VERSION 5.8 ;
BUSBITCHARS "[]" ;
DIVIDERCHAR "/" ;
UNITS
    DATABASE MICRONS 1000 ;
END UNITS

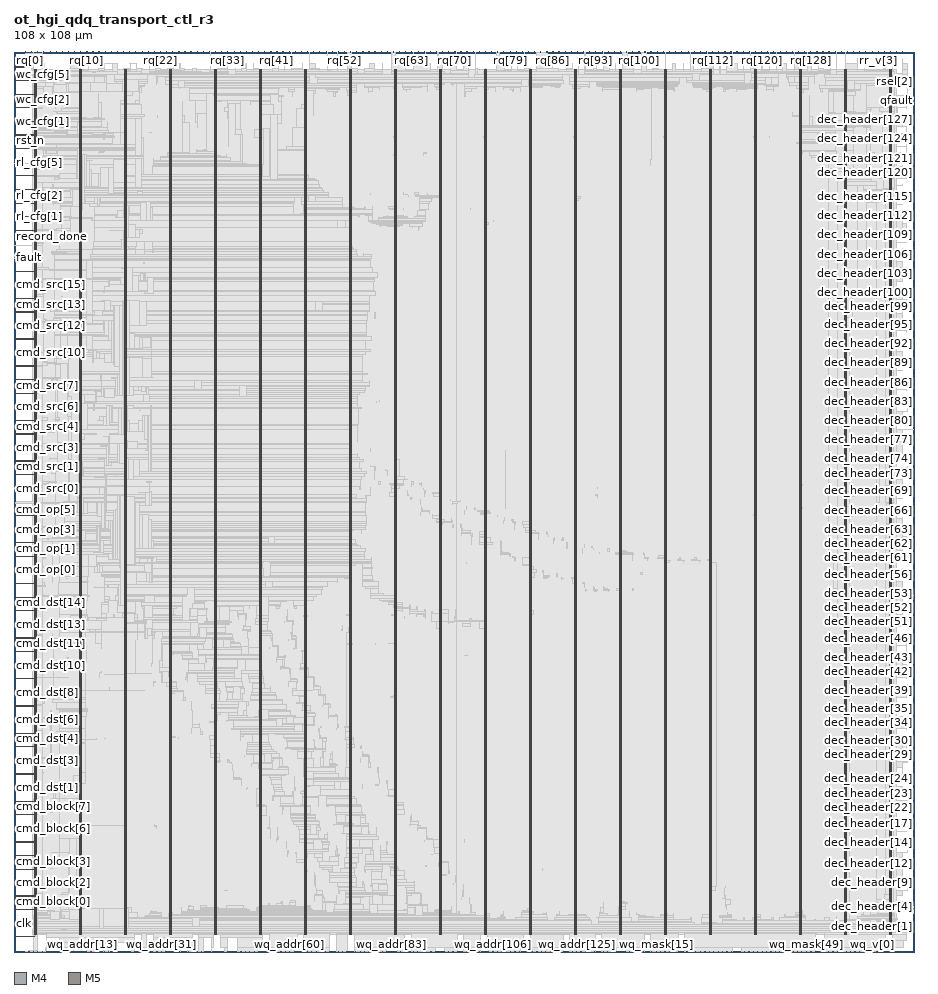
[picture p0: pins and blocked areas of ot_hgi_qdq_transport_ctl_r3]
MACRO ot_hgi_qdq_transport_ctl_r3
  FOREIGN ot_hgi_qdq_transport_ctl_r3 0 0 ;
  CLASS BLOCK ;
  SIZE 108 BY 108 ;
  PIN beat_done
    DIRECTION OUTPUT ;
    USE SIGNAL ;
    PORT
      LAYER M4 ;
        RECT  0 1.824 0.084 1.848 ;
    END
    PORT
      LAYER M4 ;
        RECT  0.06 1.824 2.408 1.848 ;
    END
  END beat_done
  PIN clk
    DIRECTION INPUT ;
    USE SIGNAL ;
    PORT
      LAYER M4 ;
        RECT  0 3.456 0.084 3.48 ;
    END
    PORT
      LAYER M4 ;
        RECT  0.06 3.456 0.227 3.48 ;
    END
  END clk
  PIN cmd_block[0]
    DIRECTION INPUT ;
    USE SIGNAL ;
    PORT
      LAYER M4 ;
        RECT  0 5.088 0.084 5.112 ;
    END
    PORT
      LAYER M4 ;
        RECT  0.06 5.088 2.408 5.112 ;
    END
  END cmd_block[0]
  PIN cmd_block[1]
    DIRECTION INPUT ;
    USE SIGNAL ;
    PORT
      LAYER M4 ;
        RECT  0 6.72 0.084 6.744 ;
    END
    PORT
      LAYER M4 ;
        RECT  0.06 6.72 2.408 6.744 ;
    END
  END cmd_block[1]
  PIN cmd_block[2]
    DIRECTION INPUT ;
    USE SIGNAL ;
    PORT
      LAYER M4 ;
        RECT  0 8.304 0.084 8.328 ;
    END
    PORT
      LAYER M4 ;
        RECT  0.06 8.304 2.408 8.328 ;
    END
  END cmd_block[2]
  PIN cmd_block[3]
    DIRECTION INPUT ;
    USE SIGNAL ;
    PORT
      LAYER M4 ;
        RECT  0 9.936 0.084 9.96 ;
    END
    PORT
      LAYER M4 ;
        RECT  0.06 9.936 2.408 9.96 ;
    END
  END cmd_block[3]
  PIN cmd_block[4]
    DIRECTION INPUT ;
    USE SIGNAL ;
    PORT
      LAYER M4 ;
        RECT  0 11.568 0.084 11.592 ;
    END
    PORT
      LAYER M4 ;
        RECT  0.06 11.568 2.408 11.592 ;
    END
  END cmd_block[4]
  PIN cmd_block[5]
    DIRECTION INPUT ;
    USE SIGNAL ;
    PORT
      LAYER M4 ;
        RECT  0 13.2 0.084 13.224 ;
    END
    PORT
      LAYER M4 ;
        RECT  0.06 13.2 2.408 13.224 ;
    END
  END cmd_block[5]
  PIN cmd_block[6]
    DIRECTION INPUT ;
    USE SIGNAL ;
    PORT
      LAYER M4 ;
        RECT  0 14.832 0.084 14.856 ;
    END
    PORT
      LAYER M4 ;
        RECT  0.06 14.832 2.408 14.856 ;
    END
  END cmd_block[6]
  PIN cmd_block[7]
    DIRECTION INPUT ;
    USE SIGNAL ;
    PORT
      LAYER M4 ;
        RECT  0 16.464 0.084 16.488 ;
    END
    PORT
      LAYER M4 ;
        RECT  0.06 16.464 2.408 16.488 ;
    END
  END cmd_block[7]
  PIN cmd_dst[0]
    DIRECTION INPUT ;
    USE SIGNAL ;
    PORT
      LAYER M4 ;
        RECT  0 18.096 0.084 18.12 ;
    END
    PORT
      LAYER M4 ;
        RECT  0.06 18.096 2.408 18.12 ;
    END
  END cmd_dst[0]
  PIN cmd_dst[10]
    DIRECTION INPUT ;
    USE SIGNAL ;
    PORT
      LAYER M4 ;
        RECT  0 34.416 0.084 34.44 ;
    END
    PORT
      LAYER M4 ;
        RECT  0.06 34.416 2.408 34.44 ;
    END
  END cmd_dst[10]
  PIN cmd_dst[11]
    DIRECTION INPUT ;
    USE SIGNAL ;
    PORT
      LAYER M4 ;
        RECT  0 36.048 0.084 36.072 ;
    END
    PORT
      LAYER M4 ;
        RECT  0.06 36.048 2.408 36.072 ;
    END
  END cmd_dst[11]
  PIN cmd_dst[12]
    DIRECTION INPUT ;
    USE SIGNAL ;
    PORT
      LAYER M4 ;
        RECT  0 37.68 0.084 37.704 ;
    END
    PORT
      LAYER M4 ;
        RECT  0.06 37.68 2.408 37.704 ;
    END
  END cmd_dst[12]
  PIN cmd_dst[13]
    DIRECTION INPUT ;
    USE SIGNAL ;
    PORT
      LAYER M4 ;
        RECT  0 39.312 0.084 39.336 ;
    END
    PORT
      LAYER M4 ;
        RECT  0.06 39.312 2.408 39.336 ;
    END
  END cmd_dst[13]
  PIN cmd_dst[14]
    DIRECTION INPUT ;
    USE SIGNAL ;
    PORT
      LAYER M4 ;
        RECT  0 40.944 0.084 40.968 ;
    END
    PORT
      LAYER M4 ;
        RECT  0.06 40.944 2.408 40.968 ;
    END
  END cmd_dst[14]
  PIN cmd_dst[15]
    DIRECTION INPUT ;
    USE SIGNAL ;
    PORT
      LAYER M4 ;
        RECT  0 42.576 0.084 42.6 ;
    END
    PORT
      LAYER M4 ;
        RECT  0.06 42.576 2.408 42.6 ;
    END
  END cmd_dst[15]
  PIN cmd_dst[1]
    DIRECTION INPUT ;
    USE SIGNAL ;
    PORT
      LAYER M4 ;
        RECT  0 19.728 0.084 19.752 ;
    END
    PORT
      LAYER M4 ;
        RECT  0.06 19.728 2.408 19.752 ;
    END
  END cmd_dst[1]
  PIN cmd_dst[2]
    DIRECTION INPUT ;
    USE SIGNAL ;
    PORT
      LAYER M4 ;
        RECT  0 21.36 0.084 21.384 ;
    END
    PORT
      LAYER M4 ;
        RECT  0.06 21.36 2.408 21.384 ;
    END
  END cmd_dst[2]
  PIN cmd_dst[3]
    DIRECTION INPUT ;
    USE SIGNAL ;
    PORT
      LAYER M4 ;
        RECT  0 22.992 0.084 23.016 ;
    END
    PORT
      LAYER M4 ;
        RECT  0.06 22.992 2.408 23.016 ;
    END
  END cmd_dst[3]
  PIN cmd_dst[4]
    DIRECTION INPUT ;
    USE SIGNAL ;
    PORT
      LAYER M4 ;
        RECT  0 24.624 0.084 24.648 ;
    END
    PORT
      LAYER M4 ;
        RECT  0.06 24.624 2.408 24.648 ;
    END
  END cmd_dst[4]
  PIN cmd_dst[5]
    DIRECTION INPUT ;
    USE SIGNAL ;
    PORT
      LAYER M4 ;
        RECT  0 26.256 0.084 26.28 ;
    END
    PORT
      LAYER M4 ;
        RECT  0.06 26.256 2.408 26.28 ;
    END
  END cmd_dst[5]
  PIN cmd_dst[6]
    DIRECTION INPUT ;
    USE SIGNAL ;
    PORT
      LAYER M4 ;
        RECT  0 27.888 0.084 27.912 ;
    END
    PORT
      LAYER M4 ;
        RECT  0.06 27.888 2.408 27.912 ;
    END
  END cmd_dst[6]
  PIN cmd_dst[7]
    DIRECTION INPUT ;
    USE SIGNAL ;
    PORT
      LAYER M4 ;
        RECT  0 29.52 0.084 29.544 ;
    END
    PORT
      LAYER M4 ;
        RECT  0.06 29.52 2.408 29.544 ;
    END
  END cmd_dst[7]
  PIN cmd_dst[8]
    DIRECTION INPUT ;
    USE SIGNAL ;
    PORT
      LAYER M4 ;
        RECT  0 31.152 0.084 31.176 ;
    END
    PORT
      LAYER M4 ;
        RECT  0.06 31.152 2.408 31.176 ;
    END
  END cmd_dst[8]
  PIN cmd_dst[9]
    DIRECTION INPUT ;
    USE SIGNAL ;
    PORT
      LAYER M4 ;
        RECT  0 32.784 0.084 32.808 ;
    END
    PORT
      LAYER M4 ;
        RECT  0.06 32.784 2.408 32.808 ;
    END
  END cmd_dst[9]
  PIN cmd_last
    DIRECTION INPUT ;
    USE SIGNAL ;
    PORT
      LAYER M4 ;
        RECT  0 44.208 0.084 44.232 ;
    END
    PORT
      LAYER M4 ;
        RECT  0.06 44.208 2.408 44.232 ;
    END
  END cmd_last
  PIN cmd_op[0]
    DIRECTION INPUT ;
    USE SIGNAL ;
    PORT
      LAYER M4 ;
        RECT  0 45.84 0.084 45.864 ;
    END
    PORT
      LAYER M4 ;
        RECT  0.06 45.84 2.408 45.864 ;
    END
  END cmd_op[0]
  PIN cmd_op[1]
    DIRECTION INPUT ;
    USE SIGNAL ;
    PORT
      LAYER M4 ;
        RECT  0 47.472 0.084 47.496 ;
    END
    PORT
      LAYER M4 ;
        RECT  0.06 47.472 2.408 47.496 ;
    END
  END cmd_op[1]
  PIN cmd_op[2]
    DIRECTION INPUT ;
    USE SIGNAL ;
    PORT
      LAYER M4 ;
        RECT  0 49.104 0.084 49.128 ;
    END
    PORT
      LAYER M4 ;
        RECT  0.06 49.104 2.408 49.128 ;
    END
  END cmd_op[2]
  PIN cmd_op[3]
    DIRECTION INPUT ;
    USE SIGNAL ;
    PORT
      LAYER M4 ;
        RECT  0 50.736 0.084 50.76 ;
    END
    PORT
      LAYER M4 ;
        RECT  0.06 50.736 2.408 50.76 ;
    END
  END cmd_op[3]
  PIN cmd_op[4]
    DIRECTION INPUT ;
    USE SIGNAL ;
    PORT
      LAYER M4 ;
        RECT  0 52.368 0.084 52.392 ;
    END
    PORT
      LAYER M4 ;
        RECT  0.06 52.368 2.408 52.392 ;
    END
  END cmd_op[4]
  PIN cmd_op[5]
    DIRECTION INPUT ;
    USE SIGNAL ;
    PORT
      LAYER M4 ;
        RECT  0 54 0.084 54.024 ;
    END
    PORT
      LAYER M4 ;
        RECT  0.06 54 0.181 54.024 ;
    END
  END cmd_op[5]
  PIN cmd_src[0]
    DIRECTION INPUT ;
    USE SIGNAL ;
    PORT
      LAYER M4 ;
        RECT  0 55.632 0.084 55.656 ;
    END
    PORT
      LAYER M4 ;
        RECT  0.06 55.632 0.097 55.656 ;
    END
  END cmd_src[0]
  PIN cmd_src[10]
    DIRECTION INPUT ;
    USE SIGNAL ;
    PORT
      LAYER M4 ;
        RECT  0 71.904 0.084 71.928 ;
    END
    PORT
      LAYER M4 ;
        RECT  0.06 71.904 2.408 71.928 ;
    END
  END cmd_src[10]
  PIN cmd_src[11]
    DIRECTION INPUT ;
    USE SIGNAL ;
    PORT
      LAYER M4 ;
        RECT  0 73.536 0.084 73.56 ;
    END
    PORT
      LAYER M4 ;
        RECT  0.06 73.536 2.408 73.56 ;
    END
  END cmd_src[11]
  PIN cmd_src[12]
    DIRECTION INPUT ;
    USE SIGNAL ;
    PORT
      LAYER M4 ;
        RECT  0 75.168 0.084 75.192 ;
    END
    PORT
      LAYER M4 ;
        RECT  0.06 75.168 2.408 75.192 ;
    END
  END cmd_src[12]
  PIN cmd_src[13]
    DIRECTION INPUT ;
    USE SIGNAL ;
    PORT
      LAYER M4 ;
        RECT  0 76.8 0.084 76.824 ;
    END
    PORT
      LAYER M4 ;
        RECT  0.06 76.8 2.408 76.824 ;
    END
  END cmd_src[13]
  PIN cmd_src[14]
    DIRECTION INPUT ;
    USE SIGNAL ;
    PORT
      LAYER M4 ;
        RECT  0 78.432 0.084 78.456 ;
    END
    PORT
      LAYER M4 ;
        RECT  0.06 78.432 2.408 78.456 ;
    END
  END cmd_src[14]
  PIN cmd_src[15]
    DIRECTION INPUT ;
    USE SIGNAL ;
    PORT
      LAYER M4 ;
        RECT  0 80.064 0.084 80.088 ;
    END
    PORT
      LAYER M4 ;
        RECT  0.06 80.064 2.408 80.088 ;
    END
  END cmd_src[15]
  PIN cmd_src[1]
    DIRECTION INPUT ;
    USE SIGNAL ;
    PORT
      LAYER M4 ;
        RECT  0 57.264 0.084 57.288 ;
    END
    PORT
      LAYER M4 ;
        RECT  0.06 57.264 2.408 57.288 ;
    END
  END cmd_src[1]
  PIN cmd_src[2]
    DIRECTION INPUT ;
    USE SIGNAL ;
    PORT
      LAYER M4 ;
        RECT  0 58.896 0.084 58.92 ;
    END
    PORT
      LAYER M4 ;
        RECT  0.06 58.896 2.408 58.92 ;
    END
  END cmd_src[2]
  PIN cmd_src[3]
    DIRECTION INPUT ;
    USE SIGNAL ;
    PORT
      LAYER M4 ;
        RECT  0 60.528 0.084 60.552 ;
    END
    PORT
      LAYER M4 ;
        RECT  0.06 60.528 2.408 60.552 ;
    END
  END cmd_src[3]
  PIN cmd_src[4]
    DIRECTION INPUT ;
    USE SIGNAL ;
    PORT
      LAYER M4 ;
        RECT  0 62.16 0.084 62.184 ;
    END
    PORT
      LAYER M4 ;
        RECT  0.06 62.16 2.408 62.184 ;
    END
  END cmd_src[4]
  PIN cmd_src[5]
    DIRECTION INPUT ;
    USE SIGNAL ;
    PORT
      LAYER M4 ;
        RECT  0 63.792 0.084 63.816 ;
    END
    PORT
      LAYER M4 ;
        RECT  0.06 63.792 2.408 63.816 ;
    END
  END cmd_src[5]
  PIN cmd_src[6]
    DIRECTION INPUT ;
    USE SIGNAL ;
    PORT
      LAYER M4 ;
        RECT  0 65.424 0.084 65.448 ;
    END
    PORT
      LAYER M4 ;
        RECT  0.06 65.424 2.408 65.448 ;
    END
  END cmd_src[6]
  PIN cmd_src[7]
    DIRECTION INPUT ;
    USE SIGNAL ;
    PORT
      LAYER M4 ;
        RECT  0 67.056 0.084 67.08 ;
    END
    PORT
      LAYER M4 ;
        RECT  0.06 67.056 2.408 67.08 ;
    END
  END cmd_src[7]
  PIN cmd_src[8]
    DIRECTION INPUT ;
    USE SIGNAL ;
    PORT
      LAYER M4 ;
        RECT  0 68.688 0.084 68.712 ;
    END
    PORT
      LAYER M4 ;
        RECT  0.06 68.688 2.408 68.712 ;
    END
  END cmd_src[8]
  PIN cmd_src[9]
    DIRECTION INPUT ;
    USE SIGNAL ;
    PORT
      LAYER M4 ;
        RECT  0 70.32 0.084 70.344 ;
    END
    PORT
      LAYER M4 ;
        RECT  0.06 70.32 2.408 70.344 ;
    END
  END cmd_src[9]
  PIN cmd_v
    DIRECTION INPUT ;
    USE SIGNAL ;
    PORT
      LAYER M4 ;
        RECT  0 81.696 0.084 81.72 ;
    END
    PORT
      LAYER M4 ;
        RECT  0.06 81.696 2.408 81.72 ;
    END
  END cmd_v
  PIN dec_header[0]
    DIRECTION OUTPUT ;
    USE SIGNAL ;
    PORT
      LAYER M4 ;
        RECT  107.916 1.392 108 1.416 ;
    END
  END dec_header[0]
  PIN dec_header[100]
    DIRECTION OUTPUT ;
    USE SIGNAL ;
    PORT
      LAYER M4 ;
        RECT  107.916 78.192 108 78.216 ;
    END
  END dec_header[100]
  PIN dec_header[101]
    DIRECTION OUTPUT ;
    USE SIGNAL ;
    PORT
      LAYER M4 ;
        RECT  107.916 78.96 108 78.984 ;
    END
  END dec_header[101]
  PIN dec_header[102]
    DIRECTION OUTPUT ;
    USE SIGNAL ;
    PORT
      LAYER M4 ;
        RECT  107.916 79.728 108 79.752 ;
    END
  END dec_header[102]
  PIN dec_header[103]
    DIRECTION OUTPUT ;
    USE SIGNAL ;
    PORT
      LAYER M4 ;
        RECT  107.916 80.496 108 80.52 ;
    END
  END dec_header[103]
  PIN dec_header[104]
    DIRECTION OUTPUT ;
    USE SIGNAL ;
    PORT
      LAYER M4 ;
        RECT  107.916 81.264 108 81.288 ;
    END
  END dec_header[104]
  PIN dec_header[105]
    DIRECTION OUTPUT ;
    USE SIGNAL ;
    PORT
      LAYER M4 ;
        RECT  107.916 82.032 108 82.056 ;
    END
  END dec_header[105]
  PIN dec_header[106]
    DIRECTION OUTPUT ;
    USE SIGNAL ;
    PORT
      LAYER M4 ;
        RECT  107.916 82.8 108 82.824 ;
    END
  END dec_header[106]
  PIN dec_header[107]
    DIRECTION OUTPUT ;
    USE SIGNAL ;
    PORT
      LAYER M4 ;
        RECT  107.916 83.568 108 83.592 ;
    END
  END dec_header[107]
  PIN dec_header[108]
    DIRECTION OUTPUT ;
    USE SIGNAL ;
    PORT
      LAYER M4 ;
        RECT  107.916 84.336 108 84.36 ;
    END
  END dec_header[108]
  PIN dec_header[109]
    DIRECTION OUTPUT ;
    USE SIGNAL ;
    PORT
      LAYER M4 ;
        RECT  107.916 85.104 108 85.128 ;
    END
  END dec_header[109]
  PIN dec_header[10]
    DIRECTION OUTPUT ;
    USE SIGNAL ;
    PORT
      LAYER M4 ;
        RECT  107.916 9.072 108 9.096 ;
    END
  END dec_header[10]
  PIN dec_header[110]
    DIRECTION OUTPUT ;
    USE SIGNAL ;
    PORT
      LAYER M4 ;
        RECT  107.916 85.872 108 85.896 ;
    END
  END dec_header[110]
  PIN dec_header[111]
    DIRECTION OUTPUT ;
    USE SIGNAL ;
    PORT
      LAYER M4 ;
        RECT  107.916 86.64 108 86.664 ;
    END
  END dec_header[111]
  PIN dec_header[112]
    DIRECTION OUTPUT ;
    USE SIGNAL ;
    PORT
      LAYER M4 ;
        RECT  107.916 87.408 108 87.432 ;
    END
  END dec_header[112]
  PIN dec_header[113]
    DIRECTION OUTPUT ;
    USE SIGNAL ;
    PORT
      LAYER M4 ;
        RECT  107.916 88.176 108 88.2 ;
    END
  END dec_header[113]
  PIN dec_header[114]
    DIRECTION OUTPUT ;
    USE SIGNAL ;
    PORT
      LAYER M4 ;
        RECT  107.916 88.944 108 88.968 ;
    END
  END dec_header[114]
  PIN dec_header[115]
    DIRECTION OUTPUT ;
    USE SIGNAL ;
    PORT
      LAYER M4 ;
        RECT  107.916 89.712 108 89.736 ;
    END
  END dec_header[115]
  PIN dec_header[116]
    DIRECTION OUTPUT ;
    USE SIGNAL ;
    PORT
      LAYER M4 ;
        RECT  107.916 90.48 108 90.504 ;
    END
  END dec_header[116]
  PIN dec_header[117]
    DIRECTION OUTPUT ;
    USE SIGNAL ;
    PORT
      LAYER M4 ;
        RECT  107.916 91.248 108 91.272 ;
    END
  END dec_header[117]
  PIN dec_header[118]
    DIRECTION OUTPUT ;
    USE SIGNAL ;
    PORT
      LAYER M4 ;
        RECT  107.916 92.016 108 92.04 ;
    END
  END dec_header[118]
  PIN dec_header[119]
    DIRECTION OUTPUT ;
    USE SIGNAL ;
    PORT
      LAYER M4 ;
        RECT  107.916 92.784 108 92.808 ;
    END
  END dec_header[119]
  PIN dec_header[11]
    DIRECTION OUTPUT ;
    USE SIGNAL ;
    PORT
      LAYER M4 ;
        RECT  107.916 9.84 108 9.864 ;
    END
  END dec_header[11]
  PIN dec_header[120]
    DIRECTION OUTPUT ;
    USE SIGNAL ;
    PORT
      LAYER M4 ;
        RECT  107.916 93.552 108 93.576 ;
    END
  END dec_header[120]
  PIN dec_header[121]
    DIRECTION OUTPUT ;
    USE SIGNAL ;
    PORT
      LAYER M4 ;
        RECT  107.916 94.32 108 94.344 ;
    END
  END dec_header[121]
  PIN dec_header[122]
    DIRECTION OUTPUT ;
    USE SIGNAL ;
    PORT
      LAYER M4 ;
        RECT  107.916 95.088 108 95.112 ;
    END
  END dec_header[122]
  PIN dec_header[123]
    DIRECTION OUTPUT ;
    USE SIGNAL ;
    PORT
      LAYER M4 ;
        RECT  107.916 95.856 108 95.88 ;
    END
  END dec_header[123]
  PIN dec_header[124]
    DIRECTION OUTPUT ;
    USE SIGNAL ;
    PORT
      LAYER M4 ;
        RECT  107.916 96.624 108 96.648 ;
    END
  END dec_header[124]
  PIN dec_header[125]
    DIRECTION OUTPUT ;
    USE SIGNAL ;
    PORT
      LAYER M4 ;
        RECT  107.916 97.392 108 97.416 ;
    END
  END dec_header[125]
  PIN dec_header[126]
    DIRECTION OUTPUT ;
    USE SIGNAL ;
    PORT
      LAYER M4 ;
        RECT  107.916 98.16 108 98.184 ;
    END
  END dec_header[126]
  PIN dec_header[127]
    DIRECTION OUTPUT ;
    USE SIGNAL ;
    PORT
      LAYER M4 ;
        RECT  107.916 98.928 108 98.952 ;
    END
  END dec_header[127]
  PIN dec_header[12]
    DIRECTION OUTPUT ;
    USE SIGNAL ;
    PORT
      LAYER M4 ;
        RECT  107.916 10.608 108 10.632 ;
    END
  END dec_header[12]
  PIN dec_header[13]
    DIRECTION OUTPUT ;
    USE SIGNAL ;
    PORT
      LAYER M4 ;
        RECT  107.916 11.376 108 11.4 ;
    END
  END dec_header[13]
  PIN dec_header[14]
    DIRECTION OUTPUT ;
    USE SIGNAL ;
    PORT
      LAYER M4 ;
        RECT  107.916 12.144 108 12.168 ;
    END
  END dec_header[14]
  PIN dec_header[15]
    DIRECTION OUTPUT ;
    USE SIGNAL ;
    PORT
      LAYER M4 ;
        RECT  107.916 12.912 108 12.936 ;
    END
  END dec_header[15]
  PIN dec_header[16]
    DIRECTION OUTPUT ;
    USE SIGNAL ;
    PORT
      LAYER M4 ;
        RECT  107.916 13.68 108 13.704 ;
    END
  END dec_header[16]
  PIN dec_header[17]
    DIRECTION OUTPUT ;
    USE SIGNAL ;
    PORT
      LAYER M4 ;
        RECT  107.916 14.448 108 14.472 ;
    END
  END dec_header[17]
  PIN dec_header[18]
    DIRECTION OUTPUT ;
    USE SIGNAL ;
    PORT
      LAYER M4 ;
        RECT  107.916 15.216 108 15.24 ;
    END
  END dec_header[18]
  PIN dec_header[19]
    DIRECTION OUTPUT ;
    USE SIGNAL ;
    PORT
      LAYER M4 ;
        RECT  107.916 15.984 108 16.008 ;
    END
  END dec_header[19]
  PIN dec_header[1]
    DIRECTION OUTPUT ;
    USE SIGNAL ;
    PORT
      LAYER M4 ;
        RECT  107.916 2.16 108 2.184 ;
    END
  END dec_header[1]
  PIN dec_header[20]
    DIRECTION OUTPUT ;
    USE SIGNAL ;
    PORT
      LAYER M4 ;
        RECT  107.916 16.752 108 16.776 ;
    END
  END dec_header[20]
  PIN dec_header[21]
    DIRECTION OUTPUT ;
    USE SIGNAL ;
    PORT
      LAYER M4 ;
        RECT  107.916 17.52 108 17.544 ;
    END
  END dec_header[21]
  PIN dec_header[22]
    DIRECTION OUTPUT ;
    USE SIGNAL ;
    PORT
      LAYER M4 ;
        RECT  107.916 18.288 108 18.312 ;
    END
  END dec_header[22]
  PIN dec_header[23]
    DIRECTION OUTPUT ;
    USE SIGNAL ;
    PORT
      LAYER M4 ;
        RECT  107.916 19.056 108 19.08 ;
    END
  END dec_header[23]
  PIN dec_header[24]
    DIRECTION OUTPUT ;
    USE SIGNAL ;
    PORT
      LAYER M4 ;
        RECT  107.916 19.824 108 19.848 ;
    END
  END dec_header[24]
  PIN dec_header[25]
    DIRECTION OUTPUT ;
    USE SIGNAL ;
    PORT
      LAYER M4 ;
        RECT  107.916 20.592 108 20.616 ;
    END
  END dec_header[25]
  PIN dec_header[26]
    DIRECTION OUTPUT ;
    USE SIGNAL ;
    PORT
      LAYER M4 ;
        RECT  107.916 21.36 108 21.384 ;
    END
  END dec_header[26]
  PIN dec_header[27]
    DIRECTION OUTPUT ;
    USE SIGNAL ;
    PORT
      LAYER M4 ;
        RECT  107.916 22.128 108 22.152 ;
    END
  END dec_header[27]
  PIN dec_header[28]
    DIRECTION OUTPUT ;
    USE SIGNAL ;
    PORT
      LAYER M4 ;
        RECT  107.916 22.896 108 22.92 ;
    END
  END dec_header[28]
  PIN dec_header[29]
    DIRECTION OUTPUT ;
    USE SIGNAL ;
    PORT
      LAYER M4 ;
        RECT  107.916 23.664 108 23.688 ;
    END
  END dec_header[29]
  PIN dec_header[2]
    DIRECTION OUTPUT ;
    USE SIGNAL ;
    PORT
      LAYER M4 ;
        RECT  107.916 2.928 108 2.952 ;
    END
  END dec_header[2]
  PIN dec_header[30]
    DIRECTION OUTPUT ;
    USE SIGNAL ;
    PORT
      LAYER M4 ;
        RECT  107.916 24.432 108 24.456 ;
    END
  END dec_header[30]
  PIN dec_header[31]
    DIRECTION OUTPUT ;
    USE SIGNAL ;
    PORT
      LAYER M4 ;
        RECT  107.916 25.2 108 25.224 ;
    END
  END dec_header[31]
  PIN dec_header[32]
    DIRECTION OUTPUT ;
    USE SIGNAL ;
    PORT
      LAYER M4 ;
        RECT  107.916 25.968 108 25.992 ;
    END
  END dec_header[32]
  PIN dec_header[33]
    DIRECTION OUTPUT ;
    USE SIGNAL ;
    PORT
      LAYER M4 ;
        RECT  107.916 26.736 108 26.76 ;
    END
  END dec_header[33]
  PIN dec_header[34]
    DIRECTION OUTPUT ;
    USE SIGNAL ;
    PORT
      LAYER M4 ;
        RECT  107.916 27.504 108 27.528 ;
    END
  END dec_header[34]
  PIN dec_header[35]
    DIRECTION OUTPUT ;
    USE SIGNAL ;
    PORT
      LAYER M4 ;
        RECT  107.916 28.272 108 28.296 ;
    END
  END dec_header[35]
  PIN dec_header[36]
    DIRECTION OUTPUT ;
    USE SIGNAL ;
    PORT
      LAYER M4 ;
        RECT  107.916 29.04 108 29.064 ;
    END
  END dec_header[36]
  PIN dec_header[37]
    DIRECTION OUTPUT ;
    USE SIGNAL ;
    PORT
      LAYER M4 ;
        RECT  107.916 29.808 108 29.832 ;
    END
  END dec_header[37]
  PIN dec_header[38]
    DIRECTION OUTPUT ;
    USE SIGNAL ;
    PORT
      LAYER M4 ;
        RECT  107.916 30.576 108 30.6 ;
    END
  END dec_header[38]
  PIN dec_header[39]
    DIRECTION OUTPUT ;
    USE SIGNAL ;
    PORT
      LAYER M4 ;
        RECT  107.916 31.344 108 31.368 ;
    END
  END dec_header[39]
  PIN dec_header[3]
    DIRECTION OUTPUT ;
    USE SIGNAL ;
    PORT
      LAYER M4 ;
        RECT  107.916 3.696 108 3.72 ;
    END
  END dec_header[3]
  PIN dec_header[40]
    DIRECTION OUTPUT ;
    USE SIGNAL ;
    PORT
      LAYER M4 ;
        RECT  107.916 32.112 108 32.136 ;
    END
  END dec_header[40]
  PIN dec_header[41]
    DIRECTION OUTPUT ;
    USE SIGNAL ;
    PORT
      LAYER M4 ;
        RECT  107.916 32.88 108 32.904 ;
    END
  END dec_header[41]
  PIN dec_header[42]
    DIRECTION OUTPUT ;
    USE SIGNAL ;
    PORT
      LAYER M4 ;
        RECT  107.916 33.648 108 33.672 ;
    END
  END dec_header[42]
  PIN dec_header[43]
    DIRECTION OUTPUT ;
    USE SIGNAL ;
    PORT
      LAYER M4 ;
        RECT  107.916 34.416 108 34.44 ;
    END
  END dec_header[43]
  PIN dec_header[44]
    DIRECTION OUTPUT ;
    USE SIGNAL ;
    PORT
      LAYER M4 ;
        RECT  107.916 35.184 108 35.208 ;
    END
  END dec_header[44]
  PIN dec_header[45]
    DIRECTION OUTPUT ;
    USE SIGNAL ;
    PORT
      LAYER M4 ;
        RECT  107.916 35.952 108 35.976 ;
    END
  END dec_header[45]
  PIN dec_header[46]
    DIRECTION OUTPUT ;
    USE SIGNAL ;
    PORT
      LAYER M4 ;
        RECT  107.916 36.72 108 36.744 ;
    END
  END dec_header[46]
  PIN dec_header[47]
    DIRECTION OUTPUT ;
    USE SIGNAL ;
    PORT
      LAYER M4 ;
        RECT  107.916 37.488 108 37.512 ;
    END
  END dec_header[47]
  PIN dec_header[48]
    DIRECTION OUTPUT ;
    USE SIGNAL ;
    PORT
      LAYER M4 ;
        RECT  107.916 38.256 108 38.28 ;
    END
  END dec_header[48]
  PIN dec_header[49]
    DIRECTION OUTPUT ;
    USE SIGNAL ;
    PORT
      LAYER M4 ;
        RECT  107.916 39.024 108 39.048 ;
    END
  END dec_header[49]
  PIN dec_header[4]
    DIRECTION OUTPUT ;
    USE SIGNAL ;
    PORT
      LAYER M4 ;
        RECT  107.916 4.464 108 4.488 ;
    END
  END dec_header[4]
  PIN dec_header[50]
    DIRECTION OUTPUT ;
    USE SIGNAL ;
    PORT
      LAYER M4 ;
        RECT  107.916 39.792 108 39.816 ;
    END
  END dec_header[50]
  PIN dec_header[51]
    DIRECTION OUTPUT ;
    USE SIGNAL ;
    PORT
      LAYER M4 ;
        RECT  107.916 40.56 108 40.584 ;
    END
  END dec_header[51]
  PIN dec_header[52]
    DIRECTION OUTPUT ;
    USE SIGNAL ;
    PORT
      LAYER M4 ;
        RECT  107.916 41.328 108 41.352 ;
    END
  END dec_header[52]
  PIN dec_header[53]
    DIRECTION OUTPUT ;
    USE SIGNAL ;
    PORT
      LAYER M4 ;
        RECT  107.916 42.096 108 42.12 ;
    END
  END dec_header[53]
  PIN dec_header[54]
    DIRECTION OUTPUT ;
    USE SIGNAL ;
    PORT
      LAYER M4 ;
        RECT  107.916 42.864 108 42.888 ;
    END
  END dec_header[54]
  PIN dec_header[55]
    DIRECTION OUTPUT ;
    USE SIGNAL ;
    PORT
      LAYER M4 ;
        RECT  107.916 43.632 108 43.656 ;
    END
  END dec_header[55]
  PIN dec_header[56]
    DIRECTION OUTPUT ;
    USE SIGNAL ;
    PORT
      LAYER M4 ;
        RECT  107.916 44.4 108 44.424 ;
    END
  END dec_header[56]
  PIN dec_header[57]
    DIRECTION OUTPUT ;
    USE SIGNAL ;
    PORT
      LAYER M4 ;
        RECT  107.916 45.168 108 45.192 ;
    END
  END dec_header[57]
  PIN dec_header[58]
    DIRECTION OUTPUT ;
    USE SIGNAL ;
    PORT
      LAYER M4 ;
        RECT  107.916 45.936 108 45.96 ;
    END
  END dec_header[58]
  PIN dec_header[59]
    DIRECTION OUTPUT ;
    USE SIGNAL ;
    PORT
      LAYER M4 ;
        RECT  107.916 46.704 108 46.728 ;
    END
  END dec_header[59]
  PIN dec_header[5]
    DIRECTION OUTPUT ;
    USE SIGNAL ;
    PORT
      LAYER M4 ;
        RECT  107.916 5.232 108 5.256 ;
    END
  END dec_header[5]
  PIN dec_header[60]
    DIRECTION OUTPUT ;
    USE SIGNAL ;
    PORT
      LAYER M4 ;
        RECT  107.916 47.472 108 47.496 ;
    END
  END dec_header[60]
  PIN dec_header[61]
    DIRECTION OUTPUT ;
    USE SIGNAL ;
    PORT
      LAYER M4 ;
        RECT  107.916 48.24 108 48.264 ;
    END
  END dec_header[61]
  PIN dec_header[62]
    DIRECTION OUTPUT ;
    USE SIGNAL ;
    PORT
      LAYER M4 ;
        RECT  107.916 49.008 108 49.032 ;
    END
  END dec_header[62]
  PIN dec_header[63]
    DIRECTION OUTPUT ;
    USE SIGNAL ;
    PORT
      LAYER M4 ;
        RECT  107.916 49.776 108 49.8 ;
    END
  END dec_header[63]
  PIN dec_header[64]
    DIRECTION OUTPUT ;
    USE SIGNAL ;
    PORT
      LAYER M4 ;
        RECT  107.916 50.544 108 50.568 ;
    END
  END dec_header[64]
  PIN dec_header[65]
    DIRECTION OUTPUT ;
    USE SIGNAL ;
    PORT
      LAYER M4 ;
        RECT  107.916 51.312 108 51.336 ;
    END
  END dec_header[65]
  PIN dec_header[66]
    DIRECTION OUTPUT ;
    USE SIGNAL ;
    PORT
      LAYER M4 ;
        RECT  107.916 52.08 108 52.104 ;
    END
  END dec_header[66]
  PIN dec_header[67]
    DIRECTION OUTPUT ;
    USE SIGNAL ;
    PORT
      LAYER M4 ;
        RECT  107.916 52.848 108 52.872 ;
    END
  END dec_header[67]
  PIN dec_header[68]
    DIRECTION OUTPUT ;
    USE SIGNAL ;
    PORT
      LAYER M4 ;
        RECT  107.916 53.616 108 53.64 ;
    END
  END dec_header[68]
  PIN dec_header[69]
    DIRECTION OUTPUT ;
    USE SIGNAL ;
    PORT
      LAYER M4 ;
        RECT  107.916 54.384 108 54.408 ;
    END
  END dec_header[69]
  PIN dec_header[6]
    DIRECTION OUTPUT ;
    USE SIGNAL ;
    PORT
      LAYER M4 ;
        RECT  107.916 6 108 6.024 ;
    END
  END dec_header[6]
  PIN dec_header[70]
    DIRECTION OUTPUT ;
    USE SIGNAL ;
    PORT
      LAYER M4 ;
        RECT  107.916 55.152 108 55.176 ;
    END
  END dec_header[70]
  PIN dec_header[71]
    DIRECTION OUTPUT ;
    USE SIGNAL ;
    PORT
      LAYER M4 ;
        RECT  107.916 55.92 108 55.944 ;
    END
  END dec_header[71]
  PIN dec_header[72]
    DIRECTION OUTPUT ;
    USE SIGNAL ;
    PORT
      LAYER M4 ;
        RECT  107.916 56.688 108 56.712 ;
    END
  END dec_header[72]
  PIN dec_header[73]
    DIRECTION OUTPUT ;
    USE SIGNAL ;
    PORT
      LAYER M4 ;
        RECT  107.916 57.456 108 57.48 ;
    END
  END dec_header[73]
  PIN dec_header[74]
    DIRECTION OUTPUT ;
    USE SIGNAL ;
    PORT
      LAYER M4 ;
        RECT  107.916 58.224 108 58.248 ;
    END
  END dec_header[74]
  PIN dec_header[75]
    DIRECTION OUTPUT ;
    USE SIGNAL ;
    PORT
      LAYER M4 ;
        RECT  107.916 58.992 108 59.016 ;
    END
  END dec_header[75]
  PIN dec_header[76]
    DIRECTION OUTPUT ;
    USE SIGNAL ;
    PORT
      LAYER M4 ;
        RECT  107.916 59.76 108 59.784 ;
    END
  END dec_header[76]
  PIN dec_header[77]
    DIRECTION OUTPUT ;
    USE SIGNAL ;
    PORT
      LAYER M4 ;
        RECT  107.916 60.528 108 60.552 ;
    END
  END dec_header[77]
  PIN dec_header[78]
    DIRECTION OUTPUT ;
    USE SIGNAL ;
    PORT
      LAYER M4 ;
        RECT  107.916 61.296 108 61.32 ;
    END
  END dec_header[78]
  PIN dec_header[79]
    DIRECTION OUTPUT ;
    USE SIGNAL ;
    PORT
      LAYER M4 ;
        RECT  107.916 62.064 108 62.088 ;
    END
  END dec_header[79]
  PIN dec_header[7]
    DIRECTION OUTPUT ;
    USE SIGNAL ;
    PORT
      LAYER M4 ;
        RECT  107.916 6.768 108 6.792 ;
    END
  END dec_header[7]
  PIN dec_header[80]
    DIRECTION OUTPUT ;
    USE SIGNAL ;
    PORT
      LAYER M4 ;
        RECT  107.916 62.832 108 62.856 ;
    END
  END dec_header[80]
  PIN dec_header[81]
    DIRECTION OUTPUT ;
    USE SIGNAL ;
    PORT
      LAYER M4 ;
        RECT  107.916 63.6 108 63.624 ;
    END
  END dec_header[81]
  PIN dec_header[82]
    DIRECTION OUTPUT ;
    USE SIGNAL ;
    PORT
      LAYER M4 ;
        RECT  107.916 64.368 108 64.392 ;
    END
  END dec_header[82]
  PIN dec_header[83]
    DIRECTION OUTPUT ;
    USE SIGNAL ;
    PORT
      LAYER M4 ;
        RECT  107.916 65.136 108 65.16 ;
    END
  END dec_header[83]
  PIN dec_header[84]
    DIRECTION OUTPUT ;
    USE SIGNAL ;
    PORT
      LAYER M4 ;
        RECT  107.916 65.904 108 65.928 ;
    END
  END dec_header[84]
  PIN dec_header[85]
    DIRECTION OUTPUT ;
    USE SIGNAL ;
    PORT
      LAYER M4 ;
        RECT  107.916 66.672 108 66.696 ;
    END
  END dec_header[85]
  PIN dec_header[86]
    DIRECTION OUTPUT ;
    USE SIGNAL ;
    PORT
      LAYER M4 ;
        RECT  107.916 67.44 108 67.464 ;
    END
  END dec_header[86]
  PIN dec_header[87]
    DIRECTION OUTPUT ;
    USE SIGNAL ;
    PORT
      LAYER M4 ;
        RECT  107.916 68.208 108 68.232 ;
    END
  END dec_header[87]
  PIN dec_header[88]
    DIRECTION OUTPUT ;
    USE SIGNAL ;
    PORT
      LAYER M4 ;
        RECT  107.916 68.976 108 69 ;
    END
  END dec_header[88]
  PIN dec_header[89]
    DIRECTION OUTPUT ;
    USE SIGNAL ;
    PORT
      LAYER M4 ;
        RECT  107.916 69.744 108 69.768 ;
    END
  END dec_header[89]
  PIN dec_header[8]
    DIRECTION OUTPUT ;
    USE SIGNAL ;
    PORT
      LAYER M4 ;
        RECT  107.916 7.536 108 7.56 ;
    END
  END dec_header[8]
  PIN dec_header[90]
    DIRECTION OUTPUT ;
    USE SIGNAL ;
    PORT
      LAYER M4 ;
        RECT  107.916 70.512 108 70.536 ;
    END
  END dec_header[90]
  PIN dec_header[91]
    DIRECTION OUTPUT ;
    USE SIGNAL ;
    PORT
      LAYER M4 ;
        RECT  107.916 71.28 108 71.304 ;
    END
  END dec_header[91]
  PIN dec_header[92]
    DIRECTION OUTPUT ;
    USE SIGNAL ;
    PORT
      LAYER M4 ;
        RECT  107.916 72.048 108 72.072 ;
    END
  END dec_header[92]
  PIN dec_header[93]
    DIRECTION OUTPUT ;
    USE SIGNAL ;
    PORT
      LAYER M4 ;
        RECT  107.916 72.816 108 72.84 ;
    END
  END dec_header[93]
  PIN dec_header[94]
    DIRECTION OUTPUT ;
    USE SIGNAL ;
    PORT
      LAYER M4 ;
        RECT  107.916 73.584 108 73.608 ;
    END
  END dec_header[94]
  PIN dec_header[95]
    DIRECTION OUTPUT ;
    USE SIGNAL ;
    PORT
      LAYER M4 ;
        RECT  107.916 74.352 108 74.376 ;
    END
  END dec_header[95]
  PIN dec_header[96]
    DIRECTION OUTPUT ;
    USE SIGNAL ;
    PORT
      LAYER M4 ;
        RECT  107.916 75.12 108 75.144 ;
    END
  END dec_header[96]
  PIN dec_header[97]
    DIRECTION OUTPUT ;
    USE SIGNAL ;
    PORT
      LAYER M4 ;
        RECT  107.916 75.888 108 75.912 ;
    END
  END dec_header[97]
  PIN dec_header[98]
    DIRECTION OUTPUT ;
    USE SIGNAL ;
    PORT
      LAYER M4 ;
        RECT  107.916 76.656 108 76.68 ;
    END
  END dec_header[98]
  PIN dec_header[99]
    DIRECTION OUTPUT ;
    USE SIGNAL ;
    PORT
      LAYER M4 ;
        RECT  107.916 77.424 108 77.448 ;
    END
  END dec_header[99]
  PIN dec_header[9]
    DIRECTION OUTPUT ;
    USE SIGNAL ;
    PORT
      LAYER M4 ;
        RECT  107.916 8.304 108 8.328 ;
    END
  END dec_header[9]
  PIN dec_v
    DIRECTION OUTPUT ;
    USE SIGNAL ;
    PORT
      LAYER M4 ;
        RECT  107.916 99.696 108 99.72 ;
    END
  END dec_v
  PIN decode_fault
    DIRECTION INPUT ;
    USE SIGNAL ;
    PORT
      LAYER M4 ;
        RECT  107.916 100.464 108 100.488 ;
    END
  END decode_fault
  PIN fault
    DIRECTION OUTPUT ;
    USE SIGNAL ;
    PORT
      LAYER M4 ;
        RECT  0 83.328 0.084 83.352 ;
    END
    PORT
      LAYER M4 ;
        RECT  0.06 83.328 0.137 83.352 ;
    END
  END fault
  PIN qfault
    DIRECTION INPUT ;
    USE SIGNAL ;
    PORT
      LAYER M4 ;
        RECT  107.916 101.232 108 101.256 ;
    END
  END qfault
  PIN record_done
    DIRECTION OUTPUT ;
    USE SIGNAL ;
    PORT
      LAYER M4 ;
        RECT  0 84.96 0.084 84.984 ;
    END
    PORT
      LAYER M4 ;
        RECT  0.06 84.96 0.137 84.984 ;
    END
  END record_done
  PIN rl_cfg[0]
    DIRECTION INPUT ;
    USE SIGNAL ;
    PORT
      LAYER M4 ;
        RECT  0 86.592 0.084 86.616 ;
    END
    PORT
      LAYER M4 ;
        RECT  0.06 86.592 2.408 86.616 ;
    END
  END rl_cfg[0]
  PIN rl_cfg[1]
    DIRECTION INPUT ;
    USE SIGNAL ;
    PORT
      LAYER M4 ;
        RECT  0 88.224 0.084 88.248 ;
    END
    PORT
      LAYER M4 ;
        RECT  0.06 88.224 2.408 88.248 ;
    END
  END rl_cfg[1]
  PIN rl_cfg[2]
    DIRECTION INPUT ;
    USE SIGNAL ;
    PORT
      LAYER M4 ;
        RECT  0 89.856 0.084 89.88 ;
    END
    PORT
      LAYER M4 ;
        RECT  0.06 89.856 2.408 89.88 ;
    END
  END rl_cfg[2]
  PIN rl_cfg[3]
    DIRECTION INPUT ;
    USE SIGNAL ;
    PORT
      LAYER M4 ;
        RECT  0 91.488 0.084 91.512 ;
    END
    PORT
      LAYER M4 ;
        RECT  0.06 91.488 2.408 91.512 ;
    END
  END rl_cfg[3]
  PIN rl_cfg[4]
    DIRECTION INPUT ;
    USE SIGNAL ;
    PORT
      LAYER M4 ;
        RECT  0 93.12 0.084 93.144 ;
    END
    PORT
      LAYER M4 ;
        RECT  0.06 93.12 2.408 93.144 ;
    END
  END rl_cfg[4]
  PIN rl_cfg[5]
    DIRECTION INPUT ;
    USE SIGNAL ;
    PORT
      LAYER M4 ;
        RECT  0 94.752 0.084 94.776 ;
    END
    PORT
      LAYER M4 ;
        RECT  0.06 94.752 0.137 94.776 ;
    END
  END rl_cfg[5]
  PIN rq[0]
    DIRECTION OUTPUT ;
    USE SIGNAL ;
    PORT
      LAYER M5 ;
        RECT  1.344 107.916 1.368 108 ;
    END
  END rq[0]
  PIN rq[100]
    DIRECTION OUTPUT ;
    USE SIGNAL ;
    PORT
      LAYER M5 ;
        RECT  74.976 107.916 75 108 ;
    END
  END rq[100]
  PIN rq[101]
    DIRECTION OUTPUT ;
    USE SIGNAL ;
    PORT
      LAYER M5 ;
        RECT  75.696 107.916 75.72 108 ;
    END
  END rq[101]
  PIN rq[102]
    DIRECTION OUTPUT ;
    USE SIGNAL ;
    PORT
      LAYER M5 ;
        RECT  76.416 107.916 76.44 108 ;
    END
  END rq[102]
  PIN rq[103]
    DIRECTION OUTPUT ;
    USE SIGNAL ;
    PORT
      LAYER M5 ;
        RECT  77.184 107.916 77.208 108 ;
    END
  END rq[103]
  PIN rq[104]
    DIRECTION OUTPUT ;
    USE SIGNAL ;
    PORT
      LAYER M5 ;
        RECT  77.904 107.916 77.928 108 ;
    END
  END rq[104]
  PIN rq[105]
    DIRECTION OUTPUT ;
    USE SIGNAL ;
    PORT
      LAYER M5 ;
        RECT  78.672 107.916 78.696 108 ;
    END
  END rq[105]
  PIN rq[106]
    DIRECTION OUTPUT ;
    USE SIGNAL ;
    PORT
      LAYER M5 ;
        RECT  79.392 107.916 79.416 108 ;
    END
  END rq[106]
  PIN rq[107]
    DIRECTION OUTPUT ;
    USE SIGNAL ;
    PORT
      LAYER M5 ;
        RECT  80.112 107.916 80.136 108 ;
    END
  END rq[107]
  PIN rq[108]
    DIRECTION OUTPUT ;
    USE SIGNAL ;
    PORT
      LAYER M5 ;
        RECT  80.88 107.916 80.904 108 ;
    END
  END rq[108]
  PIN rq[109]
    DIRECTION OUTPUT ;
    USE SIGNAL ;
    PORT
      LAYER M5 ;
        RECT  81.6 107.916 81.624 108 ;
    END
  END rq[109]
  PIN rq[10]
    DIRECTION OUTPUT ;
    USE SIGNAL ;
    PORT
      LAYER M5 ;
        RECT  8.736 107.916 8.76 108 ;
    END
  END rq[10]
  PIN rq[110]
    DIRECTION OUTPUT ;
    USE SIGNAL ;
    PORT
      LAYER M5 ;
        RECT  82.32 107.916 82.344 108 ;
    END
  END rq[110]
  PIN rq[111]
    DIRECTION OUTPUT ;
    USE SIGNAL ;
    PORT
      LAYER M5 ;
        RECT  83.088 107.916 83.112 108 ;
    END
  END rq[111]
  PIN rq[112]
    DIRECTION OUTPUT ;
    USE SIGNAL ;
    PORT
      LAYER M5 ;
        RECT  83.808 107.916 83.832 108 ;
    END
  END rq[112]
  PIN rq[113]
    DIRECTION OUTPUT ;
    USE SIGNAL ;
    PORT
      LAYER M5 ;
        RECT  84.528 107.916 84.552 108 ;
    END
  END rq[113]
  PIN rq[114]
    DIRECTION OUTPUT ;
    USE SIGNAL ;
    PORT
      LAYER M5 ;
        RECT  85.296 107.916 85.32 108 ;
    END
  END rq[114]
  PIN rq[115]
    DIRECTION OUTPUT ;
    USE SIGNAL ;
    PORT
      LAYER M5 ;
        RECT  86.016 107.916 86.04 108 ;
    END
  END rq[115]
  PIN rq[116]
    DIRECTION OUTPUT ;
    USE SIGNAL ;
    PORT
      LAYER M5 ;
        RECT  86.736 107.916 86.76 108 ;
    END
  END rq[116]
  PIN rq[117]
    DIRECTION OUTPUT ;
    USE SIGNAL ;
    PORT
      LAYER M5 ;
        RECT  87.504 107.916 87.528 108 ;
    END
  END rq[117]
  PIN rq[118]
    DIRECTION OUTPUT ;
    USE SIGNAL ;
    PORT
      LAYER M5 ;
        RECT  88.224 107.916 88.248 108 ;
    END
  END rq[118]
  PIN rq[119]
    DIRECTION OUTPUT ;
    USE SIGNAL ;
    PORT
      LAYER M5 ;
        RECT  88.944 107.916 88.968 108 ;
    END
  END rq[119]
  PIN rq[11]
    DIRECTION OUTPUT ;
    USE SIGNAL ;
    PORT
      LAYER M5 ;
        RECT  9.456 107.916 9.48 108 ;
    END
  END rq[11]
  PIN rq[120]
    DIRECTION OUTPUT ;
    USE SIGNAL ;
    PORT
      LAYER M5 ;
        RECT  89.712 107.916 89.736 108 ;
    END
  END rq[120]
  PIN rq[121]
    DIRECTION OUTPUT ;
    USE SIGNAL ;
    PORT
      LAYER M5 ;
        RECT  90.432 107.916 90.456 108 ;
    END
  END rq[121]
  PIN rq[122]
    DIRECTION OUTPUT ;
    USE SIGNAL ;
    PORT
      LAYER M5 ;
        RECT  91.152 107.916 91.176 108 ;
    END
  END rq[122]
  PIN rq[123]
    DIRECTION OUTPUT ;
    USE SIGNAL ;
    PORT
      LAYER M5 ;
        RECT  91.92 107.916 91.944 108 ;
    END
  END rq[123]
  PIN rq[124]
    DIRECTION OUTPUT ;
    USE SIGNAL ;
    PORT
      LAYER M5 ;
        RECT  92.64 107.916 92.664 108 ;
    END
  END rq[124]
  PIN rq[125]
    DIRECTION OUTPUT ;
    USE SIGNAL ;
    PORT
      LAYER M5 ;
        RECT  93.36 107.916 93.384 108 ;
    END
  END rq[125]
  PIN rq[126]
    DIRECTION OUTPUT ;
    USE SIGNAL ;
    PORT
      LAYER M5 ;
        RECT  94.128 107.916 94.152 108 ;
    END
  END rq[126]
  PIN rq[127]
    DIRECTION OUTPUT ;
    USE SIGNAL ;
    PORT
      LAYER M5 ;
        RECT  94.848 107.916 94.872 108 ;
    END
  END rq[127]
  PIN rq[128]
    DIRECTION OUTPUT ;
    USE SIGNAL ;
    PORT
      LAYER M5 ;
        RECT  95.568 107.916 95.592 108 ;
    END
  END rq[128]
  PIN rq[129]
    DIRECTION OUTPUT ;
    USE SIGNAL ;
    PORT
      LAYER M5 ;
        RECT  96.336 107.916 96.36 108 ;
    END
  END rq[129]
  PIN rq[12]
    DIRECTION OUTPUT ;
    USE SIGNAL ;
    PORT
      LAYER M5 ;
        RECT  10.176 107.916 10.2 108 ;
    END
  END rq[12]
  PIN rq[130]
    DIRECTION OUTPUT ;
    USE SIGNAL ;
    PORT
      LAYER M5 ;
        RECT  97.056 107.916 97.08 108 ;
    END
  END rq[130]
  PIN rq[131]
    DIRECTION OUTPUT ;
    USE SIGNAL ;
    PORT
      LAYER M5 ;
        RECT  97.776 107.916 97.8 108 ;
    END
  END rq[131]
  PIN rq[132]
    DIRECTION OUTPUT ;
    USE SIGNAL ;
    PORT
      LAYER M5 ;
        RECT  98.544 107.916 98.568 108 ;
    END
  END rq[132]
  PIN rq[133]
    DIRECTION OUTPUT ;
    USE SIGNAL ;
    PORT
      LAYER M5 ;
        RECT  99.264 107.916 99.288 108 ;
    END
  END rq[133]
  PIN rq[134]
    DIRECTION OUTPUT ;
    USE SIGNAL ;
    PORT
      LAYER M5 ;
        RECT  99.984 107.916 100.008 108 ;
    END
  END rq[134]
  PIN rq[135]
    DIRECTION OUTPUT ;
    USE SIGNAL ;
    PORT
      LAYER M5 ;
        RECT  100.752 107.916 100.776 108 ;
    END
  END rq[135]
  PIN rq[13]
    DIRECTION OUTPUT ;
    USE SIGNAL ;
    PORT
      LAYER M5 ;
        RECT  10.944 107.916 10.968 108 ;
    END
  END rq[13]
  PIN rq[14]
    DIRECTION OUTPUT ;
    USE SIGNAL ;
    PORT
      LAYER M5 ;
        RECT  11.664 107.916 11.688 108 ;
    END
  END rq[14]
  PIN rq[15]
    DIRECTION OUTPUT ;
    USE SIGNAL ;
    PORT
      LAYER M5 ;
        RECT  12.384 107.916 12.408 108 ;
    END
  END rq[15]
  PIN rq[16]
    DIRECTION OUTPUT ;
    USE SIGNAL ;
    PORT
      LAYER M5 ;
        RECT  13.152 107.916 13.176 108 ;
    END
  END rq[16]
  PIN rq[17]
    DIRECTION OUTPUT ;
    USE SIGNAL ;
    PORT
      LAYER M5 ;
        RECT  13.872 107.916 13.896 108 ;
    END
  END rq[17]
  PIN rq[18]
    DIRECTION OUTPUT ;
    USE SIGNAL ;
    PORT
      LAYER M5 ;
        RECT  14.592 107.916 14.616 108 ;
    END
  END rq[18]
  PIN rq[19]
    DIRECTION OUTPUT ;
    USE SIGNAL ;
    PORT
      LAYER M5 ;
        RECT  15.36 107.916 15.384 108 ;
    END
  END rq[19]
  PIN rq[1]
    DIRECTION OUTPUT ;
    USE SIGNAL ;
    PORT
      LAYER M5 ;
        RECT  2.112 107.916 2.136 108 ;
    END
  END rq[1]
  PIN rq[20]
    DIRECTION OUTPUT ;
    USE SIGNAL ;
    PORT
      LAYER M5 ;
        RECT  16.08 107.916 16.104 108 ;
    END
  END rq[20]
  PIN rq[21]
    DIRECTION OUTPUT ;
    USE SIGNAL ;
    PORT
      LAYER M5 ;
        RECT  16.8 107.916 16.824 108 ;
    END
  END rq[21]
  PIN rq[22]
    DIRECTION OUTPUT ;
    USE SIGNAL ;
    PORT
      LAYER M5 ;
        RECT  17.568 107.916 17.592 108 ;
    END
  END rq[22]
  PIN rq[23]
    DIRECTION OUTPUT ;
    USE SIGNAL ;
    PORT
      LAYER M5 ;
        RECT  18.288 107.916 18.312 108 ;
    END
  END rq[23]
  PIN rq[24]
    DIRECTION OUTPUT ;
    USE SIGNAL ;
    PORT
      LAYER M5 ;
        RECT  19.008 107.916 19.032 108 ;
    END
  END rq[24]
  PIN rq[25]
    DIRECTION OUTPUT ;
    USE SIGNAL ;
    PORT
      LAYER M5 ;
        RECT  19.776 107.916 19.8 108 ;
    END
  END rq[25]
  PIN rq[26]
    DIRECTION OUTPUT ;
    USE SIGNAL ;
    PORT
      LAYER M5 ;
        RECT  20.496 107.916 20.52 108 ;
    END
  END rq[26]
  PIN rq[27]
    DIRECTION OUTPUT ;
    USE SIGNAL ;
    PORT
      LAYER M5 ;
        RECT  21.216 107.916 21.24 108 ;
    END
  END rq[27]
  PIN rq[28]
    DIRECTION OUTPUT ;
    USE SIGNAL ;
    PORT
      LAYER M5 ;
        RECT  21.984 107.916 22.008 108 ;
    END
  END rq[28]
  PIN rq[29]
    DIRECTION OUTPUT ;
    USE SIGNAL ;
    PORT
      LAYER M5 ;
        RECT  22.704 107.916 22.728 108 ;
    END
  END rq[29]
  PIN rq[2]
    DIRECTION OUTPUT ;
    USE SIGNAL ;
    PORT
      LAYER M5 ;
        RECT  2.832 107.916 2.856 108 ;
    END
  END rq[2]
  PIN rq[30]
    DIRECTION OUTPUT ;
    USE SIGNAL ;
    PORT
      LAYER M5 ;
        RECT  23.424 107.916 23.448 108 ;
    END
  END rq[30]
  PIN rq[31]
    DIRECTION OUTPUT ;
    USE SIGNAL ;
    PORT
      LAYER M5 ;
        RECT  24.192 107.916 24.216 108 ;
    END
  END rq[31]
  PIN rq[32]
    DIRECTION OUTPUT ;
    USE SIGNAL ;
    PORT
      LAYER M5 ;
        RECT  24.912 107.916 24.936 108 ;
    END
  END rq[32]
  PIN rq[33]
    DIRECTION OUTPUT ;
    USE SIGNAL ;
    PORT
      LAYER M5 ;
        RECT  25.632 107.916 25.656 108 ;
    END
  END rq[33]
  PIN rq[34]
    DIRECTION OUTPUT ;
    USE SIGNAL ;
    PORT
      LAYER M5 ;
        RECT  26.4 107.916 26.424 108 ;
    END
  END rq[34]
  PIN rq[35]
    DIRECTION OUTPUT ;
    USE SIGNAL ;
    PORT
      LAYER M5 ;
        RECT  27.12 107.916 27.144 108 ;
    END
  END rq[35]
  PIN rq[36]
    DIRECTION OUTPUT ;
    USE SIGNAL ;
    PORT
      LAYER M5 ;
        RECT  27.84 107.916 27.864 108 ;
    END
  END rq[36]
  PIN rq[37]
    DIRECTION OUTPUT ;
    USE SIGNAL ;
    PORT
      LAYER M5 ;
        RECT  28.608 107.916 28.632 108 ;
    END
  END rq[37]
  PIN rq[38]
    DIRECTION OUTPUT ;
    USE SIGNAL ;
    PORT
      LAYER M5 ;
        RECT  29.328 107.916 29.352 108 ;
    END
  END rq[38]
  PIN rq[39]
    DIRECTION OUTPUT ;
    USE SIGNAL ;
    PORT
      LAYER M5 ;
        RECT  30.048 107.916 30.072 108 ;
    END
  END rq[39]
  PIN rq[3]
    DIRECTION OUTPUT ;
    USE SIGNAL ;
    PORT
      LAYER M5 ;
        RECT  3.552 107.916 3.576 108 ;
    END
  END rq[3]
  PIN rq[40]
    DIRECTION OUTPUT ;
    USE SIGNAL ;
    PORT
      LAYER M5 ;
        RECT  30.816 107.916 30.84 108 ;
    END
  END rq[40]
  PIN rq[41]
    DIRECTION OUTPUT ;
    USE SIGNAL ;
    PORT
      LAYER M5 ;
        RECT  31.536 107.916 31.56 108 ;
    END
  END rq[41]
  PIN rq[42]
    DIRECTION OUTPUT ;
    USE SIGNAL ;
    PORT
      LAYER M5 ;
        RECT  32.256 107.916 32.28 108 ;
    END
  END rq[42]
  PIN rq[43]
    DIRECTION OUTPUT ;
    USE SIGNAL ;
    PORT
      LAYER M5 ;
        RECT  33.024 107.916 33.048 108 ;
    END
  END rq[43]
  PIN rq[44]
    DIRECTION OUTPUT ;
    USE SIGNAL ;
    PORT
      LAYER M5 ;
        RECT  33.744 107.916 33.768 108 ;
    END
  END rq[44]
  PIN rq[45]
    DIRECTION OUTPUT ;
    USE SIGNAL ;
    PORT
      LAYER M5 ;
        RECT  34.464 107.916 34.488 108 ;
    END
  END rq[45]
  PIN rq[46]
    DIRECTION OUTPUT ;
    USE SIGNAL ;
    PORT
      LAYER M5 ;
        RECT  35.232 107.916 35.256 108 ;
    END
  END rq[46]
  PIN rq[47]
    DIRECTION OUTPUT ;
    USE SIGNAL ;
    PORT
      LAYER M5 ;
        RECT  35.952 107.916 35.976 108 ;
    END
  END rq[47]
  PIN rq[48]
    DIRECTION OUTPUT ;
    USE SIGNAL ;
    PORT
      LAYER M5 ;
        RECT  36.672 107.916 36.696 108 ;
    END
  END rq[48]
  PIN rq[49]
    DIRECTION OUTPUT ;
    USE SIGNAL ;
    PORT
      LAYER M5 ;
        RECT  37.44 107.916 37.464 108 ;
    END
  END rq[49]
  PIN rq[4]
    DIRECTION OUTPUT ;
    USE SIGNAL ;
    PORT
      LAYER M5 ;
        RECT  4.32 107.916 4.344 108 ;
    END
  END rq[4]
  PIN rq[50]
    DIRECTION OUTPUT ;
    USE SIGNAL ;
    PORT
      LAYER M5 ;
        RECT  38.16 107.916 38.184 108 ;
    END
  END rq[50]
  PIN rq[51]
    DIRECTION OUTPUT ;
    USE SIGNAL ;
    PORT
      LAYER M5 ;
        RECT  38.88 107.916 38.904 108 ;
    END
  END rq[51]
  PIN rq[52]
    DIRECTION OUTPUT ;
    USE SIGNAL ;
    PORT
      LAYER M5 ;
        RECT  39.648 107.916 39.672 108 ;
    END
  END rq[52]
  PIN rq[53]
    DIRECTION OUTPUT ;
    USE SIGNAL ;
    PORT
      LAYER M5 ;
        RECT  40.368 107.916 40.392 108 ;
    END
  END rq[53]
  PIN rq[54]
    DIRECTION OUTPUT ;
    USE SIGNAL ;
    PORT
      LAYER M5 ;
        RECT  41.088 107.916 41.112 108 ;
    END
  END rq[54]
  PIN rq[55]
    DIRECTION OUTPUT ;
    USE SIGNAL ;
    PORT
      LAYER M5 ;
        RECT  41.856 107.916 41.88 108 ;
    END
  END rq[55]
  PIN rq[56]
    DIRECTION OUTPUT ;
    USE SIGNAL ;
    PORT
      LAYER M5 ;
        RECT  42.576 107.916 42.6 108 ;
    END
  END rq[56]
  PIN rq[57]
    DIRECTION OUTPUT ;
    USE SIGNAL ;
    PORT
      LAYER M5 ;
        RECT  43.296 107.916 43.32 108 ;
    END
  END rq[57]
  PIN rq[58]
    DIRECTION OUTPUT ;
    USE SIGNAL ;
    PORT
      LAYER M5 ;
        RECT  44.064 107.916 44.088 108 ;
    END
  END rq[58]
  PIN rq[59]
    DIRECTION OUTPUT ;
    USE SIGNAL ;
    PORT
      LAYER M5 ;
        RECT  44.784 107.916 44.808 108 ;
    END
  END rq[59]
  PIN rq[5]
    DIRECTION OUTPUT ;
    USE SIGNAL ;
    PORT
      LAYER M5 ;
        RECT  5.04 107.916 5.064 108 ;
    END
  END rq[5]
  PIN rq[60]
    DIRECTION OUTPUT ;
    USE SIGNAL ;
    PORT
      LAYER M5 ;
        RECT  45.504 107.916 45.528 108 ;
    END
  END rq[60]
  PIN rq[61]
    DIRECTION OUTPUT ;
    USE SIGNAL ;
    PORT
      LAYER M5 ;
        RECT  46.272 107.916 46.296 108 ;
    END
  END rq[61]
  PIN rq[62]
    DIRECTION OUTPUT ;
    USE SIGNAL ;
    PORT
      LAYER M5 ;
        RECT  46.992 107.916 47.016 108 ;
    END
  END rq[62]
  PIN rq[63]
    DIRECTION OUTPUT ;
    USE SIGNAL ;
    PORT
      LAYER M5 ;
        RECT  47.712 107.916 47.736 108 ;
    END
  END rq[63]
  PIN rq[64]
    DIRECTION OUTPUT ;
    USE SIGNAL ;
    PORT
      LAYER M5 ;
        RECT  48.48 107.916 48.504 108 ;
    END
  END rq[64]
  PIN rq[65]
    DIRECTION OUTPUT ;
    USE SIGNAL ;
    PORT
      LAYER M5 ;
        RECT  49.2 107.916 49.224 108 ;
    END
  END rq[65]
  PIN rq[66]
    DIRECTION OUTPUT ;
    USE SIGNAL ;
    PORT
      LAYER M5 ;
        RECT  49.92 107.916 49.944 108 ;
    END
  END rq[66]
  PIN rq[67]
    DIRECTION OUTPUT ;
    USE SIGNAL ;
    PORT
      LAYER M5 ;
        RECT  50.688 107.916 50.712 108 ;
    END
  END rq[67]
  PIN rq[68]
    DIRECTION OUTPUT ;
    USE SIGNAL ;
    PORT
      LAYER M5 ;
        RECT  51.408 107.916 51.432 108 ;
    END
  END rq[68]
  PIN rq[69]
    DIRECTION OUTPUT ;
    USE SIGNAL ;
    PORT
      LAYER M5 ;
        RECT  52.128 107.916 52.152 108 ;
    END
  END rq[69]
  PIN rq[6]
    DIRECTION OUTPUT ;
    USE SIGNAL ;
    PORT
      LAYER M5 ;
        RECT  5.76 107.916 5.784 108 ;
    END
  END rq[6]
  PIN rq[70]
    DIRECTION OUTPUT ;
    USE SIGNAL ;
    PORT
      LAYER M5 ;
        RECT  52.896 107.916 52.92 108 ;
    END
  END rq[70]
  PIN rq[71]
    DIRECTION OUTPUT ;
    USE SIGNAL ;
    PORT
      LAYER M5 ;
        RECT  53.616 107.916 53.64 108 ;
    END
  END rq[71]
  PIN rq[72]
    DIRECTION OUTPUT ;
    USE SIGNAL ;
    PORT
      LAYER M5 ;
        RECT  54.336 107.916 54.36 108 ;
    END
  END rq[72]
  PIN rq[73]
    DIRECTION OUTPUT ;
    USE SIGNAL ;
    PORT
      LAYER M5 ;
        RECT  55.104 107.916 55.128 108 ;
    END
  END rq[73]
  PIN rq[74]
    DIRECTION OUTPUT ;
    USE SIGNAL ;
    PORT
      LAYER M5 ;
        RECT  55.824 107.916 55.848 108 ;
    END
  END rq[74]
  PIN rq[75]
    DIRECTION OUTPUT ;
    USE SIGNAL ;
    PORT
      LAYER M5 ;
        RECT  56.544 107.916 56.568 108 ;
    END
  END rq[75]
  PIN rq[76]
    DIRECTION OUTPUT ;
    USE SIGNAL ;
    PORT
      LAYER M5 ;
        RECT  57.312 107.916 57.336 108 ;
    END
  END rq[76]
  PIN rq[77]
    DIRECTION OUTPUT ;
    USE SIGNAL ;
    PORT
      LAYER M5 ;
        RECT  58.032 107.916 58.056 108 ;
    END
  END rq[77]
  PIN rq[78]
    DIRECTION OUTPUT ;
    USE SIGNAL ;
    PORT
      LAYER M5 ;
        RECT  58.752 107.916 58.776 108 ;
    END
  END rq[78]
  PIN rq[79]
    DIRECTION OUTPUT ;
    USE SIGNAL ;
    PORT
      LAYER M5 ;
        RECT  59.52 107.916 59.544 108 ;
    END
  END rq[79]
  PIN rq[7]
    DIRECTION OUTPUT ;
    USE SIGNAL ;
    PORT
      LAYER M5 ;
        RECT  6.528 107.916 6.552 108 ;
    END
  END rq[7]
  PIN rq[80]
    DIRECTION OUTPUT ;
    USE SIGNAL ;
    PORT
      LAYER M5 ;
        RECT  60.24 107.916 60.264 108 ;
    END
  END rq[80]
  PIN rq[81]
    DIRECTION OUTPUT ;
    USE SIGNAL ;
    PORT
      LAYER M5 ;
        RECT  60.96 107.916 60.984 108 ;
    END
  END rq[81]
  PIN rq[82]
    DIRECTION OUTPUT ;
    USE SIGNAL ;
    PORT
      LAYER M5 ;
        RECT  61.728 107.916 61.752 108 ;
    END
  END rq[82]
  PIN rq[83]
    DIRECTION OUTPUT ;
    USE SIGNAL ;
    PORT
      LAYER M5 ;
        RECT  62.448 107.916 62.472 108 ;
    END
  END rq[83]
  PIN rq[84]
    DIRECTION OUTPUT ;
    USE SIGNAL ;
    PORT
      LAYER M5 ;
        RECT  63.168 107.916 63.192 108 ;
    END
  END rq[84]
  PIN rq[85]
    DIRECTION OUTPUT ;
    USE SIGNAL ;
    PORT
      LAYER M5 ;
        RECT  63.936 107.916 63.96 108 ;
    END
  END rq[85]
  PIN rq[86]
    DIRECTION OUTPUT ;
    USE SIGNAL ;
    PORT
      LAYER M5 ;
        RECT  64.656 107.916 64.68 108 ;
    END
  END rq[86]
  PIN rq[87]
    DIRECTION OUTPUT ;
    USE SIGNAL ;
    PORT
      LAYER M5 ;
        RECT  65.376 107.916 65.4 108 ;
    END
  END rq[87]
  PIN rq[88]
    DIRECTION OUTPUT ;
    USE SIGNAL ;
    PORT
      LAYER M5 ;
        RECT  66.144 107.916 66.168 108 ;
    END
  END rq[88]
  PIN rq[89]
    DIRECTION OUTPUT ;
    USE SIGNAL ;
    PORT
      LAYER M5 ;
        RECT  66.864 107.916 66.888 108 ;
    END
  END rq[89]
  PIN rq[8]
    DIRECTION OUTPUT ;
    USE SIGNAL ;
    PORT
      LAYER M5 ;
        RECT  7.248 107.916 7.272 108 ;
    END
  END rq[8]
  PIN rq[90]
    DIRECTION OUTPUT ;
    USE SIGNAL ;
    PORT
      LAYER M5 ;
        RECT  67.584 107.916 67.608 108 ;
    END
  END rq[90]
  PIN rq[91]
    DIRECTION OUTPUT ;
    USE SIGNAL ;
    PORT
      LAYER M5 ;
        RECT  68.352 107.916 68.376 108 ;
    END
  END rq[91]
  PIN rq[92]
    DIRECTION OUTPUT ;
    USE SIGNAL ;
    PORT
      LAYER M5 ;
        RECT  69.072 107.916 69.096 108 ;
    END
  END rq[92]
  PIN rq[93]
    DIRECTION OUTPUT ;
    USE SIGNAL ;
    PORT
      LAYER M5 ;
        RECT  69.792 107.916 69.816 108 ;
    END
  END rq[93]
  PIN rq[94]
    DIRECTION OUTPUT ;
    USE SIGNAL ;
    PORT
      LAYER M5 ;
        RECT  70.56 107.916 70.584 108 ;
    END
  END rq[94]
  PIN rq[95]
    DIRECTION OUTPUT ;
    USE SIGNAL ;
    PORT
      LAYER M5 ;
        RECT  71.28 107.916 71.304 108 ;
    END
  END rq[95]
  PIN rq[96]
    DIRECTION OUTPUT ;
    USE SIGNAL ;
    PORT
      LAYER M5 ;
        RECT  72 107.916 72.024 108 ;
    END
  END rq[96]
  PIN rq[97]
    DIRECTION OUTPUT ;
    USE SIGNAL ;
    PORT
      LAYER M5 ;
        RECT  72.768 107.916 72.792 108 ;
    END
  END rq[97]
  PIN rq[98]
    DIRECTION OUTPUT ;
    USE SIGNAL ;
    PORT
      LAYER M5 ;
        RECT  73.488 107.916 73.512 108 ;
    END
  END rq[98]
  PIN rq[99]
    DIRECTION OUTPUT ;
    USE SIGNAL ;
    PORT
      LAYER M5 ;
        RECT  74.208 107.916 74.232 108 ;
    END
  END rq[99]
  PIN rq[9]
    DIRECTION OUTPUT ;
    USE SIGNAL ;
    PORT
      LAYER M5 ;
        RECT  7.968 107.916 7.992 108 ;
    END
  END rq[9]
  PIN rr_v[0]
    DIRECTION INPUT ;
    USE SIGNAL ;
    PORT
      LAYER M5 ;
        RECT  101.472 107.916 101.496 108 ;
    END
  END rr_v[0]
  PIN rr_v[1]
    DIRECTION INPUT ;
    USE SIGNAL ;
    PORT
      LAYER M5 ;
        RECT  102.192 107.916 102.216 108 ;
    END
  END rr_v[1]
  PIN rr_v[2]
    DIRECTION INPUT ;
    USE SIGNAL ;
    PORT
      LAYER M5 ;
        RECT  102.96 107.916 102.984 108 ;
    END
  END rr_v[2]
  PIN rr_v[3]
    DIRECTION INPUT ;
    USE SIGNAL ;
    PORT
      LAYER M5 ;
        RECT  103.68 107.916 103.704 108 ;
    END
  END rr_v[3]
  PIN rr_v[4]
    DIRECTION INPUT ;
    USE SIGNAL ;
    PORT
      LAYER M5 ;
        RECT  104.4 107.916 104.424 108 ;
    END
  END rr_v[4]
  PIN rr_v[5]
    DIRECTION INPUT ;
    USE SIGNAL ;
    PORT
      LAYER M5 ;
        RECT  105.168 107.916 105.192 108 ;
    END
  END rr_v[5]
  PIN rr_v[6]
    DIRECTION INPUT ;
    USE SIGNAL ;
    PORT
      LAYER M5 ;
        RECT  105.888 107.916 105.912 108 ;
    END
  END rr_v[6]
  PIN rr_v[7]
    DIRECTION INPUT ;
    USE SIGNAL ;
    PORT
      LAYER M5 ;
        RECT  106.608 107.916 106.632 108 ;
    END
  END rr_v[7]
  PIN rsel[0]
    DIRECTION OUTPUT ;
    USE SIGNAL ;
    PORT
      LAYER M4 ;
        RECT  107.916 102 108 102.024 ;
    END
  END rsel[0]
  PIN rsel[1]
    DIRECTION OUTPUT ;
    USE SIGNAL ;
    PORT
      LAYER M4 ;
        RECT  107.916 102.768 108 102.792 ;
    END
  END rsel[1]
  PIN rsel[2]
    DIRECTION OUTPUT ;
    USE SIGNAL ;
    PORT
      LAYER M4 ;
        RECT  107.916 103.536 108 103.56 ;
    END
  END rsel[2]
  PIN rst_n
    DIRECTION INPUT ;
    USE SIGNAL ;
    PORT
      LAYER M4 ;
        RECT  0 96.384 0.084 96.408 ;
    END
    PORT
      LAYER M4 ;
        RECT  0.06 96.384 2.408 96.408 ;
    END
  END rst_n
  PIN vo
    DIRECTION INPUT ;
    USE SIGNAL ;
    PORT
      LAYER M4 ;
        RECT  107.916 104.304 108 104.328 ;
    END
  END vo
  PIN wc_cfg[0]
    DIRECTION INPUT ;
    USE SIGNAL ;
    PORT
      LAYER M4 ;
        RECT  0 98.016 0.084 98.04 ;
    END
    PORT
      LAYER M4 ;
        RECT  0.06 98.016 2.408 98.04 ;
    END
  END wc_cfg[0]
  PIN wc_cfg[1]
    DIRECTION INPUT ;
    USE SIGNAL ;
    PORT
      LAYER M4 ;
        RECT  0 99.648 0.084 99.672 ;
    END
    PORT
      LAYER M4 ;
        RECT  0.06 99.648 2.408 99.672 ;
    END
  END wc_cfg[1]
  PIN wc_cfg[2]
    DIRECTION INPUT ;
    USE SIGNAL ;
    PORT
      LAYER M4 ;
        RECT  0 101.28 0.084 101.304 ;
    END
    PORT
      LAYER M4 ;
        RECT  0.06 101.28 2.408 101.304 ;
    END
  END wc_cfg[2]
  PIN wc_cfg[3]
    DIRECTION INPUT ;
    USE SIGNAL ;
    PORT
      LAYER M4 ;
        RECT  0 102.912 0.084 102.936 ;
    END
    PORT
      LAYER M4 ;
        RECT  0.06 102.912 2.408 102.936 ;
    END
  END wc_cfg[3]
  PIN wc_cfg[4]
    DIRECTION INPUT ;
    USE SIGNAL ;
    PORT
      LAYER M4 ;
        RECT  0 104.544 0.084 104.568 ;
    END
    PORT
      LAYER M4 ;
        RECT  0.06 104.544 2.408 104.568 ;
    END
  END wc_cfg[4]
  PIN wc_cfg[5]
    DIRECTION INPUT ;
    USE SIGNAL ;
    PORT
      LAYER M4 ;
        RECT  0 106.176 0.084 106.2 ;
    END
    PORT
      LAYER M4 ;
        RECT  0.06 106.176 2.069 106.2 ;
    END
  END wc_cfg[5]
  PIN wq_addr[0]
    DIRECTION OUTPUT ;
    USE SIGNAL ;
    PORT
      LAYER M5 ;
        RECT  1.248 0 1.272 0.084 ;
    END
  END wq_addr[0]
  PIN wq_addr[100]
    DIRECTION OUTPUT ;
    USE SIGNAL ;
    PORT
      LAYER M5 ;
        RECT  54.24 0 54.264 0.084 ;
    END
  END wq_addr[100]
  PIN wq_addr[101]
    DIRECTION OUTPUT ;
    USE SIGNAL ;
    PORT
      LAYER M5 ;
        RECT  54.768 0 54.792 0.084 ;
    END
  END wq_addr[101]
  PIN wq_addr[102]
    DIRECTION OUTPUT ;
    USE SIGNAL ;
    PORT
      LAYER M5 ;
        RECT  55.296 0 55.32 0.084 ;
    END
  END wq_addr[102]
  PIN wq_addr[103]
    DIRECTION OUTPUT ;
    USE SIGNAL ;
    PORT
      LAYER M5 ;
        RECT  55.824 0 55.848 0.084 ;
    END
  END wq_addr[103]
  PIN wq_addr[104]
    DIRECTION OUTPUT ;
    USE SIGNAL ;
    PORT
      LAYER M5 ;
        RECT  56.352 0 56.376 0.084 ;
    END
  END wq_addr[104]
  PIN wq_addr[105]
    DIRECTION OUTPUT ;
    USE SIGNAL ;
    PORT
      LAYER M5 ;
        RECT  56.88 0 56.904 0.084 ;
    END
  END wq_addr[105]
  PIN wq_addr[106]
    DIRECTION OUTPUT ;
    USE SIGNAL ;
    PORT
      LAYER M5 ;
        RECT  57.456 0 57.48 0.084 ;
    END
  END wq_addr[106]
  PIN wq_addr[107]
    DIRECTION OUTPUT ;
    USE SIGNAL ;
    PORT
      LAYER M5 ;
        RECT  57.984 0 58.008 0.084 ;
    END
  END wq_addr[107]
  PIN wq_addr[108]
    DIRECTION OUTPUT ;
    USE SIGNAL ;
    PORT
      LAYER M5 ;
        RECT  58.512 0 58.536 0.084 ;
    END
  END wq_addr[108]
  PIN wq_addr[109]
    DIRECTION OUTPUT ;
    USE SIGNAL ;
    PORT
      LAYER M5 ;
        RECT  59.04 0 59.064 0.084 ;
    END
  END wq_addr[109]
  PIN wq_addr[10]
    DIRECTION OUTPUT ;
    USE SIGNAL ;
    PORT
      LAYER M5 ;
        RECT  6.576 0 6.6 0.084 ;
    END
  END wq_addr[10]
  PIN wq_addr[110]
    DIRECTION OUTPUT ;
    USE SIGNAL ;
    PORT
      LAYER M5 ;
        RECT  59.568 0 59.592 0.084 ;
    END
  END wq_addr[110]
  PIN wq_addr[111]
    DIRECTION OUTPUT ;
    USE SIGNAL ;
    PORT
      LAYER M5 ;
        RECT  60.096 0 60.12 0.084 ;
    END
  END wq_addr[111]
  PIN wq_addr[112]
    DIRECTION OUTPUT ;
    USE SIGNAL ;
    PORT
      LAYER M5 ;
        RECT  60.624 0 60.648 0.084 ;
    END
  END wq_addr[112]
  PIN wq_addr[113]
    DIRECTION OUTPUT ;
    USE SIGNAL ;
    PORT
      LAYER M5 ;
        RECT  61.152 0 61.176 0.084 ;
    END
  END wq_addr[113]
  PIN wq_addr[114]
    DIRECTION OUTPUT ;
    USE SIGNAL ;
    PORT
      LAYER M5 ;
        RECT  61.68 0 61.704 0.084 ;
    END
  END wq_addr[114]
  PIN wq_addr[115]
    DIRECTION OUTPUT ;
    USE SIGNAL ;
    PORT
      LAYER M5 ;
        RECT  62.208 0 62.232 0.084 ;
    END
  END wq_addr[115]
  PIN wq_addr[116]
    DIRECTION OUTPUT ;
    USE SIGNAL ;
    PORT
      LAYER M5 ;
        RECT  62.736 0 62.76 0.084 ;
    END
  END wq_addr[116]
  PIN wq_addr[117]
    DIRECTION OUTPUT ;
    USE SIGNAL ;
    PORT
      LAYER M5 ;
        RECT  63.264 0 63.288 0.084 ;
    END
  END wq_addr[117]
  PIN wq_addr[118]
    DIRECTION OUTPUT ;
    USE SIGNAL ;
    PORT
      LAYER M5 ;
        RECT  63.792 0 63.816 0.084 ;
    END
  END wq_addr[118]
  PIN wq_addr[119]
    DIRECTION OUTPUT ;
    USE SIGNAL ;
    PORT
      LAYER M5 ;
        RECT  64.32 0 64.344 0.084 ;
    END
  END wq_addr[119]
  PIN wq_addr[11]
    DIRECTION OUTPUT ;
    USE SIGNAL ;
    PORT
      LAYER M5 ;
        RECT  7.104 0 7.128 0.084 ;
    END
  END wq_addr[11]
  PIN wq_addr[120]
    DIRECTION OUTPUT ;
    USE SIGNAL ;
    PORT
      LAYER M5 ;
        RECT  64.848 0 64.872 0.084 ;
    END
  END wq_addr[120]
  PIN wq_addr[121]
    DIRECTION OUTPUT ;
    USE SIGNAL ;
    PORT
      LAYER M5 ;
        RECT  65.376 0 65.4 0.084 ;
    END
  END wq_addr[121]
  PIN wq_addr[122]
    DIRECTION OUTPUT ;
    USE SIGNAL ;
    PORT
      LAYER M5 ;
        RECT  65.904 0 65.928 0.084 ;
    END
  END wq_addr[122]
  PIN wq_addr[123]
    DIRECTION OUTPUT ;
    USE SIGNAL ;
    PORT
      LAYER M5 ;
        RECT  66.432 0 66.456 0.084 ;
    END
  END wq_addr[123]
  PIN wq_addr[124]
    DIRECTION OUTPUT ;
    USE SIGNAL ;
    PORT
      LAYER M5 ;
        RECT  66.96 0 66.984 0.084 ;
    END
  END wq_addr[124]
  PIN wq_addr[125]
    DIRECTION OUTPUT ;
    USE SIGNAL ;
    PORT
      LAYER M5 ;
        RECT  67.488 0 67.512 0.084 ;
    END
  END wq_addr[125]
  PIN wq_addr[126]
    DIRECTION OUTPUT ;
    USE SIGNAL ;
    PORT
      LAYER M5 ;
        RECT  68.016 0 68.04 0.084 ;
    END
  END wq_addr[126]
  PIN wq_addr[127]
    DIRECTION OUTPUT ;
    USE SIGNAL ;
    PORT
      LAYER M5 ;
        RECT  68.544 0 68.568 0.084 ;
    END
  END wq_addr[127]
  PIN wq_addr[12]
    DIRECTION OUTPUT ;
    USE SIGNAL ;
    PORT
      LAYER M5 ;
        RECT  7.632 0 7.656 0.084 ;
    END
  END wq_addr[12]
  PIN wq_addr[13]
    DIRECTION OUTPUT ;
    USE SIGNAL ;
    PORT
      LAYER M5 ;
        RECT  8.16 0 8.184 0.084 ;
    END
  END wq_addr[13]
  PIN wq_addr[14]
    DIRECTION OUTPUT ;
    USE SIGNAL ;
    PORT
      LAYER M5 ;
        RECT  8.688 0 8.712 0.084 ;
    END
  END wq_addr[14]
  PIN wq_addr[15]
    DIRECTION OUTPUT ;
    USE SIGNAL ;
    PORT
      LAYER M5 ;
        RECT  9.216 0 9.24 0.084 ;
    END
  END wq_addr[15]
  PIN wq_addr[16]
    DIRECTION OUTPUT ;
    USE SIGNAL ;
    PORT
      LAYER M5 ;
        RECT  9.744 0 9.768 0.084 ;
    END
  END wq_addr[16]
  PIN wq_addr[17]
    DIRECTION OUTPUT ;
    USE SIGNAL ;
    PORT
      LAYER M5 ;
        RECT  10.272 0 10.296 0.084 ;
    END
  END wq_addr[17]
  PIN wq_addr[18]
    DIRECTION OUTPUT ;
    USE SIGNAL ;
    PORT
      LAYER M5 ;
        RECT  10.8 0 10.824 0.084 ;
    END
  END wq_addr[18]
  PIN wq_addr[19]
    DIRECTION OUTPUT ;
    USE SIGNAL ;
    PORT
      LAYER M5 ;
        RECT  11.328 0 11.352 0.084 ;
    END
  END wq_addr[19]
  PIN wq_addr[1]
    DIRECTION OUTPUT ;
    USE SIGNAL ;
    PORT
      LAYER M5 ;
        RECT  1.776 0 1.8 0.084 ;
    END
  END wq_addr[1]
  PIN wq_addr[20]
    DIRECTION OUTPUT ;
    USE SIGNAL ;
    PORT
      LAYER M5 ;
        RECT  11.856 0 11.88 0.084 ;
    END
  END wq_addr[20]
  PIN wq_addr[21]
    DIRECTION OUTPUT ;
    USE SIGNAL ;
    PORT
      LAYER M5 ;
        RECT  12.384 0 12.408 0.084 ;
    END
  END wq_addr[21]
  PIN wq_addr[22]
    DIRECTION OUTPUT ;
    USE SIGNAL ;
    PORT
      LAYER M5 ;
        RECT  12.912 0 12.936 0.084 ;
    END
  END wq_addr[22]
  PIN wq_addr[23]
    DIRECTION OUTPUT ;
    USE SIGNAL ;
    PORT
      LAYER M5 ;
        RECT  13.44 0 13.464 0.084 ;
    END
  END wq_addr[23]
  PIN wq_addr[24]
    DIRECTION OUTPUT ;
    USE SIGNAL ;
    PORT
      LAYER M5 ;
        RECT  13.968 0 13.992 0.084 ;
    END
  END wq_addr[24]
  PIN wq_addr[25]
    DIRECTION OUTPUT ;
    USE SIGNAL ;
    PORT
      LAYER M5 ;
        RECT  14.496 0 14.52 0.084 ;
    END
  END wq_addr[25]
  PIN wq_addr[26]
    DIRECTION OUTPUT ;
    USE SIGNAL ;
    PORT
      LAYER M5 ;
        RECT  15.024 0 15.048 0.084 ;
    END
  END wq_addr[26]
  PIN wq_addr[27]
    DIRECTION OUTPUT ;
    USE SIGNAL ;
    PORT
      LAYER M5 ;
        RECT  15.552 0 15.576 0.084 ;
    END
  END wq_addr[27]
  PIN wq_addr[28]
    DIRECTION OUTPUT ;
    USE SIGNAL ;
    PORT
      LAYER M5 ;
        RECT  16.08 0 16.104 0.084 ;
    END
  END wq_addr[28]
  PIN wq_addr[29]
    DIRECTION OUTPUT ;
    USE SIGNAL ;
    PORT
      LAYER M5 ;
        RECT  16.608 0 16.632 0.084 ;
    END
  END wq_addr[29]
  PIN wq_addr[2]
    DIRECTION OUTPUT ;
    USE SIGNAL ;
    PORT
      LAYER M5 ;
        RECT  2.304 0 2.328 0.084 ;
    END
  END wq_addr[2]
  PIN wq_addr[30]
    DIRECTION OUTPUT ;
    USE SIGNAL ;
    PORT
      LAYER M5 ;
        RECT  17.136 0 17.16 0.084 ;
    END
  END wq_addr[30]
  PIN wq_addr[31]
    DIRECTION OUTPUT ;
    USE SIGNAL ;
    PORT
      LAYER M5 ;
        RECT  17.664 0 17.688 0.084 ;
    END
  END wq_addr[31]
  PIN wq_addr[32]
    DIRECTION OUTPUT ;
    USE SIGNAL ;
    PORT
      LAYER M5 ;
        RECT  18.192 0 18.216 0.084 ;
    END
  END wq_addr[32]
  PIN wq_addr[33]
    DIRECTION OUTPUT ;
    USE SIGNAL ;
    PORT
      LAYER M5 ;
        RECT  18.72 0 18.744 0.084 ;
    END
  END wq_addr[33]
  PIN wq_addr[34]
    DIRECTION OUTPUT ;
    USE SIGNAL ;
    PORT
      LAYER M5 ;
        RECT  19.296 0 19.32 0.084 ;
    END
  END wq_addr[34]
  PIN wq_addr[35]
    DIRECTION OUTPUT ;
    USE SIGNAL ;
    PORT
      LAYER M5 ;
        RECT  19.824 0 19.848 0.084 ;
    END
  END wq_addr[35]
  PIN wq_addr[36]
    DIRECTION OUTPUT ;
    USE SIGNAL ;
    PORT
      LAYER M5 ;
        RECT  20.352 0 20.376 0.084 ;
    END
  END wq_addr[36]
  PIN wq_addr[37]
    DIRECTION OUTPUT ;
    USE SIGNAL ;
    PORT
      LAYER M5 ;
        RECT  20.88 0 20.904 0.084 ;
    END
  END wq_addr[37]
  PIN wq_addr[38]
    DIRECTION OUTPUT ;
    USE SIGNAL ;
    PORT
      LAYER M5 ;
        RECT  21.408 0 21.432 0.084 ;
    END
  END wq_addr[38]
  PIN wq_addr[39]
    DIRECTION OUTPUT ;
    USE SIGNAL ;
    PORT
      LAYER M5 ;
        RECT  21.936 0 21.96 0.084 ;
    END
  END wq_addr[39]
  PIN wq_addr[3]
    DIRECTION OUTPUT ;
    USE SIGNAL ;
    PORT
      LAYER M5 ;
        RECT  2.832 0 2.856 0.084 ;
    END
  END wq_addr[3]
  PIN wq_addr[40]
    DIRECTION OUTPUT ;
    USE SIGNAL ;
    PORT
      LAYER M5 ;
        RECT  22.464 0 22.488 0.084 ;
    END
  END wq_addr[40]
  PIN wq_addr[41]
    DIRECTION OUTPUT ;
    USE SIGNAL ;
    PORT
      LAYER M5 ;
        RECT  22.992 0 23.016 0.084 ;
    END
  END wq_addr[41]
  PIN wq_addr[42]
    DIRECTION OUTPUT ;
    USE SIGNAL ;
    PORT
      LAYER M5 ;
        RECT  23.52 0 23.544 0.084 ;
    END
  END wq_addr[42]
  PIN wq_addr[43]
    DIRECTION OUTPUT ;
    USE SIGNAL ;
    PORT
      LAYER M5 ;
        RECT  24.048 0 24.072 0.084 ;
    END
  END wq_addr[43]
  PIN wq_addr[44]
    DIRECTION OUTPUT ;
    USE SIGNAL ;
    PORT
      LAYER M5 ;
        RECT  24.576 0 24.6 0.084 ;
    END
  END wq_addr[44]
  PIN wq_addr[45]
    DIRECTION OUTPUT ;
    USE SIGNAL ;
    PORT
      LAYER M5 ;
        RECT  25.104 0 25.128 0.084 ;
    END
  END wq_addr[45]
  PIN wq_addr[46]
    DIRECTION OUTPUT ;
    USE SIGNAL ;
    PORT
      LAYER M5 ;
        RECT  25.632 0 25.656 0.084 ;
    END
  END wq_addr[46]
  PIN wq_addr[47]
    DIRECTION OUTPUT ;
    USE SIGNAL ;
    PORT
      LAYER M5 ;
        RECT  26.16 0 26.184 0.084 ;
    END
  END wq_addr[47]
  PIN wq_addr[48]
    DIRECTION OUTPUT ;
    USE SIGNAL ;
    PORT
      LAYER M5 ;
        RECT  26.688 0 26.712 0.084 ;
    END
  END wq_addr[48]
  PIN wq_addr[49]
    DIRECTION OUTPUT ;
    USE SIGNAL ;
    PORT
      LAYER M5 ;
        RECT  27.216 0 27.24 0.084 ;
    END
  END wq_addr[49]
  PIN wq_addr[4]
    DIRECTION OUTPUT ;
    USE SIGNAL ;
    PORT
      LAYER M5 ;
        RECT  3.36 0 3.384 0.084 ;
    END
  END wq_addr[4]
  PIN wq_addr[50]
    DIRECTION OUTPUT ;
    USE SIGNAL ;
    PORT
      LAYER M5 ;
        RECT  27.744 0 27.768 0.084 ;
    END
  END wq_addr[50]
  PIN wq_addr[51]
    DIRECTION OUTPUT ;
    USE SIGNAL ;
    PORT
      LAYER M5 ;
        RECT  28.272 0 28.296 0.084 ;
    END
  END wq_addr[51]
  PIN wq_addr[52]
    DIRECTION OUTPUT ;
    USE SIGNAL ;
    PORT
      LAYER M5 ;
        RECT  28.8 0 28.824 0.084 ;
    END
  END wq_addr[52]
  PIN wq_addr[53]
    DIRECTION OUTPUT ;
    USE SIGNAL ;
    PORT
      LAYER M5 ;
        RECT  29.328 0 29.352 0.084 ;
    END
  END wq_addr[53]
  PIN wq_addr[54]
    DIRECTION OUTPUT ;
    USE SIGNAL ;
    PORT
      LAYER M5 ;
        RECT  29.856 0 29.88 0.084 ;
    END
  END wq_addr[54]
  PIN wq_addr[55]
    DIRECTION OUTPUT ;
    USE SIGNAL ;
    PORT
      LAYER M5 ;
        RECT  30.384 0 30.408 0.084 ;
    END
  END wq_addr[55]
  PIN wq_addr[56]
    DIRECTION OUTPUT ;
    USE SIGNAL ;
    PORT
      LAYER M5 ;
        RECT  30.912 0 30.936 0.084 ;
    END
  END wq_addr[56]
  PIN wq_addr[57]
    DIRECTION OUTPUT ;
    USE SIGNAL ;
    PORT
      LAYER M5 ;
        RECT  31.44 0 31.464 0.084 ;
    END
  END wq_addr[57]
  PIN wq_addr[58]
    DIRECTION OUTPUT ;
    USE SIGNAL ;
    PORT
      LAYER M5 ;
        RECT  32.016 0 32.04 0.084 ;
    END
  END wq_addr[58]
  PIN wq_addr[59]
    DIRECTION OUTPUT ;
    USE SIGNAL ;
    PORT
      LAYER M5 ;
        RECT  32.544 0 32.568 0.084 ;
    END
  END wq_addr[59]
  PIN wq_addr[5]
    DIRECTION OUTPUT ;
    USE SIGNAL ;
    PORT
      LAYER M5 ;
        RECT  3.888 0 3.912 0.084 ;
    END
  END wq_addr[5]
  PIN wq_addr[60]
    DIRECTION OUTPUT ;
    USE SIGNAL ;
    PORT
      LAYER M5 ;
        RECT  33.072 0 33.096 0.084 ;
    END
  END wq_addr[60]
  PIN wq_addr[61]
    DIRECTION OUTPUT ;
    USE SIGNAL ;
    PORT
      LAYER M5 ;
        RECT  33.6 0 33.624 0.084 ;
    END
  END wq_addr[61]
  PIN wq_addr[62]
    DIRECTION OUTPUT ;
    USE SIGNAL ;
    PORT
      LAYER M5 ;
        RECT  34.128 0 34.152 0.084 ;
    END
  END wq_addr[62]
  PIN wq_addr[63]
    DIRECTION OUTPUT ;
    USE SIGNAL ;
    PORT
      LAYER M5 ;
        RECT  34.656 0 34.68 0.084 ;
    END
  END wq_addr[63]
  PIN wq_addr[64]
    DIRECTION OUTPUT ;
    USE SIGNAL ;
    PORT
      LAYER M5 ;
        RECT  35.184 0 35.208 0.084 ;
    END
  END wq_addr[64]
  PIN wq_addr[65]
    DIRECTION OUTPUT ;
    USE SIGNAL ;
    PORT
      LAYER M5 ;
        RECT  35.712 0 35.736 0.084 ;
    END
  END wq_addr[65]
  PIN wq_addr[66]
    DIRECTION OUTPUT ;
    USE SIGNAL ;
    PORT
      LAYER M5 ;
        RECT  36.24 0 36.264 0.084 ;
    END
  END wq_addr[66]
  PIN wq_addr[67]
    DIRECTION OUTPUT ;
    USE SIGNAL ;
    PORT
      LAYER M5 ;
        RECT  36.768 0 36.792 0.084 ;
    END
  END wq_addr[67]
  PIN wq_addr[68]
    DIRECTION OUTPUT ;
    USE SIGNAL ;
    PORT
      LAYER M5 ;
        RECT  37.296 0 37.32 0.084 ;
    END
  END wq_addr[68]
  PIN wq_addr[69]
    DIRECTION OUTPUT ;
    USE SIGNAL ;
    PORT
      LAYER M5 ;
        RECT  37.824 0 37.848 0.084 ;
    END
  END wq_addr[69]
  PIN wq_addr[6]
    DIRECTION OUTPUT ;
    USE SIGNAL ;
    PORT
      LAYER M5 ;
        RECT  4.416 0 4.44 0.084 ;
    END
  END wq_addr[6]
  PIN wq_addr[70]
    DIRECTION OUTPUT ;
    USE SIGNAL ;
    PORT
      LAYER M5 ;
        RECT  38.352 0 38.376 0.084 ;
    END
  END wq_addr[70]
  PIN wq_addr[71]
    DIRECTION OUTPUT ;
    USE SIGNAL ;
    PORT
      LAYER M5 ;
        RECT  38.88 0 38.904 0.084 ;
    END
  END wq_addr[71]
  PIN wq_addr[72]
    DIRECTION OUTPUT ;
    USE SIGNAL ;
    PORT
      LAYER M5 ;
        RECT  39.408 0 39.432 0.084 ;
    END
  END wq_addr[72]
  PIN wq_addr[73]
    DIRECTION OUTPUT ;
    USE SIGNAL ;
    PORT
      LAYER M5 ;
        RECT  39.936 0 39.96 0.084 ;
    END
  END wq_addr[73]
  PIN wq_addr[74]
    DIRECTION OUTPUT ;
    USE SIGNAL ;
    PORT
      LAYER M5 ;
        RECT  40.464 0 40.488 0.084 ;
    END
  END wq_addr[74]
  PIN wq_addr[75]
    DIRECTION OUTPUT ;
    USE SIGNAL ;
    PORT
      LAYER M5 ;
        RECT  40.992 0 41.016 0.084 ;
    END
  END wq_addr[75]
  PIN wq_addr[76]
    DIRECTION OUTPUT ;
    USE SIGNAL ;
    PORT
      LAYER M5 ;
        RECT  41.52 0 41.544 0.084 ;
    END
  END wq_addr[76]
  PIN wq_addr[77]
    DIRECTION OUTPUT ;
    USE SIGNAL ;
    PORT
      LAYER M5 ;
        RECT  42.048 0 42.072 0.084 ;
    END
  END wq_addr[77]
  PIN wq_addr[78]
    DIRECTION OUTPUT ;
    USE SIGNAL ;
    PORT
      LAYER M5 ;
        RECT  42.576 0 42.6 0.084 ;
    END
  END wq_addr[78]
  PIN wq_addr[79]
    DIRECTION OUTPUT ;
    USE SIGNAL ;
    PORT
      LAYER M5 ;
        RECT  43.104 0 43.128 0.084 ;
    END
  END wq_addr[79]
  PIN wq_addr[7]
    DIRECTION OUTPUT ;
    USE SIGNAL ;
    PORT
      LAYER M5 ;
        RECT  4.944 0 4.968 0.084 ;
    END
  END wq_addr[7]
  PIN wq_addr[80]
    DIRECTION OUTPUT ;
    USE SIGNAL ;
    PORT
      LAYER M5 ;
        RECT  43.632 0 43.656 0.084 ;
    END
  END wq_addr[80]
  PIN wq_addr[81]
    DIRECTION OUTPUT ;
    USE SIGNAL ;
    PORT
      LAYER M5 ;
        RECT  44.16 0 44.184 0.084 ;
    END
  END wq_addr[81]
  PIN wq_addr[82]
    DIRECTION OUTPUT ;
    USE SIGNAL ;
    PORT
      LAYER M5 ;
        RECT  44.736 0 44.76 0.084 ;
    END
  END wq_addr[82]
  PIN wq_addr[83]
    DIRECTION OUTPUT ;
    USE SIGNAL ;
    PORT
      LAYER M5 ;
        RECT  45.264 0 45.288 0.084 ;
    END
  END wq_addr[83]
  PIN wq_addr[84]
    DIRECTION OUTPUT ;
    USE SIGNAL ;
    PORT
      LAYER M5 ;
        RECT  45.792 0 45.816 0.084 ;
    END
  END wq_addr[84]
  PIN wq_addr[85]
    DIRECTION OUTPUT ;
    USE SIGNAL ;
    PORT
      LAYER M5 ;
        RECT  46.32 0 46.344 0.084 ;
    END
  END wq_addr[85]
  PIN wq_addr[86]
    DIRECTION OUTPUT ;
    USE SIGNAL ;
    PORT
      LAYER M5 ;
        RECT  46.848 0 46.872 0.084 ;
    END
  END wq_addr[86]
  PIN wq_addr[87]
    DIRECTION OUTPUT ;
    USE SIGNAL ;
    PORT
      LAYER M5 ;
        RECT  47.376 0 47.4 0.084 ;
    END
  END wq_addr[87]
  PIN wq_addr[88]
    DIRECTION OUTPUT ;
    USE SIGNAL ;
    PORT
      LAYER M5 ;
        RECT  47.904 0 47.928 0.084 ;
    END
  END wq_addr[88]
  PIN wq_addr[89]
    DIRECTION OUTPUT ;
    USE SIGNAL ;
    PORT
      LAYER M5 ;
        RECT  48.432 0 48.456 0.084 ;
    END
  END wq_addr[89]
  PIN wq_addr[8]
    DIRECTION OUTPUT ;
    USE SIGNAL ;
    PORT
      LAYER M5 ;
        RECT  5.472 0 5.496 0.084 ;
    END
  END wq_addr[8]
  PIN wq_addr[90]
    DIRECTION OUTPUT ;
    USE SIGNAL ;
    PORT
      LAYER M5 ;
        RECT  48.96 0 48.984 0.084 ;
    END
  END wq_addr[90]
  PIN wq_addr[91]
    DIRECTION OUTPUT ;
    USE SIGNAL ;
    PORT
      LAYER M5 ;
        RECT  49.488 0 49.512 0.084 ;
    END
  END wq_addr[91]
  PIN wq_addr[92]
    DIRECTION OUTPUT ;
    USE SIGNAL ;
    PORT
      LAYER M5 ;
        RECT  50.016 0 50.04 0.084 ;
    END
  END wq_addr[92]
  PIN wq_addr[93]
    DIRECTION OUTPUT ;
    USE SIGNAL ;
    PORT
      LAYER M5 ;
        RECT  50.544 0 50.568 0.084 ;
    END
  END wq_addr[93]
  PIN wq_addr[94]
    DIRECTION OUTPUT ;
    USE SIGNAL ;
    PORT
      LAYER M5 ;
        RECT  51.072 0 51.096 0.084 ;
    END
  END wq_addr[94]
  PIN wq_addr[95]
    DIRECTION OUTPUT ;
    USE SIGNAL ;
    PORT
      LAYER M5 ;
        RECT  51.6 0 51.624 0.084 ;
    END
  END wq_addr[95]
  PIN wq_addr[96]
    DIRECTION OUTPUT ;
    USE SIGNAL ;
    PORT
      LAYER M5 ;
        RECT  52.128 0 52.152 0.084 ;
    END
  END wq_addr[96]
  PIN wq_addr[97]
    DIRECTION OUTPUT ;
    USE SIGNAL ;
    PORT
      LAYER M5 ;
        RECT  52.656 0 52.68 0.084 ;
    END
  END wq_addr[97]
  PIN wq_addr[98]
    DIRECTION OUTPUT ;
    USE SIGNAL ;
    PORT
      LAYER M5 ;
        RECT  53.184 0 53.208 0.084 ;
    END
  END wq_addr[98]
  PIN wq_addr[99]
    DIRECTION OUTPUT ;
    USE SIGNAL ;
    PORT
      LAYER M5 ;
        RECT  53.712 0 53.736 0.084 ;
    END
  END wq_addr[99]
  PIN wq_addr[9]
    DIRECTION OUTPUT ;
    USE SIGNAL ;
    PORT
      LAYER M5 ;
        RECT  6 0 6.024 0.084 ;
    END
  END wq_addr[9]
  PIN wq_mask[0]
    DIRECTION OUTPUT ;
    USE SIGNAL ;
    PORT
      LAYER M5 ;
        RECT  69.072 0 69.096 0.084 ;
    END
  END wq_mask[0]
  PIN wq_mask[10]
    DIRECTION OUTPUT ;
    USE SIGNAL ;
    PORT
      LAYER M5 ;
        RECT  74.4 0 74.424 0.084 ;
    END
  END wq_mask[10]
  PIN wq_mask[11]
    DIRECTION OUTPUT ;
    USE SIGNAL ;
    PORT
      LAYER M5 ;
        RECT  74.928 0 74.952 0.084 ;
    END
  END wq_mask[11]
  PIN wq_mask[12]
    DIRECTION OUTPUT ;
    USE SIGNAL ;
    PORT
      LAYER M5 ;
        RECT  75.456 0 75.48 0.084 ;
    END
  END wq_mask[12]
  PIN wq_mask[13]
    DIRECTION OUTPUT ;
    USE SIGNAL ;
    PORT
      LAYER M5 ;
        RECT  75.984 0 76.008 0.084 ;
    END
  END wq_mask[13]
  PIN wq_mask[14]
    DIRECTION OUTPUT ;
    USE SIGNAL ;
    PORT
      LAYER M5 ;
        RECT  76.512 0 76.536 0.084 ;
    END
  END wq_mask[14]
  PIN wq_mask[15]
    DIRECTION OUTPUT ;
    USE SIGNAL ;
    PORT
      LAYER M5 ;
        RECT  77.04 0 77.064 0.084 ;
    END
  END wq_mask[15]
  PIN wq_mask[16]
    DIRECTION OUTPUT ;
    USE SIGNAL ;
    PORT
      LAYER M5 ;
        RECT  77.568 0 77.592 0.084 ;
    END
  END wq_mask[16]
  PIN wq_mask[17]
    DIRECTION OUTPUT ;
    USE SIGNAL ;
    PORT
      LAYER M5 ;
        RECT  78.096 0 78.12 0.084 ;
    END
  END wq_mask[17]
  PIN wq_mask[18]
    DIRECTION OUTPUT ;
    USE SIGNAL ;
    PORT
      LAYER M5 ;
        RECT  78.624 0 78.648 0.084 ;
    END
  END wq_mask[18]
  PIN wq_mask[19]
    DIRECTION OUTPUT ;
    USE SIGNAL ;
    PORT
      LAYER M5 ;
        RECT  79.152 0 79.176 0.084 ;
    END
  END wq_mask[19]
  PIN wq_mask[1]
    DIRECTION OUTPUT ;
    USE SIGNAL ;
    PORT
      LAYER M5 ;
        RECT  69.6 0 69.624 0.084 ;
    END
  END wq_mask[1]
  PIN wq_mask[20]
    DIRECTION OUTPUT ;
    USE SIGNAL ;
    PORT
      LAYER M5 ;
        RECT  79.68 0 79.704 0.084 ;
    END
  END wq_mask[20]
  PIN wq_mask[21]
    DIRECTION OUTPUT ;
    USE SIGNAL ;
    PORT
      LAYER M5 ;
        RECT  80.208 0 80.232 0.084 ;
    END
  END wq_mask[21]
  PIN wq_mask[22]
    DIRECTION OUTPUT ;
    USE SIGNAL ;
    PORT
      LAYER M5 ;
        RECT  80.736 0 80.76 0.084 ;
    END
  END wq_mask[22]
  PIN wq_mask[23]
    DIRECTION OUTPUT ;
    USE SIGNAL ;
    PORT
      LAYER M5 ;
        RECT  81.264 0 81.288 0.084 ;
    END
  END wq_mask[23]
  PIN wq_mask[24]
    DIRECTION OUTPUT ;
    USE SIGNAL ;
    PORT
      LAYER M5 ;
        RECT  81.792 0 81.816 0.084 ;
    END
  END wq_mask[24]
  PIN wq_mask[25]
    DIRECTION OUTPUT ;
    USE SIGNAL ;
    PORT
      LAYER M5 ;
        RECT  82.32 0 82.344 0.084 ;
    END
  END wq_mask[25]
  PIN wq_mask[26]
    DIRECTION OUTPUT ;
    USE SIGNAL ;
    PORT
      LAYER M5 ;
        RECT  82.896 0 82.92 0.084 ;
    END
  END wq_mask[26]
  PIN wq_mask[27]
    DIRECTION OUTPUT ;
    USE SIGNAL ;
    PORT
      LAYER M5 ;
        RECT  83.424 0 83.448 0.084 ;
    END
  END wq_mask[27]
  PIN wq_mask[28]
    DIRECTION OUTPUT ;
    USE SIGNAL ;
    PORT
      LAYER M5 ;
        RECT  83.952 0 83.976 0.084 ;
    END
  END wq_mask[28]
  PIN wq_mask[29]
    DIRECTION OUTPUT ;
    USE SIGNAL ;
    PORT
      LAYER M5 ;
        RECT  84.48 0 84.504 0.084 ;
    END
  END wq_mask[29]
  PIN wq_mask[2]
    DIRECTION OUTPUT ;
    USE SIGNAL ;
    PORT
      LAYER M5 ;
        RECT  70.176 0 70.2 0.084 ;
    END
  END wq_mask[2]
  PIN wq_mask[30]
    DIRECTION OUTPUT ;
    USE SIGNAL ;
    PORT
      LAYER M5 ;
        RECT  85.008 0 85.032 0.084 ;
    END
  END wq_mask[30]
  PIN wq_mask[31]
    DIRECTION OUTPUT ;
    USE SIGNAL ;
    PORT
      LAYER M5 ;
        RECT  85.536 0 85.56 0.084 ;
    END
  END wq_mask[31]
  PIN wq_mask[32]
    DIRECTION OUTPUT ;
    USE SIGNAL ;
    PORT
      LAYER M5 ;
        RECT  86.064 0 86.088 0.084 ;
    END
  END wq_mask[32]
  PIN wq_mask[33]
    DIRECTION OUTPUT ;
    USE SIGNAL ;
    PORT
      LAYER M5 ;
        RECT  86.592 0 86.616 0.084 ;
    END
  END wq_mask[33]
  PIN wq_mask[34]
    DIRECTION OUTPUT ;
    USE SIGNAL ;
    PORT
      LAYER M5 ;
        RECT  87.12 0 87.144 0.084 ;
    END
  END wq_mask[34]
  PIN wq_mask[35]
    DIRECTION OUTPUT ;
    USE SIGNAL ;
    PORT
      LAYER M5 ;
        RECT  87.648 0 87.672 0.084 ;
    END
  END wq_mask[35]
  PIN wq_mask[36]
    DIRECTION OUTPUT ;
    USE SIGNAL ;
    PORT
      LAYER M5 ;
        RECT  88.176 0 88.2 0.084 ;
    END
  END wq_mask[36]
  PIN wq_mask[37]
    DIRECTION OUTPUT ;
    USE SIGNAL ;
    PORT
      LAYER M5 ;
        RECT  88.704 0 88.728 0.084 ;
    END
  END wq_mask[37]
  PIN wq_mask[38]
    DIRECTION OUTPUT ;
    USE SIGNAL ;
    PORT
      LAYER M5 ;
        RECT  89.232 0 89.256 0.084 ;
    END
  END wq_mask[38]
  PIN wq_mask[39]
    DIRECTION OUTPUT ;
    USE SIGNAL ;
    PORT
      LAYER M5 ;
        RECT  89.76 0 89.784 0.084 ;
    END
  END wq_mask[39]
  PIN wq_mask[3]
    DIRECTION OUTPUT ;
    USE SIGNAL ;
    PORT
      LAYER M5 ;
        RECT  70.704 0 70.728 0.084 ;
    END
  END wq_mask[3]
  PIN wq_mask[40]
    DIRECTION OUTPUT ;
    USE SIGNAL ;
    PORT
      LAYER M5 ;
        RECT  90.288 0 90.312 0.084 ;
    END
  END wq_mask[40]
  PIN wq_mask[41]
    DIRECTION OUTPUT ;
    USE SIGNAL ;
    PORT
      LAYER M5 ;
        RECT  90.816 0 90.84 0.084 ;
    END
  END wq_mask[41]
  PIN wq_mask[42]
    DIRECTION OUTPUT ;
    USE SIGNAL ;
    PORT
      LAYER M5 ;
        RECT  91.344 0 91.368 0.084 ;
    END
  END wq_mask[42]
  PIN wq_mask[43]
    DIRECTION OUTPUT ;
    USE SIGNAL ;
    PORT
      LAYER M5 ;
        RECT  91.872 0 91.896 0.084 ;
    END
  END wq_mask[43]
  PIN wq_mask[44]
    DIRECTION OUTPUT ;
    USE SIGNAL ;
    PORT
      LAYER M5 ;
        RECT  92.4 0 92.424 0.084 ;
    END
  END wq_mask[44]
  PIN wq_mask[45]
    DIRECTION OUTPUT ;
    USE SIGNAL ;
    PORT
      LAYER M5 ;
        RECT  92.928 0 92.952 0.084 ;
    END
  END wq_mask[45]
  PIN wq_mask[46]
    DIRECTION OUTPUT ;
    USE SIGNAL ;
    PORT
      LAYER M5 ;
        RECT  93.456 0 93.48 0.084 ;
    END
  END wq_mask[46]
  PIN wq_mask[47]
    DIRECTION OUTPUT ;
    USE SIGNAL ;
    PORT
      LAYER M5 ;
        RECT  93.984 0 94.008 0.084 ;
    END
  END wq_mask[47]
  PIN wq_mask[48]
    DIRECTION OUTPUT ;
    USE SIGNAL ;
    PORT
      LAYER M5 ;
        RECT  94.512 0 94.536 0.084 ;
    END
  END wq_mask[48]
  PIN wq_mask[49]
    DIRECTION OUTPUT ;
    USE SIGNAL ;
    PORT
      LAYER M5 ;
        RECT  95.04 0 95.064 0.084 ;
    END
  END wq_mask[49]
  PIN wq_mask[4]
    DIRECTION OUTPUT ;
    USE SIGNAL ;
    PORT
      LAYER M5 ;
        RECT  71.232 0 71.256 0.084 ;
    END
  END wq_mask[4]
  PIN wq_mask[50]
    DIRECTION OUTPUT ;
    USE SIGNAL ;
    PORT
      LAYER M5 ;
        RECT  95.616 0 95.64 0.084 ;
    END
  END wq_mask[50]
  PIN wq_mask[51]
    DIRECTION OUTPUT ;
    USE SIGNAL ;
    PORT
      LAYER M5 ;
        RECT  96.144 0 96.168 0.084 ;
    END
  END wq_mask[51]
  PIN wq_mask[52]
    DIRECTION OUTPUT ;
    USE SIGNAL ;
    PORT
      LAYER M5 ;
        RECT  96.672 0 96.696 0.084 ;
    END
  END wq_mask[52]
  PIN wq_mask[53]
    DIRECTION OUTPUT ;
    USE SIGNAL ;
    PORT
      LAYER M5 ;
        RECT  97.2 0 97.224 0.084 ;
    END
  END wq_mask[53]
  PIN wq_mask[54]
    DIRECTION OUTPUT ;
    USE SIGNAL ;
    PORT
      LAYER M5 ;
        RECT  97.728 0 97.752 0.084 ;
    END
  END wq_mask[54]
  PIN wq_mask[55]
    DIRECTION OUTPUT ;
    USE SIGNAL ;
    PORT
      LAYER M5 ;
        RECT  98.256 0 98.28 0.084 ;
    END
  END wq_mask[55]
  PIN wq_mask[56]
    DIRECTION OUTPUT ;
    USE SIGNAL ;
    PORT
      LAYER M5 ;
        RECT  98.784 0 98.808 0.084 ;
    END
  END wq_mask[56]
  PIN wq_mask[57]
    DIRECTION OUTPUT ;
    USE SIGNAL ;
    PORT
      LAYER M5 ;
        RECT  99.312 0 99.336 0.084 ;
    END
  END wq_mask[57]
  PIN wq_mask[58]
    DIRECTION OUTPUT ;
    USE SIGNAL ;
    PORT
      LAYER M5 ;
        RECT  99.84 0 99.864 0.084 ;
    END
  END wq_mask[58]
  PIN wq_mask[59]
    DIRECTION OUTPUT ;
    USE SIGNAL ;
    PORT
      LAYER M5 ;
        RECT  100.368 0 100.392 0.084 ;
    END
  END wq_mask[59]
  PIN wq_mask[5]
    DIRECTION OUTPUT ;
    USE SIGNAL ;
    PORT
      LAYER M5 ;
        RECT  71.76 0 71.784 0.084 ;
    END
  END wq_mask[5]
  PIN wq_mask[60]
    DIRECTION OUTPUT ;
    USE SIGNAL ;
    PORT
      LAYER M5 ;
        RECT  100.896 0 100.92 0.084 ;
    END
  END wq_mask[60]
  PIN wq_mask[61]
    DIRECTION OUTPUT ;
    USE SIGNAL ;
    PORT
      LAYER M5 ;
        RECT  101.424 0 101.448 0.084 ;
    END
  END wq_mask[61]
  PIN wq_mask[62]
    DIRECTION OUTPUT ;
    USE SIGNAL ;
    PORT
      LAYER M5 ;
        RECT  101.952 0 101.976 0.084 ;
    END
  END wq_mask[62]
  PIN wq_mask[63]
    DIRECTION OUTPUT ;
    USE SIGNAL ;
    PORT
      LAYER M5 ;
        RECT  102.48 0 102.504 0.084 ;
    END
  END wq_mask[63]
  PIN wq_mask[6]
    DIRECTION OUTPUT ;
    USE SIGNAL ;
    PORT
      LAYER M5 ;
        RECT  72.288 0 72.312 0.084 ;
    END
  END wq_mask[6]
  PIN wq_mask[7]
    DIRECTION OUTPUT ;
    USE SIGNAL ;
    PORT
      LAYER M5 ;
        RECT  72.816 0 72.84 0.084 ;
    END
  END wq_mask[7]
  PIN wq_mask[8]
    DIRECTION OUTPUT ;
    USE SIGNAL ;
    PORT
      LAYER M5 ;
        RECT  73.344 0 73.368 0.084 ;
    END
  END wq_mask[8]
  PIN wq_mask[9]
    DIRECTION OUTPUT ;
    USE SIGNAL ;
    PORT
      LAYER M5 ;
        RECT  73.872 0 73.896 0.084 ;
    END
  END wq_mask[9]
  PIN wq_v[0]
    DIRECTION OUTPUT ;
    USE SIGNAL ;
    PORT
      LAYER M5 ;
        RECT  103.008 0 103.032 0.084 ;
    END
  END wq_v[0]
  PIN wq_v[1]
    DIRECTION OUTPUT ;
    USE SIGNAL ;
    PORT
      LAYER M5 ;
        RECT  103.536 0 103.56 0.084 ;
    END
  END wq_v[1]
  PIN wq_v[2]
    DIRECTION OUTPUT ;
    USE SIGNAL ;
    PORT
      LAYER M5 ;
        RECT  104.064 0 104.088 0.084 ;
    END
  END wq_v[2]
  PIN wq_v[3]
    DIRECTION OUTPUT ;
    USE SIGNAL ;
    PORT
      LAYER M5 ;
        RECT  104.592 0 104.616 0.084 ;
    END
  END wq_v[3]
  PIN wq_v[4]
    DIRECTION OUTPUT ;
    USE SIGNAL ;
    PORT
      LAYER M5 ;
        RECT  105.12 0 105.144 0.084 ;
    END
  END wq_v[4]
  PIN wq_v[5]
    DIRECTION OUTPUT ;
    USE SIGNAL ;
    PORT
      LAYER M5 ;
        RECT  105.648 0 105.672 0.084 ;
    END
  END wq_v[5]
  PIN wq_v[6]
    DIRECTION OUTPUT ;
    USE SIGNAL ;
    PORT
      LAYER M5 ;
        RECT  106.176 0 106.2 0.084 ;
    END
  END wq_v[6]
  PIN wq_v[7]
    DIRECTION OUTPUT ;
    USE SIGNAL ;
    PORT
      LAYER M5 ;
        RECT  106.704 0 106.728 0.084 ;
    END
  END wq_v[7]
  PIN wsel[0]
    DIRECTION OUTPUT ;
    USE SIGNAL ;
    PORT
      LAYER M4 ;
        RECT  107.916 105.072 108 105.096 ;
    END
  END wsel[0]
  PIN wsel[1]
    DIRECTION OUTPUT ;
    USE SIGNAL ;
    PORT
      LAYER M4 ;
        RECT  107.916 105.84 108 105.864 ;
    END
  END wsel[1]
  PIN wsel[2]
    DIRECTION OUTPUT ;
    USE SIGNAL ;
    PORT
      LAYER M4 ;
        RECT  107.916 106.608 108 106.632 ;
    END
  END wsel[2]
  PIN VDD
    DIRECTION INOUT ;
    USE POWER ;
    PORT
      LAYER M5 ;
        RECT  105.192 2.151 105.312 105.849 ;
        RECT  99.792 2.151 99.912 105.849 ;
        RECT  94.392 2.151 94.512 105.849 ;
        RECT  88.992 2.151 89.112 105.849 ;
        RECT  83.592 2.151 83.712 105.849 ;
        RECT  78.192 2.151 78.312 105.849 ;
        RECT  72.792 2.151 72.912 105.849 ;
        RECT  67.392 2.151 67.512 105.849 ;
        RECT  61.992 2.151 62.112 105.849 ;
        RECT  56.592 2.151 56.712 105.849 ;
        RECT  51.192 2.151 51.312 105.849 ;
        RECT  45.792 2.151 45.912 105.849 ;
        RECT  40.392 2.151 40.512 105.849 ;
        RECT  34.992 2.151 35.112 105.849 ;
        RECT  29.592 2.151 29.712 105.849 ;
        RECT  24.192 2.151 24.312 105.849 ;
        RECT  18.792 2.151 18.912 105.849 ;
        RECT  13.392 2.151 13.512 105.849 ;
        RECT  7.992 2.151 8.112 105.849 ;
        RECT  2.592 2.151 2.712 105.849 ;
    END
  END VDD
  PIN VSS
    DIRECTION INOUT ;
    USE GROUND ;
    PORT
      LAYER M5 ;
        RECT  105 2.137 105.12 105.863 ;
        RECT  99.6 2.137 99.72 105.863 ;
        RECT  94.2 2.137 94.32 105.863 ;
        RECT  88.8 2.137 88.92 105.863 ;
        RECT  83.4 2.137 83.52 105.863 ;
        RECT  78 2.137 78.12 105.863 ;
        RECT  72.6 2.137 72.72 105.863 ;
        RECT  67.2 2.137 67.32 105.863 ;
        RECT  61.8 2.137 61.92 105.863 ;
        RECT  56.4 2.137 56.52 105.863 ;
        RECT  51 2.137 51.12 105.863 ;
        RECT  45.6 2.137 45.72 105.863 ;
        RECT  40.2 2.137 40.32 105.863 ;
        RECT  34.8 2.137 34.92 105.863 ;
        RECT  29.4 2.137 29.52 105.863 ;
        RECT  24 2.137 24.12 105.863 ;
        RECT  18.6 2.137 18.72 105.863 ;
        RECT  13.2 2.137 13.32 105.863 ;
        RECT  7.8 2.137 7.92 105.863 ;
        RECT  2.4 2.137 2.52 105.863 ;
    END
  END VSS
  # OT_OBS_CLOSED layer=M5 d_um=1.536 added=446
  OBS
    LAYER RVTN ;
     RECT  2.16 2.16 105.84 2.295 ;
     RECT  2.16 2.565 105.84 2.835 ;
     RECT  2.16 3.105 105.84 3.375 ;
     RECT  2.16 3.645 105.84 3.915 ;
     RECT  2.16 4.185 105.84 4.455 ;
     RECT  2.16 4.725 105.84 4.995 ;
     RECT  2.16 5.265 105.84 5.535 ;
     RECT  2.16 5.805 105.84 6.075 ;
     RECT  2.16 6.345 105.84 6.615 ;
     RECT  2.16 6.885 105.84 7.155 ;
     RECT  2.16 7.425 105.84 7.695 ;
     RECT  2.16 7.965 105.84 8.235 ;
     RECT  2.16 8.505 105.84 8.775 ;
     RECT  2.16 9.045 105.84 9.315 ;
     RECT  2.16 9.585 105.84 9.855 ;
     RECT  2.16 10.125 105.84 10.395 ;
     RECT  2.16 10.665 105.84 10.935 ;
     RECT  2.16 11.205 105.84 11.475 ;
     RECT  2.16 11.745 105.84 12.015 ;
     RECT  2.16 12.285 105.84 12.555 ;
     RECT  2.16 12.825 105.84 13.095 ;
     RECT  2.16 13.365 105.84 13.635 ;
     RECT  2.16 13.905 105.84 14.175 ;
     RECT  2.16 14.445 105.84 14.715 ;
     RECT  2.16 14.985 105.84 15.255 ;
     RECT  2.16 15.525 105.84 15.795 ;
     RECT  2.16 16.065 105.84 16.335 ;
     RECT  2.16 16.605 105.84 16.875 ;
     RECT  2.16 17.145 105.84 17.415 ;
     RECT  2.16 17.685 105.84 17.955 ;
     RECT  2.16 18.225 105.84 18.495 ;
     RECT  2.16 18.765 105.84 19.035 ;
     RECT  2.16 19.305 105.84 19.575 ;
     RECT  2.16 19.845 105.84 20.115 ;
     RECT  2.16 20.385 105.84 20.655 ;
     RECT  2.16 20.925 105.84 21.195 ;
     RECT  2.16 21.465 105.84 21.735 ;
     RECT  2.16 22.005 105.84 22.275 ;
     RECT  2.16 22.545 105.84 22.815 ;
     RECT  2.16 23.085 105.84 23.355 ;
     RECT  2.16 23.625 105.84 23.895 ;
     RECT  2.16 24.165 105.84 24.435 ;
     RECT  2.16 24.705 105.84 24.975 ;
     RECT  2.16 25.245 105.84 25.515 ;
     RECT  2.16 25.785 105.84 26.055 ;
     RECT  2.16 26.325 105.84 26.595 ;
     RECT  2.16 26.865 105.84 27.135 ;
     RECT  2.16 27.405 105.84 27.675 ;
     RECT  2.16 27.945 105.84 28.215 ;
     RECT  2.16 28.485 105.84 28.755 ;
     RECT  2.16 29.025 105.84 29.295 ;
     RECT  2.16 29.565 105.84 29.835 ;
     RECT  2.16 30.105 105.84 30.375 ;
     RECT  2.16 30.645 105.84 30.915 ;
     RECT  2.16 31.185 105.84 31.455 ;
     RECT  2.16 31.725 105.84 31.995 ;
     RECT  2.16 32.265 105.84 32.535 ;
     RECT  2.16 32.805 105.84 33.075 ;
     RECT  2.16 33.345 105.84 33.615 ;
     RECT  2.16 33.885 105.84 34.155 ;
     RECT  2.16 34.425 105.84 34.695 ;
     RECT  2.16 34.965 105.84 35.235 ;
     RECT  2.16 35.505 105.84 35.775 ;
     RECT  2.16 36.045 105.84 36.315 ;
     RECT  2.16 36.585 105.84 36.855 ;
     RECT  2.16 37.125 105.84 37.395 ;
     RECT  2.16 37.665 105.84 37.935 ;
     RECT  2.16 38.205 105.84 38.475 ;
     RECT  2.16 38.745 105.84 39.015 ;
     RECT  2.16 39.285 105.84 39.555 ;
     RECT  2.16 39.825 105.84 40.095 ;
     RECT  2.16 40.365 105.84 40.635 ;
     RECT  2.16 40.905 105.84 41.175 ;
     RECT  2.16 41.445 105.84 41.715 ;
     RECT  2.16 41.985 105.84 42.255 ;
     RECT  2.16 42.525 105.84 42.795 ;
     RECT  2.16 43.065 105.84 43.335 ;
     RECT  2.16 43.605 105.84 43.875 ;
     RECT  2.16 44.145 105.84 44.415 ;
     RECT  2.16 44.685 105.84 44.955 ;
     RECT  2.16 45.225 105.84 45.495 ;
     RECT  2.16 45.765 105.84 46.035 ;
     RECT  2.16 46.305 105.84 46.575 ;
     RECT  2.16 46.845 105.84 47.115 ;
     RECT  2.16 47.385 105.84 47.655 ;
     RECT  2.16 47.925 105.84 48.195 ;
     RECT  2.16 48.465 105.84 48.735 ;
     RECT  2.16 49.005 105.84 49.275 ;
     RECT  2.16 49.545 105.84 49.815 ;
     RECT  2.16 50.085 105.84 50.355 ;
     RECT  2.16 50.625 105.84 50.895 ;
     RECT  2.16 51.165 105.84 51.435 ;
     RECT  2.16 51.705 105.84 51.975 ;
     RECT  2.16 52.245 105.84 52.515 ;
     RECT  2.16 52.785 105.84 53.055 ;
     RECT  2.16 53.325 105.84 53.595 ;
     RECT  2.16 53.865 105.84 54.135 ;
     RECT  2.16 54.405 105.84 54.675 ;
     RECT  2.16 54.945 105.84 55.215 ;
     RECT  2.16 55.485 105.84 55.755 ;
     RECT  2.16 56.025 105.84 56.295 ;
     RECT  2.16 56.565 105.84 56.835 ;
     RECT  2.16 57.105 105.84 57.375 ;
     RECT  2.16 57.645 105.84 57.915 ;
     RECT  2.16 58.185 105.84 58.455 ;
     RECT  2.16 58.725 105.84 58.995 ;
     RECT  2.16 59.265 105.84 59.535 ;
     RECT  2.16 59.805 105.84 60.075 ;
     RECT  2.16 60.345 105.84 60.615 ;
     RECT  2.16 60.885 105.84 61.155 ;
     RECT  2.16 61.425 105.84 61.695 ;
     RECT  2.16 61.965 105.84 62.235 ;
     RECT  2.16 62.505 105.84 62.775 ;
     RECT  2.16 63.045 105.84 63.315 ;
     RECT  2.16 63.585 105.84 63.855 ;
     RECT  2.16 64.125 105.84 64.395 ;
     RECT  2.16 64.665 105.84 64.935 ;
     RECT  2.16 65.205 105.84 65.475 ;
     RECT  2.16 65.745 105.84 66.015 ;
     RECT  2.16 66.285 105.84 66.555 ;
     RECT  2.16 66.825 105.84 67.095 ;
     RECT  2.16 67.365 105.84 67.635 ;
     RECT  2.16 67.905 105.84 68.175 ;
     RECT  2.16 68.445 105.84 68.715 ;
     RECT  2.16 68.985 105.84 69.255 ;
     RECT  2.16 69.525 105.84 69.795 ;
     RECT  2.16 70.065 105.84 70.335 ;
     RECT  2.16 70.605 105.84 70.875 ;
     RECT  2.16 71.145 105.84 71.415 ;
     RECT  2.16 71.685 105.84 71.955 ;
     RECT  2.16 72.225 105.84 72.495 ;
     RECT  2.16 72.765 105.84 73.035 ;
     RECT  2.16 73.305 105.84 73.575 ;
     RECT  2.16 73.845 105.84 74.115 ;
     RECT  2.16 74.385 105.84 74.655 ;
     RECT  2.16 74.925 105.84 75.195 ;
     RECT  2.16 75.465 105.84 75.735 ;
     RECT  2.16 76.005 105.84 76.275 ;
     RECT  2.16 76.545 105.84 76.815 ;
     RECT  2.16 77.085 105.84 77.355 ;
     RECT  2.16 77.625 105.84 77.895 ;
     RECT  2.16 78.165 105.84 78.435 ;
     RECT  2.16 78.705 105.84 78.975 ;
     RECT  2.16 79.245 105.84 79.515 ;
     RECT  2.16 79.785 105.84 80.055 ;
     RECT  2.16 80.325 105.84 80.595 ;
     RECT  2.16 80.865 105.84 81.135 ;
     RECT  2.16 81.405 105.84 81.675 ;
     RECT  2.16 81.945 105.84 82.215 ;
     RECT  2.16 82.485 105.84 82.755 ;
     RECT  2.16 83.025 105.84 83.295 ;
     RECT  2.16 83.565 105.84 83.835 ;
     RECT  2.16 84.105 105.84 84.375 ;
     RECT  2.16 84.645 105.84 84.915 ;
     RECT  2.16 85.185 105.84 85.455 ;
     RECT  2.16 85.725 105.84 85.995 ;
     RECT  2.16 86.265 105.84 86.535 ;
     RECT  2.16 86.805 105.84 87.075 ;
     RECT  2.16 87.345 105.84 87.615 ;
     RECT  2.16 87.885 105.84 88.155 ;
     RECT  2.16 88.425 105.84 88.695 ;
     RECT  2.16 88.965 105.84 89.235 ;
     RECT  2.16 89.505 105.84 89.775 ;
     RECT  2.16 90.045 105.84 90.315 ;
     RECT  2.16 90.585 105.84 90.855 ;
     RECT  2.16 91.125 105.84 91.395 ;
     RECT  2.16 91.665 105.84 91.935 ;
     RECT  2.16 92.205 105.84 92.475 ;
     RECT  2.16 92.745 105.84 93.015 ;
     RECT  2.16 93.285 105.84 93.555 ;
     RECT  2.16 93.825 105.84 94.095 ;
     RECT  2.16 94.365 105.84 94.635 ;
     RECT  2.16 94.905 105.84 95.175 ;
     RECT  2.16 95.445 105.84 95.715 ;
     RECT  2.16 95.985 105.84 96.255 ;
     RECT  2.16 96.525 105.84 96.795 ;
     RECT  2.16 97.065 105.84 97.335 ;
     RECT  2.16 97.605 105.84 97.875 ;
     RECT  2.16 98.145 105.84 98.415 ;
     RECT  2.16 98.685 105.84 98.955 ;
     RECT  2.16 99.225 105.84 99.495 ;
     RECT  2.16 99.765 105.84 100.035 ;
     RECT  2.16 100.305 105.84 100.575 ;
     RECT  2.16 100.845 105.84 101.115 ;
     RECT  2.16 101.385 105.84 101.655 ;
     RECT  2.16 101.925 105.84 102.195 ;
     RECT  2.16 102.465 105.84 102.735 ;
     RECT  2.16 103.005 105.84 103.275 ;
     RECT  2.16 103.545 105.84 103.815 ;
     RECT  2.16 104.085 105.84 104.355 ;
     RECT  2.16 104.625 105.84 104.895 ;
     RECT  2.16 105.165 105.84 105.435 ;
     RECT  2.16 105.705 105.84 105.84 ;
    LAYER RVTP ;
     RECT  2.16 2.295 105.84 2.565 ;
     RECT  2.16 2.835 105.84 3.105 ;
     RECT  2.16 3.375 105.84 3.645 ;
     RECT  2.16 3.915 105.84 4.185 ;
     RECT  2.16 4.455 105.84 4.725 ;
     RECT  2.16 4.995 105.84 5.265 ;
     RECT  2.16 5.535 105.84 5.805 ;
     RECT  2.16 6.075 105.84 6.345 ;
     RECT  2.16 6.615 105.84 6.885 ;
     RECT  2.16 7.155 105.84 7.425 ;
     RECT  2.16 7.695 105.84 7.965 ;
     RECT  2.16 8.235 105.84 8.505 ;
     RECT  2.16 8.775 105.84 9.045 ;
     RECT  2.16 9.315 105.84 9.585 ;
     RECT  2.16 9.855 105.84 10.125 ;
     RECT  2.16 10.395 105.84 10.665 ;
     RECT  2.16 10.935 105.84 11.205 ;
     RECT  2.16 11.475 105.84 11.745 ;
     RECT  2.16 12.015 105.84 12.285 ;
     RECT  2.16 12.555 105.84 12.825 ;
     RECT  2.16 13.095 105.84 13.365 ;
     RECT  2.16 13.635 105.84 13.905 ;
     RECT  2.16 14.175 105.84 14.445 ;
     RECT  2.16 14.715 105.84 14.985 ;
     RECT  2.16 15.255 105.84 15.525 ;
     RECT  2.16 15.795 105.84 16.065 ;
     RECT  2.16 16.335 105.84 16.605 ;
     RECT  2.16 16.875 105.84 17.145 ;
     RECT  2.16 17.415 105.84 17.685 ;
     RECT  2.16 17.955 105.84 18.225 ;
     RECT  2.16 18.495 105.84 18.765 ;
     RECT  2.16 19.035 105.84 19.305 ;
     RECT  2.16 19.575 105.84 19.845 ;
     RECT  2.16 20.115 105.84 20.385 ;
     RECT  2.16 20.655 105.84 20.925 ;
     RECT  2.16 21.195 105.84 21.465 ;
     RECT  2.16 21.735 105.84 22.005 ;
     RECT  2.16 22.275 105.84 22.545 ;
     RECT  2.16 22.815 105.84 23.085 ;
     RECT  2.16 23.355 105.84 23.625 ;
     RECT  2.16 23.895 105.84 24.165 ;
     RECT  2.16 24.435 105.84 24.705 ;
     RECT  2.16 24.975 105.84 25.245 ;
     RECT  2.16 25.515 105.84 25.785 ;
     RECT  2.16 26.055 105.84 26.325 ;
     RECT  2.16 26.595 105.84 26.865 ;
     RECT  2.16 27.135 105.84 27.405 ;
     RECT  2.16 27.675 105.84 27.945 ;
     RECT  2.16 28.215 105.84 28.485 ;
     RECT  2.16 28.755 105.84 29.025 ;
     RECT  2.16 29.295 105.84 29.565 ;
     RECT  2.16 29.835 105.84 30.105 ;
     RECT  2.16 30.375 105.84 30.645 ;
     RECT  2.16 30.915 105.84 31.185 ;
     RECT  2.16 31.455 105.84 31.725 ;
     RECT  2.16 31.995 105.84 32.265 ;
     RECT  2.16 32.535 105.84 32.805 ;
     RECT  2.16 33.075 105.84 33.345 ;
     RECT  2.16 33.615 105.84 33.885 ;
     RECT  2.16 34.155 105.84 34.425 ;
     RECT  2.16 34.695 105.84 34.965 ;
     RECT  2.16 35.235 105.84 35.505 ;
     RECT  2.16 35.775 105.84 36.045 ;
     RECT  2.16 36.315 105.84 36.585 ;
     RECT  2.16 36.855 105.84 37.125 ;
     RECT  2.16 37.395 105.84 37.665 ;
     RECT  2.16 37.935 105.84 38.205 ;
     RECT  2.16 38.475 105.84 38.745 ;
     RECT  2.16 39.015 105.84 39.285 ;
     RECT  2.16 39.555 105.84 39.825 ;
     RECT  2.16 40.095 105.84 40.365 ;
     RECT  2.16 40.635 105.84 40.905 ;
     RECT  2.16 41.175 105.84 41.445 ;
     RECT  2.16 41.715 105.84 41.985 ;
     RECT  2.16 42.255 105.84 42.525 ;
     RECT  2.16 42.795 105.84 43.065 ;
     RECT  2.16 43.335 105.84 43.605 ;
     RECT  2.16 43.875 105.84 44.145 ;
     RECT  2.16 44.415 105.84 44.685 ;
     RECT  2.16 44.955 105.84 45.225 ;
     RECT  2.16 45.495 105.84 45.765 ;
     RECT  2.16 46.035 105.84 46.305 ;
     RECT  2.16 46.575 105.84 46.845 ;
     RECT  2.16 47.115 105.84 47.385 ;
     RECT  2.16 47.655 105.84 47.925 ;
     RECT  2.16 48.195 105.84 48.465 ;
     RECT  2.16 48.735 105.84 49.005 ;
     RECT  2.16 49.275 105.84 49.545 ;
     RECT  2.16 49.815 105.84 50.085 ;
     RECT  2.16 50.355 105.84 50.625 ;
     RECT  2.16 50.895 105.84 51.165 ;
     RECT  2.16 51.435 105.84 51.705 ;
     RECT  2.16 51.975 105.84 52.245 ;
     RECT  2.16 52.515 105.84 52.785 ;
     RECT  2.16 53.055 105.84 53.325 ;
     RECT  2.16 53.595 105.84 53.865 ;
     RECT  2.16 54.135 105.84 54.405 ;
     RECT  2.16 54.675 105.84 54.945 ;
     RECT  2.16 55.215 105.84 55.485 ;
     RECT  2.16 55.755 105.84 56.025 ;
     RECT  2.16 56.295 105.84 56.565 ;
     RECT  2.16 56.835 105.84 57.105 ;
     RECT  2.16 57.375 105.84 57.645 ;
     RECT  2.16 57.915 105.84 58.185 ;
     RECT  2.16 58.455 105.84 58.725 ;
     RECT  2.16 58.995 105.84 59.265 ;
     RECT  2.16 59.535 105.84 59.805 ;
     RECT  2.16 60.075 105.84 60.345 ;
     RECT  2.16 60.615 105.84 60.885 ;
     RECT  2.16 61.155 105.84 61.425 ;
     RECT  2.16 61.695 105.84 61.965 ;
     RECT  2.16 62.235 105.84 62.505 ;
     RECT  2.16 62.775 105.84 63.045 ;
     RECT  2.16 63.315 105.84 63.585 ;
     RECT  2.16 63.855 105.84 64.125 ;
     RECT  2.16 64.395 105.84 64.665 ;
     RECT  2.16 64.935 105.84 65.205 ;
     RECT  2.16 65.475 105.84 65.745 ;
     RECT  2.16 66.015 105.84 66.285 ;
     RECT  2.16 66.555 105.84 66.825 ;
     RECT  2.16 67.095 105.84 67.365 ;
     RECT  2.16 67.635 105.84 67.905 ;
     RECT  2.16 68.175 105.84 68.445 ;
     RECT  2.16 68.715 105.84 68.985 ;
     RECT  2.16 69.255 105.84 69.525 ;
     RECT  2.16 69.795 105.84 70.065 ;
     RECT  2.16 70.335 105.84 70.605 ;
     RECT  2.16 70.875 105.84 71.145 ;
     RECT  2.16 71.415 105.84 71.685 ;
     RECT  2.16 71.955 105.84 72.225 ;
     RECT  2.16 72.495 105.84 72.765 ;
     RECT  2.16 73.035 105.84 73.305 ;
     RECT  2.16 73.575 105.84 73.845 ;
     RECT  2.16 74.115 105.84 74.385 ;
     RECT  2.16 74.655 105.84 74.925 ;
     RECT  2.16 75.195 105.84 75.465 ;
     RECT  2.16 75.735 105.84 76.005 ;
     RECT  2.16 76.275 105.84 76.545 ;
     RECT  2.16 76.815 105.84 77.085 ;
     RECT  2.16 77.355 105.84 77.625 ;
     RECT  2.16 77.895 105.84 78.165 ;
     RECT  2.16 78.435 105.84 78.705 ;
     RECT  2.16 78.975 105.84 79.245 ;
     RECT  2.16 79.515 105.84 79.785 ;
     RECT  2.16 80.055 105.84 80.325 ;
     RECT  2.16 80.595 105.84 80.865 ;
     RECT  2.16 81.135 105.84 81.405 ;
     RECT  2.16 81.675 105.84 81.945 ;
     RECT  2.16 82.215 105.84 82.485 ;
     RECT  2.16 82.755 105.84 83.025 ;
     RECT  2.16 83.295 105.84 83.565 ;
     RECT  2.16 83.835 105.84 84.105 ;
     RECT  2.16 84.375 105.84 84.645 ;
     RECT  2.16 84.915 105.84 85.185 ;
     RECT  2.16 85.455 105.84 85.725 ;
     RECT  2.16 85.995 105.84 86.265 ;
     RECT  2.16 86.535 105.84 86.805 ;
     RECT  2.16 87.075 105.84 87.345 ;
     RECT  2.16 87.615 105.84 87.885 ;
     RECT  2.16 88.155 105.84 88.425 ;
     RECT  2.16 88.695 105.84 88.965 ;
     RECT  2.16 89.235 105.84 89.505 ;
     RECT  2.16 89.775 105.84 90.045 ;
     RECT  2.16 90.315 105.84 90.585 ;
     RECT  2.16 90.855 105.84 91.125 ;
     RECT  2.16 91.395 105.84 91.665 ;
     RECT  2.16 91.935 105.84 92.205 ;
     RECT  2.16 92.475 105.84 92.745 ;
     RECT  2.16 93.015 105.84 93.285 ;
     RECT  2.16 93.555 105.84 93.825 ;
     RECT  2.16 94.095 105.84 94.365 ;
     RECT  2.16 94.635 105.84 94.905 ;
     RECT  2.16 95.175 105.84 95.445 ;
     RECT  2.16 95.715 105.84 95.985 ;
     RECT  2.16 96.255 105.84 96.525 ;
     RECT  2.16 96.795 105.84 97.065 ;
     RECT  2.16 97.335 105.84 97.605 ;
     RECT  2.16 97.875 105.84 98.145 ;
     RECT  2.16 98.415 105.84 98.685 ;
     RECT  2.16 98.955 105.84 99.225 ;
     RECT  2.16 99.495 105.84 99.765 ;
     RECT  2.16 100.035 105.84 100.305 ;
     RECT  2.16 100.575 105.84 100.845 ;
     RECT  2.16 101.115 105.84 101.385 ;
     RECT  2.16 101.655 105.84 101.925 ;
     RECT  2.16 102.195 105.84 102.465 ;
     RECT  2.16 102.735 105.84 103.005 ;
     RECT  2.16 103.275 105.84 103.545 ;
     RECT  2.16 103.815 105.84 104.085 ;
     RECT  2.16 104.355 105.84 104.625 ;
     RECT  2.16 104.895 105.84 105.165 ;
     RECT  2.16 105.435 105.84 105.705 ;
    LAYER M1 ;
     RECT  2.16 2.151 105.84 105.849 ;
    LAYER M2 ;
     RECT  0.103 83.196 2.16 83.214 ;
     RECT  0.103 84.816 2.16 84.834 ;
     RECT  0.103 94.608 2.16 94.626 ;
     RECT  2.119 105.066 2.16 105.084 ;
     RECT  33.187 1.152 33.359 1.17 ;
     RECT  2.16 2.151 53.059 105.849 ;
     RECT  53.059 2.151 53.159 106.578 ;
     RECT  53.159 2.151 105.511 105.849 ;
     RECT  105.511 2.106 105.84 105.849 ;
     RECT  105.84 3.546 106.043 3.978 ;
     RECT  105.84 100.62 106.043 101.34 ;
     RECT  106.043 3.546 106.187 3.744 ;
     RECT  106.187 3.582 106.583 3.744 ;
     RECT  105.84 6.822 106.583 7.416 ;
     RECT  105.84 2.106 106.619 2.214 ;
     RECT  105.84 5.202 106.619 6.03 ;
     RECT  105.84 8.28 106.619 8.298 ;
     RECT  105.84 9.09 106.619 10.458 ;
     RECT  105.84 11.376 106.619 11.934 ;
     RECT  105.84 16.776 106.619 18.216 ;
     RECT  105.84 19.08 106.619 19.836 ;
     RECT  105.84 20.862 106.619 21.258 ;
     RECT  105.84 22.086 106.619 22.806 ;
     RECT  105.84 24.48 106.619 25.974 ;
     RECT  105.84 28.26 106.619 28.278 ;
     RECT  105.84 29.034 106.619 29.052 ;
     RECT  105.84 29.808 106.619 29.826 ;
     RECT  105.84 33.822 106.619 35.154 ;
     RECT  105.84 39.06 106.619 40.554 ;
     RECT  105.84 41.382 106.619 42.75 ;
     RECT  105.84 43.65 106.619 44.406 ;
     RECT  105.84 45.162 106.619 45.864 ;
     RECT  105.84 47.016 106.619 47.484 ;
     RECT  105.84 48.24 106.619 48.996 ;
     RECT  105.84 49.788 106.619 50.454 ;
     RECT  105.84 51.336 106.619 52.074 ;
     RECT  105.84 54.378 106.619 54.396 ;
     RECT  105.84 55.152 106.619 55.17 ;
     RECT  105.84 55.926 106.619 56.664 ;
     RECT  105.84 57.42 106.619 58.14 ;
     RECT  105.84 59.778 106.619 61.218 ;
     RECT  105.84 62.046 106.619 62.694 ;
     RECT  105.84 63.756 106.619 64.854 ;
     RECT  105.84 65.916 106.619 66.618 ;
     RECT  105.84 69.732 106.619 69.75 ;
     RECT  105.84 71.316 106.619 72.018 ;
     RECT  105.84 72.81 106.619 73.53 ;
     RECT  105.84 74.556 106.619 75.114 ;
     RECT  105.84 75.942 106.619 76.644 ;
     RECT  105.84 77.4 106.619 77.418 ;
     RECT  105.84 78.246 106.619 78.966 ;
     RECT  105.84 79.722 106.619 79.74 ;
     RECT  105.84 80.496 106.619 81.198 ;
     RECT  105.84 82.116 106.619 82.818 ;
     RECT  105.84 83.574 106.619 84.204 ;
     RECT  105.84 86.742 106.619 88.92 ;
     RECT  105.84 89.712 106.619 89.73 ;
     RECT  105.84 92.016 106.619 92.034 ;
     RECT  105.84 94.266 106.619 94.284 ;
     RECT  105.84 95.076 106.619 95.094 ;
     RECT  105.84 99 106.619 99.594 ;
     RECT  106.583 3.582 106.727 3.672 ;
     RECT  106.619 2.196 107.159 2.214 ;
     RECT  106.727 3.582 107.159 3.6 ;
     RECT  106.619 5.436 107.159 6.03 ;
     RECT  106.619 9.09 107.159 9.108 ;
     RECT  105.84 12.996 107.159 13.554 ;
     RECT  105.84 14.454 107.159 14.472 ;
     RECT  105.84 15.228 107.159 15.246 ;
     RECT  105.84 16.002 107.159 16.02 ;
     RECT  106.619 16.776 107.159 16.794 ;
     RECT  106.619 19.08 107.159 19.098 ;
     RECT  106.619 20.862 107.159 20.88 ;
     RECT  105.84 23.67 107.159 23.688 ;
     RECT  106.619 24.48 107.159 25.236 ;
     RECT  105.84 26.802 107.159 27.36 ;
     RECT  105.84 30.582 107.159 31.914 ;
     RECT  105.84 32.886 107.159 32.904 ;
     RECT  106.619 33.822 107.159 34.452 ;
     RECT  105.84 35.982 107.159 36 ;
     RECT  105.84 36.756 107.159 36.774 ;
     RECT  105.84 37.602 107.159 38.16 ;
     RECT  106.619 39.06 107.159 39.816 ;
     RECT  106.619 41.382 107.159 41.4 ;
     RECT  106.619 43.65 107.159 43.668 ;
     RECT  106.619 47.016 107.159 47.034 ;
     RECT  106.619 49.788 107.159 49.806 ;
     RECT  106.619 51.336 107.159 51.354 ;
     RECT  105.84 52.866 107.159 53.424 ;
     RECT  106.619 55.926 107.159 55.944 ;
     RECT  105.84 59.004 107.159 59.022 ;
     RECT  106.619 59.778 107.159 59.796 ;
     RECT  106.619 63.756 107.159 63.774 ;
     RECT  106.619 65.916 107.159 65.934 ;
     RECT  105.84 67.446 107.159 67.464 ;
     RECT  105.84 68.22 107.159 68.94 ;
     RECT  105.84 70.542 107.159 70.56 ;
     RECT  106.619 71.316 107.159 71.334 ;
     RECT  106.619 74.556 107.159 74.574 ;
     RECT  106.619 75.942 107.159 75.96 ;
     RECT  106.619 78.246 107.159 78.264 ;
     RECT  106.619 82.116 107.159 82.134 ;
     RECT  106.619 83.574 107.159 83.592 ;
     RECT  105.84 85.122 107.159 85.14 ;
     RECT  105.84 85.896 107.159 85.914 ;
     RECT  106.619 86.742 107.159 87.444 ;
     RECT  105.84 90.522 107.159 91.188 ;
     RECT  105.84 92.826 107.159 93.384 ;
     RECT  105.84 95.886 107.159 95.904 ;
     RECT  105.84 96.696 107.159 96.714 ;
     RECT  105.84 97.542 107.159 98.208 ;
     RECT  106.619 99 107.159 99.018 ;
     RECT  106.043 101.322 107.159 101.34 ;
     RECT  105.84 102.096 107.159 102.798 ;
     RECT  105.84 104.292 107.167 105.426 ;
     RECT  106.583 7.398 107.195 7.416 ;
     RECT  106.619 11.916 107.195 11.934 ;
     RECT  107.159 13.536 107.195 13.554 ;
     RECT  106.619 18.198 107.195 18.216 ;
     RECT  106.619 22.788 107.195 22.806 ;
     RECT  107.159 27.342 107.195 27.36 ;
     RECT  107.159 31.266 107.195 31.914 ;
     RECT  107.159 38.142 107.195 38.16 ;
     RECT  106.619 48.978 107.195 48.996 ;
     RECT  107.159 53.406 107.195 53.424 ;
     RECT  106.619 58.122 107.195 58.14 ;
     RECT  106.619 64.836 107.195 64.854 ;
     RECT  107.159 68.922 107.195 68.94 ;
     RECT  106.619 73.512 107.195 73.53 ;
     RECT  106.619 88.902 107.195 88.92 ;
     RECT  107.159 91.17 107.195 91.188 ;
     RECT  107.159 93.366 107.195 93.384 ;
     RECT  107.159 102.636 107.195 102.654 ;
     RECT  107.167 104.292 107.195 105.93 ;
     RECT  107.195 105.336 107.267 105.93 ;
     RECT  107.159 5.436 107.915 5.454 ;
     RECT  106.619 42.732 107.915 42.75 ;
     RECT  106.619 62.676 107.915 62.694 ;
    LAYER M3 ;
     RECT  2.808 0.091 2.826 0.139 ;
     RECT  3.924 0.091 3.942 0.523 ;
     RECT  10.764 0.091 11.394 0.523 ;
     RECT  12.384 0.091 12.402 0.523 ;
     RECT  23.688 0.091 23.706 0.523 ;
     RECT  26.82 0.091 29.178 0.523 ;
     RECT  31.14 0.091 33.642 0.523 ;
     RECT  35.208 0.091 37.818 0.523 ;
     RECT  40.86 0.091 42.606 0.523 ;
     RECT  43.668 0.091 44.73 0.523 ;
     RECT  45.972 0.091 46.89 0.523 ;
     RECT  47.736 0.091 50.562 0.523 ;
     RECT  51.624 0.091 53.19 0.523 ;
     RECT  53.928 0.091 54.378 0.523 ;
     RECT  55.512 0.091 56.034 0.523 ;
     RECT  56.88 0.091 60.75 0.523 ;
     RECT  62.172 0.091 65.898 0.523 ;
     RECT  70.524 0.091 72.27 0.523 ;
     RECT  73.332 0.091 75.654 0.523 ;
     RECT  80.46 0.091 86.238 0.523 ;
     RECT  87.3 0.091 96.138 0.523 ;
     RECT  97.236 0.091 104.238 0.523 ;
     RECT  105.444 0.091 105.678 0.523 ;
     RECT  5.472 0.091 6.102 0.571 ;
     RECT  7.092 0.091 7.11 0.571 ;
     RECT  8.748 0.091 9.666 0.571 ;
     RECT  10.764 0.523 12.402 0.571 ;
     RECT  15.66 0.091 15.93 0.571 ;
     RECT  25.308 0.091 25.614 0.571 ;
     RECT  31.14 0.523 34.038 0.571 ;
     RECT  5.472 0.571 12.402 1.099 ;
     RECT  14.076 0.091 14.49 1.099 ;
     RECT  105.444 0.523 106.722 1.387 ;
     RECT  3.888 0.523 3.942 1.723 ;
     RECT  5.472 1.099 14.49 1.723 ;
     RECT  16.74 0.091 18.198 1.723 ;
     RECT  19.296 0.091 20.034 1.723 ;
     RECT  20.844 0.091 21.402 1.723 ;
     RECT  22.14 0.091 22.698 1.723 ;
     RECT  23.688 0.523 23.994 1.723 ;
     RECT  24.732 0.571 25.614 1.723 ;
     RECT  26.82 0.523 29.826 1.723 ;
     RECT  22.14 1.723 23.994 2.143 ;
     RECT  24.732 1.723 29.826 2.143 ;
     RECT  38.7 0.091 39.978 2.143 ;
     RECT  40.86 0.523 46.89 2.143 ;
     RECT  53.928 0.523 56.034 2.143 ;
     RECT  56.772 0.523 61.11 2.143 ;
     RECT  61.956 0.523 65.898 2.143 ;
     RECT  97.236 0.523 104.562 2.143 ;
     RECT  105.444 1.387 107.154 2.143 ;
     RECT  2.376 0.139 2.826 2.191 ;
     RECT  3.888 1.723 14.49 2.191 ;
     RECT  15.264 0.571 15.93 2.191 ;
     RECT  16.74 1.723 21.402 2.191 ;
     RECT  22.14 2.143 29.826 2.191 ;
     RECT  30.636 0.571 34.038 2.191 ;
     RECT  34.776 0.523 37.818 2.191 ;
     RECT  38.7 2.143 46.89 2.191 ;
     RECT  47.736 0.523 53.19 2.191 ;
     RECT  53.928 2.143 65.898 2.191 ;
     RECT  66.672 0.091 69.786 2.191 ;
     RECT  70.524 0.523 75.654 2.191 ;
     RECT  76.392 0.091 79.686 2.191 ;
     RECT  30.636 2.191 37.818 2.227 ;
     RECT  2.34 2.191 29.826 2.263 ;
     RECT  30.636 2.227 37.926 2.263 ;
     RECT  38.7 2.191 53.19 2.263 ;
     RECT  53.928 2.191 79.686 2.263 ;
     RECT  80.46 0.523 96.138 2.263 ;
     RECT  2.34 2.263 37.962 2.371 ;
     RECT  38.7 2.263 79.686 2.371 ;
     RECT  80.46 2.263 96.246 2.371 ;
     RECT  97.236 2.143 107.154 2.371 ;
     RECT  2.304 2.371 107.154 2.569 ;
     RECT  2.232 2.569 107.154 2.795 ;
     RECT  2.232 2.795 102.762 3.065 ;
     RECT  103.5 2.795 107.154 3.065 ;
     RECT  2.232 3.065 102.726 3.107 ;
     RECT  22.284 3.107 102.726 3.299 ;
     RECT  70.128 3.299 102.726 3.335 ;
     RECT  2.232 3.107 21.438 3.407 ;
     RECT  82.44 3.335 102.726 3.437 ;
     RECT  70.128 3.335 81.666 3.569 ;
     RECT  82.44 3.437 84.294 3.569 ;
     RECT  70.128 3.569 81.342 3.605 ;
     RECT  103.536 3.065 107.154 3.605 ;
     RECT  2.304 3.407 21.438 3.641 ;
     RECT  103.536 3.605 106.722 3.677 ;
     RECT  85.068 3.437 102.726 3.749 ;
     RECT  103.536 3.677 106.578 3.749 ;
     RECT  22.284 3.299 69.318 3.839 ;
     RECT  85.068 3.749 87.642 3.839 ;
     RECT  88.596 3.749 102.726 3.839 ;
     RECT  64.8 3.839 69.174 3.875 ;
     RECT  74.88 3.605 81.342 3.875 ;
     RECT  85.068 3.839 86.67 3.875 ;
     RECT  88.596 3.839 91.134 3.875 ;
     RECT  80.712 3.875 81.342 3.911 ;
     RECT  90.936 3.875 91.134 3.911 ;
     RECT  99.615 3.839 102.726 3.911 ;
     RECT  22.284 3.839 64.026 3.917 ;
     RECT  96.012 3.839 96.21 3.917 ;
     RECT  22.284 3.917 59.202 3.947 ;
     RECT  74.88 3.875 79.65 3.947 ;
     RECT  88.596 3.875 89.622 3.947 ;
     RECT  101.232 3.911 102.726 3.955 ;
     RECT  103.536 3.749 106.038 3.955 ;
     RECT  2.304 3.641 8.838 3.965 ;
     RECT  9.576 3.641 21.438 3.965 ;
     RECT  9.612 3.965 21.438 3.983 ;
     RECT  22.284 3.947 58.95 3.983 ;
     RECT  101.232 3.955 106.038 3.983 ;
     RECT  70.128 3.605 74.106 4.081 ;
     RECT  2.304 3.965 6.066 4.109 ;
     RECT  9.612 3.983 10.962 4.109 ;
     RECT  11.988 3.983 21.438 4.109 ;
     RECT  57.96 3.983 58.95 4.109 ;
     RECT  60.228 3.917 64.026 4.109 ;
     RECT  64.8 3.875 69.03 4.109 ;
     RECT  69.912 4.081 74.106 4.109 ;
     RECT  81.18 3.911 81.342 4.109 ;
     RECT  82.44 3.569 83.697 4.109 ;
     RECT  87.516 3.839 87.642 4.109 ;
     RECT  88.668 3.947 89.622 4.109 ;
     RECT  90.936 3.911 91.098 4.109 ;
     RECT  91.872 3.839 94.986 4.109 ;
     RECT  97.236 3.839 97.902 4.109 ;
     RECT  90.936 4.109 90.954 4.115 ;
     RECT  15.624 4.109 21.438 4.123 ;
     RECT  22.284 3.983 57.042 4.123 ;
     RECT  15.624 4.123 57.042 4.145 ;
     RECT  58.428 4.109 58.95 4.145 ;
     RECT  60.228 4.109 63.954 4.145 ;
     RECT  74.88 3.947 79.182 4.145 ;
     RECT  81.18 4.109 81.198 4.145 ;
     RECT  87.516 4.109 87.534 4.145 ;
     RECT  88.815 4.109 89.622 4.145 ;
     RECT  97.236 4.109 97.254 4.145 ;
     RECT  9.756 4.109 10.962 4.157 ;
     RECT  85.068 3.875 86.094 4.171 ;
     RECT  69.912 4.109 73.89 4.181 ;
     RECT  15.624 4.145 17.73 4.205 ;
     RECT  58.428 4.145 58.914 4.217 ;
     RECT  88.815 4.145 89.586 4.217 ;
     RECT  6.84 3.965 8.838 4.253 ;
     RECT  15.696 4.205 17.73 4.253 ;
     RECT  98.676 3.839 98.694 4.253 ;
     RECT  74.88 4.145 76.734 4.289 ;
     RECT  92.484 4.109 94.986 4.289 ;
     RECT  84.672 4.171 86.094 4.301 ;
     RECT  101.232 3.983 105.714 4.312 ;
     RECT  2.376 4.109 6.066 4.379 ;
     RECT  6.84 4.253 8.097 4.379 ;
     RECT  10.44 4.157 10.962 4.379 ;
     RECT  15.768 4.253 17.73 4.379 ;
     RECT  58.428 4.217 58.734 4.379 ;
     RECT  65.052 4.109 68.67 4.379 ;
     RECT  70.2 4.181 72.954 4.379 ;
     RECT  74.88 4.289 75.726 4.379 ;
     RECT  77.544 4.145 79.182 4.379 ;
     RECT  84.708 4.301 86.094 4.379 ;
     RECT  93.78 4.289 94.986 4.379 ;
     RECT  101.664 4.312 105.714 4.379 ;
     RECT  84.816 4.379 84.834 4.397 ;
     RECT  70.2 4.379 71.406 4.402 ;
     RECT  2.412 4.379 6.066 4.415 ;
     RECT  10.512 4.379 10.962 4.415 ;
     RECT  18.576 4.145 57.042 4.415 ;
     RECT  66.42 4.379 68.67 4.415 ;
     RECT  74.88 4.379 75.582 4.415 ;
     RECT  10.584 4.415 10.962 4.451 ;
     RECT  18.576 4.415 48.222 4.451 ;
     RECT  65.088 4.379 65.43 4.451 ;
     RECT  77.544 4.379 78.426 4.451 ;
     RECT  92.484 4.289 92.538 4.451 ;
     RECT  93.78 4.379 94.698 4.451 ;
     RECT  82.656 4.109 83.697 4.487 ;
     RECT  85.572 4.379 86.094 4.487 ;
     RECT  92.52 4.451 92.538 4.487 ;
     RECT  66.528 4.415 68.562 4.493 ;
     RECT  102.78 4.379 105.642 4.493 ;
     RECT  6.84 4.379 6.894 4.523 ;
     RECT  10.692 4.451 10.962 4.523 ;
     RECT  49.032 4.415 55.422 4.523 ;
     RECT  77.544 4.451 78.39 4.523 ;
     RECT  82.692 4.487 83.697 4.523 ;
     RECT  88.815 4.217 89.55 4.523 ;
     RECT  101.664 4.379 101.898 4.523 ;
     RECT  74.88 4.415 75.114 4.531 ;
     RECT  8.82 4.253 8.838 4.541 ;
     RECT  18.576 4.451 47.25 4.541 ;
     RECT  60.912 4.145 63.954 4.541 ;
     RECT  10.836 4.523 10.926 4.559 ;
     RECT  49.032 4.523 53.442 4.559 ;
     RECT  54.828 4.523 55.422 4.559 ;
     RECT  58.464 4.379 58.734 4.559 ;
     RECT  60.912 4.541 62.73 4.559 ;
     RECT  66.528 4.493 67.497 4.559 ;
     RECT  68.544 4.493 68.562 4.559 ;
     RECT  72.396 4.379 72.954 4.559 ;
     RECT  74.664 4.531 75.114 4.559 ;
     RECT  16.272 4.379 17.73 4.649 ;
     RECT  18.576 4.541 18.99 4.649 ;
     RECT  20.052 4.541 47.25 4.649 ;
     RECT  49.068 4.559 53.442 4.649 ;
     RECT  56.415 4.415 57.042 4.649 ;
     RECT  63.468 4.541 63.954 4.649 ;
     RECT  70.2 4.402 71.262 4.649 ;
     RECT  78.015 4.523 78.39 4.649 ;
     RECT  79.164 4.379 79.182 4.649 ;
     RECT  85.572 4.487 85.662 4.649 ;
     RECT  103.608 4.493 105.642 4.649 ;
     RECT  54.828 4.559 55.386 4.685 ;
     RECT  70.2 4.649 70.722 4.685 ;
     RECT  85.572 4.649 85.59 4.685 ;
     RECT  60.912 4.559 62.37 4.721 ;
     RECT  11.988 4.109 14.85 4.733 ;
     RECT  18.615 4.649 18.99 4.733 ;
     RECT  20.052 4.649 42.786 4.733 ;
     RECT  49.068 4.649 52.542 4.733 ;
     RECT  63.936 4.649 63.954 4.757 ;
     RECT  93.78 4.451 94.626 4.781 ;
     RECT  2.412 4.415 5.634 4.793 ;
     RECT  6.84 4.523 6.858 4.793 ;
     RECT  13.215 4.733 14.85 4.793 ;
     RECT  16.344 4.649 17.73 4.793 ;
     RECT  50.364 4.733 52.542 4.793 ;
     RECT  74.664 4.559 74.682 4.793 ;
     RECT  11.988 4.733 12.006 4.829 ;
     RECT  20.052 4.733 37.53 4.829 ;
     RECT  16.344 4.793 17.118 4.919 ;
     RECT  20.808 4.829 37.53 4.919 ;
     RECT  38.376 4.733 42.786 4.919 ;
     RECT  50.436 4.793 52.542 4.919 ;
     RECT  53.352 4.649 53.442 4.919 ;
     RECT  58.716 4.559 58.734 4.919 ;
     RECT  61.02 4.721 62.37 4.919 ;
     RECT  65.412 4.451 65.43 4.919 ;
     RECT  73.872 4.181 73.89 4.919 ;
     RECT  102.78 4.493 102.798 4.919 ;
     RECT  7.704 4.379 8.097 4.925 ;
     RECT  94.215 4.781 94.626 4.925 ;
     RECT  2.412 4.793 4.806 4.928 ;
     RECT  20.808 4.919 28.242 4.928 ;
     RECT  43.56 4.649 47.25 4.955 ;
     RECT  61.02 4.919 62.154 4.955 ;
     RECT  103.608 4.649 105.354 4.955 ;
     RECT  29.088 4.919 37.53 4.973 ;
     RECT  2.412 4.928 3.87 4.991 ;
     RECT  4.788 4.928 4.806 4.991 ;
     RECT  16.488 4.919 16.506 4.991 ;
     RECT  36.648 4.973 37.53 4.991 ;
     RECT  29.088 4.973 35.91 5.021 ;
     RECT  98.604 4.891 98.622 5.021 ;
     RECT  36.972 4.991 37.53 5.027 ;
     RECT  46.692 4.955 47.25 5.027 ;
     RECT  50.508 4.919 52.542 5.027 ;
     RECT  20.808 4.928 21.582 5.063 ;
     RECT  38.376 4.919 42.678 5.063 ;
     RECT  46.728 5.027 47.25 5.063 ;
     RECT  38.376 5.063 41.922 5.069 ;
     RECT  52.38 5.027 52.542 5.069 ;
     RECT  72.504 4.559 72.954 5.071 ;
     RECT  29.088 5.021 35.766 5.072 ;
     RECT  18.615 4.733 18.954 5.099 ;
     RECT  22.356 4.928 28.242 5.099 ;
     RECT  29.088 5.072 35.694 5.099 ;
     RECT  50.616 5.027 51.297 5.099 ;
     RECT  52.416 5.069 52.542 5.099 ;
     RECT  101.88 4.523 101.898 5.099 ;
     RECT  2.412 4.991 3.546 5.117 ;
     RECT  5.544 4.793 5.634 5.117 ;
     RECT  2.415 5.117 3.546 5.189 ;
     RECT  61.632 4.955 62.154 5.189 ;
     RECT  22.392 5.099 27.846 5.225 ;
     RECT  22.392 5.225 27.594 5.261 ;
     RECT  29.124 5.099 35.694 5.261 ;
     RECT  106.596 5.197 106.614 5.261 ;
     RECT  13.215 4.793 14.13 5.297 ;
     RECT  47.232 5.063 47.25 5.305 ;
     RECT  48.024 4.451 48.222 5.305 ;
     RECT  20.052 4.829 20.07 5.309 ;
     RECT  13.215 5.297 13.698 5.369 ;
     RECT  22.392 5.261 24.498 5.369 ;
     RECT  29.124 5.261 35.586 5.369 ;
     RECT  70.38 4.685 70.722 5.369 ;
     RECT  85.536 5.131 85.554 5.419 ;
     RECT  2.415 5.189 3.474 5.459 ;
     RECT  20.952 5.063 21.582 5.459 ;
     RECT  29.304 5.369 35.586 5.459 ;
     RECT  107.892 4.459 107.91 5.459 ;
     RECT  5.544 5.117 5.562 5.495 ;
     RECT  20.988 5.459 21.582 5.495 ;
     RECT  29.415 5.459 35.586 5.495 ;
     RECT  52.524 5.099 52.542 5.495 ;
     RECT  72.504 5.071 73.422 5.495 ;
     RECT  22.392 5.369 23.094 5.531 ;
     RECT  25.524 5.261 27.594 5.531 ;
     RECT  29.415 5.495 33.822 5.531 ;
     RECT  20.988 5.495 21.15 5.567 ;
     RECT  26.64 5.531 27.27 5.567 ;
     RECT  25.524 5.531 25.542 5.603 ;
     RECT  29.415 5.531 32.31 5.603 ;
     RECT  6.552 4.891 6.57 5.611 ;
     RECT  47.232 5.305 48.222 5.611 ;
     RECT  49.068 4.733 49.59 5.611 ;
     RECT  20.988 5.567 21.006 5.639 ;
     RECT  22.392 5.531 22.842 5.639 ;
     RECT  27.252 5.567 27.27 5.639 ;
     RECT  30.492 5.603 32.31 5.639 ;
     RECT  34.815 5.495 35.586 5.639 ;
     RECT  42.66 5.063 42.678 5.707 ;
     RECT  43.56 4.955 45.897 5.707 ;
     RECT  85.392 5.419 85.554 5.707 ;
     RECT  103.608 4.955 105.297 5.707 ;
     RECT  38.412 5.069 41.922 5.729 ;
     RECT  42.66 5.707 45.897 5.729 ;
     RECT  47.232 5.611 49.59 5.729 ;
     RECT  54.828 4.685 54.846 5.729 ;
     RECT  38.412 5.729 41.562 5.741 ;
     RECT  39.564 5.741 41.562 5.789 ;
     RECT  47.232 5.729 47.25 5.803 ;
     RECT  72.615 5.495 73.422 5.809 ;
     RECT  30.492 5.639 30.654 5.837 ;
     RECT  48.636 5.729 48.942 5.837 ;
     RECT  46.944 5.803 47.25 5.843 ;
     RECT  30.528 5.837 30.654 5.873 ;
     RECT  31.5 5.639 32.238 5.873 ;
     RECT  36.972 5.027 37.386 5.881 ;
     RECT  38.412 5.741 38.682 5.881 ;
     RECT  33.084 5.531 33.822 5.909 ;
     RECT  61.815 5.189 62.154 5.909 ;
     RECT  70.704 5.369 70.722 5.909 ;
     RECT  72.615 5.809 73.566 5.909 ;
     RECT  31.932 5.873 32.238 5.999 ;
     RECT  72.615 5.909 73.35 5.999 ;
     RECT  103.428 5.707 105.297 5.999 ;
     RECT  72.615 5.999 73.278 6.035 ;
     RECT  107.136 5.995 107.154 6.035 ;
     RECT  32.148 5.999 32.238 6.071 ;
     RECT  36.972 5.881 38.682 6.077 ;
     RECT  32.22 6.071 32.238 6.107 ;
     RECT  36.972 6.077 37.926 6.107 ;
     RECT  33.228 5.909 33.822 6.125 ;
     RECT  85.392 5.707 85.986 6.269 ;
     RECT  103.5 5.999 105.297 6.269 ;
     RECT  85.032 6.385 85.338 6.461 ;
     RECT  36.972 6.107 37.278 6.539 ;
     RECT  53.676 6.283 53.694 6.539 ;
     RECT  54.612 5.845 54.63 6.539 ;
     RECT  39.744 5.789 41.562 6.547 ;
     RECT  39.744 6.547 41.922 6.691 ;
     RECT  42.66 5.729 43.038 6.691 ;
     RECT  48.78 5.837 48.942 6.691 ;
     RECT  2.415 5.459 2.697 6.715 ;
     RECT  36 6.091 36.018 6.781 ;
     RECT  36.972 6.539 37.134 6.781 ;
     RECT  44.172 5.729 45.897 6.781 ;
     RECT  47.088 5.843 47.25 6.808 ;
     RECT  36 6.781 37.134 6.809 ;
     RECT  38.664 6.077 38.682 6.809 ;
     RECT  43.884 6.781 45.897 6.809 ;
     RECT  85.212 6.461 85.338 6.809 ;
     RECT  2.304 6.715 2.697 6.845 ;
     RECT  36 6.809 37.062 6.845 ;
     RECT  104.436 6.269 105.297 6.845 ;
     RECT  106.56 6.763 106.578 6.845 ;
     RECT  6.48 5.611 6.57 6.859 ;
     RECT  39.744 6.691 43.038 6.925 ;
     RECT  43.884 6.809 44.874 6.925 ;
     RECT  2.415 6.845 2.697 6.961 ;
     RECT  3.456 5.459 3.474 6.961 ;
     RECT  47.088 6.808 47.718 6.961 ;
     RECT  48.744 6.691 48.942 6.961 ;
     RECT  2.415 6.961 3.474 7.079 ;
     RECT  39.744 6.925 44.874 7.079 ;
     RECT  47.088 6.961 48.942 7.079 ;
     RECT  53.82 6.691 53.946 7.079 ;
     RECT  85.212 6.809 85.266 7.079 ;
     RECT  5.76 6.859 6.57 7.115 ;
     RECT  47.088 7.079 48.69 7.115 ;
     RECT  39.744 7.079 44.766 7.187 ;
     RECT  6.48 7.115 6.57 7.231 ;
     RECT  25.596 7.321 25.614 7.339 ;
     RECT  38.88 6.961 39.006 7.339 ;
     RECT  39.744 7.187 42.174 7.339 ;
     RECT  36.288 6.845 37.062 7.349 ;
     RECT  38.88 7.339 42.174 7.349 ;
     RECT  47.088 7.115 48.114 7.349 ;
     RECT  53.82 7.079 53.91 7.349 ;
     RECT  25.236 7.339 25.614 7.373 ;
     RECT  25.236 7.373 25.254 7.385 ;
     RECT  36.288 7.349 36.99 7.385 ;
     RECT  43.02 7.187 44.766 7.421 ;
     RECT  83.415 4.523 83.697 7.435 ;
     RECT  107.172 7.393 107.19 7.565 ;
     RECT  36.288 7.385 36.306 7.619 ;
     RECT  85.248 7.079 85.266 7.619 ;
     RECT  47.088 7.349 48.006 7.735 ;
     RECT  38.88 7.349 42.03 7.799 ;
     RECT  38.88 7.799 41.094 7.819 ;
     RECT  83.415 7.435 84.186 7.861 ;
     RECT  36.144 7.735 36.162 7.889 ;
     RECT  53.892 7.349 53.91 7.889 ;
     RECT  85.32 7.735 85.338 7.889 ;
     RECT  43.02 7.421 43.038 7.915 ;
     RECT  45.615 6.809 45.897 8.005 ;
     RECT  45.615 8.005 46.17 8.011 ;
     RECT  46.98 7.735 48.006 8.011 ;
     RECT  42.768 7.915 43.038 8.033 ;
     RECT  41.868 7.799 42.03 8.159 ;
     RECT  43.776 7.421 44.766 8.159 ;
     RECT  53.928 8.005 53.946 8.159 ;
     RECT  52.776 8.155 52.794 8.195 ;
     RECT  42.876 8.033 43.038 8.203 ;
     RECT  43.776 8.159 44.694 8.203 ;
     RECT  2.415 7.079 2.697 8.299 ;
     RECT  45.615 8.011 48.006 8.303 ;
     RECT  37.8 8.299 37.818 8.311 ;
     RECT  38.772 7.819 41.094 8.311 ;
     RECT  106.596 8.275 106.614 8.333 ;
     RECT  7.815 4.925 8.097 8.401 ;
     RECT  41.868 8.159 41.886 8.429 ;
     RECT  47.988 8.303 48.006 8.429 ;
     RECT  53.028 8.311 53.154 8.429 ;
     RECT  2.304 8.299 2.697 8.465 ;
     RECT  42.876 8.203 44.694 8.699 ;
     RECT  45.615 8.303 47.106 8.699 ;
     RECT  37.8 8.311 41.094 8.969 ;
     RECT  107.136 9.067 107.154 9.113 ;
     RECT  45.615 8.699 46.89 9.121 ;
     RECT  51.015 5.099 51.297 9.211 ;
     RECT  36.108 7.933 36.126 9.239 ;
     RECT  37.8 8.969 40.95 9.239 ;
     RECT  53.028 8.429 53.046 9.239 ;
     RECT  51.015 9.211 51.894 9.275 ;
     RECT  36 9.355 36.018 9.509 ;
     RECT  37.8 9.239 40.914 9.545 ;
     RECT  42.156 9.481 42.174 9.625 ;
     RECT  42.912 8.699 44.118 9.625 ;
     RECT  34.815 5.639 35.097 9.661 ;
     RECT  37.8 9.545 38.178 9.661 ;
     RECT  34.815 9.661 35.262 9.779 ;
     RECT  45.144 9.121 46.89 9.779 ;
     RECT  52.092 9.391 52.218 9.779 ;
     RECT  2.415 8.465 2.697 9.931 ;
     RECT  37.728 9.661 38.178 9.931 ;
     RECT  42.048 9.625 42.174 9.931 ;
     RECT  42.912 9.625 44.19 9.931 ;
     RECT  4.428 9.979 4.446 10.049 ;
     RECT  39.132 9.545 40.914 10.049 ;
     RECT  45.144 9.779 46.17 10.049 ;
     RECT  63.36 9.787 63.378 10.049 ;
     RECT  2.304 9.931 2.697 10.085 ;
     RECT  45.144 10.049 46.062 10.085 ;
     RECT  37.044 9.931 38.178 10.165 ;
     RECT  39.636 10.049 40.914 10.171 ;
     RECT  45.144 10.085 46.026 10.201 ;
     RECT  42.048 9.931 44.19 10.205 ;
     RECT  51.015 9.275 51.297 10.291 ;
     RECT  45 10.201 46.026 10.319 ;
     RECT  36.648 10.165 38.178 10.327 ;
     RECT  49.428 10.315 49.446 10.355 ;
     RECT  42.156 10.205 44.19 10.471 ;
     RECT  45 10.319 45.954 10.471 ;
     RECT  42.156 10.471 45.954 10.589 ;
     RECT  39.636 10.171 41.058 10.625 ;
     RECT  106.596 9.823 106.614 10.637 ;
     RECT  50.976 10.291 51.297 10.733 ;
     RECT  33.948 10.705 33.966 10.741 ;
     RECT  34.815 9.779 35.154 10.741 ;
     RECT  39.672 10.625 41.058 10.741 ;
     RECT  51.015 10.733 51.297 10.741 ;
     RECT  52.092 9.779 52.182 10.741 ;
     RECT  36.648 10.327 38.898 10.843 ;
     RECT  36.468 10.843 38.898 10.859 ;
     RECT  42.192 10.589 45.954 10.859 ;
     RECT  51.015 10.741 52.182 10.859 ;
     RECT  51.015 10.859 52.038 10.895 ;
     RECT  33.948 10.741 35.154 11.129 ;
     RECT  34.815 11.129 35.154 11.281 ;
     RECT  36.468 10.859 37.062 11.281 ;
     RECT  39.672 10.741 41.382 11.399 ;
     RECT  43.92 10.859 45.954 11.399 ;
     RECT  106.596 11.365 106.614 11.405 ;
     RECT  37.836 10.859 38.898 11.435 ;
     RECT  38.52 11.435 38.898 11.551 ;
     RECT  2.415 10.085 2.697 11.563 ;
     RECT  38.52 11.551 39.006 11.669 ;
     RECT  42.192 10.859 43.146 11.669 ;
     RECT  43.92 11.399 45.897 11.669 ;
     RECT  51.015 10.895 51.354 11.669 ;
     RECT  2.412 11.563 2.697 11.705 ;
     RECT  50.148 11.659 50.166 11.705 ;
     RECT  39.852 11.399 41.382 11.785 ;
     RECT  32.76 11.419 32.778 11.821 ;
     RECT  33.912 11.281 33.93 11.821 ;
     RECT  34.815 11.281 35.262 11.821 ;
     RECT  36.072 11.281 37.062 11.821 ;
     RECT  51.015 11.669 51.297 11.821 ;
     RECT  5.4 10.201 5.418 11.899 ;
     RECT  33.768 11.821 33.93 11.939 ;
     RECT  38.52 11.669 38.862 11.939 ;
     RECT  43.92 11.669 44.874 11.939 ;
     RECT  5.04 11.899 5.418 11.947 ;
     RECT  6.48 7.231 6.714 11.947 ;
     RECT  5.04 11.947 6.714 11.975 ;
     RECT  33.768 11.939 33.786 11.975 ;
     RECT  34.815 11.821 37.062 12.091 ;
     RECT  107.172 11.911 107.19 12.173 ;
     RECT  32.76 11.821 32.994 12.209 ;
     RECT  38.592 11.939 38.79 12.209 ;
     RECT  42.732 11.669 43.146 12.209 ;
     RECT  43.92 11.939 44.73 12.209 ;
     RECT  34.815 12.091 37.746 12.245 ;
     RECT  43.92 12.209 43.974 12.245 ;
     RECT  38.664 12.209 38.79 12.281 ;
     RECT  34.815 12.245 36.234 12.317 ;
     RECT  36.972 12.245 37.746 12.389 ;
     RECT  39.852 11.785 41.778 12.451 ;
     RECT  42.732 12.209 42.966 12.451 ;
     RECT  38.7 12.281 38.79 12.479 ;
     RECT  39.852 12.451 42.966 12.515 ;
     RECT  50.472 11.821 51.297 12.595 ;
     RECT  38.7 12.479 38.718 12.749 ;
     RECT  43.956 12.245 43.974 12.749 ;
     RECT  44.712 12.209 44.73 12.749 ;
     RECT  37.008 12.389 37.746 12.901 ;
     RECT  107.136 12.907 107.154 13.019 ;
     RECT  34.815 12.317 35.982 13.051 ;
     RECT  34.812 13.051 35.982 13.171 ;
     RECT  37.008 12.901 37.818 13.171 ;
     RECT  2.415 11.705 2.697 13.195 ;
     RECT  32.652 12.361 32.67 13.289 ;
     RECT  36.864 13.171 37.818 13.289 ;
     RECT  44.748 12.865 44.766 13.289 ;
     RECT  2.34 13.195 2.697 13.325 ;
     RECT  49.284 13.291 49.302 13.331 ;
     RECT  31.536 13.243 31.554 13.441 ;
     RECT  34.272 13.171 35.982 13.441 ;
     RECT  36.864 13.289 37.674 13.441 ;
     RECT  39.852 12.515 40.554 13.441 ;
     RECT  41.472 12.515 42.966 13.441 ;
     RECT  50.328 12.595 51.297 13.441 ;
     RECT  34.272 13.441 37.674 13.559 ;
     RECT  49.5 13.441 51.297 13.559 ;
     RECT  54 13.099 54.018 13.559 ;
     RECT  34.272 13.559 37.638 13.595 ;
     RECT  49.5 13.559 50.274 13.595 ;
     RECT  5.4 11.975 6.714 13.603 ;
     RECT  7.524 8.401 8.097 13.603 ;
     RECT  31.536 13.441 31.77 13.661 ;
     RECT  53.64 13.627 53.658 13.667 ;
     RECT  107.172 13.531 107.19 13.709 ;
     RECT  31.572 13.661 31.77 13.829 ;
     RECT  39.852 13.441 43.794 13.829 ;
     RECT  49.5 13.595 49.626 13.829 ;
     RECT  31.572 13.829 31.626 14.099 ;
     RECT  34.272 13.595 36.486 14.099 ;
     RECT  37.296 13.595 37.638 14.099 ;
     RECT  39.852 13.829 43.47 14.099 ;
     RECT  39.852 14.099 41.706 14.203 ;
     RECT  39.348 14.203 41.706 14.243 ;
     RECT  37.62 14.099 37.638 14.369 ;
     RECT  42.552 14.099 42.714 14.369 ;
     RECT  107.136 14.44 107.154 14.477 ;
     RECT  42.552 14.369 42.678 14.513 ;
     RECT  36.324 14.099 36.486 14.521 ;
     RECT  34.272 14.099 35.586 14.647 ;
     RECT  30.78 13.627 30.798 14.765 ;
     RECT  48.384 14.587 48.402 14.791 ;
     RECT  49.5 13.829 49.518 14.791 ;
     RECT  2.415 13.325 2.697 14.827 ;
     RECT  30.456 14.827 30.618 14.909 ;
     RECT  31.572 14.099 31.59 14.909 ;
     RECT  36.324 14.521 36.774 14.909 ;
     RECT  43.452 14.099 43.47 14.909 ;
     RECT  48.384 14.791 49.518 14.909 ;
     RECT  2.304 14.827 2.697 14.945 ;
     RECT  48.384 14.909 49.41 14.945 ;
     RECT  34.128 14.647 35.586 15.025 ;
     RECT  17.064 14.827 17.082 15.061 ;
     RECT  39.528 14.243 41.706 15.061 ;
     RECT  42.552 14.513 42.57 15.061 ;
     RECT  13.215 5.369 13.497 15.151 ;
     RECT  16.884 15.061 17.082 15.151 ;
     RECT  16.848 15.151 17.082 15.179 ;
     RECT  36.324 14.909 36.666 15.179 ;
     RECT  39.528 15.061 42.57 15.179 ;
     RECT  48.384 14.945 48.726 15.179 ;
     RECT  13.104 15.151 13.497 15.197 ;
     RECT  16.848 15.179 16.902 15.197 ;
     RECT  48.384 15.179 48.582 15.215 ;
     RECT  107.136 15.211 107.154 15.251 ;
     RECT  47.448 15.163 47.466 15.293 ;
     RECT  33.912 15.025 35.586 15.331 ;
     RECT  36.324 15.179 36.63 15.331 ;
     RECT  38.376 15.163 38.394 15.331 ;
     RECT  39.528 15.179 40.698 15.331 ;
     RECT  48.384 15.215 48.546 15.331 ;
     RECT  16.884 15.197 16.902 15.341 ;
     RECT  38.376 15.331 40.698 15.341 ;
     RECT  38.7 15.341 40.698 15.449 ;
     RECT  41.58 15.179 42.498 15.449 ;
     RECT  38.7 15.449 40.497 15.485 ;
     RECT  33.588 15.331 36.63 15.601 ;
     RECT  33.408 15.601 36.63 15.719 ;
     RECT  47.628 15.331 48.546 15.719 ;
     RECT  33.408 15.719 36.486 15.755 ;
     RECT  48.42 15.719 48.438 15.755 ;
     RECT  33.408 15.755 36.234 15.835 ;
     RECT  33.264 15.835 36.234 15.989 ;
     RECT  107.136 15.979 107.154 16.025 ;
     RECT  33.264 15.989 36.126 16.105 ;
     RECT  41.58 15.449 42.174 16.105 ;
     RECT  30.6 14.909 30.618 16.259 ;
     RECT  47.628 15.719 47.682 16.259 ;
     RECT  29.415 5.603 29.697 16.375 ;
     RECT  38.7 15.485 38.718 16.375 ;
     RECT  39.78 15.485 40.497 16.405 ;
     RECT  33.228 16.105 36.126 16.411 ;
     RECT  39.78 16.405 40.626 16.411 ;
     RECT  41.544 16.105 42.174 16.411 ;
     RECT  45.615 11.669 45.897 16.459 ;
     RECT  38.556 16.375 38.718 16.501 ;
     RECT  39.78 16.411 42.174 16.501 ;
     RECT  45.615 16.459 46.566 16.501 ;
     RECT  33.192 16.411 36.126 16.529 ;
     RECT  38.556 16.501 42.174 16.529 ;
     RECT  47.664 16.259 47.682 16.529 ;
     RECT  2.415 14.945 2.697 16.537 ;
     RECT  3.456 7.079 3.474 16.537 ;
     RECT  33.192 16.529 35.586 16.645 ;
     RECT  4.428 16.747 4.446 16.799 ;
     RECT  38.556 16.529 41.778 16.799 ;
     RECT  107.136 16.747 107.154 16.799 ;
     RECT  2.415 16.537 3.474 16.835 ;
     RECT  32.184 16.555 32.202 17.041 ;
     RECT  45.615 16.501 46.89 17.069 ;
     RECT  29.415 16.375 30.258 17.455 ;
     RECT  32.184 17.041 32.382 17.455 ;
     RECT  33.156 16.645 35.586 17.455 ;
     RECT  37.476 17.467 37.494 17.491 ;
     RECT  38.556 16.799 41.706 17.491 ;
     RECT  31.896 17.455 35.586 17.501 ;
     RECT  106.596 17.455 106.614 17.549 ;
     RECT  37.476 17.491 37.746 17.581 ;
     RECT  38.484 17.491 41.706 17.581 ;
     RECT  29.088 17.455 30.258 17.609 ;
     RECT  31.932 17.501 35.586 17.609 ;
     RECT  37.476 17.581 41.706 17.609 ;
     RECT  45.615 17.069 46.782 17.611 ;
     RECT  29.088 17.609 30.042 17.645 ;
     RECT  34.416 17.609 35.097 17.645 ;
     RECT  37.476 17.609 41.634 17.645 ;
     RECT  45.612 17.611 46.782 17.651 ;
     RECT  37.476 17.645 41.058 17.693 ;
     RECT  31.932 17.609 33.678 17.879 ;
     RECT  45.615 17.651 46.782 17.915 ;
     RECT  45.615 17.915 46.602 17.987 ;
     RECT  2.415 16.835 2.697 18.091 ;
     RECT  45.615 17.987 45.954 18.149 ;
     RECT  107.172 18.193 107.19 18.317 ;
     RECT  5.4 13.603 8.097 18.379 ;
     RECT  37.512 17.693 41.058 18.419 ;
     RECT  2.304 18.091 2.697 18.455 ;
     RECT  5.004 18.379 8.097 18.455 ;
     RECT  34.632 17.645 35.097 18.565 ;
     RECT  36.504 17.467 36.522 18.565 ;
     RECT  34.632 18.565 36.522 18.571 ;
     RECT  34.596 18.571 36.522 18.605 ;
     RECT  31.068 18.229 31.086 18.661 ;
     RECT  31.932 17.879 33.57 18.661 ;
     RECT  45.615 18.149 45.897 18.661 ;
     RECT  37.512 18.419 40.914 18.689 ;
     RECT  31.068 18.661 33.57 18.725 ;
     RECT  44.964 18.661 45.897 18.763 ;
     RECT  36.504 18.605 36.522 18.769 ;
     RECT  37.512 18.689 40.497 18.769 ;
     RECT  36.504 18.769 40.497 18.797 ;
     RECT  31.068 18.725 32.49 18.803 ;
     RECT  44.676 18.763 45.897 18.803 ;
     RECT  33.408 18.725 33.57 18.959 ;
     RECT  34.596 18.605 35.097 19.075 ;
     RECT  107.136 19.051 107.154 19.103 ;
     RECT  31.284 18.803 32.49 19.229 ;
     RECT  34.416 19.075 35.097 19.229 ;
     RECT  33.444 18.959 33.57 19.265 ;
     RECT  34.56 19.229 35.097 19.373 ;
     RECT  44.964 18.803 45.897 19.499 ;
     RECT  31.284 19.229 32.238 19.531 ;
     RECT  36.72 18.797 40.497 19.535 ;
     RECT  27.9 19.507 27.918 19.565 ;
     RECT  29.088 17.645 29.697 19.565 ;
     RECT  2.415 18.455 2.697 19.723 ;
     RECT  28.044 19.651 28.062 19.769 ;
     RECT  31.104 19.531 32.238 19.769 ;
     RECT  33.66 19.381 33.822 19.769 ;
     RECT  2.304 19.723 2.697 19.805 ;
     RECT  106.596 19.813 106.614 19.853 ;
     RECT  34.815 19.373 35.097 19.885 ;
     RECT  34.815 19.885 35.586 19.921 ;
     RECT  36.72 19.535 38.43 19.921 ;
     RECT  34.815 19.921 38.43 19.949 ;
     RECT  43.74 19.963 43.758 20.011 ;
     RECT  43.344 20.011 43.758 20.048 ;
     RECT  41.796 19.651 41.814 20.141 ;
     RECT  31.104 19.769 32.13 20.155 ;
     RECT  5.4 18.455 8.097 20.191 ;
     RECT  44.82 19.615 44.838 20.191 ;
     RECT  33.66 19.769 33.714 20.309 ;
     RECT  35.892 19.949 38.43 20.461 ;
     RECT  39.168 19.535 40.497 20.461 ;
     RECT  44.676 20.191 44.838 20.579 ;
     RECT  26.1 20.539 26.118 20.615 ;
     RECT  44.676 20.579 44.694 20.615 ;
     RECT  34.815 19.949 35.097 20.695 ;
     RECT  35.892 20.461 40.497 20.695 ;
     RECT  27.252 19.921 27.27 20.731 ;
     RECT  30.888 20.155 32.13 20.731 ;
     RECT  26.352 20.731 27.27 20.849 ;
     RECT  34.815 20.695 40.497 20.849 ;
     RECT  43.884 20.191 43.902 20.849 ;
     RECT  26.352 20.849 27.09 20.885 ;
     RECT  35.892 20.849 40.497 20.885 ;
     RECT  107.136 20.587 107.154 20.885 ;
     RECT  30.816 20.731 32.13 20.965 ;
     RECT  34.815 20.849 35.097 21.115 ;
     RECT  33.696 20.309 33.714 21.119 ;
     RECT  30.672 20.965 32.13 21.127 ;
     RECT  29.415 19.565 29.697 21.163 ;
     RECT  30.672 21.127 32.562 21.163 ;
     RECT  29.415 21.163 32.562 21.271 ;
     RECT  2.415 19.805 2.697 21.355 ;
     RECT  3.456 16.835 3.474 21.361 ;
     RECT  35.892 20.885 38.934 21.389 ;
     RECT  43.704 20.965 43.722 21.389 ;
     RECT  2.304 21.355 2.697 21.425 ;
     RECT  35.892 21.389 38.826 21.425 ;
     RECT  3.456 21.361 3.582 21.533 ;
     RECT  34.776 21.115 35.097 21.631 ;
     RECT  35.892 21.425 38.61 21.631 ;
     RECT  26.352 20.885 26.37 21.659 ;
     RECT  29.415 21.271 32.886 21.929 ;
     RECT  29.415 21.929 31.05 22.045 ;
     RECT  31.788 21.929 32.886 22.109 ;
     RECT  39.78 20.885 40.497 22.109 ;
     RECT  106.596 21.235 106.614 22.157 ;
     RECT  31.86 22.109 32.886 22.199 ;
     RECT  34.776 21.631 38.61 22.199 ;
     RECT  43.668 21.541 43.686 22.199 ;
     RECT  36.72 22.199 38.61 22.205 ;
     RECT  31.86 22.199 32.778 22.235 ;
     RECT  36.756 22.205 38.61 22.235 ;
     RECT  37.872 22.235 38.61 22.351 ;
     RECT  26.208 21.775 26.226 22.469 ;
     RECT  37.872 22.351 38.826 22.505 ;
     RECT  37.872 22.505 38.61 22.577 ;
     RECT  28.44 22.219 28.458 22.621 ;
     RECT  29.304 22.045 31.05 22.621 ;
     RECT  28.44 22.621 31.05 22.637 ;
     RECT  24.015 5.369 24.297 22.699 ;
     RECT  26.1 22.621 26.118 22.711 ;
     RECT  25.668 22.711 26.118 22.739 ;
     RECT  42.516 22.171 42.822 22.739 ;
     RECT  24.015 22.699 24.57 22.747 ;
     RECT  28.728 22.637 31.05 22.775 ;
     RECT  24.015 22.747 24.642 22.891 ;
     RECT  107.172 22.783 107.19 22.925 ;
     RECT  30.924 22.775 31.05 22.939 ;
     RECT  2.415 21.425 2.697 22.987 ;
     RECT  24.015 22.891 24.786 23.009 ;
     RECT  25.668 22.739 25.83 23.009 ;
     RECT  25.668 23.009 25.686 23.045 ;
     RECT  37.872 22.577 38.214 23.045 ;
     RECT  30.924 22.939 31.122 23.161 ;
     RECT  31.86 22.235 32.202 23.161 ;
     RECT  34.776 22.199 35.946 23.161 ;
     RECT  3.456 21.533 3.474 23.275 ;
     RECT  30.924 23.161 32.202 23.279 ;
     RECT  34.02 23.161 35.946 23.279 ;
     RECT  41.58 22.795 41.598 23.279 ;
     RECT  2.304 22.987 2.697 23.315 ;
     RECT  3.456 23.275 3.51 23.315 ;
     RECT  30.924 23.279 32.058 23.315 ;
     RECT  36.756 22.235 37.098 23.315 ;
     RECT  24.015 23.009 24.678 23.371 ;
     RECT  42.516 22.739 42.606 23.431 ;
     RECT  27.648 23.515 27.666 23.555 ;
     RECT  41.76 23.431 42.606 23.585 ;
     RECT  107.136 23.656 107.154 23.693 ;
     RECT  28.728 22.775 30.042 23.701 ;
     RECT  41.76 23.585 42.534 23.729 ;
     RECT  23.544 23.371 24.678 23.819 ;
     RECT  30.924 23.315 31.914 23.819 ;
     RECT  37.944 23.045 38.214 23.819 ;
     RECT  41.76 23.729 41.922 23.819 ;
     RECT  27.9 23.701 30.042 23.827 ;
     RECT  30.924 23.819 31.554 23.827 ;
     RECT  27.9 23.827 31.554 24.089 ;
     RECT  38.196 23.819 38.214 24.089 ;
     RECT  41.76 23.819 41.778 24.089 ;
     RECT  34.02 23.279 35.73 24.091 ;
     RECT  37.008 23.315 37.098 24.091 ;
     RECT  34.02 24.091 35.91 24.241 ;
     RECT  37.008 24.091 37.422 24.241 ;
     RECT  27.9 24.089 31.158 24.359 ;
     RECT  41.724 24.241 41.742 24.359 ;
     RECT  33.3 24.241 37.422 24.395 ;
     RECT  32.544 24.241 32.562 24.403 ;
     RECT  33.3 24.395 35.097 24.403 ;
     RECT  41.652 24.367 41.67 24.475 ;
     RECT  32.544 24.403 35.097 24.509 ;
     RECT  39.852 22.109 40.497 24.511 ;
     RECT  2.415 23.315 2.697 24.619 ;
     RECT  27.972 24.359 30.906 24.629 ;
     RECT  36.072 24.395 36.234 24.629 ;
     RECT  41.616 24.475 41.67 24.665 ;
     RECT  23.616 23.819 24.297 24.781 ;
     RECT  41.652 24.665 41.67 24.809 ;
     RECT  27.972 24.629 30.834 24.899 ;
     RECT  39.852 24.511 40.878 24.899 ;
     RECT  2.304 24.619 2.697 24.935 ;
     RECT  28.008 24.899 30.726 24.935 ;
     RECT  4.428 23.431 4.446 25.045 ;
     RECT  5.4 20.191 8.586 25.045 ;
     RECT  4.428 25.045 8.586 25.085 ;
     RECT  26.892 25.099 26.91 25.169 ;
     RECT  28.008 24.935 30.618 25.169 ;
     RECT  107.136 24.427 107.154 25.241 ;
     RECT  32.76 24.509 35.097 25.285 ;
     RECT  36.972 24.395 37.422 25.285 ;
     RECT  32.652 25.285 35.097 25.321 ;
     RECT  36.072 24.629 36.09 25.321 ;
     RECT  35.928 25.321 36.09 25.439 ;
     RECT  35.928 25.439 35.946 25.475 ;
     RECT  39.852 24.899 40.77 25.477 ;
     RECT  39.6 25.477 40.77 25.517 ;
     RECT  23.544 24.781 24.297 25.555 ;
     RECT  9.9 25.531 9.918 25.583 ;
     RECT  32.652 25.321 35.154 25.591 ;
     RECT  36.972 25.285 37.53 25.591 ;
     RECT  10.872 25.591 10.89 25.661 ;
     RECT  32.4 25.591 35.154 25.681 ;
     RECT  32.328 25.681 35.154 25.709 ;
     RECT  36.684 25.591 37.53 25.709 ;
     RECT  39.816 25.517 40.77 25.709 ;
     RECT  19.728 25.675 19.746 25.715 ;
     RECT  36.684 25.709 37.422 25.745 ;
     RECT  39.816 25.709 40.662 25.745 ;
     RECT  18.615 5.099 18.897 25.771 ;
     RECT  18.615 25.771 19.422 25.817 ;
     RECT  27.144 25.321 27.234 25.915 ;
     RECT  23.472 25.555 24.297 25.979 ;
     RECT  36.684 25.745 36.774 25.979 ;
     RECT  106.596 25.951 106.614 25.997 ;
     RECT  28.584 25.169 30.546 26.095 ;
     RECT  22.32 26.095 22.338 26.131 ;
     RECT  27.144 25.915 27.558 26.131 ;
     RECT  28.548 26.095 30.546 26.131 ;
     RECT  31.392 26.095 31.41 26.131 ;
     RECT  32.328 25.709 35.097 26.131 ;
     RECT  27.144 26.131 30.546 26.203 ;
     RECT  31.392 26.131 35.097 26.203 ;
     RECT  2.415 24.935 2.697 26.251 ;
     RECT  3.456 23.315 3.474 26.251 ;
     RECT  36.684 25.979 36.702 26.401 ;
     RECT  39.816 25.745 40.497 26.401 ;
     RECT  22.32 26.131 22.59 26.519 ;
     RECT  27.144 26.203 35.097 26.519 ;
     RECT  2.415 26.251 3.474 26.555 ;
     RECT  27.144 26.519 33.714 26.671 ;
     RECT  26.136 26.671 33.714 26.765 ;
     RECT  21.276 26.203 21.294 26.789 ;
     RECT  22.32 26.519 22.374 26.789 ;
     RECT  36.576 26.401 36.702 26.789 ;
     RECT  38.664 26.731 38.682 26.789 ;
     RECT  5.4 25.085 8.586 26.825 ;
     RECT  107.136 26.731 107.154 26.825 ;
     RECT  39.78 26.401 40.497 26.941 ;
     RECT  36.828 26.905 36.846 27.059 ;
     RECT  26.352 26.765 33.714 27.095 ;
     RECT  39.672 26.941 40.497 27.095 ;
     RECT  34.56 26.519 35.097 27.175 ;
     RECT  34.56 27.175 35.694 27.211 ;
     RECT  34.56 27.211 36.09 27.245 ;
     RECT  32.22 27.095 33.714 27.301 ;
     RECT  34.56 27.245 35.097 27.301 ;
     RECT  21.384 26.941 22.302 27.329 ;
     RECT  38.808 26.941 38.934 27.329 ;
     RECT  22.212 27.329 22.23 27.365 ;
     RECT  32.22 27.301 35.097 27.365 ;
     RECT  24.015 25.979 24.297 27.481 ;
     RECT  107.172 27.337 107.19 27.533 ;
     RECT  23.616 27.481 24.297 27.595 ;
     RECT  38.808 27.329 38.826 27.599 ;
     RECT  23.472 27.595 24.297 27.635 ;
     RECT  24.015 27.635 24.297 27.751 ;
     RECT  25.452 27.715 25.47 27.751 ;
     RECT  26.352 27.095 31.482 27.751 ;
     RECT  25.452 27.751 31.482 27.773 ;
     RECT  25.704 27.773 31.482 27.869 ;
     RECT  2.415 26.555 2.697 27.877 ;
     RECT  3.456 26.555 3.474 27.877 ;
     RECT  2.415 27.877 3.474 27.917 ;
     RECT  3.456 27.917 3.474 28.021 ;
     RECT  30.564 27.869 31.482 28.021 ;
     RECT  32.22 27.365 32.742 28.021 ;
     RECT  3.456 28.021 3.618 28.139 ;
     RECT  25.704 27.869 29.697 28.139 ;
     RECT  33.552 27.365 35.097 28.139 ;
     RECT  37.692 28.075 37.71 28.139 ;
     RECT  30.564 28.021 32.742 28.255 ;
     RECT  33.552 28.139 33.786 28.255 ;
     RECT  35.964 27.245 36.09 28.255 ;
     RECT  5.436 26.825 8.586 28.291 ;
     RECT  34.815 28.139 35.097 28.291 ;
     RECT  35.964 28.255 36.126 28.291 ;
     RECT  38.772 27.751 38.79 28.291 ;
     RECT  106.596 28.255 106.614 28.301 ;
     RECT  28.8 28.139 29.697 28.319 ;
     RECT  25.704 28.139 28.026 28.409 ;
     RECT  30.564 28.255 33.786 28.409 ;
     RECT  37.728 28.291 38.79 28.409 ;
     RECT  38.628 28.409 38.646 28.445 ;
     RECT  24.015 27.751 24.426 28.507 ;
     RECT  34.815 28.291 36.126 28.679 ;
     RECT  34.815 28.679 36.018 28.715 ;
     RECT  24.015 28.507 24.786 28.795 ;
     RECT  25.704 28.409 26.766 28.795 ;
     RECT  5.436 28.291 8.694 28.831 ;
     RECT  30.564 28.409 33.21 28.831 ;
     RECT  29.376 28.319 29.697 28.921 ;
     RECT  5.436 28.831 8.802 28.949 ;
     RECT  21.384 27.329 21.402 28.949 ;
     RECT  27.576 28.409 27.918 28.949 ;
     RECT  29.376 28.921 29.754 28.949 ;
     RECT  30.492 28.831 33.21 28.949 ;
     RECT  34.815 28.715 35.55 28.957 ;
     RECT  4.428 25.085 4.446 28.985 ;
     RECT  34.488 28.957 35.55 29.021 ;
     RECT  29.415 28.949 29.754 29.065 ;
     RECT  30.492 28.949 32.742 29.065 ;
     RECT  106.596 29.029 106.614 29.069 ;
     RECT  5.436 28.949 8.766 29.101 ;
     RECT  24.015 28.795 26.766 29.179 ;
     RECT  5.112 29.101 8.766 29.255 ;
     RECT  37.728 28.409 37.746 29.335 ;
     RECT  23.688 29.179 26.766 29.371 ;
     RECT  36.972 29.467 36.99 29.525 ;
     RECT  2.415 27.917 2.697 29.605 ;
     RECT  3.456 28.139 3.474 29.605 ;
     RECT  27.9 28.949 27.918 29.605 ;
     RECT  34.596 29.021 35.55 29.633 ;
     RECT  37.728 29.335 37.962 29.641 ;
     RECT  29.415 29.065 32.742 29.693 ;
     RECT  2.415 29.605 3.474 29.759 ;
     RECT  23.688 29.371 26.946 29.759 ;
     RECT  29.415 29.693 32.346 29.759 ;
     RECT  37.188 29.641 37.962 29.759 ;
     RECT  37.188 29.759 37.89 29.795 ;
     RECT  106.596 29.797 106.614 29.837 ;
     RECT  3.456 29.759 3.474 29.875 ;
     RECT  34.596 29.633 35.097 29.875 ;
     RECT  5.112 29.255 8.586 29.911 ;
     RECT  33.876 29.875 35.097 29.933 ;
     RECT  24.012 29.759 26.946 30.001 ;
     RECT  27.9 29.605 28.098 30.001 ;
     RECT  21.24 29.029 21.258 30.029 ;
     RECT  24.012 30.001 28.098 30.029 ;
     RECT  24.012 30.029 24.714 30.065 ;
     RECT  20.232 30.145 20.25 30.181 ;
     RECT  28.404 30.145 28.458 30.181 ;
     RECT  29.415 29.759 32.274 30.181 ;
     RECT  3.456 29.875 3.618 30.221 ;
     RECT  20.232 30.181 20.538 30.221 ;
     RECT  25.452 30.029 27.378 30.299 ;
     RECT  28.404 30.181 32.274 30.299 ;
     RECT  4.572 29.911 8.586 30.335 ;
     RECT  45.615 19.499 45.897 30.568 ;
     RECT  4.68 30.335 8.586 30.569 ;
     RECT  20.34 30.221 20.538 30.569 ;
     RECT  36.396 30.523 36.414 30.569 ;
     RECT  45.216 30.568 45.897 30.605 ;
     RECT  107.136 30.568 107.154 30.605 ;
     RECT  34.236 29.933 35.097 30.685 ;
     RECT  37.188 29.795 37.422 30.721 ;
     RECT  45.504 30.605 45.897 30.797 ;
     RECT  34.128 30.685 35.097 30.811 ;
     RECT  28.404 30.299 31.554 30.839 ;
     RECT  28.548 30.839 31.41 30.875 ;
     RECT  36.576 30.721 37.422 30.911 ;
     RECT  24.012 30.065 24.678 30.991 ;
     RECT  27.144 30.299 27.378 30.991 ;
     RECT  18.615 25.817 18.897 31.051 ;
     RECT  28.548 30.875 31.338 31.109 ;
     RECT  28.548 31.109 31.266 31.145 ;
     RECT  25.632 30.299 26.262 31.189 ;
     RECT  18.615 31.051 19.242 31.261 ;
     RECT  20.34 30.569 20.358 31.261 ;
     RECT  25.632 31.189 26.298 31.261 ;
     RECT  33.408 30.811 35.097 31.339 ;
     RECT  18.615 31.261 20.358 31.379 ;
     RECT  22.932 30.991 24.75 31.379 ;
     RECT  33.408 31.339 35.766 31.379 ;
     RECT  18.615 31.379 20.25 31.415 ;
     RECT  33.408 31.379 35.097 31.415 ;
     RECT  36.576 30.911 36.738 31.531 ;
     RECT  18.615 31.415 19.566 31.649 ;
     RECT  22.932 31.379 24.606 31.649 ;
     RECT  27.144 30.991 27.666 31.649 ;
     RECT  28.656 31.145 30.798 31.649 ;
     RECT  33.408 31.415 33.858 31.649 ;
     RECT  11.412 31.351 11.43 31.685 ;
     RECT  25.524 31.261 26.298 31.765 ;
     RECT  27.144 31.649 27.522 31.765 ;
     RECT  25.416 31.765 26.298 31.801 ;
     RECT  27.072 31.765 27.522 31.801 ;
     RECT  18.615 31.649 19.458 31.915 ;
     RECT  25.416 31.801 27.522 31.919 ;
     RECT  30.78 31.649 30.798 31.919 ;
     RECT  35.892 31.531 36.738 31.919 ;
     RECT  35.892 31.919 36.594 31.955 ;
     RECT  107.172 31.261 107.19 32.141 ;
     RECT  22.932 31.649 24.462 32.155 ;
     RECT  28.656 31.649 30.006 32.189 ;
     RECT  33.84 31.649 33.858 32.305 ;
     RECT  16.704 31.801 16.722 32.341 ;
     RECT  18.324 31.915 19.458 32.341 ;
     RECT  28.656 32.189 29.934 32.341 ;
     RECT  17.748 32.341 19.458 32.381 ;
     RECT  22.284 32.155 24.462 32.431 ;
     RECT  32.94 31.915 32.958 32.431 ;
     RECT  33.84 32.305 33.966 32.431 ;
     RECT  22.284 32.431 24.642 32.443 ;
     RECT  25.416 31.919 27.378 32.443 ;
     RECT  16.704 32.341 17.01 32.459 ;
     RECT  18.615 32.381 19.458 32.459 ;
     RECT  21.996 32.443 27.378 32.459 ;
     RECT  32.94 32.431 33.966 32.459 ;
     RECT  16.704 32.459 16.722 32.495 ;
     RECT  18.615 32.459 19.314 32.495 ;
     RECT  33.192 32.459 33.966 32.729 ;
     RECT  20.844 32.443 20.862 32.731 ;
     RECT  21.996 32.459 27.306 32.765 ;
     RECT  33.192 32.729 33.858 32.765 ;
     RECT  28.296 32.341 29.934 32.845 ;
     RECT  2.415 29.759 2.697 32.881 ;
     RECT  34.815 31.415 35.097 32.881 ;
     RECT  35.892 31.955 36.018 32.881 ;
     RECT  107.136 32.872 107.154 32.909 ;
     RECT  2.415 32.881 2.718 32.999 ;
     RECT  20.556 32.731 20.862 32.999 ;
     RECT  34.815 32.881 36.018 32.999 ;
     RECT  21.996 32.765 26.514 33.035 ;
     RECT  28.152 32.845 29.934 33.035 ;
     RECT  34.815 32.999 35.91 33.035 ;
     RECT  18.615 32.495 18.897 33.115 ;
     RECT  33.192 32.765 33.21 33.385 ;
     RECT  20.7 32.999 20.862 33.403 ;
     RECT  21.996 33.035 26.406 33.403 ;
     RECT  27.288 32.765 27.306 33.421 ;
     RECT  28.152 33.035 29.826 33.421 ;
     RECT  17.748 32.381 17.766 33.541 ;
     RECT  10.296 32.971 10.314 33.547 ;
     RECT  10.296 33.547 10.494 33.575 ;
     RECT  20.7 33.403 26.406 33.575 ;
     RECT  18.54 33.115 18.897 33.619 ;
     RECT  17.424 33.541 17.766 33.691 ;
     RECT  18.504 33.619 18.897 33.691 ;
     RECT  10.476 33.575 10.494 33.719 ;
     RECT  20.916 33.575 26.406 33.809 ;
     RECT  27.288 33.421 29.826 33.809 ;
     RECT  34.815 33.035 35.37 33.925 ;
     RECT  23.832 33.809 26.406 33.961 ;
     RECT  32.004 33.925 32.022 33.961 ;
     RECT  33.084 33.385 33.21 33.961 ;
     RECT  34.272 33.925 35.37 33.965 ;
     RECT  32.004 33.961 33.21 34.079 ;
     RECT  17.424 33.691 18.897 34.115 ;
     RECT  23.832 33.961 26.874 34.115 ;
     RECT  32.004 34.079 32.958 34.115 ;
     RECT  34.416 33.965 35.37 34.151 ;
     RECT  32.004 34.115 32.454 34.205 ;
     RECT  107.136 33.643 107.154 34.457 ;
     RECT  20.916 33.809 22.806 34.619 ;
     RECT  34.416 34.151 35.097 34.619 ;
     RECT  16.452 34.219 16.47 34.655 ;
     RECT  20.916 34.619 22.122 34.655 ;
     RECT  4.716 30.569 8.586 34.735 ;
     RECT  17.424 34.115 17.766 34.997 ;
     RECT  20.916 34.655 22.086 35.041 ;
     RECT  23.904 34.115 26.874 35.041 ;
     RECT  27.72 33.809 29.754 35.041 ;
     RECT  31.464 34.795 31.482 35.041 ;
     RECT  32.256 34.205 32.454 35.041 ;
     RECT  23.904 35.041 29.754 35.159 ;
     RECT  20.196 35.041 22.086 35.195 ;
     RECT  106.596 35.131 106.614 35.213 ;
     RECT  22.932 34.771 23.13 35.275 ;
     RECT  23.904 35.159 29.697 35.275 ;
     RECT  31.464 35.041 32.454 35.309 ;
     RECT  31.644 35.309 32.454 35.311 ;
     RECT  31.644 35.311 32.526 35.429 ;
     RECT  20.196 35.195 21.366 35.545 ;
     RECT  32.508 35.429 32.526 35.573 ;
     RECT  22.14 35.401 22.158 35.581 ;
     RECT  22.932 35.275 29.697 35.581 ;
     RECT  54.072 35.545 54.09 35.581 ;
     RECT  54.072 35.581 54.45 35.597 ;
     RECT  54.432 35.597 54.45 35.645 ;
     RECT  18.615 34.115 18.897 35.659 ;
     RECT  22.14 35.581 29.697 35.735 ;
     RECT  18.615 35.659 19.134 35.851 ;
     RECT  20.124 35.545 21.366 35.851 ;
     RECT  18.615 35.851 21.366 35.969 ;
     RECT  34.56 34.619 35.097 36.085 ;
     RECT  18.615 35.969 21.258 36.113 ;
     RECT  2.415 32.999 2.697 36.121 ;
     RECT  3.456 30.221 3.474 36.121 ;
     RECT  2.415 36.121 3.474 36.239 ;
     RECT  34.488 36.085 35.097 36.239 ;
     RECT  22.14 35.735 27.27 36.275 ;
     RECT  22.14 36.275 22.734 36.355 ;
     RECT  3.456 36.239 3.474 36.391 ;
     RECT  4.716 34.735 8.73 36.391 ;
     RECT  33.516 36.355 33.534 36.391 ;
     RECT  33.516 36.391 33.858 36.413 ;
     RECT  3.456 36.391 3.582 36.461 ;
     RECT  28.08 35.735 29.697 36.509 ;
     RECT  30.672 36.472 30.69 36.509 ;
     RECT  23.796 36.275 27.27 36.545 ;
     RECT  16.596 34.663 16.614 36.616 ;
     RECT  16.596 36.616 16.65 36.617 ;
     RECT  25.956 36.545 27.27 36.625 ;
     RECT  28.08 36.509 28.134 36.625 ;
     RECT  31.644 35.429 31.77 36.661 ;
     RECT  25.956 36.625 28.134 36.701 ;
     RECT  30.996 36.661 31.77 36.779 ;
     RECT  4.608 36.391 8.73 36.815 ;
     RECT  30.996 36.779 31.626 36.815 ;
     RECT  17.748 34.997 17.766 36.907 ;
     RECT  18.615 36.113 21.114 36.907 ;
     RECT  39.852 27.095 40.497 36.907 ;
     RECT  17.748 36.907 21.114 36.931 ;
     RECT  21.996 36.355 22.734 36.931 ;
     RECT  45.615 30.797 45.897 37.003 ;
     RECT  10.512 36.391 10.53 37.021 ;
     RECT  17.748 36.931 22.734 37.021 ;
     RECT  39.852 36.907 40.59 37.037 ;
     RECT  4.86 36.815 8.73 37.049 ;
     RECT  25.956 36.701 27.162 37.049 ;
     RECT  28.08 36.701 28.134 37.049 ;
     RECT  43.344 36.859 43.362 37.049 ;
     RECT  44.892 37.003 45.897 37.049 ;
     RECT  5.436 37.049 8.73 37.085 ;
     RECT  25.956 37.049 27.09 37.085 ;
     RECT  17.748 37.021 22.842 37.201 ;
     RECT  25.956 37.085 26.406 37.319 ;
     RECT  14.544 33.511 14.562 37.355 ;
     RECT  30.996 36.815 31.014 37.435 ;
     RECT  32.976 37.429 32.994 37.469 ;
     RECT  23.796 36.545 25.182 37.471 ;
     RECT  25.956 37.319 26.298 37.471 ;
     RECT  33.732 36.413 33.858 37.471 ;
     RECT  16.632 36.617 16.65 37.561 ;
     RECT  17.748 37.201 23.022 37.561 ;
     RECT  23.796 37.471 26.298 37.561 ;
     RECT  28.08 37.049 28.098 37.561 ;
     RECT  30.888 37.435 31.014 37.561 ;
     RECT  17.748 37.561 26.298 37.589 ;
     RECT  28.008 37.561 28.098 37.589 ;
     RECT  33.264 37.471 33.93 37.625 ;
     RECT  107.136 35.947 107.154 37.625 ;
     RECT  17.784 37.589 26.262 37.769 ;
     RECT  17.784 37.769 22.302 37.859 ;
     RECT  33.264 37.625 33.858 37.895 ;
     RECT  29.415 36.509 29.697 37.975 ;
     RECT  16.632 37.561 16.866 38.005 ;
     RECT  2.415 36.239 2.697 38.011 ;
     RECT  3.456 36.461 3.474 38.011 ;
     RECT  29.415 37.975 30.078 38.011 ;
     RECT  30.816 37.561 31.014 38.011 ;
     RECT  33.264 37.895 33.75 38.039 ;
     RECT  16.488 38.005 16.866 38.045 ;
     RECT  2.415 38.011 3.474 38.129 ;
     RECT  23.04 37.769 26.262 38.129 ;
     RECT  4.572 37.579 4.59 38.165 ;
     RECT  23.04 38.129 26.118 38.165 ;
     RECT  29.415 38.011 31.014 38.165 ;
     RECT  22.068 37.859 22.302 38.189 ;
     RECT  33.264 38.039 33.39 38.245 ;
     RECT  5.436 37.085 8.586 38.281 ;
     RECT  16.56 38.045 16.866 38.281 ;
     RECT  107.172 38.137 107.19 38.285 ;
     RECT  13.215 15.197 13.497 38.371 ;
     RECT  16.56 38.281 17.01 38.399 ;
     RECT  23.04 38.165 25.434 38.399 ;
     RECT  33.156 38.245 33.39 38.399 ;
     RECT  39.852 37.037 40.497 38.399 ;
     RECT  29.415 38.165 30.942 38.435 ;
     RECT  14.76 37.471 14.778 38.443 ;
     RECT  12.528 38.371 13.497 38.471 ;
     RECT  16.632 38.399 17.01 38.515 ;
     RECT  17.784 37.859 21.222 38.515 ;
     RECT  28.008 37.589 28.026 38.515 ;
     RECT  14.76 38.443 14.85 38.543 ;
     RECT  29.415 38.435 30.834 38.579 ;
     RECT  28.008 38.515 28.35 38.635 ;
     RECT  16.632 38.515 21.222 38.669 ;
     RECT  5.436 38.281 9.018 38.677 ;
     RECT  9.792 37.021 10.53 38.677 ;
     RECT  27.36 38.635 28.35 38.705 ;
     RECT  39.24 38.635 39.402 38.705 ;
     RECT  15.768 38.641 15.786 38.762 ;
     RECT  51.015 13.559 51.297 38.821 ;
     RECT  56.415 4.649 56.697 38.821 ;
     RECT  22.104 38.189 22.302 38.923 ;
     RECT  23.04 38.399 25.326 38.923 ;
     RECT  40.176 38.399 40.497 38.975 ;
     RECT  27.504 38.705 28.35 39.047 ;
     RECT  27.504 39.047 27.774 39.209 ;
     RECT  39.384 38.705 39.402 39.209 ;
     RECT  2.415 38.129 2.697 39.307 ;
     RECT  29.415 38.579 30.474 39.307 ;
     RECT  29.412 39.307 30.474 39.325 ;
     RECT  33.372 38.399 33.39 39.325 ;
     RECT  22.104 38.923 25.326 39.355 ;
     RECT  14.76 38.543 14.778 39.361 ;
     RECT  15.696 38.762 15.786 39.361 ;
     RECT  53.784 39.091 54.738 39.361 ;
     RECT  13.215 38.471 13.497 39.451 ;
     RECT  14.76 39.361 15.894 39.451 ;
     RECT  22.104 39.355 25.866 39.479 ;
     RECT  16.668 38.669 21.222 39.487 ;
     RECT  2.304 39.307 2.697 39.515 ;
     RECT  22.824 39.479 25.866 39.559 ;
     RECT  52.092 39.451 52.11 39.589 ;
     RECT  32.436 39.589 32.454 39.629 ;
     RECT  52.092 39.589 52.794 39.629 ;
     RECT  28.944 39.325 30.474 39.631 ;
     RECT  33.372 39.325 33.498 39.631 ;
     RECT  50.724 38.821 51.297 39.631 ;
     RECT  52.092 39.629 52.146 39.631 ;
     RECT  53.784 39.361 54.81 39.631 ;
     RECT  55.836 38.821 56.697 39.631 ;
     RECT  50.724 39.631 52.146 39.643 ;
     RECT  22.824 39.559 26.046 39.659 ;
     RECT  5.436 38.677 10.53 39.721 ;
     RECT  24.015 39.659 25.83 39.749 ;
     RECT  32.652 39.631 33.498 39.749 ;
     RECT  52.884 39.631 56.697 39.749 ;
     RECT  5.436 39.721 11.106 39.785 ;
     RECT  13.215 39.451 15.894 39.785 ;
     RECT  16.668 39.487 21.978 39.785 ;
     RECT  32.652 39.749 33.39 39.785 ;
     RECT  52.884 39.749 53.766 39.785 ;
     RECT  54.648 39.749 55.638 39.785 ;
     RECT  107.136 39.019 107.154 39.821 ;
     RECT  5.436 39.785 8.838 39.865 ;
     RECT  27.756 39.209 27.774 39.865 ;
     RECT  15.588 39.785 15.894 39.901 ;
     RECT  16.668 39.785 20.214 39.901 ;
     RECT  5.256 39.865 8.838 39.917 ;
     RECT  21.024 39.785 21.978 39.917 ;
     RECT  23.076 39.659 23.238 40.019 ;
     RECT  52.884 39.785 53.046 40.019 ;
     RECT  54.648 39.785 54.918 40.019 ;
     RECT  9.9 39.785 11.106 40.055 ;
     RECT  28.944 39.631 30.546 40.055 ;
     RECT  54.648 40.019 54.666 40.055 ;
     RECT  13.215 39.785 14.778 40.123 ;
     RECT  49.32 39.991 49.338 40.171 ;
     RECT  15.588 39.901 20.214 40.199 ;
     RECT  26.892 39.883 26.91 40.267 ;
     RECT  34.815 36.239 35.097 40.267 ;
     RECT  49.32 40.171 49.374 40.267 ;
     RECT  21.096 39.917 21.978 40.289 ;
     RECT  32.652 39.785 32.778 40.289 ;
     RECT  46.872 40.075 46.89 40.289 ;
     RECT  52.884 40.019 52.938 40.289 ;
     RECT  16.632 40.199 20.214 40.325 ;
     RECT  29.088 40.055 30.546 40.325 ;
     RECT  29.088 40.325 29.79 40.397 ;
     RECT  34.776 40.267 35.19 40.397 ;
     RECT  40.215 38.975 40.497 40.405 ;
     RECT  45.615 37.049 45.897 40.405 ;
     RECT  21.96 40.289 21.978 40.411 ;
     RECT  23.076 40.019 23.13 40.411 ;
     RECT  49.176 40.267 49.374 40.432 ;
     RECT  15.588 40.199 15.714 40.433 ;
     RECT  26.784 40.267 26.91 40.441 ;
     RECT  27.756 39.865 27.882 40.441 ;
     RECT  48.276 40.267 48.294 40.441 ;
     RECT  49.176 40.432 49.41 40.441 ;
     RECT  39.924 40.405 40.497 40.445 ;
     RECT  45.324 40.405 45.897 40.445 ;
     RECT  5.436 39.917 8.766 40.469 ;
     RECT  16.632 40.325 19.422 40.469 ;
     RECT  61.815 5.909 62.097 40.555 ;
     RECT  11.988 40.507 12.006 40.559 ;
     RECT  13.032 40.123 14.778 40.559 ;
     RECT  48.276 40.441 49.41 40.559 ;
     RECT  106.596 40.531 106.614 40.589 ;
     RECT  10.512 40.055 11.106 40.595 ;
     RECT  26.784 40.441 27.882 40.595 ;
     RECT  50.148 39.643 52.146 40.595 ;
     RECT  47.412 40.531 47.43 40.639 ;
     RECT  48.276 40.559 49.374 40.639 ;
     RECT  13.032 40.559 14.562 40.711 ;
     RECT  32.76 40.289 32.778 40.829 ;
     RECT  50.148 40.595 50.274 40.829 ;
     RECT  47.412 40.639 49.374 40.865 ;
     RECT  50.148 40.829 50.166 40.865 ;
     RECT  2.415 39.515 2.697 40.939 ;
     RECT  3.456 38.129 3.474 40.939 ;
     RECT  25.812 39.749 25.83 40.945 ;
     RECT  26.784 40.595 27.486 40.945 ;
     RECT  45.615 40.445 45.897 40.981 ;
     RECT  46.62 40.909 46.638 40.981 ;
     RECT  61.815 40.555 62.298 41.021 ;
     RECT  32.832 40.945 32.85 41.099 ;
     RECT  47.412 40.865 48.438 41.099 ;
     RECT  49.212 40.865 49.374 41.099 ;
     RECT  51.015 40.595 52.146 41.099 ;
     RECT  52.92 40.289 52.938 41.099 ;
     RECT  21.96 40.411 23.13 41.107 ;
     RECT  47.412 41.099 47.61 41.135 ;
     RECT  49.212 41.099 49.23 41.135 ;
     RECT  51.015 41.099 52.002 41.135 ;
     RECT  21.096 40.289 21.222 41.179 ;
     RECT  21.96 41.107 23.274 41.179 ;
     RECT  21.096 41.179 23.274 41.207 ;
     RECT  15.588 40.433 15.678 41.215 ;
     RECT  16.632 40.469 19.17 41.215 ;
     RECT  31.536 41.143 31.554 41.215 ;
     RECT  2.415 40.939 3.474 41.251 ;
     RECT  15.408 41.215 15.678 41.251 ;
     RECT  16.632 41.215 19.314 41.251 ;
     RECT  31.536 41.215 31.698 41.251 ;
     RECT  33.66 41.215 33.678 41.251 ;
     RECT  45.615 40.981 46.638 41.251 ;
     RECT  47.412 41.135 47.574 41.251 ;
     RECT  2.415 41.251 3.69 41.369 ;
     RECT  45.615 41.251 47.574 41.369 ;
     RECT  48.348 41.099 48.438 41.369 ;
     RECT  45.615 41.369 46.638 41.377 ;
     RECT  45.504 41.377 46.638 41.405 ;
     RECT  47.412 41.369 47.574 41.405 ;
     RECT  48.348 41.369 48.366 41.405 ;
     RECT  107.136 41.323 107.154 41.405 ;
     RECT  31.536 41.251 31.842 41.413 ;
     RECT  16.632 41.251 19.458 41.449 ;
     RECT  20.196 40.325 20.214 41.449 ;
     RECT  31.356 41.413 31.914 41.449 ;
     RECT  15.408 41.251 15.714 41.485 ;
     RECT  24.015 39.749 24.714 41.485 ;
     RECT  25.812 40.945 27.486 41.485 ;
     RECT  28.26 41.251 28.278 41.485 ;
     RECT  33.66 41.251 33.93 41.485 ;
     RECT  24.015 41.485 27.486 41.521 ;
     RECT  28.224 41.485 28.278 41.521 ;
     RECT  29.088 40.397 29.697 41.521 ;
     RECT  30.528 40.325 30.546 41.521 ;
     RECT  31.356 41.449 32.022 41.521 ;
     RECT  33.588 41.485 33.93 41.521 ;
     RECT  34.815 40.397 35.097 41.521 ;
     RECT  15.3 41.485 15.714 41.563 ;
     RECT  16.632 41.449 20.214 41.563 ;
     RECT  47.448 41.405 47.574 41.639 ;
     RECT  47.448 41.639 47.466 41.675 ;
     RECT  10.512 40.595 10.53 41.719 ;
     RECT  11.304 40.711 11.322 41.719 ;
     RECT  30.528 41.521 32.022 41.755 ;
     RECT  45.504 41.405 46.602 41.755 ;
     RECT  21.456 41.207 22.914 41.789 ;
     RECT  10.512 41.719 11.322 41.909 ;
     RECT  44.892 41.755 46.602 41.909 ;
     RECT  15.3 41.563 20.214 41.945 ;
     RECT  21.636 41.789 22.914 41.945 ;
     RECT  44.892 41.909 46.494 41.945 ;
     RECT  10.836 41.909 11.322 42.025 ;
     RECT  30.492 41.755 32.022 42.025 ;
     RECT  44.892 41.945 45.897 42.025 ;
     RECT  5.436 40.469 8.658 42.061 ;
     RECT  12.384 40.711 14.562 42.061 ;
     RECT  15.3 41.945 15.678 42.061 ;
     RECT  21.672 41.945 22.914 42.061 ;
     RECT  24.015 41.521 29.697 42.061 ;
     RECT  10.836 42.025 11.394 42.089 ;
     RECT  106.596 42.061 106.614 42.125 ;
     RECT  21.672 42.061 23.094 42.139 ;
     RECT  23.94 42.061 29.697 42.139 ;
     RECT  5.436 42.061 8.73 42.151 ;
     RECT  30.492 42.025 32.742 42.151 ;
     RECT  33.588 41.521 35.097 42.151 ;
     RECT  44.208 42.025 45.897 42.187 ;
     RECT  10.872 42.089 11.394 42.331 ;
     RECT  12.384 42.061 15.678 42.331 ;
     RECT  43.884 42.187 45.897 42.379 ;
     RECT  2.415 41.369 2.697 42.571 ;
     RECT  16.848 41.945 20.214 42.601 ;
     RECT  3.456 41.369 3.474 42.691 ;
     RECT  5.436 42.151 8.838 42.691 ;
     RECT  21.672 42.139 29.697 42.691 ;
     RECT  30.492 42.151 35.946 42.691 ;
     RECT  12.348 42.331 15.678 42.715 ;
     RECT  21.672 42.691 36.342 42.715 ;
     RECT  10.872 42.331 11.43 42.719 ;
     RECT  12.24 42.715 15.678 42.727 ;
     RECT  5.436 42.691 8.946 42.749 ;
     RECT  2.304 42.571 2.697 42.755 ;
     RECT  4.392 42.715 4.41 42.755 ;
     RECT  12.24 42.727 16.11 42.755 ;
     RECT  42.768 42.379 45.897 42.755 ;
     RECT  12.384 42.755 16.11 42.763 ;
     RECT  16.848 42.601 20.682 42.763 ;
     RECT  12.384 42.763 20.682 42.835 ;
     RECT  5.436 42.749 8.838 42.871 ;
     RECT  12.384 42.835 20.718 42.871 ;
     RECT  21.636 42.715 36.342 42.871 ;
     RECT  107.892 42.727 107.91 42.893 ;
     RECT  3.456 42.691 3.582 42.899 ;
     RECT  42.768 42.755 44.334 42.989 ;
     RECT  42.768 42.989 44.226 43.025 ;
     RECT  69.696 43.231 69.714 43.243 ;
     RECT  69.696 43.243 69.822 43.267 ;
     RECT  71.316 43.267 71.334 43.339 ;
     RECT  68.58 43.231 68.598 43.411 ;
     RECT  69.696 43.267 69.894 43.411 ;
     RECT  70.884 43.339 71.334 43.411 ;
     RECT  72.615 6.035 72.897 43.411 ;
     RECT  68.58 43.411 68.742 43.529 ;
     RECT  69.516 43.411 69.966 43.529 ;
     RECT  70.776 43.411 71.478 43.529 ;
     RECT  21.636 42.871 36.918 43.531 ;
     RECT  69.516 43.529 69.714 43.565 ;
     RECT  70.776 43.529 71.226 43.565 ;
     RECT  72.324 43.411 72.897 43.565 ;
     RECT  98.856 39.451 98.874 43.573 ;
     RECT  74.268 43.411 74.286 43.601 ;
     RECT  42.768 43.025 43.794 43.645 ;
     RECT  42.192 43.645 43.794 43.673 ;
     RECT  107.136 43.627 107.154 43.673 ;
     RECT  12.384 42.871 20.79 43.681 ;
     RECT  21.636 43.531 37.026 43.681 ;
     RECT  12.384 43.681 37.026 43.709 ;
     RECT  10.872 42.719 10.89 43.723 ;
     RECT  69.516 43.565 69.678 43.799 ;
     RECT  70.776 43.565 70.902 43.799 ;
     RECT  9.648 43.771 9.666 43.808 ;
     RECT  69.516 43.799 69.534 43.835 ;
     RECT  70.776 43.799 70.794 43.835 ;
     RECT  30.996 43.709 37.026 43.843 ;
     RECT  42.192 43.673 43.686 43.879 ;
     RECT  3.456 42.899 3.474 43.915 ;
     RECT  10.872 43.723 11.214 44.059 ;
     RECT  12.384 43.709 30.222 44.059 ;
     RECT  67.215 4.559 67.497 44.185 ;
     RECT  2.415 42.755 2.697 44.203 ;
     RECT  67.176 44.185 67.497 44.221 ;
     RECT  68.4 43.681 68.418 44.221 ;
     RECT  3.456 43.915 3.69 44.339 ;
     RECT  5.364 42.871 8.838 44.339 ;
     RECT  68.22 44.221 68.418 44.339 ;
     RECT  2.304 44.203 2.697 44.375 ;
     RECT  68.22 44.339 68.238 44.375 ;
     RECT  106.596 44.383 106.614 44.429 ;
     RECT  41.832 43.879 43.686 44.447 ;
     RECT  10.872 44.059 30.222 44.491 ;
     RECT  30.996 43.843 37.674 44.491 ;
     RECT  38.772 44.347 38.79 44.491 ;
     RECT  41.832 44.447 43.146 44.609 ;
     RECT  41.832 44.609 43.074 44.645 ;
     RECT  40.215 40.445 40.497 44.761 ;
     RECT  65.736 44.725 65.754 44.761 ;
     RECT  66.996 44.221 67.497 44.761 ;
     RECT  65.736 44.761 65.934 44.879 ;
     RECT  10.872 44.491 38.826 44.887 ;
     RECT  63.54 44.851 63.918 44.887 ;
     RECT  66.888 44.761 67.497 44.915 ;
     RECT  10.836 44.887 38.826 44.923 ;
     RECT  39.6 44.761 40.497 44.923 ;
     RECT  61.815 41.021 62.097 44.923 ;
     RECT  65.736 44.879 65.754 44.957 ;
     RECT  10.836 44.923 40.497 45.023 ;
     RECT  5.436 44.339 8.838 45.031 ;
     RECT  10.836 45.023 29.97 45.031 ;
     RECT  63.54 44.887 64.098 45.031 ;
     RECT  65.16 44.959 65.178 45.031 ;
     RECT  41.832 44.645 43.038 45.149 ;
     RECT  63.54 45.031 64.242 45.149 ;
     RECT  30.708 45.023 40.497 45.185 ;
     RECT  63.54 45.149 63.918 45.185 ;
     RECT  10.548 45.031 29.97 45.197 ;
     RECT  10.548 45.197 15.75 45.265 ;
     RECT  65.052 45.031 65.178 45.419 ;
     RECT  65.052 45.419 65.07 45.455 ;
     RECT  10.44 45.265 15.75 45.533 ;
     RECT  75.132 45.301 75.474 45.533 ;
     RECT  61.815 44.923 62.478 45.571 ;
     RECT  63.54 45.185 63.558 45.571 ;
     RECT  10.548 45.533 15.75 45.581 ;
     RECT  75.456 45.533 75.474 45.581 ;
     RECT  30.744 45.185 40.497 45.599 ;
     RECT  10.584 45.581 15.75 45.689 ;
     RECT  63.468 45.571 63.558 45.689 ;
     RECT  63.468 45.689 63.486 45.725 ;
     RECT  2.415 44.375 2.697 45.835 ;
     RECT  61.815 45.571 62.73 45.959 ;
     RECT  106.596 45.157 106.614 45.965 ;
     RECT  2.304 45.835 2.697 45.995 ;
     RECT  16.524 45.197 29.97 45.995 ;
     RECT  41.832 45.149 42.93 46.039 ;
     RECT  3.456 44.339 3.474 46.111 ;
     RECT  41.832 46.039 43.038 46.111 ;
     RECT  41.76 46.111 43.038 46.139 ;
     RECT  3.456 46.111 3.51 46.229 ;
     RECT  61.815 45.959 62.298 46.229 ;
     RECT  5.436 45.031 8.91 46.237 ;
     RECT  5.436 46.237 9.594 46.301 ;
     RECT  10.584 45.689 15.714 46.345 ;
     RECT  30.78 45.599 40.497 46.381 ;
     RECT  60.984 46.345 61.002 46.381 ;
     RECT  61.815 46.229 62.154 46.381 ;
     RECT  60.984 46.381 62.154 46.499 ;
     RECT  52.74 46.471 52.758 46.541 ;
     RECT  9.9 46.345 15.714 46.651 ;
     RECT  16.524 45.995 29.79 46.651 ;
     RECT  30.78 46.381 40.986 46.651 ;
     RECT  41.76 46.139 42.858 46.651 ;
     RECT  9.9 46.651 29.79 46.685 ;
     RECT  54.288 46.651 54.306 46.733 ;
     RECT  17.1 46.685 29.79 46.741 ;
     RECT  78.015 4.649 78.297 46.741 ;
     RECT  98.316 43.573 98.874 46.741 ;
     RECT  83.415 7.861 84.33 46.769 ;
     RECT  30.78 46.651 42.858 46.795 ;
     RECT  17.1 46.741 29.898 46.891 ;
     RECT  30.672 46.795 42.858 46.891 ;
     RECT  60.012 46.843 60.03 46.921 ;
     RECT  78.015 46.741 78.642 46.921 ;
     RECT  80.352 46.741 80.37 46.921 ;
     RECT  82.224 46.747 82.242 46.921 ;
     RECT  83.415 46.769 83.754 46.921 ;
     RECT  78.015 46.921 78.786 47.039 ;
     RECT  79.56 46.921 80.514 47.039 ;
     RECT  81.288 46.921 82.386 47.039 ;
     RECT  83.16 46.921 83.754 47.039 ;
     RECT  107.136 46.699 107.154 47.039 ;
     RECT  17.1 46.891 42.858 47.075 ;
     RECT  79.56 47.039 80.046 47.075 ;
     RECT  81.288 47.039 82.062 47.075 ;
     RECT  83.16 47.039 83.697 47.075 ;
     RECT  3.456 46.229 3.474 47.191 ;
     RECT  75.996 47.035 76.014 47.191 ;
     RECT  78.015 47.039 78.297 47.191 ;
     RECT  60.012 46.921 60.21 47.281 ;
     RECT  3.456 47.191 3.798 47.309 ;
     RECT  42.84 47.075 42.858 47.309 ;
     RECT  59.868 47.281 60.21 47.309 ;
     RECT  60.984 46.499 62.097 47.309 ;
     RECT  75.672 47.191 76.194 47.309 ;
     RECT  79.812 47.075 79.974 47.309 ;
     RECT  81.612 47.075 81.954 47.309 ;
     RECT  60.984 47.309 61.002 47.345 ;
     RECT  75.672 47.309 76.014 47.345 ;
     RECT  77.184 47.191 78.297 47.345 ;
     RECT  79.812 47.309 79.83 47.345 ;
     RECT  81.612 47.309 81.63 47.345 ;
     RECT  2.415 45.995 2.697 47.425 ;
     RECT  9.9 46.685 16.074 47.425 ;
     RECT  17.1 47.075 42.066 47.425 ;
     RECT  59.868 47.309 59.886 47.453 ;
     RECT  2.304 47.425 2.697 47.501 ;
     RECT  106.596 47.461 106.614 47.501 ;
     RECT  77.364 47.345 78.297 47.615 ;
     RECT  72.615 43.565 72.897 47.695 ;
     RECT  5.436 46.301 8.91 47.731 ;
     RECT  9.9 47.425 42.066 47.731 ;
     RECT  58.356 47.587 58.374 47.731 ;
     RECT  59.508 47.461 59.526 47.731 ;
     RECT  72.216 47.695 72.897 47.731 ;
     RECT  74.232 47.035 74.25 47.731 ;
     RECT  75.672 47.345 75.69 47.731 ;
     RECT  58.356 47.731 59.526 47.849 ;
     RECT  72.216 47.731 74.394 47.849 ;
     RECT  75.492 47.731 75.69 47.849 ;
     RECT  58.356 47.849 59.31 47.885 ;
     RECT  72.216 47.849 74.25 47.885 ;
     RECT  75.492 47.849 75.51 47.885 ;
     RECT  70.272 47.851 70.29 47.891 ;
     RECT  5.436 47.731 42.066 48.001 ;
     RECT  58.356 47.885 58.59 48.119 ;
     RECT  70.2 48.001 70.218 48.119 ;
     RECT  72.615 47.885 73.566 48.119 ;
     RECT  72.615 48.119 73.386 48.155 ;
     RECT  106.596 48.229 106.614 48.269 ;
     RECT  5.436 48.001 42.138 48.389 ;
     RECT  68.256 47.851 68.274 48.389 ;
     RECT  69.516 48.271 69.534 48.389 ;
     RECT  71.244 48.001 71.406 48.389 ;
     RECT  65.7 48.361 65.718 48.413 ;
     RECT  71.244 48.389 71.262 48.425 ;
     RECT  69.444 48.505 69.462 48.541 ;
     RECT  69.3 48.541 69.462 48.659 ;
     RECT  69.3 48.659 69.318 48.695 ;
     RECT  5.436 48.389 41.598 48.839 ;
     RECT  56.415 39.749 56.697 48.859 ;
     RECT  5.436 48.839 41.274 48.929 ;
     RECT  68.4 48.541 68.418 48.929 ;
     RECT  56.415 48.859 57.366 48.955 ;
     RECT  5.436 48.929 41.13 48.965 ;
     RECT  107.172 48.973 107.19 49.037 ;
     RECT  55.872 48.955 57.366 49.081 ;
     RECT  66.348 48.475 66.366 49.081 ;
     RECT  67.215 44.915 67.497 49.081 ;
     RECT  2.415 47.501 2.697 49.099 ;
     RECT  55.872 49.081 57.51 49.199 ;
     RECT  66.348 49.081 66.438 49.199 ;
     RECT  2.304 49.099 2.697 49.235 ;
     RECT  58.356 48.119 58.482 49.235 ;
     RECT  3.456 47.309 3.474 49.315 ;
     RECT  4.608 44.347 4.626 49.315 ;
     RECT  5.436 48.965 30.51 49.315 ;
     RECT  64.728 49.003 64.746 49.351 ;
     RECT  58.356 49.235 58.374 49.379 ;
     RECT  31.284 48.965 41.022 49.469 ;
     RECT  67.215 49.081 67.554 49.469 ;
     RECT  65.664 49.351 65.934 49.505 ;
     RECT  3.456 49.315 30.51 49.565 ;
     RECT  64.728 49.351 64.89 49.565 ;
     RECT  55.872 49.199 57.15 49.739 ;
     RECT  64.872 49.565 64.89 49.739 ;
     RECT  65.808 49.505 65.934 49.739 ;
     RECT  4.608 49.565 30.51 49.775 ;
     RECT  55.872 49.739 57.078 49.775 ;
     RECT  65.808 49.739 65.826 49.775 ;
     RECT  107.136 49.771 107.154 49.811 ;
     RECT  5.436 49.775 30.51 49.891 ;
     RECT  31.284 49.469 40.497 49.891 ;
     RECT  54.9 48.955 54.918 49.891 ;
     RECT  55.872 49.775 56.697 49.891 ;
     RECT  54.9 49.891 55.062 49.981 ;
     RECT  62.928 49.531 62.946 49.981 ;
     RECT  64.08 49.891 64.098 50.009 ;
     RECT  55.836 49.891 56.697 50.045 ;
     RECT  53.64 49.963 53.658 50.153 ;
     RECT  54.792 49.981 55.062 50.161 ;
     RECT  61.815 47.309 62.097 50.161 ;
     RECT  62.892 49.981 62.946 50.161 ;
     RECT  53.748 50.161 55.062 50.279 ;
     RECT  61.815 50.161 63.09 50.279 ;
     RECT  41.688 50.251 41.706 50.287 ;
     RECT  61.815 50.279 62.946 50.299 ;
     RECT  53.748 50.279 54.81 50.315 ;
     RECT  63.936 50.125 63.99 50.315 ;
     RECT  61.416 50.299 62.946 50.333 ;
     RECT  104.616 6.845 105.297 50.395 ;
     RECT  5.436 49.891 40.497 50.431 ;
     RECT  55.872 50.045 56.697 50.459 ;
     RECT  63.936 50.315 63.954 50.459 ;
     RECT  5.436 50.431 40.554 50.539 ;
     RECT  53.748 50.315 54.774 50.549 ;
     RECT  61.416 50.333 62.586 50.549 ;
     RECT  104.616 50.395 105.498 50.549 ;
     RECT  106.596 50.431 106.614 50.573 ;
     RECT  54.612 50.549 54.63 50.585 ;
     RECT  61.416 50.549 62.406 50.585 ;
     RECT  104.616 50.549 105.297 50.629 ;
     RECT  2.415 49.235 2.697 50.665 ;
     RECT  103.5 6.269 103.518 50.665 ;
     RECT  2.304 50.665 2.697 50.701 ;
     RECT  3.456 49.565 3.474 50.701 ;
     RECT  5.436 50.539 40.698 50.701 ;
     RECT  41.688 50.287 41.742 50.701 ;
     RECT  104.364 50.629 105.297 50.701 ;
     RECT  103.284 50.665 103.518 50.717 ;
     RECT  2.304 50.701 3.474 50.765 ;
     RECT  2.415 50.765 3.474 50.819 ;
     RECT  53.748 50.549 53.766 50.819 ;
     RECT  104.256 50.701 105.297 50.855 ;
     RECT  3.456 50.819 3.474 50.971 ;
     RECT  52.632 50.935 52.65 50.971 ;
     RECT  61.416 50.585 62.097 50.971 ;
     RECT  5.436 50.701 42.174 50.999 ;
     RECT  4.608 49.775 4.626 51.061 ;
     RECT  3.456 50.971 3.726 51.089 ;
     RECT  4.608 51.061 5.022 51.125 ;
     RECT  53.568 50.971 53.73 51.125 ;
     RECT  6.048 50.999 42.174 51.169 ;
     RECT  60.048 50.731 60.066 51.241 ;
     RECT  61.128 50.971 62.097 51.241 ;
     RECT  51.015 41.135 51.297 51.259 ;
     RECT  104.688 50.855 105.297 51.331 ;
     RECT  52.632 50.971 52.794 51.359 ;
     RECT  53.604 51.125 53.73 51.359 ;
     RECT  107.136 51.307 107.154 51.359 ;
     RECT  53.604 51.359 53.622 51.395 ;
     RECT  104.688 51.331 105.498 51.431 ;
     RECT  6.048 51.169 42.318 51.439 ;
     RECT  51.015 51.259 51.426 51.511 ;
     RECT  60.048 51.241 60.21 51.511 ;
     RECT  103.5 50.717 103.518 51.511 ;
     RECT  102.384 51.511 102.402 51.581 ;
     RECT  59.796 51.511 60.21 51.629 ;
     RECT  60.984 51.241 62.097 51.629 ;
     RECT  50.724 51.511 52.578 51.665 ;
     RECT  59.796 51.629 59.922 51.665 ;
     RECT  60.984 51.629 61.002 51.665 ;
     RECT  103.32 51.511 103.554 51.665 ;
     RECT  6.048 51.439 42.354 51.701 ;
     RECT  52.452 51.665 52.578 51.737 ;
     RECT  58.716 51.439 58.734 51.745 ;
     RECT  58.68 51.745 58.734 51.781 ;
     RECT  59.796 51.665 59.886 51.781 ;
     RECT  58.68 51.781 58.842 51.821 ;
     RECT  50.724 51.665 51.642 51.899 ;
     RECT  52.452 51.737 52.506 51.899 ;
     RECT  59.688 51.781 59.886 51.899 ;
     RECT  59.688 51.899 59.706 51.935 ;
     RECT  52.452 51.899 52.47 51.971 ;
     RECT  50.724 51.899 51.354 52.015 ;
     RECT  106.596 52.051 106.614 52.109 ;
     RECT  58.824 51.821 58.842 52.169 ;
     RECT  99.615 3.911 100.314 52.285 ;
     RECT  101.7 52.267 101.718 52.321 ;
     RECT  103.5 51.665 103.554 52.321 ;
     RECT  6.084 51.701 42.354 52.349 ;
     RECT  99.615 52.285 100.602 52.349 ;
     RECT  2.415 50.819 2.697 52.363 ;
     RECT  5.004 51.125 5.022 52.411 ;
     RECT  88.815 4.523 89.097 52.411 ;
     RECT  50.184 52.015 51.354 52.439 ;
     RECT  58.032 52.285 58.05 52.439 ;
     RECT  50.184 52.439 50.202 52.445 ;
     RECT  88.704 52.411 89.097 52.448 ;
     RECT  56.415 50.459 56.697 52.459 ;
     RECT  2.304 52.363 2.697 52.475 ;
     RECT  51.015 52.439 51.318 52.511 ;
     RECT  55.944 52.459 56.697 52.591 ;
     RECT  103.5 52.321 103.734 52.591 ;
     RECT  6.084 52.349 42.21 52.699 ;
     RECT  55.944 52.591 57.186 52.709 ;
     RECT  103.248 52.591 103.734 52.709 ;
     RECT  48.744 52.411 48.762 52.745 ;
     RECT  101.7 52.321 102.042 52.745 ;
     RECT  6.012 52.699 42.21 52.829 ;
     RECT  49.896 52.591 49.914 52.861 ;
     RECT  55.944 52.709 57.078 52.861 ;
     RECT  5.004 52.411 5.166 52.889 ;
     RECT  107.136 52.843 107.154 52.889 ;
     RECT  48.852 52.861 49.914 52.979 ;
     RECT  55.656 52.861 57.078 52.979 ;
     RECT  101.7 52.745 102.006 52.979 ;
     RECT  48.852 52.979 49.698 53.015 ;
     RECT  54.072 52.459 54.09 53.015 ;
     RECT  55.656 52.979 56.898 53.015 ;
     RECT  101.988 52.979 102.006 53.021 ;
     RECT  55.332 53.095 55.35 53.131 ;
     RECT  94.215 4.925 94.497 53.221 ;
     RECT  48.852 53.015 48.978 53.249 ;
     RECT  55.224 53.131 55.35 53.249 ;
     RECT  55.224 53.249 55.242 53.285 ;
     RECT  104.688 51.431 105.297 53.365 ;
     RECT  94.215 53.221 94.662 53.393 ;
     RECT  99.615 52.349 100.314 53.401 ;
     RECT  48.852 53.249 48.87 53.519 ;
     RECT  54.252 53.131 54.27 53.519 ;
     RECT  99.615 53.401 100.71 53.519 ;
     RECT  104.688 53.365 105.642 53.519 ;
     RECT  107.172 53.401 107.19 53.645 ;
     RECT  103.248 52.709 103.518 53.789 ;
     RECT  104.688 53.519 105.57 53.789 ;
     RECT  52.56 53.671 52.578 53.851 ;
     RECT  6.264 52.829 42.21 53.905 ;
     RECT  103.5 53.789 103.518 53.941 ;
     RECT  104.688 53.789 105.498 53.941 ;
     RECT  2.415 52.475 2.697 53.995 ;
     RECT  52.56 53.851 53.226 54.031 ;
     RECT  6.264 53.905 42.318 54.043 ;
     RECT  6.012 54.043 42.318 54.059 ;
     RECT  52.56 54.031 53.55 54.059 ;
     RECT  2.304 53.995 2.697 54.095 ;
     RECT  6.012 54.059 6.678 54.095 ;
     RECT  53.532 54.059 53.55 54.125 ;
     RECT  48.744 53.671 48.762 54.329 ;
     RECT  52.344 54.175 52.362 54.329 ;
     RECT  7.632 54.059 42.318 54.365 ;
     RECT  106.596 54.373 106.614 54.413 ;
     RECT  47.628 54.301 47.646 54.481 ;
     RECT  7.632 54.365 41.094 54.509 ;
     RECT  47.628 54.481 47.79 54.599 ;
     RECT  99.615 53.519 100.314 54.607 ;
     RECT  45.615 42.755 45.897 54.715 ;
     RECT  51.015 52.511 51.297 54.715 ;
     RECT  99.615 54.607 100.89 54.743 ;
     RECT  42.192 54.365 42.318 54.751 ;
     RECT  69.984 54.571 70.002 54.751 ;
     RECT  42.192 54.751 42.786 54.779 ;
     RECT  7.632 54.509 41.058 54.869 ;
     RECT  47.196 54.751 47.286 54.869 ;
     RECT  7.632 54.869 40.497 54.905 ;
     RECT  69.804 54.751 70.002 54.905 ;
     RECT  49.212 54.715 49.23 55.021 ;
     RECT  50.292 54.715 51.297 55.021 ;
     RECT  42.732 54.779 42.786 55.139 ;
     RECT  45.072 54.715 45.897 55.139 ;
     RECT  50.184 55.021 51.297 55.139 ;
     RECT  50.184 55.139 50.202 55.175 ;
     RECT  106.596 55.141 106.614 55.181 ;
     RECT  104.616 53.941 105.498 55.255 ;
     RECT  103.5 53.941 103.842 55.291 ;
     RECT  99.615 54.743 100.53 55.319 ;
     RECT  47.196 54.869 47.214 55.409 ;
     RECT  49.212 55.021 49.338 55.409 ;
     RECT  103.5 55.291 103.878 55.409 ;
     RECT  104.616 55.255 105.534 55.409 ;
     RECT  45.252 55.139 45.897 55.561 ;
     RECT  49.104 55.525 49.122 55.679 ;
     RECT  70.056 55.561 70.074 55.715 ;
     RECT  2.415 54.095 2.697 55.723 ;
     RECT  3.456 51.089 3.474 55.723 ;
     RECT  0.108 55.627 0.126 55.757 ;
     RECT  42.768 55.139 42.786 55.787 ;
     RECT  7.74 54.905 40.497 55.831 ;
     RECT  41.508 55.525 41.526 55.831 ;
     RECT  107.136 55.912 107.154 55.949 ;
     RECT  2.415 55.723 3.474 55.985 ;
     RECT  104.616 55.409 105.498 56.021 ;
     RECT  45.252 55.561 46.278 56.029 ;
     RECT  94.215 53.393 94.497 56.029 ;
     RECT  3.456 55.985 3.474 56.101 ;
     RECT  43.776 56.059 43.794 56.101 ;
     RECT  45.252 56.029 46.782 56.101 ;
     RECT  47.736 55.867 47.754 56.101 ;
     RECT  48.852 55.831 48.942 56.101 ;
     RECT  94.215 56.029 94.662 56.129 ;
     RECT  3.456 56.101 4.158 56.219 ;
     RECT  45.072 56.101 46.782 56.255 ;
     RECT  48.672 56.101 48.942 56.255 ;
     RECT  48.924 56.255 48.942 56.327 ;
     RECT  3.456 56.219 4.014 56.429 ;
     RECT  43.776 56.101 43.938 56.489 ;
     RECT  47.736 56.101 47.898 56.489 ;
     RECT  7.74 55.831 41.526 56.641 ;
     RECT  45.615 56.255 46.782 56.641 ;
     RECT  45.615 56.641 47.178 56.759 ;
     RECT  7.74 56.641 41.67 57.019 ;
     RECT  45.615 56.759 46.89 57.029 ;
     RECT  45.615 57.029 46.746 57.065 ;
     RECT  2.415 55.985 2.697 57.259 ;
     RECT  2.304 57.259 2.697 57.335 ;
     RECT  5.004 52.889 5.022 57.451 ;
     RECT  6.552 54.095 6.678 57.451 ;
     RECT  7.74 57.019 42.102 57.451 ;
     RECT  106.596 56.641 106.614 57.485 ;
     RECT  5.904 57.451 6.678 57.569 ;
     RECT  4.536 57.451 5.022 57.605 ;
     RECT  5.76 57.577 5.778 57.629 ;
     RECT  7.74 57.451 42.282 57.713 ;
     RECT  43.236 56.641 43.254 57.721 ;
     RECT  44.784 57.181 44.802 57.721 ;
     RECT  44.568 57.721 44.802 57.839 ;
     RECT  44.568 57.839 44.586 57.875 ;
     RECT  7.74 57.713 41.742 58.019 ;
     RECT  43.236 57.721 43.398 58.225 ;
     RECT  42.732 58.225 43.398 58.253 ;
     RECT  107.172 58.117 107.19 58.253 ;
     RECT  42.732 58.253 42.75 58.415 ;
     RECT  7.74 58.019 41.454 58.801 ;
     RECT  2.415 57.335 2.697 58.891 ;
     RECT  7.74 58.801 41.922 58.891 ;
     RECT  2.304 58.891 2.697 58.955 ;
     RECT  103.5 55.409 103.842 58.991 ;
     RECT  107.136 58.987 107.154 59.027 ;
     RECT  6.552 57.569 6.678 59.071 ;
     RECT  7.74 58.891 41.958 59.099 ;
     RECT  45.615 57.065 46.206 59.099 ;
     RECT  4.248 59.071 4.266 59.179 ;
     RECT  5.22 57.721 5.238 59.179 ;
     RECT  4.248 59.179 5.238 59.225 ;
     RECT  7.74 59.099 41.454 59.333 ;
     RECT  7.74 59.333 41.274 59.729 ;
     RECT  41.256 59.729 41.274 59.801 ;
     RECT  107.136 59.755 107.154 59.801 ;
     RECT  58.968 53.221 58.986 60.143 ;
     RECT  42.732 60.115 42.75 60.413 ;
     RECT  6.552 59.071 6.894 60.427 ;
     RECT  7.74 59.729 40.497 60.427 ;
     RECT  2.415 58.955 2.697 60.523 ;
     RECT  2.304 60.523 2.697 60.575 ;
     RECT  2.415 60.575 2.697 60.691 ;
     RECT  3.456 56.429 3.474 60.691 ;
     RECT  2.415 60.691 3.474 60.809 ;
     RECT  6.552 60.427 40.497 60.845 ;
     RECT  6.552 60.845 6.894 60.955 ;
     RECT  3.456 60.809 3.474 60.961 ;
     RECT  7.632 60.845 40.497 60.989 ;
     RECT  5.22 59.225 5.238 61.003 ;
     RECT  6.012 60.955 6.894 61.003 ;
     RECT  3.456 60.961 3.978 61.037 ;
     RECT  5.22 61.003 6.894 61.079 ;
     RECT  5.22 61.079 5.814 61.115 ;
     RECT  106.596 60.511 106.614 62.093 ;
     RECT  2.415 60.809 2.697 62.155 ;
     RECT  3.456 61.037 3.474 62.395 ;
     RECT  2.304 62.155 2.697 62.465 ;
     RECT  3.456 62.395 4.014 62.581 ;
     RECT  5.22 61.115 5.238 62.581 ;
     RECT  3.456 62.581 4.158 62.699 ;
     RECT  3.456 62.699 3.87 62.735 ;
     RECT  7.815 60.989 40.497 62.735 ;
     RECT  107.892 62.671 107.91 62.861 ;
     RECT  8.82 62.735 40.497 63.121 ;
     RECT  41.22 61.231 41.238 63.121 ;
     RECT  8.82 63.121 41.238 63.247 ;
     RECT  3.456 62.735 3.474 63.751 ;
     RECT  107.136 63.595 107.154 63.779 ;
     RECT  2.415 62.465 2.697 63.781 ;
     RECT  3.456 63.751 4.014 63.781 ;
     RECT  2.415 63.781 4.014 63.821 ;
     RECT  4.932 62.581 5.238 63.835 ;
     RECT  3.456 63.821 4.014 64.085 ;
     RECT  4.932 63.835 5.49 64.085 ;
     RECT  6.552 61.079 6.894 64.201 ;
     RECT  106.596 64.291 106.614 64.397 ;
     RECT  107.172 64.831 107.19 65.165 ;
     RECT  8.82 63.247 41.346 65.209 ;
     RECT  6.444 64.201 6.894 65.371 ;
     RECT  7.815 62.735 8.097 65.371 ;
     RECT  8.82 65.209 41.67 65.399 ;
     RECT  2.415 63.821 2.697 65.407 ;
     RECT  3.456 64.085 3.474 65.407 ;
     RECT  2.415 65.407 3.474 65.453 ;
     RECT  6.444 65.371 8.097 65.669 ;
     RECT  7.815 65.669 8.097 65.821 ;
     RECT  8.82 65.399 41.238 65.821 ;
     RECT  107.136 65.899 107.154 65.939 ;
     RECT  6.444 65.669 7.038 65.981 ;
     RECT  43.488 65.995 43.506 66.047 ;
     RECT  7.815 65.821 41.238 66.119 ;
     RECT  43.812 66.091 43.83 66.128 ;
     RECT  16.308 66.119 41.238 66.361 ;
     RECT  6.444 65.981 6.894 66.659 ;
     RECT  16.308 66.361 41.274 66.659 ;
     RECT  106.596 66.595 106.614 66.701 ;
     RECT  7.815 66.119 15.57 66.865 ;
     RECT  16.308 66.659 27.054 66.865 ;
     RECT  27.9 66.659 41.274 66.901 ;
     RECT  2.415 65.453 2.697 67.051 ;
     RECT  3.456 65.453 3.474 67.051 ;
     RECT  27.9 66.901 41.454 67.171 ;
     RECT  2.415 67.051 3.474 67.325 ;
     RECT  7.815 66.865 27.054 67.405 ;
     RECT  27.9 67.171 42.102 67.405 ;
     RECT  3.456 67.325 3.474 67.441 ;
     RECT  107.136 67.432 107.154 67.469 ;
     RECT  7.38 67.405 27.054 67.559 ;
     RECT  3.456 67.441 3.978 67.595 ;
     RECT  27.9 67.405 42.174 67.639 ;
     RECT  7.38 67.559 21.69 67.805 ;
     RECT  27.9 67.639 42.21 67.873 ;
     RECT  27.9 67.873 42.642 67.945 ;
     RECT  22.536 67.559 27.054 67.981 ;
     RECT  27.792 67.945 42.642 67.981 ;
     RECT  107.136 68.203 107.154 68.243 ;
     RECT  22.536 67.981 42.642 68.369 ;
     RECT  7.815 67.805 21.69 68.521 ;
     RECT  22.536 68.369 41.85 68.521 ;
     RECT  4.932 64.085 5.238 68.635 ;
     RECT  42.624 68.369 42.642 68.639 ;
     RECT  3.456 67.595 3.474 68.791 ;
     RECT  4.572 68.635 5.238 68.791 ;
     RECT  3.456 68.791 5.526 68.909 ;
     RECT  3.456 68.909 4.158 68.945 ;
     RECT  107.172 68.917 107.19 69.005 ;
     RECT  7.815 68.521 41.85 69.331 ;
     RECT  7.815 69.331 42.462 69.449 ;
     RECT  7.815 69.449 41.814 69.719 ;
     RECT  106.596 69.727 106.614 69.773 ;
     RECT  2.415 67.325 2.697 70.303 ;
     RECT  3.456 68.945 3.474 70.303 ;
     RECT  2.415 70.303 3.474 70.349 ;
     RECT  3.456 70.349 3.474 70.411 ;
     RECT  4.932 68.909 5.526 70.501 ;
     RECT  4.896 70.501 5.526 70.645 ;
     RECT  6.444 66.659 6.57 70.645 ;
     RECT  3.456 70.411 3.978 70.681 ;
     RECT  3.456 70.681 4.086 70.709 ;
     RECT  3.528 70.709 4.086 70.799 ;
     RECT  3.528 70.799 3.978 70.835 ;
     RECT  4.896 70.645 6.57 71.185 ;
     RECT  107.136 70.507 107.154 71.339 ;
     RECT  4.896 71.185 6.822 71.491 ;
     RECT  7.815 69.719 41.778 71.491 ;
     RECT  4.896 71.491 41.778 71.501 ;
     RECT  6.444 71.501 41.778 71.653 ;
     RECT  2.415 70.349 2.697 71.887 ;
     RECT  3.528 70.835 3.546 71.887 ;
     RECT  2.415 71.887 3.546 71.933 ;
     RECT  3.528 71.933 3.546 72.031 ;
     RECT  6.444 71.653 42.21 72.031 ;
     RECT  106.596 71.995 106.614 72.077 ;
     RECT  3.528 72.031 3.906 72.185 ;
     RECT  6.444 72.031 42.75 72.269 ;
     RECT  9.468 72.269 42.75 72.293 ;
     RECT  106.596 72.805 106.614 72.845 ;
     RECT  9.468 72.293 42.174 73.381 ;
     RECT  2.415 71.933 2.697 73.531 ;
     RECT  107.172 73.507 107.19 73.613 ;
     RECT  2.304 73.531 2.697 73.805 ;
     RECT  9.468 73.381 42.858 73.913 ;
     RECT  4.896 71.501 5.526 73.921 ;
     RECT  6.444 72.269 8.658 73.921 ;
     RECT  9.468 73.913 42.318 73.921 ;
     RECT  4.896 73.921 42.318 74.075 ;
     RECT  6.444 74.075 42.318 74.345 ;
     RECT  107.136 74.347 107.154 74.579 ;
     RECT  106.596 75.091 106.614 75.149 ;
     RECT  2.415 73.805 2.697 75.163 ;
     RECT  6.444 74.345 42.282 75.389 ;
     RECT  2.415 75.163 2.79 75.425 ;
     RECT  3.528 72.185 3.546 75.541 ;
     RECT  4.896 74.075 5.526 75.541 ;
     RECT  3.456 75.541 3.87 75.695 ;
     RECT  9.468 75.389 42.282 75.811 ;
     RECT  3.528 75.695 3.87 75.929 ;
     RECT  3.528 75.929 3.654 75.965 ;
     RECT  4.788 75.541 5.526 75.965 ;
     RECT  107.136 75.883 107.154 75.965 ;
     RECT  4.86 75.965 5.526 76.081 ;
     RECT  6.444 75.389 8.658 76.081 ;
     RECT  99.615 55.319 100.314 76.081 ;
     RECT  4.86 76.081 8.658 76.363 ;
     RECT  9.468 75.811 42.39 76.363 ;
     RECT  4.86 76.363 42.39 76.505 ;
     RECT  43.308 76.045 43.326 76.739 ;
     RECT  4.86 76.505 8.658 76.891 ;
     RECT  9.468 76.505 42.39 76.891 ;
     RECT  9.468 76.891 42.678 77.009 ;
     RECT  4.392 76.891 8.658 77.045 ;
     RECT  106.596 76.621 106.614 77.453 ;
     RECT  37.044 77.009 42.678 77.701 ;
     RECT  37.044 77.701 42.714 77.819 ;
     RECT  9.468 77.009 36.162 78.043 ;
     RECT  37.044 77.819 42.606 78.043 ;
     RECT  107.136 78.187 107.154 78.269 ;
     RECT  99.615 76.081 100.602 78.511 ;
     RECT  2.415 75.425 2.697 78.637 ;
     RECT  3.528 75.965 3.546 78.637 ;
     RECT  9.468 78.043 42.606 78.745 ;
     RECT  9.468 78.745 43.038 78.781 ;
     RECT  2.415 78.637 3.546 78.899 ;
     RECT  106.596 78.943 106.614 78.989 ;
     RECT  3.456 78.899 3.546 79.051 ;
     RECT  3.456 79.051 3.798 79.205 ;
     RECT  9.468 78.781 43.326 79.277 ;
     RECT  9.468 79.277 43.218 79.439 ;
     RECT  106.596 79.717 106.614 79.757 ;
     RECT  2.415 78.899 2.697 80.059 ;
     RECT  2.34 80.059 2.697 80.285 ;
     RECT  2.415 80.285 2.697 80.329 ;
     RECT  3.456 79.205 3.474 80.329 ;
     RECT  9.468 79.439 43.11 80.401 ;
     RECT  2.415 80.329 3.474 80.519 ;
     RECT  3.456 80.519 3.474 80.671 ;
     RECT  4.896 77.045 8.658 80.671 ;
     RECT  9.468 80.401 43.254 80.671 ;
     RECT  3.456 80.671 3.762 80.813 ;
     RECT  4.896 80.671 43.254 80.861 ;
     RECT  9.468 80.861 43.254 80.905 ;
     RECT  106.596 80.485 106.614 81.293 ;
     RECT  9.468 80.905 43.65 81.599 ;
     RECT  4.896 80.861 8.658 81.751 ;
     RECT  2.415 80.519 2.697 81.877 ;
     RECT  3.456 80.813 3.474 81.877 ;
     RECT  4.212 81.751 8.658 81.877 ;
     RECT  2.415 81.877 8.658 81.941 ;
     RECT  9.468 81.599 43.038 82.139 ;
     RECT  107.136 82.027 107.154 82.139 ;
     RECT  2.415 81.941 4.086 82.175 ;
     RECT  106.596 82.789 106.614 82.829 ;
     RECT  4.896 81.941 8.658 83.029 ;
     RECT  9.468 82.139 42.822 83.029 ;
     RECT  4.896 83.029 42.822 83.057 ;
     RECT  9.144 83.057 42.822 83.191 ;
     RECT  0.108 83.191 0.126 83.357 ;
     RECT  9.144 83.191 42.894 83.489 ;
     RECT  2.415 82.175 2.697 83.497 ;
     RECT  3.456 82.175 3.474 83.497 ;
     RECT  107.136 83.56 107.154 83.597 ;
     RECT  4.896 83.057 8.097 83.641 ;
     RECT  9.144 83.489 41.166 83.669 ;
     RECT  9.468 83.669 41.058 83.759 ;
     RECT  41.94 83.489 42.894 83.759 ;
     RECT  41.94 83.759 41.958 83.795 ;
     RECT  2.415 83.497 3.474 83.867 ;
     RECT  4.608 83.641 8.097 83.875 ;
     RECT  4.464 83.875 8.097 84.029 ;
     RECT  15.624 83.759 41.058 84.065 ;
     RECT  5.076 84.029 8.097 84.299 ;
     RECT  16.56 84.065 41.058 84.299 ;
     RECT  106.596 84.181 106.614 84.365 ;
     RECT  9.468 83.759 14.562 84.371 ;
     RECT  16.56 84.299 40.77 84.479 ;
     RECT  9.504 84.371 14.562 84.613 ;
     RECT  16.56 84.479 40.626 84.713 ;
     RECT  2.415 83.867 2.697 84.811 ;
     RECT  3.456 83.867 3.474 84.811 ;
     RECT  0.108 84.811 0.126 84.989 ;
     RECT  2.415 84.811 3.474 84.991 ;
     RECT  2.415 84.991 3.51 85.109 ;
     RECT  107.136 85.099 107.154 85.145 ;
     RECT  9.504 84.613 14.742 85.225 ;
     RECT  15.624 84.065 15.642 85.225 ;
     RECT  16.56 84.713 40.497 85.225 ;
     RECT  9.504 85.225 40.497 85.253 ;
     RECT  5.472 84.299 8.097 85.559 ;
     RECT  5.724 85.559 8.097 85.685 ;
     RECT  2.415 85.109 2.697 86.575 ;
     RECT  2.304 86.575 2.697 86.611 ;
     RECT  3.456 85.109 3.474 86.611 ;
     RECT  48.564 86.575 48.582 86.611 ;
     RECT  2.304 86.611 3.474 86.621 ;
     RECT  5.724 85.685 6.786 86.635 ;
     RECT  2.415 86.621 3.474 86.669 ;
     RECT  5.112 86.635 6.786 86.765 ;
     RECT  48.528 86.611 48.582 86.845 ;
     RECT  9.684 85.253 40.497 86.999 ;
     RECT  45.615 59.099 45.897 87.079 ;
     RECT  48.528 86.845 48.69 87.079 ;
     RECT  45.615 87.079 46.206 87.115 ;
     RECT  47.772 86.971 47.79 87.115 ;
     RECT  48.528 87.079 49.014 87.115 ;
     RECT  43.92 87.007 43.938 87.151 ;
     RECT  44.82 87.115 46.242 87.151 ;
     RECT  43.884 87.151 46.638 87.277 ;
     RECT  56.415 53.015 56.697 87.355 ;
     RECT  43.452 87.277 46.638 87.385 ;
     RECT  47.448 87.115 49.014 87.385 ;
     RECT  43.452 87.385 49.014 87.421 ;
     RECT  107.136 85.867 107.154 87.449 ;
     RECT  43.02 87.421 49.014 87.511 ;
     RECT  56.415 87.355 56.898 87.539 ;
     RECT  42.768 87.511 49.014 87.655 ;
     RECT  42.48 87.655 49.014 87.691 ;
     RECT  57.528 87.691 57.546 87.773 ;
     RECT  9.684 86.999 38.862 87.781 ;
     RECT  39.744 86.999 40.497 87.781 ;
     RECT  42.48 87.691 49.338 87.809 ;
     RECT  5.724 86.765 6.786 88.051 ;
     RECT  43.776 87.809 49.338 88.079 ;
     RECT  43.776 88.079 47.25 88.115 ;
     RECT  5.544 88.051 6.786 88.123 ;
     RECT  106.596 88.159 106.614 88.205 ;
     RECT  5.544 88.123 6.858 88.223 ;
     RECT  44.316 88.115 47.25 88.223 ;
     RECT  3.456 86.669 3.474 88.231 ;
     RECT  41.328 88.195 41.346 88.231 ;
     RECT  48.06 88.079 49.338 88.231 ;
     RECT  48.06 88.231 49.374 88.253 ;
     RECT  9.684 87.781 40.497 88.321 ;
     RECT  41.328 88.231 41.418 88.321 ;
     RECT  42.48 87.809 43.038 88.321 ;
     RECT  4.536 88.231 4.698 88.349 ;
     RECT  44.856 88.223 44.874 88.349 ;
     RECT  45.615 88.223 46.71 88.349 ;
     RECT  3.456 88.231 3.582 88.385 ;
     RECT  48.348 88.253 49.374 88.385 ;
     RECT  4.536 88.349 4.554 88.493 ;
     RECT  9.684 88.321 41.418 88.501 ;
     RECT  42.156 88.321 43.038 88.501 ;
     RECT  102.276 83.029 102.294 88.501 ;
     RECT  103.5 58.991 103.518 88.501 ;
     RECT  9.684 88.501 43.038 88.541 ;
     RECT  34.38 88.541 43.038 88.655 ;
     RECT  48.42 88.385 49.374 88.931 ;
     RECT  107.172 88.897 107.19 88.973 ;
     RECT  48.6 88.931 49.374 89.041 ;
     RECT  7.815 85.685 8.097 89.131 ;
     RECT  45.615 88.349 45.897 89.131 ;
     RECT  34.776 88.655 43.038 89.159 ;
     RECT  45 89.131 45.897 89.227 ;
     RECT  34.776 89.159 42.174 89.231 ;
     RECT  46.764 89.131 46.782 89.261 ;
     RECT  54.72 89.131 54.738 89.261 ;
     RECT  7.815 89.131 8.19 89.275 ;
     RECT  34.776 89.231 40.842 89.303 ;
     RECT  42.012 89.231 42.174 89.303 ;
     RECT  40.215 89.303 40.626 89.429 ;
     RECT  42.012 89.303 42.03 89.429 ;
     RECT  43.02 89.159 43.038 89.429 ;
     RECT  7.815 89.275 8.262 89.437 ;
     RECT  9.684 88.541 33.57 89.437 ;
     RECT  44.964 89.227 45.897 89.453 ;
     RECT  5.544 88.223 6.786 89.473 ;
     RECT  5.544 89.473 7.002 89.581 ;
     RECT  7.74 89.437 8.262 89.581 ;
     RECT  34.776 89.303 39.474 89.671 ;
     RECT  106.596 89.701 106.614 89.741 ;
     RECT  4.716 89.707 4.734 89.851 ;
     RECT  5.544 89.581 8.262 89.851 ;
     RECT  9.108 89.437 33.57 89.851 ;
     RECT  48.6 89.041 49.698 89.851 ;
     RECT  4.572 89.851 33.57 89.941 ;
     RECT  102.276 88.501 103.518 89.941 ;
     RECT  4.572 89.941 33.714 90.005 ;
     RECT  34.488 89.671 39.474 90.005 ;
     RECT  102.276 89.941 103.77 90.013 ;
     RECT  104.616 56.021 105.297 90.013 ;
     RECT  36.18 90.005 39.474 90.041 ;
     RECT  48.6 89.851 49.878 90.085 ;
     RECT  67.215 49.469 67.497 90.235 ;
     RECT  48.6 90.085 50.058 90.391 ;
     RECT  67.215 90.235 67.698 90.391 ;
     RECT  34.488 90.005 35.37 90.481 ;
     RECT  36.18 90.041 39.402 90.509 ;
     RECT  4.716 90.005 33.714 90.517 ;
     RECT  34.452 90.481 35.37 90.517 ;
     RECT  48.6 90.391 50.202 90.517 ;
     RECT  51.015 55.139 51.297 90.517 ;
     RECT  36.18 90.509 38.106 90.545 ;
     RECT  38.88 90.509 39.078 90.545 ;
     RECT  107.136 90.475 107.154 90.545 ;
     RECT  38.88 90.545 38.898 90.581 ;
     RECT  67.215 90.391 68.022 90.605 ;
     RECT  102.276 90.013 105.297 90.653 ;
     RECT  48.6 90.517 51.297 90.661 ;
     RECT  4.716 90.517 35.37 90.751 ;
     RECT  47.376 90.625 47.394 90.779 ;
     RECT  48.168 90.661 51.297 90.779 ;
     RECT  4.572 90.751 35.37 90.787 ;
     RECT  36.18 90.545 37.746 90.787 ;
     RECT  3.456 88.385 3.474 90.811 ;
     RECT  4.572 90.787 37.746 90.811 ;
     RECT  49.572 90.779 50.202 90.815 ;
     RECT  3.456 90.811 37.746 90.851 ;
     RECT  48.168 90.779 48.51 90.895 ;
     RECT  49.572 90.815 49.662 90.923 ;
     RECT  47.232 90.895 47.25 90.931 ;
     RECT  46.764 90.931 47.25 90.941 ;
     RECT  42.768 90.859 42.786 91.049 ;
     RECT  49.644 90.923 49.662 91.049 ;
     RECT  48.024 90.895 48.51 91.085 ;
     RECT  46.764 90.941 46.782 91.121 ;
     RECT  48.492 91.085 48.51 91.121 ;
     RECT  4.428 90.851 37.746 91.193 ;
     RECT  107.172 91.165 107.19 91.277 ;
     RECT  4.428 91.193 37.17 91.355 ;
     RECT  2.415 86.669 2.697 91.435 ;
     RECT  102.348 90.653 105.297 91.435 ;
     RECT  101.988 91.435 105.297 91.499 ;
     RECT  2.304 91.435 2.697 91.517 ;
     RECT  4.428 91.355 36.99 91.589 ;
     RECT  104.364 91.499 105.297 91.633 ;
     RECT  4.428 91.589 36.954 91.733 ;
     RECT  3.456 90.851 3.582 91.741 ;
     RECT  4.428 91.733 14.562 91.741 ;
     RECT  99.615 78.511 101.25 91.975 ;
     RECT  101.988 91.499 103.446 91.975 ;
     RECT  106.596 92.005 106.614 92.045 ;
     RECT  15.336 91.733 36.63 92.129 ;
     RECT  2.415 91.517 2.697 92.371 ;
     RECT  3.456 91.741 14.562 92.371 ;
     RECT  99.615 91.975 103.446 92.435 ;
     RECT  15.336 92.129 36.594 92.579 ;
     RECT  15.336 92.579 36.306 92.669 ;
     RECT  99.615 92.435 102.87 92.669 ;
     RECT  31.536 92.669 36.162 92.705 ;
     RECT  31.536 92.705 36.054 92.741 ;
     RECT  31.572 92.741 36.054 92.777 ;
     RECT  104.364 91.633 105.678 92.821 ;
     RECT  107.136 92.779 107.154 92.849 ;
     RECT  103.86 92.821 105.678 92.939 ;
     RECT  2.415 92.371 14.562 93.055 ;
     RECT  15.336 92.669 30.726 93.083 ;
     RECT  99.615 92.669 102.834 93.083 ;
     RECT  2.304 93.055 14.562 93.149 ;
     RECT  31.572 92.777 35.37 93.209 ;
     RECT  15.336 93.083 29.826 93.341 ;
     RECT  31.572 93.209 35.262 93.353 ;
     RECT  107.172 93.361 107.19 93.581 ;
     RECT  97.776 46.741 98.874 93.631 ;
     RECT  99.615 93.083 101.25 93.631 ;
     RECT  97.776 93.631 101.25 94.019 ;
     RECT  97.776 94.019 100.998 94.061 ;
     RECT  30.636 93.083 30.726 94.289 ;
     RECT  16.668 93.341 29.826 94.297 ;
     RECT  106.596 94.261 106.614 94.349 ;
     RECT  16.632 94.297 29.826 94.397 ;
     RECT  16.776 94.397 29.826 94.441 ;
     RECT  2.415 93.149 14.562 94.469 ;
     RECT  16.776 94.441 29.97 94.469 ;
     RECT  16.776 94.469 27.954 94.595 ;
     RECT  16.776 94.595 27.774 94.631 ;
     RECT  104.22 92.939 105.678 94.675 ;
     RECT  97.776 94.061 100.71 94.703 ;
     RECT  0.108 94.603 0.126 94.781 ;
     RECT  16.776 94.631 27.414 94.829 ;
     RECT  103.824 94.675 105.678 94.829 ;
     RECT  97.776 94.703 99.897 94.837 ;
     RECT  26.676 94.829 27.414 94.901 ;
     RECT  102.276 93.083 102.834 94.981 ;
     RECT  16.776 94.829 25.938 95.009 ;
     RECT  106.596 95.071 106.614 95.117 ;
     RECT  76.356 94.333 76.374 95.135 ;
     RECT  16.776 95.009 16.794 95.165 ;
     RECT  3.42 94.469 14.562 95.251 ;
     RECT  15.336 93.341 15.57 95.251 ;
     RECT  95.688 95.179 95.706 95.341 ;
     RECT  17.568 95.009 25.938 95.369 ;
     RECT  95.688 95.341 96.282 95.377 ;
     RECT  3.42 95.251 15.57 95.405 ;
     RECT  17.568 95.369 25.542 95.405 ;
     RECT  18.36 95.405 25.542 95.441 ;
     RECT  97.452 94.837 99.897 95.477 ;
     RECT  17.568 95.405 17.586 95.501 ;
     RECT  95.688 95.377 96.534 95.521 ;
     RECT  97.452 95.477 98.73 95.521 ;
     RECT  3.492 95.405 15.57 95.549 ;
     RECT  45.615 89.453 45.897 95.611 ;
     RECT  95.688 95.521 98.73 95.611 ;
     RECT  18.36 95.441 24.75 95.639 ;
     RECT  45.504 95.611 45.897 95.648 ;
     RECT  25.524 95.441 25.542 95.711 ;
     RECT  18.36 95.639 24.297 95.783 ;
     RECT  49.104 95.611 49.122 95.791 ;
     RECT  94.215 56.129 94.497 95.791 ;
     RECT  18.36 95.783 21.042 95.909 ;
     RECT  49.104 95.791 49.446 95.909 ;
     RECT  102.276 94.981 103.266 95.909 ;
     RECT  18.615 95.909 19.314 95.981 ;
     RECT  94.215 95.791 94.662 96.061 ;
     RECT  95.4 95.611 98.73 96.061 ;
     RECT  21.888 95.783 24.297 96.089 ;
     RECT  102.276 95.909 102.834 96.089 ;
     RECT  3.492 95.549 14.562 96.151 ;
     RECT  21.888 96.089 23.202 96.179 ;
     RECT  31.572 93.353 35.097 96.179 ;
     RECT  94.215 96.061 98.73 96.179 ;
     RECT  2.415 94.469 2.697 96.187 ;
     RECT  99.576 95.477 99.897 96.221 ;
     RECT  99.615 96.221 99.897 96.223 ;
     RECT  100.692 94.703 100.71 96.223 ;
     RECT  21.888 96.179 21.906 96.251 ;
     RECT  31.608 96.179 35.097 96.251 ;
     RECT  2.412 96.187 2.697 96.295 ;
     RECT  3.42 96.151 14.562 96.295 ;
     RECT  22.716 96.179 23.094 96.323 ;
     RECT  31.608 96.251 31.734 96.323 ;
     RECT  2.412 96.295 14.562 96.331 ;
     RECT  2.376 96.331 14.562 96.379 ;
     RECT  2.304 96.379 14.562 96.485 ;
     RECT  32.688 96.251 35.097 96.629 ;
     RECT  2.376 96.485 14.562 96.863 ;
     RECT  2.376 96.863 11.79 96.989 ;
     RECT  94.215 96.179 98.622 97.069 ;
     RECT  93.924 97.069 98.622 97.133 ;
     RECT  94.215 97.133 98.622 97.295 ;
     RECT  94.215 97.295 96.642 97.529 ;
     RECT  2.415 96.989 11.79 97.681 ;
     RECT  29.415 94.469 29.97 97.771 ;
     RECT  45.615 95.648 45.897 97.771 ;
     RECT  56.415 87.539 56.697 97.771 ;
     RECT  67.215 90.605 67.497 97.771 ;
     RECT  78.015 47.615 78.297 97.771 ;
     RECT  88.815 52.448 89.097 97.771 ;
     RECT  15.336 95.549 15.57 97.799 ;
     RECT  45.504 97.771 45.897 97.808 ;
     RECT  56.304 97.771 56.697 97.808 ;
     RECT  67.104 97.771 67.497 97.808 ;
     RECT  77.904 97.771 78.297 97.808 ;
     RECT  88.704 97.771 89.097 97.808 ;
     RECT  90.648 97.771 90.666 97.901 ;
     RECT  2.415 97.681 12.006 97.907 ;
     RECT  2.415 97.907 11.934 98.011 ;
     RECT  27.216 94.901 27.414 98.059 ;
     RECT  26.496 98.059 27.414 98.069 ;
     RECT  26.496 98.069 27.306 98.105 ;
     RECT  2.304 98.011 11.934 98.249 ;
     RECT  94.215 97.529 96.39 98.311 ;
     RECT  97.38 97.295 98.622 98.311 ;
     RECT  16.488 98.311 16.506 98.347 ;
     RECT  2.304 98.249 11.286 98.375 ;
     RECT  16.272 98.347 16.506 98.381 ;
     RECT  16.272 98.381 16.29 98.384 ;
     RECT  94.215 98.311 98.622 98.581 ;
     RECT  99.615 96.223 100.71 98.581 ;
     RECT  2.415 98.375 11.286 98.609 ;
     RECT  28.872 97.771 29.97 98.645 ;
     RECT  26.532 98.105 27.306 98.753 ;
     RECT  29.415 98.645 29.97 98.761 ;
     RECT  30.708 94.289 30.726 98.761 ;
     RECT  102.312 96.089 102.834 98.887 ;
     RECT  2.415 98.609 11.25 98.915 ;
     RECT  33.408 96.629 35.097 98.951 ;
     RECT  94.215 98.581 100.71 98.959 ;
     RECT  2.415 98.915 10.494 99.023 ;
     RECT  107.136 95.851 107.154 99.023 ;
     RECT  94.215 98.959 101.034 99.031 ;
     RECT  101.988 98.887 102.834 99.031 ;
     RECT  2.415 99.023 3.402 99.149 ;
     RECT  94.215 99.031 102.834 99.149 ;
     RECT  95.436 99.149 102.834 99.185 ;
     RECT  96.516 99.185 102.834 99.221 ;
     RECT  97.596 99.221 102.834 99.455 ;
     RECT  31.608 96.323 31.626 99.463 ;
     RECT  20.232 95.909 21.042 99.491 ;
     RECT  21.996 98.887 22.014 99.499 ;
     RECT  11.232 98.915 11.25 99.527 ;
     RECT  2.415 99.149 3.294 99.643 ;
     RECT  2.412 99.643 3.294 99.689 ;
     RECT  4.284 99.023 10.494 99.689 ;
     RECT  2.412 99.689 2.697 99.725 ;
     RECT  4.284 99.689 4.302 99.725 ;
     RECT  97.74 99.455 102.834 99.725 ;
     RECT  106.596 99.571 106.614 99.725 ;
     RECT  5.724 99.689 10.494 99.841 ;
     RECT  12.744 96.863 14.562 100.039 ;
     RECT  15.336 97.799 15.354 100.039 ;
     RECT  5.724 99.841 10.818 100.067 ;
     RECT  25.704 96.601 25.722 100.075 ;
     RECT  9.504 100.067 10.494 100.103 ;
     RECT  96.516 99.221 96.534 100.139 ;
     RECT  5.724 100.067 8.658 100.157 ;
     RECT  12.744 100.039 15.354 100.201 ;
     RECT  94.215 99.149 94.497 100.201 ;
     RECT  95.436 99.185 95.778 100.301 ;
     RECT  17.244 100.171 17.262 100.349 ;
     RECT  93.456 100.201 94.497 100.349 ;
     RECT  20.232 99.491 20.43 100.409 ;
     RECT  29.415 98.761 30.726 100.459 ;
     RECT  31.608 99.463 32.058 100.459 ;
     RECT  104.22 94.829 105.678 100.459 ;
     RECT  29.415 100.459 32.058 100.499 ;
     RECT  12.744 100.201 15.714 100.535 ;
     RECT  21.78 99.499 22.014 100.579 ;
     RECT  23.076 96.323 23.094 100.579 ;
     RECT  97.776 99.725 102.834 100.607 ;
     RECT  104.22 100.459 106.038 100.643 ;
     RECT  5.724 100.157 8.097 100.645 ;
     RECT  93.456 100.349 93.474 100.685 ;
     RECT  97.776 100.607 98.55 100.685 ;
     RECT  99.36 100.607 102.834 100.685 ;
     RECT  99.36 100.685 100.998 100.769 ;
     RECT  101.772 100.685 102.834 100.769 ;
     RECT  99.576 100.769 100.998 100.805 ;
     RECT  104.22 100.643 105.678 100.849 ;
     RECT  99.615 100.805 100.998 100.877 ;
     RECT  5.148 100.645 8.097 100.883 ;
     RECT  25.596 100.075 25.722 100.891 ;
     RECT  102.312 100.769 102.834 101.155 ;
     RECT  33.876 98.951 35.097 101.183 ;
     RECT  2.415 99.725 2.697 101.191 ;
     RECT  5.724 100.883 8.097 101.219 ;
     RECT  2.415 101.191 3.402 101.309 ;
     RECT  6.192 101.219 8.097 101.309 ;
     RECT  25.2 100.891 25.722 101.309 ;
     RECT  4.932 101.191 4.95 101.345 ;
     RECT  102.312 101.155 102.87 101.389 ;
     RECT  103.896 100.849 105.678 101.389 ;
     RECT  12.744 100.535 15.354 101.759 ;
     RECT  29.415 100.499 31.086 101.759 ;
     RECT  34.452 101.183 35.097 101.759 ;
     RECT  25.596 101.309 25.722 101.821 ;
     RECT  26.532 98.753 27.234 101.821 ;
     RECT  12.744 101.759 15.102 101.849 ;
     RECT  10.152 100.103 10.494 101.921 ;
     RECT  28.332 101.731 28.35 102.001 ;
     RECT  29.415 101.759 30.726 102.001 ;
     RECT  32.04 100.499 32.058 102.043 ;
     RECT  24.015 96.089 24.297 102.091 ;
     RECT  20.232 100.409 20.25 102.119 ;
     RECT  24.015 102.091 24.858 102.127 ;
     RECT  25.596 101.821 27.234 102.127 ;
     RECT  28.332 102.001 30.726 102.163 ;
     RECT  12.744 101.849 13.497 102.191 ;
     RECT  21.78 100.579 23.094 102.199 ;
     RECT  14.544 101.849 15.102 102.227 ;
     RECT  24.015 102.127 27.234 102.235 ;
     RECT  28.116 102.163 30.726 102.235 ;
     RECT  31.68 102.043 32.058 102.631 ;
     RECT  107.136 101.227 107.154 102.631 ;
     RECT  95.436 100.301 95.454 102.731 ;
     RECT  24.015 102.235 30.726 102.739 ;
     RECT  40.215 89.429 40.497 102.739 ;
     RECT  99.615 100.877 100.71 102.763 ;
     RECT  13.215 102.191 13.497 102.775 ;
     RECT  31.68 102.631 32.382 102.803 ;
     RECT  107.136 102.631 107.19 102.803 ;
     RECT  23.94 102.739 30.726 102.901 ;
     RECT  31.68 102.803 31.698 102.901 ;
     RECT  2.415 101.309 2.697 102.907 ;
     RECT  2.304 102.907 2.697 102.965 ;
     RECT  10.152 101.921 10.17 103.001 ;
     RECT  21.096 102.199 23.094 103.003 ;
     RECT  23.94 102.901 31.698 103.003 ;
     RECT  35.892 100.345 35.91 103.009 ;
     RECT  4.572 103.045 4.59 103.081 ;
     RECT  6.624 101.309 8.097 103.147 ;
     RECT  15.084 102.227 15.102 103.171 ;
     RECT  38.304 102.667 38.538 103.171 ;
     RECT  40.032 102.739 40.497 103.171 ;
     RECT  94.215 100.349 94.497 103.171 ;
     RECT  4.572 103.081 4.734 103.181 ;
     RECT  6.552 103.147 8.097 103.195 ;
     RECT  4.716 103.181 4.734 103.199 ;
     RECT  54.108 102.631 54.126 103.207 ;
     RECT  33.444 102.703 33.462 103.243 ;
     RECT  38.304 103.171 38.79 103.243 ;
     RECT  42.48 103.195 42.498 103.243 ;
     RECT  99.615 102.763 100.998 103.243 ;
     RECT  97.776 100.685 98.334 103.291 ;
     RECT  99.108 103.243 100.998 103.291 ;
     RECT  32.976 103.243 33.462 103.315 ;
     RECT  83.415 47.075 83.697 103.315 ;
     RECT  85.14 103.243 85.158 103.315 ;
     RECT  97.02 103.171 97.038 103.315 ;
     RECT  34.815 101.759 35.097 103.351 ;
     RECT  35.892 103.009 36.162 103.351 ;
     RECT  40.032 103.171 41.058 103.351 ;
     RECT  76.536 95.143 76.554 103.351 ;
     RECT  79.2 103.279 79.218 103.351 ;
     RECT  97.776 103.291 100.998 103.351 ;
     RECT  72.615 48.155 72.897 103.441 ;
     RECT  78.015 97.808 78.297 103.441 ;
     RECT  79.128 103.351 79.218 103.441 ;
     RECT  83.124 103.315 83.697 103.441 ;
     RECT  85.14 103.315 85.41 103.441 ;
     RECT  86.688 103.279 86.706 103.441 ;
     RECT  90.252 103.351 90.27 103.441 ;
     RECT  91.152 103.279 91.17 103.441 ;
     RECT  32.976 103.315 33.642 103.477 ;
     RECT  56.415 97.808 56.697 103.477 ;
     RECT  59.868 103.207 59.958 103.477 ;
     RECT  74.664 103.279 74.682 103.477 ;
     RECT  47.088 103.291 47.106 103.483 ;
     RECT  70.596 103.315 70.614 103.483 ;
     RECT  51.015 90.779 51.297 103.513 ;
     RECT  74.664 103.477 75.294 103.513 ;
     RECT  86.688 103.441 87.354 103.513 ;
     RECT  94.215 103.171 94.698 103.513 ;
     RECT  46.764 103.483 47.106 103.531 ;
     RECT  70.596 103.483 70.722 103.531 ;
     RECT  97.776 103.351 101.538 103.541 ;
     RECT  37.656 103.243 38.79 103.549 ;
     RECT  50.724 103.513 51.297 103.549 ;
     RECT  56.415 103.477 56.79 103.549 ;
     RECT  70.596 103.531 71.37 103.549 ;
     RECT  72.396 103.441 72.897 103.549 ;
     RECT  107.172 102.803 107.19 103.565 ;
     RECT  21.096 103.003 31.698 103.585 ;
     RECT  37.332 103.549 39.006 103.585 ;
     RECT  54.108 103.207 54.882 103.585 ;
     RECT  67.215 97.808 67.497 103.585 ;
     RECT  74.664 103.513 75.582 103.585 ;
     RECT  76.464 103.351 76.554 103.585 ;
     RECT  82.656 103.441 83.697 103.585 ;
     RECT  85.14 103.441 85.77 103.585 ;
     RECT  86.688 103.513 87.93 103.585 ;
     RECT  88.815 97.808 89.097 103.585 ;
     RECT  94.215 103.513 95.346 103.585 ;
     RECT  2.34 102.965 2.697 103.621 ;
     RECT  3.564 103.081 3.582 103.621 ;
     RECT  34.815 103.351 36.162 103.621 ;
     RECT  37.332 103.585 39.114 103.621 ;
     RECT  45.615 97.808 45.897 103.621 ;
     RECT  67.215 103.585 68.022 103.621 ;
     RECT  78.015 103.441 79.218 103.621 ;
     RECT  85.14 103.585 89.097 103.621 ;
     RECT  96.804 103.315 97.038 103.621 ;
     RECT  97.776 103.541 100.026 103.621 ;
     RECT  10.584 103.621 10.746 103.711 ;
     RECT  13.215 102.775 14.202 103.711 ;
     RECT  19.836 103.585 19.854 103.711 ;
     RECT  21.096 103.585 31.914 103.711 ;
     RECT  42.48 103.243 43.038 103.711 ;
     RECT  43.884 103.441 43.902 103.711 ;
     RECT  56.415 103.549 56.934 103.711 ;
     RECT  57.744 103.315 57.762 103.711 ;
     RECT  59.544 103.477 59.958 103.711 ;
     RECT  60.768 103.279 60.786 103.711 ;
     RECT  70.596 103.549 72.897 103.711 ;
     RECT  82.656 103.585 83.79 103.711 ;
     RECT  13.215 103.711 14.274 103.723 ;
     RECT  15.084 103.171 15.246 103.723 ;
     RECT  34.815 103.621 39.114 103.723 ;
     RECT  39.888 103.351 41.058 103.723 ;
     RECT  46.764 103.531 47.538 103.723 ;
     RECT  48.456 103.711 48.474 103.723 ;
     RECT  82.368 103.711 84.15 103.723 ;
     RECT  19.836 103.711 31.914 103.739 ;
     RECT  18.615 95.981 18.897 103.747 ;
     RECT  20.484 103.739 31.914 103.747 ;
     RECT  32.976 103.477 33.714 103.747 ;
     RECT  42.48 103.711 43.902 103.747 ;
     RECT  46.764 103.723 48.474 103.747 ;
     RECT  58.716 103.441 58.734 103.747 ;
     RECT  59.544 103.711 60.786 103.747 ;
     RECT  61.815 51.629 62.097 103.747 ;
     RECT  65.34 103.711 65.358 103.747 ;
     RECT  70.596 103.711 73.494 103.747 ;
     RECT  74.664 103.585 76.554 103.747 ;
     RECT  85.14 103.621 89.19 103.747 ;
     RECT  50.652 103.549 51.297 103.771 ;
     RECT  61.815 103.747 62.442 103.771 ;
     RECT  63.36 103.711 63.378 103.771 ;
     RECT  70.596 103.747 76.554 103.771 ;
     RECT  77.292 103.621 79.218 103.771 ;
     RECT  20.484 103.747 33.714 103.783 ;
     RECT  34.815 103.723 41.058 103.783 ;
     RECT  42.192 103.747 43.902 103.783 ;
     RECT  46.656 103.747 48.87 103.783 ;
     RECT  65.196 103.747 65.43 103.783 ;
     RECT  69.084 103.747 69.102 103.783 ;
     RECT  82.152 103.723 84.15 103.783 ;
     RECT  10.584 103.711 10.89 103.819 ;
     RECT  56.304 103.711 57.762 103.819 ;
     RECT  70.596 103.771 79.218 103.819 ;
     RECT  13.215 103.723 15.246 103.855 ;
     RECT  45.576 103.621 45.897 103.855 ;
     RECT  46.656 103.783 48.906 103.855 ;
     RECT  49.644 103.207 49.662 103.855 ;
     RECT  54.108 103.585 55.458 103.855 ;
     RECT  56.196 103.819 57.762 103.855 ;
     RECT  58.716 103.747 60.786 103.855 ;
     RECT  61.815 103.771 63.378 103.855 ;
     RECT  64.944 103.783 65.466 103.855 ;
     RECT  81.54 103.783 84.15 103.855 ;
     RECT  85.068 103.747 89.19 103.855 ;
     RECT  2.34 103.621 3.582 103.891 ;
     RECT  50.544 103.771 51.297 103.891 ;
     RECT  64.404 103.855 65.466 103.891 ;
     RECT  66.996 103.621 68.022 103.891 ;
     RECT  68.976 103.783 69.102 103.891 ;
     RECT  70.02 103.819 79.218 103.891 ;
     RECT  90.252 103.441 91.17 103.891 ;
     RECT  58.716 103.855 63.378 103.901 ;
     RECT  6.192 103.195 8.097 103.915 ;
     RECT  9.036 103.351 9.054 103.915 ;
     RECT  42.084 103.783 43.902 103.915 ;
     RECT  44.892 103.855 45.897 103.915 ;
     RECT  54.108 103.855 57.762 103.915 ;
     RECT  58.716 103.901 60.894 103.915 ;
     RECT  10.08 103.819 10.89 103.981 ;
     RECT  13.215 103.855 15.642 103.981 ;
     RECT  20.484 103.783 41.058 103.981 ;
     RECT  70.02 103.891 79.65 103.981 ;
     RECT  81.504 103.855 89.19 103.981 ;
     RECT  93.024 103.891 93.042 103.981 ;
     RECT  93.888 103.585 95.346 103.981 ;
     RECT  6.192 103.915 9.054 104.008 ;
     RECT  10.08 103.981 11.142 104.008 ;
     RECT  93.024 103.981 95.346 104.009 ;
     RECT  96.66 103.621 100.026 104.009 ;
     RECT  102.312 101.389 105.678 104.009 ;
     RECT  12.996 103.981 15.642 104.011 ;
     RECT  90.252 103.891 91.782 104.011 ;
     RECT  61.704 103.901 63.378 104.017 ;
     RECT  64.404 103.891 65.538 104.017 ;
     RECT  96.66 104.009 96.678 104.045 ;
     RECT  52.632 104.017 52.65 104.053 ;
     RECT  66.996 103.891 69.102 104.059 ;
     RECT  61.704 104.017 65.538 104.089 ;
     RECT  90.108 104.011 91.782 104.089 ;
     RECT  81.396 103.981 89.19 104.107 ;
     RECT  89.964 104.089 91.782 104.107 ;
     RECT  81.396 104.107 91.782 104.117 ;
     RECT  18.615 103.747 19.71 104.125 ;
     RECT  50.4 103.891 51.297 104.125 ;
     RECT  52.488 104.053 52.65 104.125 ;
     RECT  6.192 104.008 11.142 104.141 ;
     RECT  69.912 103.981 79.65 104.155 ;
     RECT  12.312 104.011 15.642 104.161 ;
     RECT  20.484 103.981 41.094 104.161 ;
     RECT  42.084 103.915 45.897 104.161 ;
     RECT  46.656 103.855 49.662 104.161 ;
     RECT  50.4 104.125 51.606 104.161 ;
     RECT  52.488 104.125 52.794 104.161 ;
     RECT  54.108 103.915 60.894 104.161 ;
     RECT  69.912 104.155 79.794 104.161 ;
     RECT  20.484 104.161 51.606 104.189 ;
     RECT  4.896 104.161 4.914 104.203 ;
     RECT  52.488 104.161 60.894 104.251 ;
     RECT  61.704 104.089 65.574 104.251 ;
     RECT  69.84 104.161 79.794 104.251 ;
     RECT  100.8 103.541 101.538 104.251 ;
     RECT  102.312 104.009 105.354 104.251 ;
     RECT  6.192 104.141 10.098 104.279 ;
     RECT  81.396 104.117 90.126 104.279 ;
     RECT  2.34 103.891 3.762 104.287 ;
     RECT  4.752 104.203 4.914 104.287 ;
     RECT  93.024 104.009 95.31 104.287 ;
     RECT  6.192 104.279 9.954 104.302 ;
     RECT  6.66 104.302 9.954 104.315 ;
     RECT  92.88 104.287 95.31 104.315 ;
     RECT  36.468 104.189 51.606 104.359 ;
     RECT  52.38 104.251 60.894 104.359 ;
     RECT  81.396 104.279 87.642 104.359 ;
     RECT  20.484 104.189 35.442 104.387 ;
     RECT  17.1 104.059 17.118 104.395 ;
     RECT  69.84 104.251 79.83 104.395 ;
     RECT  12.312 104.161 16.038 104.431 ;
     RECT  66.708 104.059 69.102 104.491 ;
     RECT  69.84 104.395 79.902 104.491 ;
     RECT  80.712 104.359 87.642 104.549 ;
     RECT  88.38 104.279 90.126 104.549 ;
     RECT  18.18 104.125 19.71 104.557 ;
     RECT  20.484 104.387 35.406 104.557 ;
     RECT  61.704 104.251 65.97 104.585 ;
     RECT  2.34 104.287 5.13 104.629 ;
     RECT  97.416 104.009 100.026 104.629 ;
     RECT  100.8 104.251 105.354 104.629 ;
     RECT  61.704 104.585 65.862 104.665 ;
     RECT  92.88 104.315 92.898 104.692 ;
     RECT  12.06 104.431 16.038 104.701 ;
     RECT  17.1 104.395 17.19 104.701 ;
     RECT  36.468 104.359 60.894 104.701 ;
     RECT  61.632 104.665 65.862 104.701 ;
     RECT  36.468 104.701 65.862 104.935 ;
     RECT  18.18 104.557 35.406 104.971 ;
     RECT  66.708 104.491 79.902 104.971 ;
     RECT  80.712 104.549 81.378 104.971 ;
     RECT  88.452 104.549 90.126 104.971 ;
     RECT  90.9 104.117 91.782 104.971 ;
     RECT  92.844 104.692 92.898 104.971 ;
     RECT  97.416 104.629 105.354 104.971 ;
     RECT  36.144 104.935 65.862 104.999 ;
     RECT  2.34 104.629 5.706 105.061 ;
     RECT  6.66 104.315 9.702 105.061 ;
     RECT  10.836 104.141 11.142 105.061 ;
     RECT  17.1 104.701 17.262 105.061 ;
     RECT  18.036 104.971 35.406 105.061 ;
     RECT  92.7 104.971 92.898 105.061 ;
     RECT  93.672 104.315 95.31 105.061 ;
     RECT  96.048 104.161 96.066 105.061 ;
     RECT  107.172 104.287 107.19 105.097 ;
     RECT  2.124 105.061 5.706 105.205 ;
     RECT  6.66 105.061 11.142 105.205 ;
     RECT  2.124 105.205 11.142 105.241 ;
     RECT  12.06 104.701 16.074 105.241 ;
     RECT  17.1 105.061 35.406 105.241 ;
     RECT  36.144 104.999 54.486 105.241 ;
     RECT  92.7 105.061 96.066 105.241 ;
     RECT  97.236 104.971 105.462 105.241 ;
     RECT  2.124 105.241 16.254 105.331 ;
     RECT  17.1 105.241 54.486 105.331 ;
     RECT  55.296 104.999 65.862 105.331 ;
     RECT  66.708 104.971 81.378 105.331 ;
     RECT  106.596 105.097 107.19 105.331 ;
     RECT  2.124 105.331 54.486 105.359 ;
     RECT  55.296 105.331 81.378 105.359 ;
     RECT  82.26 104.549 87.642 105.359 ;
     RECT  97.236 105.241 105.606 105.359 ;
     RECT  26.532 105.359 44.226 105.395 ;
     RECT  92.7 105.241 96.39 105.403 ;
     RECT  97.236 105.359 97.974 105.403 ;
     RECT  13.215 105.359 25.686 105.431 ;
     RECT  45.252 105.359 54.486 105.431 ;
     RECT  68.508 105.359 81.378 105.431 ;
     RECT  75.24 105.431 81.378 105.475 ;
     RECT  82.26 105.359 83.97 105.475 ;
     RECT  88.452 104.971 91.782 105.475 ;
     RECT  92.628 105.403 96.39 105.475 ;
     RECT  97.164 105.403 97.974 105.475 ;
     RECT  85.464 105.359 87.642 105.511 ;
     RECT  88.452 105.475 97.974 105.511 ;
     RECT  16.236 105.431 25.686 105.581 ;
     RECT  4.392 105.359 12.438 105.629 ;
     RECT  13.215 105.431 15.354 105.629 ;
     RECT  16.236 105.581 22.446 105.629 ;
     RECT  23.4 105.581 25.686 105.629 ;
     RECT  26.532 105.395 41.274 105.629 ;
     RECT  42.012 105.395 44.226 105.629 ;
     RECT  45.252 105.431 51.642 105.629 ;
     RECT  56.376 105.359 67.77 105.629 ;
     RECT  68.508 105.431 74.358 105.629 ;
     RECT  85.464 105.511 97.974 105.629 ;
     RECT  98.712 105.359 105.606 105.629 ;
     RECT  5.076 105.629 9.234 105.665 ;
     RECT  13.215 105.629 15.318 105.665 ;
     RECT  38.772 105.629 41.274 105.665 ;
     RECT  42.012 105.629 43.47 105.665 ;
     RECT  45.252 105.629 51.426 105.665 ;
     RECT  57.924 105.629 61.974 105.665 ;
     RECT  75.24 105.475 83.97 105.665 ;
     RECT  87.552 105.629 95.742 105.665 ;
     RECT  98.712 105.629 105.39 105.665 ;
     RECT  30.816 105.629 31.698 105.701 ;
     RECT  56.415 105.629 57.042 105.701 ;
     RECT  80.28 105.665 81.522 105.701 ;
     RECT  88.38 105.665 90.702 105.701 ;
     RECT  98.712 105.665 101.25 105.701 ;
     RECT  68.508 105.629 71.442 105.737 ;
     RECT  89.748 105.701 90.702 105.737 ;
     RECT  5.076 105.665 8.91 105.773 ;
     RECT  16.992 105.629 20.502 105.773 ;
     RECT  60.408 105.665 61.974 105.773 ;
     RECT  68.508 105.737 69.93 105.773 ;
     RECT  2.124 105.359 3.618 105.809 ;
     RECT  6.012 105.773 8.91 105.809 ;
     RECT  10.08 105.629 10.89 105.809 ;
     RECT  13.215 105.665 13.986 105.809 ;
     RECT  16.992 105.773 19.17 105.809 ;
     RECT  37.656 105.629 37.962 105.809 ;
     RECT  45.252 105.665 49.95 105.809 ;
     RECT  52.416 105.431 54.486 105.809 ;
     RECT  57.924 105.665 59.67 105.809 ;
     RECT  96.48 105.629 97.974 105.809 ;
     RECT  102.096 105.665 105.39 105.809 ;
     RECT  102.096 105.809 103.446 105.821 ;
     RECT  2.124 105.809 2.505 105.857 ;
     RECT  13.215 105.809 13.95 105.857 ;
     RECT  23.58 105.629 25.65 105.857 ;
     RECT  28.764 105.629 29.505 105.857 ;
     RECT  33.264 105.629 36.63 105.857 ;
     RECT  56.415 105.701 56.574 105.857 ;
     RECT  66.312 105.629 67.77 105.857 ;
     RECT  72.18 105.629 74.358 105.857 ;
     RECT  76.644 105.665 78.174 105.857 ;
     RECT  93.6 105.665 94.305 105.857 ;
     RECT  99.615 105.701 101.25 105.857 ;
     RECT  104.364 105.809 105.39 105.857 ;
     RECT  106.596 105.331 107.262 105.935 ;
     RECT  28.764 105.857 29.394 105.965 ;
     RECT  2.124 105.857 2.358 106.013 ;
     RECT  5.076 105.773 5.094 106.013 ;
     RECT  17.028 105.809 17.622 106.013 ;
     RECT  19.908 105.773 20.502 106.013 ;
     RECT  24.408 105.857 25.65 106.013 ;
     RECT  27.324 105.629 27.846 106.013 ;
     RECT  102.096 105.821 102.114 106.013 ;
     RECT  104.364 105.857 104.634 106.013 ;
     RECT  6.012 105.809 7.974 106.061 ;
     RECT  10.152 105.809 10.89 106.061 ;
     RECT  13.536 105.857 13.95 106.061 ;
     RECT  14.724 105.665 15.318 106.061 ;
     RECT  17.028 106.013 17.046 106.061 ;
     RECT  18.432 105.809 19.17 106.061 ;
     RECT  21.384 105.629 21.942 106.061 ;
     RECT  24.408 106.013 24.426 106.061 ;
     RECT  26.532 105.629 26.55 106.061 ;
     RECT  30.996 105.701 31.698 106.061 ;
     RECT  33.264 105.857 34.614 106.061 ;
     RECT  35.424 105.857 36.63 106.061 ;
     RECT  38.772 105.665 38.862 106.061 ;
     RECT  39.996 105.665 41.274 106.061 ;
     RECT  42.012 105.665 43.29 106.061 ;
     RECT  55.368 105.359 55.638 106.061 ;
     RECT  56.556 105.857 56.574 106.061 ;
     RECT  61.272 105.773 61.974 106.061 ;
     RECT  62.712 105.629 65.358 106.061 ;
     RECT  66.312 105.857 67.014 106.061 ;
     RECT  69.516 105.773 69.93 106.061 ;
     RECT  76.644 105.857 77.382 106.061 ;
     RECT  82.512 105.665 83.97 106.061 ;
     RECT  88.38 105.701 88.974 106.061 ;
     RECT  96.48 105.809 97.182 106.061 ;
     RECT  97.956 105.809 97.974 106.061 ;
     RECT  2.304 106.013 2.358 106.205 ;
     RECT  52.416 105.809 53.154 106.583 ;
     RECT  3.42 105.809 3.618 106.589 ;
     RECT  6.732 106.061 7.974 106.589 ;
     RECT  8.892 105.809 8.91 106.589 ;
     RECT  10.872 106.061 10.89 106.589 ;
     RECT  11.808 105.629 12.438 106.589 ;
     RECT  13.932 106.061 13.95 106.589 ;
     RECT  14.724 106.061 14.742 106.589 ;
     RECT  16.236 105.629 16.254 106.589 ;
     RECT  19.152 106.061 19.17 106.589 ;
     RECT  19.908 106.013 19.926 106.589 ;
     RECT  25.632 106.013 25.65 106.589 ;
     RECT  27.828 106.013 27.846 106.589 ;
     RECT  28.764 105.965 28.782 106.589 ;
     RECT  31.68 106.061 31.698 106.589 ;
     RECT  32.436 105.629 32.454 106.589 ;
     RECT  34.596 106.061 34.614 106.589 ;
     RECT  35.424 106.061 36.126 106.589 ;
     RECT  42.696 106.061 43.29 106.589 ;
     RECT  44.208 105.629 44.226 106.589 ;
     RECT  45.252 105.809 46.998 106.589 ;
     RECT  47.916 105.809 49.95 106.589 ;
     RECT  50.868 105.665 51.426 106.589 ;
     RECT  52.416 106.583 53.082 106.589 ;
     RECT  53.928 105.809 54.486 106.589 ;
     RECT  57.924 105.809 58.914 106.589 ;
     RECT  59.652 105.809 59.67 106.589 ;
     RECT  62.712 106.061 64.674 106.589 ;
     RECT  66.996 106.061 67.014 106.589 ;
     RECT  67.752 105.857 67.77 106.589 ;
     RECT  69.912 106.061 69.93 106.589 ;
     RECT  70.74 105.737 71.442 106.589 ;
     RECT  72.18 105.857 72.198 106.589 ;
     RECT  73.044 105.857 74.358 106.589 ;
     RECT  77.364 106.061 77.382 106.589 ;
     RECT  78.984 105.665 79.398 106.589 ;
     RECT  80.28 105.701 80.298 106.589 ;
     RECT  83.232 106.061 83.97 106.589 ;
     RECT  84.708 105.359 84.726 106.589 ;
     RECT  85.464 105.629 86.814 106.589 ;
     RECT  87.552 105.665 87.57 106.589 ;
     RECT  89.748 105.737 89.766 106.589 ;
     RECT  92.268 105.665 92.646 106.589 ;
     RECT  93.6 105.857 94.158 106.589 ;
     RECT  95.184 105.665 95.742 106.589 ;
     RECT  96.48 106.061 96.498 106.589 ;
     RECT  99.756 105.857 101.25 106.589 ;
     RECT  7.956 106.589 7.974 106.637 ;
     RECT  106.596 105.935 107.19 106.637 ;
     RECT  60.408 105.773 60.426 107.165 ;
     RECT  81.216 105.701 81.522 107.213 ;
     RECT  101.232 106.589 101.25 107.213 ;
     RECT  104.616 106.013 104.634 107.213 ;
     RECT  105.372 105.857 105.39 107.213 ;
     RECT  106.596 106.637 106.614 107.213 ;
     RECT  2.34 106.205 2.358 107.885 ;
     RECT  3.42 106.589 3.438 107.885 ;
     RECT  23.58 105.857 23.598 107.885 ;
     RECT  33.264 106.061 33.282 107.885 ;
     RECT  35.424 106.589 35.442 107.885 ;
     RECT  37.656 105.809 37.674 107.885 ;
     RECT  38.772 106.061 38.79 107.885 ;
     RECT  39.996 106.061 40.554 107.885 ;
     RECT  45.252 106.589 45.774 107.885 ;
     RECT  47.916 106.589 47.934 107.885 ;
     RECT  49.356 106.589 49.374 107.885 ;
     RECT  50.868 106.589 50.886 107.885 ;
     RECT  53.064 106.589 53.082 107.885 ;
     RECT  55.368 106.061 55.386 107.885 ;
     RECT  57.924 106.589 58.23 107.885 ;
     RECT  61.272 106.061 61.29 107.885 ;
     RECT  62.712 106.589 64.062 107.885 ;
     RECT  68.508 105.773 68.526 107.885 ;
     RECT  70.74 106.589 70.758 107.885 ;
     RECT  73.044 106.589 73.674 107.885 ;
     RECT  75.24 105.665 75.87 107.885 ;
     RECT  78.156 105.857 78.174 107.885 ;
     RECT  81.216 107.213 81.234 107.885 ;
     RECT  83.232 106.589 83.25 107.885 ;
     RECT  86.184 106.589 86.202 107.885 ;
     RECT  88.38 106.061 88.398 107.885 ;
     RECT  90.684 105.737 90.702 107.885 ;
     RECT  91.476 105.665 91.494 107.885 ;
     RECT  93.6 106.589 93.618 107.885 ;
     RECT  95.184 106.589 95.202 107.885 ;
     RECT  98.712 105.701 98.73 107.885 ;
     RECT  99.756 106.589 99.774 107.885 ;
    LAYER M4 ;
     RECT  0.097 55.632 0.137 55.752 ;
     RECT  1.237 0.096 1.765 0.12 ;
     RECT  2.069 105.984 2.333 106.2 ;
     RECT  2.293 3.312 2.365 3.336 ;
     RECT  1.765 0.096 2.405 0.168 ;
     RECT  2.365 2.832 2.408 3.336 ;
     RECT  0.181 53.856 2.408 54.024 ;
     RECT  0.137 55.728 2.408 55.752 ;
     RECT  2.408 1.824 2.512 105.852 ;
     RECT  2.512 1.824 2.585 105.582 ;
     RECT  2.585 2.256 2.704 105.582 ;
     RECT  2.704 65.424 2.765 65.448 ;
     RECT  2.704 26.256 2.801 26.28 ;
     RECT  2.704 75.168 2.801 75.192 ;
     RECT  2.704 2.256 2.819 4.584 ;
     RECT  2.819 2.256 2.837 2.856 ;
     RECT  2.704 27.888 2.837 27.912 ;
     RECT  2.704 63.792 2.837 63.816 ;
     RECT  2.704 70.32 2.837 70.344 ;
     RECT  2.704 71.904 2.837 71.928 ;
     RECT  2.704 97.92 2.837 98.76 ;
     RECT  2.837 2.256 2.873 2.28 ;
     RECT  2.704 40.944 2.981 40.968 ;
     RECT  2.704 55.728 2.981 55.752 ;
     RECT  2.704 67.056 3.017 67.08 ;
     RECT  2.837 98.64 3.197 98.76 ;
     RECT  1.333 107.856 3.449 107.88 ;
     RECT  3.541 106.56 3.629 106.584 ;
     RECT  2.704 30.192 3.673 30.216 ;
     RECT  2.704 43.92 3.745 43.944 ;
     RECT  2.704 96.576 3.805 96.6 ;
     RECT  2.405 0.096 3.836 0.12 ;
     RECT  3.805 95.856 3.881 96.6 ;
     RECT  3.836 0.096 3.923 0.552 ;
     RECT  3.923 0.096 3.953 0.12 ;
     RECT  2.704 93.84 3.971 94.68 ;
     RECT  2.819 4.56 4.057 4.584 ;
     RECT  4.021 49.536 4.105 49.56 ;
     RECT  3.971 94.56 4.313 94.68 ;
     RECT  4.057 4.56 4.345 4.92 ;
     RECT  3.197 98.736 4.421 98.76 ;
     RECT  2.704 103.872 4.561 103.896 ;
     RECT  4.309 105.552 4.565 105.576 ;
     RECT  4.417 9.984 4.595 10.008 ;
     RECT  4.417 16.752 4.595 16.776 ;
     RECT  2.704 36.432 4.595 36.456 ;
     RECT  4.556 68.64 4.597 68.664 ;
     RECT  2.704 90.816 4.645 90.84 ;
     RECT  4.604 92.064 4.645 92.088 ;
     RECT  4.561 103.152 4.7 103.896 ;
     RECT  4.645 90.816 4.745 92.088 ;
     RECT  4.313 94.656 4.745 94.68 ;
     RECT  4.7 103.152 4.787 104.232 ;
     RECT  4.549 18.384 4.789 18.408 ;
     RECT  2.704 23.28 4.835 23.304 ;
     RECT  3.985 62.4 4.835 62.424 ;
     RECT  4.741 99.6 4.953 99.624 ;
     RECT  4.373 1.728 5.005 1.752 ;
     RECT  4.789 18.384 5.033 19.368 ;
     RECT  3.913 70.656 5.077 70.68 ;
     RECT  3.881 95.856 5.077 95.88 ;
     RECT  4.129 96.912 5.077 96.936 ;
     RECT  4.789 25.056 5.123 25.08 ;
     RECT  3.985 56.4 5.123 56.424 ;
     RECT  4.561 59.184 5.123 59.208 ;
     RECT  4.597 67.776 5.123 68.664 ;
     RECT  5.077 70.656 5.123 71.496 ;
     RECT  5.077 95.856 5.123 96.936 ;
     RECT  4.741 100.848 5.132 100.872 ;
     RECT  2.704 86.64 5.141 86.664 ;
     RECT  5.123 95.856 5.173 96.312 ;
     RECT  5.132 100.656 5.177 100.872 ;
     RECT  5.173 95.136 5.219 96.312 ;
     RECT  5.177 100.656 5.219 100.68 ;
     RECT  4.849 92.688 5.321 93 ;
     RECT  5.321 92.784 5.425 93 ;
     RECT  4.549 11.904 5.459 11.928 ;
     RECT  5.413 13.536 5.461 13.56 ;
     RECT  4.345 3.936 5.465 4.92 ;
     RECT  5.219 96.288 5.465 96.312 ;
     RECT  5.461 13.536 5.501 13.656 ;
     RECT  4.789 63.84 5.501 63.864 ;
     RECT  5.465 4.272 5.533 4.92 ;
     RECT  5.501 13.632 5.545 13.656 ;
     RECT  5.021 105.984 5.641 106.008 ;
     RECT  5.533 4.272 5.651 5.16 ;
     RECT  4.849 76.896 5.747 76.92 ;
     RECT  5.641 105.072 5.749 106.008 ;
     RECT  5.605 6.864 5.789 6.888 ;
     RECT  5.701 78.672 5.789 78.696 ;
     RECT  5.533 88.08 5.821 88.104 ;
     RECT  3.949 61.008 5.825 61.032 ;
     RECT  4.745 91.296 5.857 91.32 ;
     RECT  2.704 53.856 5.989 53.88 ;
     RECT  5.033 19.344 6.001 19.368 ;
     RECT  5.989 52.704 6.001 52.728 ;
     RECT  2.704 51.024 6.035 51.048 ;
     RECT  4.549 15.12 6.037 15.144 ;
     RECT  6.001 18.816 6.041 19.368 ;
     RECT  5.749 105.072 6.041 106.056 ;
     RECT  6.001 52.704 6.076 52.824 ;
     RECT  5.989 53.856 6.076 54.072 ;
     RECT  6.041 18.816 6.085 19.224 ;
     RECT  5.123 71.472 6.085 71.496 ;
     RECT  5.461 0.096 6.113 0.12 ;
     RECT  6.085 71.472 6.131 72.024 ;
     RECT  3.769 75.792 6.131 75.816 ;
     RECT  3.733 80.784 6.149 80.808 ;
     RECT  4.787 103.152 6.253 104.04 ;
     RECT  6.041 105.072 6.253 105.096 ;
     RECT  4.885 98.448 6.289 98.472 ;
     RECT  4.497 37.584 6.323 37.608 ;
     RECT  2.704 81.888 6.323 81.912 ;
     RECT  4.453 84 6.323 84.024 ;
     RECT  6.253 103.152 6.323 105.096 ;
     RECT  6.289 98.448 6.325 98.712 ;
     RECT  5.641 2.688 6.329 2.712 ;
     RECT  6.323 103.152 6.337 104.28 ;
     RECT  6.277 85.632 6.364 85.656 ;
     RECT  6.325 98.112 6.373 98.712 ;
     RECT  3.685 42.72 6.419 42.744 ;
     RECT  6.332 44.832 6.419 44.856 ;
     RECT  6.037 15.12 6.437 15.192 ;
     RECT  6.277 35.328 6.469 35.352 ;
     RECT  2.704 32.976 6.515 33 ;
     RECT  4.549 8.496 6.545 8.52 ;
     RECT  6.469 34.752 6.545 35.352 ;
     RECT  6.545 34.752 6.556 34.776 ;
     RECT  6.277 38.64 6.563 38.664 ;
     RECT  6.337 103.152 6.581 104.184 ;
     RECT  6.541 86.592 6.659 86.616 ;
     RECT  5.821 87.792 6.659 88.104 ;
     RECT  5.651 4.896 6.685 5.16 ;
     RECT  6.289 46.176 6.793 46.2 ;
     RECT  5.857 90.48 6.793 91.32 ;
     RECT  6.373 41.568 6.797 41.592 ;
     RECT  5.245 39.888 6.805 39.912 ;
     RECT  6.793 46.176 6.833 46.296 ;
     RECT  6.131 72 6.901 72.024 ;
     RECT  6.793 90.48 6.973 91.464 ;
     RECT  6.565 0.576 7.081 0.6 ;
     RECT  6.085 19.2 7.148 19.224 ;
     RECT  7.081 0.096 7.165 0.6 ;
     RECT  7.148 19.2 7.189 20.184 ;
     RECT  6.833 46.272 7.225 46.296 ;
     RECT  6.076 52.8 7.237 52.824 ;
     RECT  6.001 60.96 7.477 60.984 ;
     RECT  6.901 72 7.477 72.264 ;
     RECT  5.425 92.784 7.513 93.384 ;
     RECT  5.219 95.136 7.513 95.16 ;
     RECT  5.077 26.496 7.669 26.52 ;
     RECT  7.237 52.704 7.669 52.824 ;
     RECT  6.076 53.856 7.669 53.88 ;
     RECT  7.477 58.656 7.669 58.68 ;
     RECT  7.513 92.784 7.669 95.16 ;
     RECT  7.117 96.384 7.669 96.408 ;
     RECT  6.373 98.112 7.669 98.568 ;
     RECT  6.685 3.936 7.808 5.16 ;
     RECT  6.437 15.168 7.808 15.192 ;
     RECT  7.189 19.2 7.808 21.144 ;
     RECT  7.669 25.536 7.808 26.52 ;
     RECT  7.649 27.936 7.808 27.96 ;
     RECT  5.533 31.392 7.808 31.416 ;
     RECT  6.805 39.888 7.808 40.344 ;
     RECT  7.225 46.272 7.808 46.728 ;
     RECT  7.549 47.712 7.808 47.736 ;
     RECT  7.669 52.704 7.808 53.88 ;
     RECT  5.077 57.6 7.808 57.624 ;
     RECT  7.669 58.656 7.808 58.728 ;
     RECT  7.477 60.432 7.808 60.984 ;
     RECT  7.009 65.952 7.808 65.976 ;
     RECT  5.123 67.776 7.808 67.8 ;
     RECT  7.477 71.904 7.808 72.264 ;
     RECT  6.277 80.544 7.808 80.568 ;
     RECT  6.659 88.08 7.808 88.104 ;
     RECT  6.973 89.52 7.808 91.464 ;
     RECT  7.669 92.784 7.808 96.408 ;
     RECT  7.669 98.112 7.808 99.48 ;
     RECT  6.581 103.2 7.808 104.184 ;
     RECT  6.517 106.56 7.808 106.584 ;
     RECT  7.808 2.148 7.912 106.584 ;
     RECT  7.912 106.56 7.916 106.584 ;
     RECT  7.916 106.56 8.003 106.632 ;
     RECT  7.912 2.418 8.104 105.582 ;
     RECT  8.104 57.024 8.201 58.728 ;
     RECT  8.104 89.76 8.237 95.688 ;
     RECT  8.201 57.024 8.273 58.68 ;
     RECT  7.165 0.576 8.345 0.6 ;
     RECT  8.104 80.544 8.381 80.568 ;
     RECT  8.104 52.656 8.387 54.552 ;
     RECT  8.273 57.024 8.387 58.152 ;
     RECT  8.104 73.776 8.387 73.8 ;
     RECT  8.237 89.808 8.417 95.688 ;
     RECT  8.104 21.552 8.483 21.576 ;
     RECT  8.104 65.856 8.483 66.84 ;
     RECT  8.104 61.536 8.489 62.184 ;
     RECT  8.483 65.856 8.489 66.744 ;
     RECT  8.104 49.344 8.533 50.568 ;
     RECT  8.104 47.712 8.597 47.736 ;
     RECT  8.417 89.808 8.597 90.36 ;
     RECT  8.104 38.4 8.633 40.44 ;
     RECT  8.104 100.128 8.675 100.152 ;
     RECT  8.417 91.872 8.705 95.688 ;
     RECT  8.387 52.656 8.777 53.88 ;
     RECT  8.633 39.888 8.819 40.44 ;
     RECT  8.104 42.192 8.857 42.744 ;
     RECT  8.387 57.024 8.867 57.048 ;
     RECT  8.104 71.904 8.885 72.264 ;
     RECT  8.819 39.888 8.893 40.152 ;
     RECT  8.003 106.56 8.921 106.584 ;
     RECT  8.104 44.448 8.963 44.472 ;
     RECT  8.633 38.4 9.001 38.76 ;
     RECT  8.857 42.72 9.001 42.744 ;
     RECT  8.705 91.872 9.065 94.968 ;
     RECT  8.104 103.2 9.137 104.328 ;
     RECT  9.065 91.872 9.317 93.912 ;
     RECT  8.104 88.08 9.349 88.104 ;
     RECT  9.349 87.792 9.395 88.104 ;
     RECT  9.065 94.944 9.395 94.968 ;
     RECT  8.104 84.288 9.432 84.312 ;
     RECT  9.404 70.704 9.445 70.728 ;
     RECT  8.885 71.904 9.445 72.168 ;
     RECT  8.104 98.352 9.457 98.376 ;
     RECT  9.445 70.704 9.491 72.168 ;
     RECT  9.395 87.792 9.539 87.816 ;
     RECT  8.489 65.856 9.541 65.976 ;
     RECT  8.104 46.272 9.637 46.296 ;
     RECT  9.541 64.944 9.641 65.976 ;
     RECT  8.104 76.368 9.701 76.392 ;
     RECT  8.597 89.808 9.709 90.072 ;
     RECT  8.677 0.096 9.779 0.12 ;
     RECT  9.445 105.504 9.785 105.528 ;
     RECT  9.641 65.856 9.829 65.976 ;
     RECT  9.709 67.248 9.829 67.272 ;
     RECT  9.829 65.856 9.875 67.272 ;
     RECT  8.533 49.344 9.889 50.232 ;
     RECT  8.777 52.752 9.925 53.88 ;
     RECT  8.104 25.536 9.929 25.56 ;
     RECT  8.489 62.16 9.929 62.184 ;
     RECT  9.491 71.184 9.929 72.168 ;
     RECT  9.709 89.808 9.961 90.504 ;
     RECT  9.925 52.608 10.033 53.88 ;
     RECT  9.637 45.552 10.069 46.296 ;
     RECT  9.889 49.344 10.069 51.048 ;
     RECT  9.317 91.872 10.105 93.432 ;
     RECT  10.124 106.032 10.211 106.056 ;
     RECT  8.104 3.024 10.213 5.256 ;
     RECT  9.961 63.792 10.213 63.816 ;
     RECT  10.177 95.952 10.213 95.976 ;
     RECT  9.529 47.904 10.249 47.928 ;
     RECT  10.069 48.912 10.249 51.048 ;
     RECT  8.104 55.68 10.249 55.704 ;
     RECT  10.069 45.552 10.261 46.488 ;
     RECT  9.961 89.568 10.289 90.504 ;
     RECT  10.261 45.504 10.307 46.632 ;
     RECT  9.929 71.184 10.307 71.928 ;
     RECT  10.105 91.728 10.357 93.432 ;
     RECT  10.249 47.904 10.361 51.048 ;
     RECT  10.289 89.856 10.361 90.504 ;
     RECT  10.261 0.576 10.397 0.6 ;
     RECT  9.709 69.312 10.421 69.336 ;
     RECT  10.361 50.832 10.429 51.048 ;
     RECT  10.421 68.4 10.46 69.336 ;
     RECT  10.307 45.504 10.469 45.576 ;
     RECT  9.875 66.72 10.501 67.272 ;
     RECT  10.46 68.304 10.501 69.336 ;
     RECT  10.501 66.72 10.505 69.336 ;
     RECT  10.429 50.832 10.537 51.288 ;
     RECT  10.033 52.32 10.537 53.88 ;
     RECT  10.505 66.72 10.547 68.328 ;
     RECT  10.469 45.552 10.577 45.576 ;
     RECT  9.701 76.368 10.577 76.968 ;
     RECT  10.213 2.88 10.685 5.256 ;
     RECT  9.457 98.112 10.717 98.376 ;
     RECT  10.213 95.952 10.721 96.072 ;
     RECT  10.361 47.904 10.753 49.368 ;
     RECT  8.104 75.264 10.753 75.288 ;
     RECT  10.213 63.792 10.789 64.296 ;
     RECT  10.753 75.264 10.789 75.816 ;
     RECT  10.721 96.048 10.789 96.072 ;
     RECT  10.753 47.856 10.793 49.368 ;
     RECT  10.547 66.72 10.793 67.656 ;
     RECT  10.307 71.184 10.825 71.832 ;
     RECT  10.789 74.64 10.825 75.816 ;
     RECT  10.717 97.488 10.835 98.376 ;
     RECT  9.637 56.976 10.837 57 ;
     RECT  8.387 58.08 10.837 58.152 ;
     RECT  10.577 76.944 10.837 76.968 ;
     RECT  10.501 78.096 10.837 78.12 ;
     RECT  10.789 79.152 10.837 79.176 ;
     RECT  10.537 50.832 10.861 53.88 ;
     RECT  10.249 54.864 10.861 55.704 ;
     RECT  10.837 56.976 10.861 58.152 ;
     RECT  10.141 59.184 10.861 59.208 ;
     RECT  10.789 96.048 10.865 96.312 ;
     RECT  10.861 56.976 10.883 59.208 ;
     RECT  10.837 79.152 10.883 79.848 ;
     RECT  10.793 66.72 10.897 67.56 ;
     RECT  10.844 25.632 10.931 25.656 ;
     RECT  10.861 50.832 10.973 55.704 ;
     RECT  10.835 98.112 10.973 98.376 ;
     RECT  10.973 52.752 10.981 55.704 ;
     RECT  10.883 56.976 10.981 57.336 ;
     RECT  10.883 58.368 11.041 59.208 ;
     RECT  10.321 60.72 11.041 60.744 ;
     RECT  10.505 69.312 11.045 69.336 ;
     RECT  10.981 52.752 11.068 57.336 ;
     RECT  11.068 52.752 11.081 56.04 ;
     RECT  10.789 63.216 11.113 64.296 ;
     RECT  11.081 52.752 11.153 54.744 ;
     RECT  9.137 103.2 11.153 104.28 ;
     RECT  9.637 43.776 11.185 43.8 ;
     RECT  10.307 46.608 11.189 46.632 ;
     RECT  10.361 90.48 11.225 90.504 ;
     RECT  11.041 58.368 11.297 60.744 ;
     RECT  10.793 47.856 11.329 47.88 ;
     RECT  10.973 50.832 11.329 51.768 ;
     RECT  10.883 79.824 11.329 79.848 ;
     RECT  11.185 43.728 11.363 44.088 ;
     RECT  10.825 74.016 11.365 75.816 ;
     RECT  10.357 91.728 11.365 94.104 ;
     RECT  11.297 59.76 11.372 60.744 ;
     RECT  10.717 61.872 11.372 61.896 ;
     RECT  10.748 0.096 11.405 0.12 ;
     RECT  11.372 59.76 11.413 61.896 ;
     RECT  11.113 63.216 11.413 65.544 ;
     RECT  11.413 63.216 11.441 65.592 ;
     RECT  11.413 59.76 11.459 62.184 ;
     RECT  11.329 79.824 11.513 80.616 ;
     RECT  10.793 48.96 11.545 49.368 ;
     RECT  11.329 50.736 11.545 51.768 ;
     RECT  10.837 76.944 11.621 78.12 ;
     RECT  10.825 70.704 11.689 71.832 ;
     RECT  11.365 73.344 11.689 75.816 ;
     RECT  11.297 58.368 11.729 58.776 ;
     RECT  11.441 63.504 11.729 65.592 ;
     RECT  11.729 63.504 11.843 65.544 ;
     RECT  11.329 47.088 11.869 47.88 ;
     RECT  11.545 48.96 11.869 51.768 ;
     RECT  11.797 0.528 11.891 0.552 ;
     RECT  11.689 70.704 11.905 75.816 ;
     RECT  11.869 47.088 11.941 51.768 ;
     RECT  11.153 52.752 11.941 53.016 ;
     RECT  11.905 70.512 11.941 75.816 ;
     RECT  11.621 76.944 11.941 77.592 ;
     RECT  11.365 91.008 11.941 94.104 ;
     RECT  8.893 40.128 11.948 40.152 ;
     RECT  11.941 91.008 11.987 95.16 ;
     RECT  11.948 40.128 12.035 40.536 ;
     RECT  10.865 96.288 12.045 96.312 ;
     RECT  11.941 70.512 12.049 77.592 ;
     RECT  10.897 66.576 12.089 67.56 ;
     RECT  11.941 47.088 12.121 53.016 ;
     RECT  12.089 66.768 12.193 67.56 ;
     RECT  11.653 68.832 12.193 68.952 ;
     RECT  11.068 57.024 12.197 57.336 ;
     RECT  11.301 42.192 12.229 42.216 ;
     RECT  11.729 58.752 12.373 58.776 ;
     RECT  11.459 59.76 12.373 61.08 ;
     RECT  12.193 66.768 12.373 68.952 ;
     RECT  12.121 47.088 12.409 53.112 ;
     RECT  11.153 54.096 12.409 54.744 ;
     RECT  12.157 88.176 12.409 88.2 ;
     RECT  10.861 106.56 12.449 106.584 ;
     RECT  12.373 0.096 12.457 0.12 ;
     RECT  11.843 63.504 12.481 65.256 ;
     RECT  12.229 42.192 12.517 42.744 ;
     RECT  11.363 43.776 12.517 44.088 ;
     RECT  11.459 62.16 12.589 62.184 ;
     RECT  12.481 63.216 12.589 65.256 ;
     RECT  12.373 66.768 12.613 69.288 ;
     RECT  12.049 70.272 12.613 77.592 ;
     RECT  12.409 47.088 12.661 54.744 ;
     RECT  12.373 58.752 12.709 61.08 ;
     RECT  12.517 41.568 12.733 44.088 ;
     RECT  11.545 45.12 12.733 45.144 ;
     RECT  11.513 80.064 12.757 80.616 ;
     RECT  12.733 41.568 12.805 45.144 ;
     RECT  12.661 46.176 12.805 54.744 ;
     RECT  12.589 62.16 12.841 65.256 ;
     RECT  9.432 84.288 12.853 84.36 ;
     RECT  12.757 85.488 12.853 85.512 ;
     RECT  12.035 40.128 13.021 40.152 ;
     RECT  11.153 103.2 13.021 104.184 ;
     RECT  12.613 66.768 13.057 77.592 ;
     RECT  12.841 62.112 13.093 65.256 ;
     RECT  13.057 66.768 13.093 78.12 ;
     RECT  12.853 84.288 13.093 85.512 ;
     RECT  11.473 86.592 13.093 86.616 ;
     RECT  12.409 88.176 13.093 88.92 ;
     RECT  13.093 84.288 13.201 86.616 ;
     RECT  13.093 88.176 13.201 89.928 ;
     RECT  10.685 3.024 13.208 5.256 ;
     RECT  8.104 15.168 13.208 15.192 ;
     RECT  8.104 31.392 13.208 31.416 ;
     RECT  10.885 33.312 13.208 33.336 ;
     RECT  9.001 38.4 13.208 38.424 ;
     RECT  13.021 40.128 13.208 40.584 ;
     RECT  12.805 41.568 13.208 54.744 ;
     RECT  11.081 55.968 13.208 56.04 ;
     RECT  12.197 57.12 13.208 57.336 ;
     RECT  12.709 58.656 13.208 61.08 ;
     RECT  13.093 62.112 13.208 78.12 ;
     RECT  12.757 80.064 13.208 80.904 ;
     RECT  12.841 81.984 13.208 82.008 ;
     RECT  12.812 83.136 13.208 83.16 ;
     RECT  13.201 84.288 13.208 89.928 ;
     RECT  11.987 91.008 13.208 91.176 ;
     RECT  11.987 92.352 13.208 95.16 ;
     RECT  10.973 98.352 13.208 98.376 ;
     RECT  13.021 103.2 13.208 104.664 ;
     RECT  13.141 106.032 13.208 106.056 ;
     RECT  13.208 2.148 13.312 106.056 ;
     RECT  12.86 1.104 13.475 1.128 ;
     RECT  13.312 2.418 13.504 106.056 ;
     RECT  13.504 106.032 13.565 106.056 ;
     RECT  13.504 62.448 13.601 65.592 ;
     RECT  13.504 60.432 13.637 61.416 ;
     RECT  13.504 85.728 13.715 89.544 ;
     RECT  13.504 56.64 13.745 59.256 ;
     RECT  13.504 2.832 13.781 5.256 ;
     RECT  13.504 84.288 13.781 84.696 ;
     RECT  13.601 62.448 13.817 63.816 ;
     RECT  13.504 66.768 13.817 71.304 ;
     RECT  13.504 72.384 13.889 78.12 ;
     RECT  13.715 88.368 13.889 89.544 ;
     RECT  13.504 79.248 14.249 82.104 ;
     RECT  13.817 66.768 14.285 67.896 ;
     RECT  13.745 56.64 14.321 59.064 ;
     RECT  13.601 65.184 14.321 65.592 ;
     RECT  13.889 72.384 14.429 74.232 ;
     RECT  13.504 39.6 14.465 40.584 ;
     RECT  13.504 42.144 14.465 42.216 ;
     RECT  13.504 46.512 14.465 54.696 ;
     RECT  14.429 72.432 14.465 74.232 ;
     RECT  14.465 46.512 14.537 53.88 ;
     RECT  13.957 0.096 14.545 0.12 ;
     RECT  13.715 85.728 14.609 87.288 ;
     RECT  13.504 44.16 14.717 45.528 ;
     RECT  13.861 106.56 14.753 106.584 ;
     RECT  14.821 91.2 14.857 91.224 ;
     RECT  13.637 60.432 14.861 61.224 ;
     RECT  14.285 67.344 14.897 67.896 ;
     RECT  13.817 62.448 14.965 63.384 ;
     RECT  14.249 79.248 14.969 81.24 ;
     RECT  13.504 103.2 14.969 104.664 ;
     RECT  14.537 46.704 15.077 47.304 ;
     RECT  14.321 57.12 15.077 59.064 ;
     RECT  14.465 72.432 15.077 73.896 ;
     RECT  13.889 75.216 15.077 78.12 ;
     RECT  14.537 48.432 15.113 53.88 ;
     RECT  15.077 57.6 15.113 59.064 ;
     RECT  14.609 85.728 15.113 86.664 ;
     RECT  13.889 88.656 15.181 89.544 ;
     RECT  15.013 64.992 15.185 65.016 ;
     RECT  14.969 80.592 15.217 81.24 ;
     RECT  15.181 88.656 15.217 89.976 ;
     RECT  15.013 0.576 15.293 0.6 ;
     RECT  14.897 67.344 15.325 67.848 ;
     RECT  14.965 62.448 15.361 63.816 ;
     RECT  15.113 48.432 15.395 52.488 ;
     RECT  15.289 106.032 15.395 106.056 ;
     RECT  15.113 86.256 15.401 86.664 ;
     RECT  15.077 72.432 15.437 73.8 ;
     RECT  14.857 90.96 15.437 91.224 ;
     RECT  13.817 68.928 15.443 71.304 ;
     RECT  14.465 42.144 15.509 42.168 ;
     RECT  15.217 80.592 15.589 81.432 ;
     RECT  13.504 38.4 15.637 38.424 ;
     RECT  15.361 62.448 15.649 64.392 ;
     RECT  14.969 79.248 15.649 79.272 ;
     RECT  15.569 82.656 15.653 82.68 ;
     RECT  15.589 80.592 15.676 81.48 ;
     RECT  13.504 31.392 15.683 31.416 ;
     RECT  15.637 37.632 15.685 38.424 ;
     RECT  14.465 39.6 15.685 39.624 ;
     RECT  15.685 37.632 15.725 39.624 ;
     RECT  15.676 80.592 15.725 81.432 ;
     RECT  14.861 60.432 15.757 60.456 ;
     RECT  15.325 67.248 15.758 67.848 ;
     RECT  15.113 53.568 15.793 53.88 ;
     RECT  14.965 55.152 15.793 55.176 ;
     RECT  15.758 67.248 15.865 67.8 ;
     RECT  15.217 87.792 15.865 89.976 ;
     RECT  14.717 44.496 15.901 45.528 ;
     RECT  15.077 75.216 15.923 78.024 ;
     RECT  15.725 37.632 15.971 38.808 ;
     RECT  15.757 60.144 16.009 60.456 ;
     RECT  15.649 61.536 16.009 64.392 ;
     RECT  15.649 79.008 16.009 79.272 ;
     RECT  15.725 80.592 16.009 81 ;
     RECT  15.865 66.912 16.121 67.8 ;
     RECT  15.113 57.648 16.153 59.064 ;
     RECT  16.009 60.144 16.153 64.392 ;
     RECT  15.395 48.48 16.193 52.488 ;
     RECT  15.793 53.568 16.22 55.176 ;
     RECT  15.865 56.4 16.22 56.424 ;
     RECT  16.069 106.56 16.265 106.584 ;
     RECT  15.901 44.448 16.297 45.528 ;
     RECT  16.22 53.568 16.307 56.424 ;
     RECT  15.865 87.792 16.337 90.072 ;
     RECT  16.153 57.648 16.405 64.392 ;
     RECT  16.364 65.52 16.405 65.544 ;
     RECT  15.437 72.48 16.405 73.752 ;
     RECT  13.504 33.408 16.441 33.432 ;
     RECT  16.307 53.568 16.441 55.272 ;
     RECT  15.443 68.928 16.441 71.208 ;
     RECT  16.405 72.48 16.441 73.992 ;
     RECT  16.405 57.648 16.451 65.544 ;
     RECT  16.307 56.4 16.481 56.424 ;
     RECT  16.451 57.648 16.499 65.016 ;
     RECT  16.297 44.352 16.513 45.528 ;
     RECT  15.077 47.28 16.513 47.304 ;
     RECT  15.971 38.016 16.547 38.808 ;
     RECT  16.193 48.48 16.547 51.864 ;
     RECT  16.441 68.928 16.547 73.992 ;
     RECT  16.547 48.48 16.553 51.72 ;
     RECT  16.513 44.352 16.597 47.304 ;
     RECT  13.781 84.288 16.657 84.312 ;
     RECT  16.337 87.792 16.661 89.304 ;
     RECT  16.261 93.312 16.693 93.336 ;
     RECT  15.685 42.768 16.697 42.792 ;
     RECT  16.597 47.28 16.765 47.304 ;
     RECT  16.553 48.48 16.765 49.368 ;
     RECT  16.547 68.928 16.765 68.952 ;
     RECT  16.009 79.008 16.789 81 ;
     RECT  16.657 83.904 16.789 84.312 ;
     RECT  16.547 38.16 16.805 38.808 ;
     RECT  16.499 57.648 16.805 64.44 ;
     RECT  16.693 93.312 16.835 94.104 ;
     RECT  13.504 15.168 16.873 15.192 ;
     RECT  16.789 79.008 16.876 81.192 ;
     RECT  15.541 41.568 16.913 41.592 ;
     RECT  16.876 79.008 16.913 80.904 ;
     RECT  16.789 83.904 16.931 84.984 ;
     RECT  16.661 87.792 16.931 88.92 ;
     RECT  15.923 75.216 16.981 77.976 ;
     RECT  16.873 15.168 17.053 15.336 ;
     RECT  16.805 57.648 17.053 57.96 ;
     RECT  16.981 75.168 17.053 77.976 ;
     RECT  16.981 90.528 17.053 90.552 ;
     RECT  16.789 106.032 17.057 106.056 ;
     RECT  15.685 100.224 17.077 100.344 ;
     RECT  15.401 86.592 17.089 86.664 ;
     RECT  16.441 52.992 17.161 55.272 ;
     RECT  17.077 100.224 17.219 100.92 ;
     RECT  17.219 100.224 17.233 100.344 ;
     RECT  17.233 100.176 17.273 100.344 ;
     RECT  16.931 83.904 17.363 84.312 ;
     RECT  17.053 75.12 17.372 77.976 ;
     RECT  16.441 33.408 17.411 34.248 ;
     RECT  17.363 83.904 17.411 84.216 ;
     RECT  16.121 66.912 17.413 66.936 ;
     RECT  17.411 33.408 17.453 33.576 ;
     RECT  17.161 52.944 17.453 55.272 ;
     RECT  17.372 75.12 17.459 78.024 ;
     RECT  16.913 79.008 17.459 80.856 ;
     RECT  17.125 41.04 17.489 41.064 ;
     RECT  17.413 66.096 17.557 66.936 ;
     RECT  13.504 95.136 17.557 95.16 ;
     RECT  16.597 44.352 17.593 46.104 ;
     RECT  16.765 47.28 17.593 49.368 ;
     RECT  17.053 57.12 17.593 57.96 ;
     RECT  17.557 95.136 17.597 95.496 ;
     RECT  16.805 58.992 17.629 64.44 ;
     RECT  17.053 90.528 17.629 90.84 ;
     RECT  17.549 105.984 17.633 106.008 ;
     RECT  17.411 83.904 17.66 83.928 ;
     RECT  17.593 44.352 17.773 49.368 ;
     RECT  17.089 85.632 17.773 86.664 ;
     RECT  17.773 44.064 17.809 49.368 ;
     RECT  17.521 42.336 17.881 42.36 ;
     RECT  17.453 52.992 17.881 55.272 ;
     RECT  17.593 56.4 17.881 57.96 ;
     RECT  16.931 88.464 17.881 88.92 ;
     RECT  16.547 69.936 17.917 73.992 ;
     RECT  17.459 75.12 17.917 77.976 ;
     RECT  17.629 90.528 17.989 91.176 ;
     RECT  17.629 58.992 18.169 64.968 ;
     RECT  17.557 66.096 18.169 67.032 ;
     RECT  17.773 85.632 18.181 87.288 ;
     RECT  17.881 88.464 18.181 88.968 ;
     RECT  17.881 42.336 18.241 42.792 ;
     RECT  18.181 85.632 18.241 88.968 ;
     RECT  15.541 0.096 18.253 0.12 ;
     RECT  16.837 32.352 18.313 32.376 ;
     RECT  18.241 85.392 18.313 88.968 ;
     RECT  17.989 90.336 18.313 91.176 ;
     RECT  17.597 95.472 18.349 95.496 ;
     RECT  18.169 58.992 18.457 67.032 ;
     RECT  16.765 68.112 18.457 68.952 ;
     RECT  18.313 85.392 18.457 91.176 ;
     RECT  16.835 93.312 18.469 93.864 ;
     RECT  16.805 38.16 18.493 38.424 ;
     RECT  17.084 39.888 18.493 39.912 ;
     RECT  18.457 58.992 18.529 68.952 ;
     RECT  17.917 69.936 18.529 77.976 ;
     RECT  13.781 3.024 18.608 5.256 ;
     RECT  17.605 7.344 18.608 7.368 ;
     RECT  17.053 14.832 18.608 15.336 ;
     RECT  18.313 31.92 18.608 32.376 ;
     RECT  17.453 33.408 18.608 33.432 ;
     RECT  18.133 36.912 18.608 36.936 ;
     RECT  18.493 38.16 18.608 40.056 ;
     RECT  18.241 42.336 18.608 43.032 ;
     RECT  17.809 44.064 18.608 49.464 ;
     RECT  16.553 50.976 18.608 51.72 ;
     RECT  17.881 52.992 18.608 57.96 ;
     RECT  18.529 58.992 18.608 77.976 ;
     RECT  17.459 79.2 18.608 80.856 ;
     RECT  17.66 83.136 18.608 83.928 ;
     RECT  18.457 85.392 18.608 91.944 ;
     RECT  18.469 93.312 18.608 94.2 ;
     RECT  18.349 95.472 18.608 95.784 ;
     RECT  13.504 98.352 18.608 98.376 ;
     RECT  17.273 100.176 18.608 100.248 ;
     RECT  14.969 103.2 18.608 104.28 ;
     RECT  18.277 106.032 18.608 106.056 ;
     RECT  18.608 2.148 18.701 106.056 ;
     RECT  18.701 1.728 18.712 106.056 ;
     RECT  18.712 1.728 18.785 105.582 ;
     RECT  18.785 2.418 18.904 105.582 ;
     RECT  18.904 84 19.001 85.704 ;
     RECT  18.904 41.76 19.037 43.032 ;
     RECT  18.904 50.736 19.043 53.88 ;
     RECT  18.904 35.664 19.073 40.056 ;
     RECT  19.043 50.736 19.109 53.784 ;
     RECT  18.904 86.832 19.139 90.936 ;
     RECT  18.904 91.968 19.181 93.864 ;
     RECT  19.001 84 19.217 85.464 ;
     RECT  18.904 30.192 19.283 33.432 ;
     RECT  19.073 37.584 19.397 40.056 ;
     RECT  18.904 64.944 19.433 66.312 ;
     RECT  19.433 65.136 19.505 66.312 ;
     RECT  18.904 56.88 19.577 63.624 ;
     RECT  19.037 42.672 19.613 43.032 ;
     RECT  19.577 56.88 19.649 59.256 ;
     RECT  18.904 67.536 19.685 77.976 ;
     RECT  19.613 42.672 19.715 42.84 ;
     RECT  19.397 37.584 19.721 38.76 ;
     RECT  18.904 47.088 19.721 49.32 ;
     RECT  19.685 67.536 19.757 73.608 ;
     RECT  18.904 14.928 19.763 15.336 ;
     RECT  18.904 25.68 19.763 25.8 ;
     RECT  19.139 90.288 19.793 90.936 ;
     RECT  19.793 90.288 19.865 90.888 ;
     RECT  19.715 42.72 19.873 42.84 ;
     RECT  19.139 86.832 19.937 89.016 ;
     RECT  18.997 106.56 19.937 106.584 ;
     RECT  19.685 75.12 19.941 77.976 ;
     RECT  18.904 79.2 19.941 81.864 ;
     RECT  18.904 3.024 20.041 5.256 ;
     RECT  19.721 37.584 20.045 37.656 ;
     RECT  18.904 103.2 20.045 104.712 ;
     RECT  19.505 65.184 20.081 66.312 ;
     RECT  19.865 90.288 20.149 90.84 ;
     RECT  19.073 35.664 20.153 36.504 ;
     RECT  19.397 39.888 20.153 40.056 ;
     RECT  18.904 44.016 20.185 45.816 ;
     RECT  20.149 90.24 20.185 90.84 ;
     RECT  19.577 60.672 20.189 63.624 ;
     RECT  19.181 91.968 20.189 91.992 ;
     RECT  20.185 44.016 20.221 45.912 ;
     RECT  19.109 50.736 20.221 51.72 ;
     RECT  19.721 47.424 20.257 49.32 ;
     RECT  20.221 50.64 20.257 51.72 ;
     RECT  19.941 75.12 20.257 81.864 ;
     RECT  19.283 30.192 20.261 30.216 ;
     RECT  20.257 47.424 20.365 51.72 ;
     RECT  19.109 52.848 20.365 53.784 ;
     RECT  19.649 56.88 20.365 59.016 ;
     RECT  18.904 54.912 20.437 55.752 ;
     RECT  20.365 56.784 20.437 59.016 ;
     RECT  20.113 66.48 20.437 66.504 ;
     RECT  19.757 67.536 20.437 68.76 ;
     RECT  19.181 93.312 20.437 93.864 ;
     RECT  19.757 69.984 20.441 73.608 ;
     RECT  19.937 87.12 20.473 89.016 ;
     RECT  20.341 1.728 20.477 1.752 ;
     RECT  20.437 66.48 20.477 68.76 ;
     RECT  20.081 65.184 20.483 65.352 ;
     RECT  20.477 66.48 20.521 67.848 ;
     RECT  20.437 93.312 20.533 94.056 ;
     RECT  18.904 95.376 20.533 95.4 ;
     RECT  20.437 54.912 20.549 59.016 ;
     RECT  20.473 105.984 20.557 106.008 ;
     RECT  20.473 87.12 20.581 89.064 ;
     RECT  20.185 90.048 20.581 90.84 ;
     RECT  20.521 66.48 20.585 66.504 ;
     RECT  20.365 47.424 20.693 53.784 ;
     RECT  20.257 75.12 20.729 81.96 ;
     RECT  20.533 93.312 20.761 95.4 ;
     RECT  20.693 51.36 20.765 53.784 ;
     RECT  20.549 54.912 20.765 58.008 ;
     RECT  20.441 69.984 20.801 73.272 ;
     RECT  20.801 69.984 20.821 70.104 ;
     RECT  20.761 92.88 20.837 95.4 ;
     RECT  20.729 81.888 20.905 81.96 ;
     RECT  18.904 82.992 20.905 83.016 ;
     RECT  20.821 69.408 20.908 70.104 ;
     RECT  20.549 58.992 20.941 59.016 ;
     RECT  20.189 60.816 20.941 63.624 ;
     RECT  20.773 64.848 20.941 64.872 ;
     RECT  20.765 54.912 21.017 55.896 ;
     RECT  20.765 56.976 21.017 58.008 ;
     RECT  20.801 71.088 21.053 73.272 ;
     RECT  21.017 54.912 21.085 55.848 ;
     RECT  20.581 87.12 21.085 90.84 ;
     RECT  20.941 60.816 21.089 64.872 ;
     RECT  19.873 42.816 21.155 42.84 ;
     RECT  21.085 87.12 21.169 91.8 ;
     RECT  19.283 32.448 21.193 33.432 ;
     RECT  19.217 84 21.193 85.416 ;
     RECT  20.521 67.824 21.233 67.848 ;
     RECT  20.837 92.88 21.233 93.864 ;
     RECT  21.053 72.912 21.251 73.272 ;
     RECT  19.763 25.776 21.265 25.8 ;
     RECT  20.045 103.2 21.301 104.184 ;
     RECT  20.221 43.92 21.337 45.912 ;
     RECT  20.765 51.648 21.337 53.784 ;
     RECT  21.337 43.92 21.377 46.2 ;
     RECT  20.837 95.136 21.445 95.4 ;
     RECT  21.193 84 21.481 86.136 ;
     RECT  21.169 87.12 21.481 90.984 ;
     RECT  21.109 41.76 21.485 41.784 ;
     RECT  21.445 95.136 21.491 95.784 ;
     RECT  21.377 44.16 21.733 46.2 ;
     RECT  20.693 47.424 21.733 50.136 ;
     RECT  21.089 61.68 21.733 64.872 ;
     RECT  20.045 37.632 21.74 37.656 ;
     RECT  19.721 38.736 21.74 38.76 ;
     RECT  21.337 51.648 21.769 53.88 ;
     RECT  20.905 81.888 21.769 83.016 ;
     RECT  21.481 84 21.769 90.984 ;
     RECT  21.301 103.2 21.769 104.568 ;
     RECT  21.769 51.312 21.805 53.88 ;
     RECT  21.085 54.864 21.805 55.848 ;
     RECT  20.908 70.08 21.805 70.104 ;
     RECT  21.053 71.088 21.805 71.736 ;
     RECT  20.729 75.12 21.805 80.856 ;
     RECT  21.017 57.456 21.841 58.008 ;
     RECT  20.941 58.992 21.841 59.64 ;
     RECT  21.769 81.888 21.989 90.984 ;
     RECT  21.205 106.032 22.019 106.056 ;
     RECT  21.193 32.448 22.025 33.672 ;
     RECT  21.74 37.632 22.069 38.76 ;
     RECT  20.153 39.888 22.069 39.912 ;
     RECT  21.841 57.456 22.165 59.64 ;
     RECT  21.805 70.08 22.201 71.736 ;
     RECT  21.989 87.216 22.205 90.984 ;
     RECT  22.069 37.632 22.211 39.912 ;
     RECT  22.165 57.456 22.211 60.552 ;
     RECT  21.805 75.024 22.237 80.856 ;
     RECT  21.989 81.888 22.237 86.232 ;
     RECT  20.153 36.48 22.241 36.504 ;
     RECT  22.025 32.448 22.273 32.76 ;
     RECT  21.805 51.312 22.309 55.848 ;
     RECT  21.233 93.456 22.309 93.864 ;
     RECT  21.733 44.16 22.345 50.136 ;
     RECT  22.309 51.264 22.345 55.848 ;
     RECT  22.211 57.456 22.345 58.488 ;
     RECT  22.201 70.08 22.417 71.928 ;
     RECT  21.251 72.912 22.417 72.936 ;
     RECT  22.309 93.456 22.453 94.44 ;
     RECT  22.453 93.36 22.525 94.44 ;
     RECT  22.345 51.168 22.529 55.848 ;
     RECT  21.553 69.024 22.561 69.048 ;
     RECT  22.417 70.08 22.561 72.936 ;
     RECT  22.529 51.168 22.565 53.88 ;
     RECT  22.565 52.512 22.637 53.88 ;
     RECT  21.541 41.232 22.652 41.256 ;
     RECT  22.652 40.416 22.693 41.256 ;
     RECT  22.211 59.808 22.705 60.552 ;
     RECT  21.733 61.68 22.705 65.544 ;
     RECT  22.693 40.416 22.739 41.64 ;
     RECT  22.739 41.232 22.741 41.64 ;
     RECT  21.625 42.72 22.741 42.744 ;
     RECT  22.345 44.016 22.741 50.136 ;
     RECT  22.205 87.264 22.781 90.984 ;
     RECT  22.565 51.168 22.813 51.288 ;
     RECT  22.693 105.552 22.817 105.576 ;
     RECT  22.705 59.808 22.835 65.544 ;
     RECT  22.525 93.312 22.849 94.44 ;
     RECT  22.211 38.928 22.853 39.336 ;
     RECT  22.849 93.264 22.885 94.44 ;
     RECT  22.853 39.024 22.925 39.336 ;
     RECT  22.273 32.16 22.961 32.76 ;
     RECT  22.835 59.808 22.961 59.832 ;
     RECT  22.781 87.264 22.961 90.888 ;
     RECT  21.491 95.76 22.989 95.784 ;
     RECT  22.561 69.024 23.029 72.936 ;
     RECT  22.237 74.928 23.029 86.232 ;
     RECT  22.211 37.632 23.033 37.656 ;
     RECT  22.835 61.008 23.033 65.544 ;
     RECT  22.885 93.264 23.132 94.68 ;
     RECT  23.033 61.392 23.137 65.544 ;
     RECT  21.877 66.816 23.137 66.84 ;
     RECT  22.981 1.728 23.141 1.752 ;
     RECT  23.029 68.736 23.173 72.936 ;
     RECT  22.529 54.864 23.317 55.848 ;
     RECT  22.345 57.024 23.317 58.488 ;
     RECT  18.904 100.224 23.317 100.248 ;
     RECT  22.741 41.232 23.353 50.136 ;
     RECT  22.813 51.12 23.353 51.288 ;
     RECT  23.173 68.736 23.365 73.032 ;
     RECT  21.769 102.96 23.389 104.568 ;
     RECT  22.961 32.736 23.468 32.76 ;
     RECT  22.777 34.464 23.468 34.488 ;
     RECT  23.137 61.392 23.605 66.84 ;
     RECT  23.413 107.856 23.609 107.88 ;
     RECT  22.637 52.704 23.713 53.88 ;
     RECT  23.317 54.864 23.713 59.256 ;
     RECT  19.285 0.096 23.717 0.12 ;
     RECT  23.468 32.736 23.852 34.488 ;
     RECT  20.041 3.024 23.893 5.304 ;
     RECT  23.533 23.376 23.893 23.4 ;
     RECT  23.852 32.736 23.893 35.064 ;
     RECT  23.713 52.704 23.929 59.256 ;
     RECT  23.365 68.592 23.929 73.032 ;
     RECT  23.893 2.88 23.965 5.304 ;
     RECT  23.929 68.4 24.001 73.032 ;
     RECT  23.965 2.832 24.008 5.304 ;
     RECT  18.904 7.344 24.008 7.368 ;
     RECT  19.763 14.928 24.008 14.952 ;
     RECT  23.893 22.752 24.008 23.4 ;
     RECT  21.265 25.776 24.008 26.232 ;
     RECT  23.42 27.6 24.008 27.624 ;
     RECT  23.461 28.8 24.008 29.208 ;
     RECT  23.893 32.736 24.008 35.928 ;
     RECT  23.857 36.912 24.008 36.936 ;
     RECT  22.925 39.024 24.008 39.24 ;
     RECT  23.353 41.232 24.008 51.288 ;
     RECT  23.929 52.704 24.008 59.592 ;
     RECT  23.605 61.392 24.008 67.416 ;
     RECT  24.001 68.4 24.008 73.08 ;
     RECT  23.029 74.064 24.008 86.232 ;
     RECT  22.961 87.264 24.008 90.792 ;
     RECT  23.132 93.264 24.008 95.64 ;
     RECT  18.904 98.352 24.008 98.376 ;
     RECT  23.317 100.224 24.008 100.92 ;
     RECT  23.389 102.96 24.008 104.712 ;
     RECT  23.965 0.528 24.083 0.552 ;
     RECT  24.008 2.148 24.112 105.852 ;
     RECT  24.112 2.418 24.181 105.852 ;
     RECT  24.181 2.418 24.304 106.056 ;
     RECT  24.304 105.984 24.437 106.056 ;
     RECT  24.304 74.784 24.473 90.888 ;
     RECT  24.304 65.952 24.508 73.32 ;
     RECT  24.304 39.024 24.509 39.24 ;
     RECT  24.304 92.88 24.563 95.208 ;
     RECT  24.473 89.424 24.581 90.888 ;
     RECT  24.509 39.024 24.617 39.048 ;
     RECT  24.304 22.704 24.653 22.776 ;
     RECT  24.304 2.88 24.689 5.304 ;
     RECT  24.563 95.184 24.689 95.208 ;
     RECT  24.304 28.512 24.697 30.264 ;
     RECT  24.565 0.576 24.761 0.6 ;
     RECT  24.304 53.568 24.796 64.968 ;
     RECT  24.304 34.128 24.797 34.488 ;
     RECT  24.304 14.928 24.803 14.952 ;
     RECT  24.437 105.984 25.085 106.008 ;
     RECT  24.563 92.88 25.229 94.152 ;
     RECT  24.304 100.896 25.229 100.92 ;
     RECT  24.304 36.672 25.235 37.272 ;
     RECT  24.797 34.224 25.265 34.488 ;
     RECT  24.304 102.96 25.297 104.568 ;
     RECT  24.304 40.416 25.333 42.744 ;
     RECT  24.304 50.88 25.333 51.768 ;
     RECT  24.304 44.448 25.369 49.32 ;
     RECT  24.796 61.392 25.369 64.968 ;
     RECT  24.508 65.952 25.369 73.224 ;
     RECT  25.265 34.464 25.373 34.488 ;
     RECT  24.304 25.776 25.379 25.8 ;
     RECT  24.796 53.568 25.379 59.88 ;
     RECT  25.369 44.208 25.405 49.32 ;
     RECT  25.333 40.272 25.427 42.744 ;
     RECT  24.697 28.512 25.429 29.112 ;
     RECT  25.333 50.688 25.441 51.768 ;
     RECT  24.473 74.784 25.441 88.152 ;
     RECT  25.369 61.392 25.445 73.224 ;
     RECT  25.427 40.272 25.477 41.544 ;
     RECT  25.429 27.744 25.516 29.112 ;
     RECT  25.441 34.752 25.525 34.776 ;
     RECT  25.445 61.536 25.549 73.224 ;
     RECT  25.441 74.688 25.549 88.152 ;
     RECT  24.581 90.864 25.549 90.888 ;
     RECT  25.297 102.864 25.549 104.664 ;
     RECT  25.229 93.84 25.553 94.152 ;
     RECT  25.549 102.864 25.585 104.856 ;
     RECT  25.516 28.272 25.589 29.112 ;
     RECT  24.653 22.704 25.619 22.728 ;
     RECT  24.581 89.424 25.621 89.448 ;
     RECT  25.441 50.592 25.625 51.768 ;
     RECT  24.304 7.344 25.66 7.368 ;
     RECT  25.405 44.208 25.667 49.608 ;
     RECT  25.093 0.096 25.669 0.12 ;
     RECT  24.697 30.24 25.697 30.264 ;
     RECT  25.621 106.56 25.705 106.584 ;
     RECT  25.549 61.536 25.715 88.152 ;
     RECT  25.427 42.72 25.717 42.744 ;
     RECT  25.667 44.208 25.717 49.272 ;
     RECT  25.585 102.768 25.717 104.856 ;
     RECT  24.304 32.448 25.765 32.76 ;
     RECT  25.717 42.72 25.804 49.272 ;
     RECT  25.717 102.768 25.804 104.952 ;
     RECT  25.765 32.448 25.805 33.096 ;
     RECT  25.715 66.096 25.841 88.152 ;
     RECT  25.379 53.616 25.873 59.88 ;
     RECT  25.477 39.36 25.877 41.544 ;
     RECT  25.715 61.536 25.877 65.016 ;
     RECT  25.804 102.768 25.901 104.856 ;
     RECT  25.873 53.616 25.913 60.408 ;
     RECT  25.901 102.048 25.916 104.856 ;
     RECT  25.625 50.592 25.945 51.624 ;
     RECT  25.841 74.784 25.945 88.152 ;
     RECT  24.304 98.352 26.003 98.376 ;
     RECT  25.916 101.952 26.003 104.856 ;
     RECT  25.841 66.096 26.057 73.8 ;
     RECT  25.801 35.424 26.125 35.448 ;
     RECT  25.235 36.672 26.125 36.696 ;
     RECT  25.573 20.544 26.129 20.568 ;
     RECT  25.804 42.72 26.129 42.744 ;
     RECT  26.117 1.728 26.201 1.752 ;
     RECT  26.125 35.424 26.243 36.696 ;
     RECT  25.877 40.272 26.273 41.544 ;
     RECT  25.913 53.616 26.273 59.112 ;
     RECT  25.877 61.536 26.273 64.92 ;
     RECT  25.621 89.424 26.273 89.496 ;
     RECT  26.273 61.536 26.345 62.856 ;
     RECT  26.273 53.616 26.377 54.696 ;
     RECT  26.345 61.536 26.417 62.568 ;
     RECT  26.057 66.096 26.417 73.56 ;
     RECT  26.377 53.568 26.485 54.696 ;
     RECT  26.417 66.096 26.525 70.056 ;
     RECT  26.389 106.032 26.561 106.056 ;
     RECT  26.413 92.736 26.665 92.76 ;
     RECT  25.945 74.784 26.669 88.344 ;
     RECT  26.125 26.736 26.677 26.76 ;
     RECT  25.589 28.272 26.677 28.296 ;
     RECT  26.677 26.736 26.723 28.296 ;
     RECT  26.669 79.104 26.741 88.344 ;
     RECT  26.723 26.736 26.764 27.336 ;
     RECT  26.485 53.136 26.773 54.696 ;
     RECT  26.525 66.096 26.777 68.712 ;
     RECT  26.417 71.04 26.785 73.56 ;
     RECT  26.777 68.256 26.813 68.712 ;
     RECT  26.764 26.736 26.849 26.76 ;
     RECT  26.741 79.104 26.849 86.76 ;
     RECT  26.485 101.424 26.849 101.448 ;
     RECT  24.304 24.624 26.881 24.648 ;
     RECT  26.273 40.272 26.881 41.256 ;
     RECT  26.243 35.424 26.885 35.448 ;
     RECT  26.881 39.888 26.965 41.256 ;
     RECT  25.945 50.4 26.993 51.624 ;
     RECT  25.804 44.208 27.061 49.272 ;
     RECT  26.849 79.104 27.065 86.616 ;
     RECT  26.003 102.768 27.065 104.856 ;
     RECT  27.061 44.208 27.097 49.512 ;
     RECT  25.553 93.84 27.097 93.864 ;
     RECT  26.424 98.064 27.155 98.088 ;
     RECT  26.273 55.68 27.157 59.112 ;
     RECT  25.913 60.384 27.173 60.408 ;
     RECT  26.813 68.256 27.173 68.28 ;
     RECT  27.097 93.84 27.181 94.584 ;
     RECT  27.065 102.768 27.205 104.712 ;
     RECT  26.741 87.792 27.209 88.344 ;
     RECT  27.157 55.68 27.244 59.208 ;
     RECT  25.805 32.688 27.26 33.096 ;
     RECT  24.689 3.024 27.277 5.304 ;
     RECT  27.26 32.688 27.301 33.624 ;
     RECT  27.097 43.872 27.313 49.512 ;
     RECT  27.301 32.688 27.347 34.248 ;
     RECT  26.125 31.344 27.349 31.368 ;
     RECT  26.993 50.544 27.349 51.624 ;
     RECT  26.773 52.8 27.349 54.696 ;
     RECT  26.669 74.784 27.349 78.12 ;
     RECT  27.244 55.68 27.353 58.248 ;
     RECT  27.109 105.984 27.353 106.008 ;
     RECT  27.349 30.192 27.389 31.368 ;
     RECT  26.917 38.64 27.389 38.664 ;
     RECT  27.349 50.544 27.389 54.696 ;
     RECT  26.777 66.096 27.389 66.84 ;
     RECT  26.665 92.688 27.421 92.76 ;
     RECT  27.277 2.976 27.461 5.304 ;
     RECT  26.881 24.624 27.5 25.128 ;
     RECT  26.785 71.04 27.529 73.32 ;
     RECT  27.421 92.544 27.569 92.76 ;
     RECT  27.5 24.624 27.587 26.232 ;
     RECT  26.417 61.92 27.605 62.568 ;
     RECT  26.273 63.888 27.713 64.92 ;
     RECT  26.243 36.672 27.749 36.696 ;
     RECT  27.569 92.544 27.821 92.712 ;
     RECT  27.347 34.224 27.857 34.248 ;
     RECT  27.209 88.272 27.893 88.344 ;
     RECT  27.821 92.544 27.925 92.568 ;
     RECT  27.529 70.656 27.929 73.32 ;
     RECT  25.549 90.768 27.929 90.888 ;
     RECT  27.925 92.256 27.965 92.568 ;
     RECT  27.929 72.48 27.997 73.32 ;
     RECT  27.349 74.736 27.997 78.12 ;
     RECT  27.065 79.104 27.997 86.184 ;
     RECT  27.313 43.824 28.033 49.512 ;
     RECT  27.389 50.544 28.033 54.36 ;
     RECT  27.587 24.624 28.073 25.128 ;
     RECT  27.997 72.48 28.141 86.184 ;
     RECT  28.141 72.48 28.145 86.472 ;
     RECT  27.605 62.544 28.175 62.568 ;
     RECT  26.965 40.368 28.213 41.256 ;
     RECT  28.033 43.824 28.213 54.36 ;
     RECT  27.713 64.416 28.285 64.92 ;
     RECT  28.073 24.624 28.289 24.648 ;
     RECT  28.213 40.368 28.3 54.36 ;
     RECT  28.145 73.296 28.321 86.472 ;
     RECT  28.3 40.368 28.333 42.792 ;
     RECT  27.389 66.816 28.357 66.84 ;
     RECT  28.357 66.672 28.393 66.84 ;
     RECT  27.205 102.624 28.397 104.712 ;
     RECT  27.637 23.52 28.405 23.544 ;
     RECT  28.405 22.608 28.429 24.504 ;
     RECT  28.321 59.232 28.429 59.256 ;
     RECT  27.353 57.024 28.433 58.248 ;
     RECT  28.175 62.544 28.453 62.712 ;
     RECT  27.347 32.688 28.501 32.712 ;
     RECT  27.889 34.752 28.501 34.776 ;
     RECT  28.069 35.904 28.501 35.928 ;
     RECT  28.3 43.824 28.501 54.36 ;
     RECT  27.353 55.68 28.501 55.944 ;
     RECT  28.433 57.024 28.501 58.104 ;
     RECT  27.181 93.84 28.537 94.056 ;
     RECT  28.501 32.688 28.645 33.048 ;
     RECT  28.172 61.2 28.753 61.224 ;
     RECT  28.453 62.544 28.753 63.096 ;
     RECT  27.929 90.864 28.753 90.888 ;
     RECT  27.965 92.256 28.753 92.28 ;
     RECT  28.177 69.408 28.789 69.432 ;
     RECT  27.929 70.656 28.789 71.4 ;
     RECT  27.817 106.56 28.793 106.584 ;
     RECT  27.389 30.192 28.933 30.888 ;
     RECT  28.789 69.408 28.933 71.4 ;
     RECT  27.893 88.272 28.969 88.296 ;
     RECT  26.273 89.424 28.969 89.448 ;
     RECT  28.753 90.864 29.029 92.28 ;
     RECT  28.753 60.816 29.077 63.096 ;
     RECT  28.285 64.416 29.077 65.016 ;
     RECT  28.969 88.272 29.077 89.448 ;
     RECT  29.029 90.48 29.077 92.28 ;
     RECT  28.933 69.408 29.113 71.496 ;
     RECT  28.321 73.296 29.173 87.288 ;
     RECT  29.113 68.448 29.221 71.496 ;
     RECT  29.221 68.4 29.269 71.496 ;
     RECT  29.173 73.248 29.269 87.288 ;
     RECT  29.077 88.272 29.269 92.28 ;
     RECT  28.537 93.84 29.269 94.344 ;
     RECT  28.397 102.672 29.269 104.712 ;
     RECT  26.677 0.096 29.363 0.12 ;
     RECT  28.393 66.288 29.401 66.84 ;
     RECT  29.317 105.936 29.405 105.96 ;
     RECT  27.461 3.024 29.408 5.304 ;
     RECT  27.889 19.536 29.408 19.56 ;
     RECT  28.429 22.224 29.408 24.504 ;
     RECT  27.587 26.208 29.408 26.232 ;
     RECT  29.401 28.512 29.408 28.536 ;
     RECT  28.933 29.52 29.408 30.888 ;
     RECT  28.645 31.92 29.408 33.048 ;
     RECT  28.501 34.752 29.408 35.928 ;
     RECT  29.401 39.312 29.408 39.336 ;
     RECT  28.333 40.368 29.408 42.216 ;
     RECT  28.501 43.824 29.408 58.104 ;
     RECT  28.429 59.232 29.408 59.592 ;
     RECT  29.077 60.816 29.408 65.016 ;
     RECT  29.401 66.288 29.408 67.32 ;
     RECT  29.269 68.4 29.408 71.736 ;
     RECT  29.269 72.816 29.408 87.288 ;
     RECT  29.269 88.272 29.408 94.344 ;
     RECT  29.269 102.672 29.408 104.904 ;
     RECT  29.408 2.148 29.512 105.852 ;
     RECT  29.512 2.418 29.704 105.582 ;
     RECT  29.704 92.256 29.729 92.28 ;
     RECT  29.704 39.312 29.843 42.216 ;
     RECT  29.704 31.92 29.873 31.944 ;
     RECT  29.797 0.528 29.891 0.552 ;
     RECT  29.704 43.824 29.891 86.808 ;
     RECT  29.704 22.224 29.909 22.248 ;
     RECT  29.704 90.576 30.017 90.6 ;
     RECT  29.891 44.592 30.035 86.808 ;
     RECT  29.704 38.16 30.089 38.184 ;
     RECT  30.035 44.592 30.161 63.912 ;
     RECT  30.161 44.592 30.269 58.392 ;
     RECT  29.704 102.768 30.269 105.48 ;
     RECT  30.269 44.592 30.275 52.824 ;
     RECT  30.161 59.568 30.277 63.912 ;
     RECT  30.277 59.568 30.305 63.24 ;
     RECT  30.373 0.576 30.665 0.6 ;
     RECT  29.704 14.832 30.725 14.856 ;
     RECT  29.704 21.216 30.733 21.24 ;
     RECT  29.704 36.48 30.745 36.504 ;
     RECT  29.704 28.512 30.773 28.536 ;
     RECT  30.725 14.736 30.803 14.856 ;
     RECT  30.275 44.592 30.809 51.48 ;
     RECT  30.275 52.464 30.809 52.824 ;
     RECT  30.803 14.736 30.844 14.76 ;
     RECT  30.269 53.856 30.881 58.392 ;
     RECT  30.733 21.168 30.913 21.24 ;
     RECT  29.704 23.952 30.953 23.976 ;
     RECT  29.704 3.024 30.985 5.496 ;
     RECT  29.704 93.84 30.995 94.488 ;
     RECT  30.035 64.944 31.025 86.808 ;
     RECT  30.805 106.032 31.025 106.056 ;
     RECT  30.809 52.464 31.043 52.776 ;
     RECT  30.269 102.768 31.043 104.904 ;
     RECT  29.704 19.536 31.045 19.56 ;
     RECT  30.913 21.168 31.093 21.672 ;
     RECT  31.052 22.944 31.093 22.968 ;
     RECT  31.025 64.944 31.129 65.592 ;
     RECT  31.045 18.768 31.132 19.56 ;
     RECT  30.985 2.88 31.133 5.496 ;
     RECT  31.132 19.536 31.133 19.56 ;
     RECT  30.881 56.976 31.133 58.392 ;
     RECT  31.093 21.168 31.139 22.968 ;
     RECT  31.139 21.168 31.165 22.104 ;
     RECT  29.704 29.52 31.205 29.544 ;
     RECT  31.025 66.816 31.205 86.808 ;
     RECT  31.133 56.976 31.277 57.192 ;
     RECT  31.043 102.768 31.285 104.856 ;
     RECT  31.205 86.688 31.309 86.808 ;
     RECT  30.908 100.464 31.331 100.488 ;
     RECT  31.133 58.176 31.345 58.392 ;
     RECT  31.237 59.424 31.345 59.448 ;
     RECT  30.305 60.528 31.345 63.096 ;
     RECT  31.345 60.528 31.379 63.192 ;
     RECT  31.205 66.816 31.379 85.56 ;
     RECT  31.129 64.896 31.417 65.592 ;
     RECT  31.093 26.208 31.421 26.232 ;
     RECT  31.379 60.768 31.427 63.192 ;
     RECT  29.704 35.28 31.453 35.304 ;
     RECT  30.809 44.592 31.453 50.76 ;
     RECT  31.453 34.8 31.477 35.304 ;
     RECT  29.704 88.608 31.489 89.496 ;
     RECT  31.477 34.176 31.493 35.304 ;
     RECT  30.769 13.632 31.525 13.656 ;
     RECT  29.843 40.032 31.525 42.216 ;
     RECT  30.881 53.856 31.525 55.848 ;
     RECT  31.489 88.32 31.525 89.496 ;
     RECT  31.493 34.176 31.537 34.824 ;
     RECT  31.525 13.248 31.565 13.656 ;
     RECT  31.309 86.688 31.619 87.24 ;
     RECT  31.619 87.216 31.633 87.24 ;
     RECT  31.525 88.32 31.633 90.024 ;
     RECT  31.525 40.032 31.637 42.792 ;
     RECT  31.345 58.176 31.667 59.448 ;
     RECT  31.427 60.96 31.669 63.192 ;
     RECT  31.285 102.528 31.669 104.856 ;
     RECT  31.633 87.216 31.709 90.024 ;
     RECT  31.669 102.048 31.753 104.856 ;
     RECT  31.669 60.96 31.813 63.528 ;
     RECT  31.417 64.656 31.813 65.592 ;
     RECT  31.165 20.304 31.817 22.104 ;
     RECT  31.709 87.552 31.817 90.024 ;
     RECT  31.453 44.16 31.849 50.76 ;
     RECT  31.817 88.32 31.849 90.024 ;
     RECT  31.637 40.032 31.861 42.456 ;
     RECT  31.813 60.96 31.889 65.592 ;
     RECT  31.525 53.76 31.925 55.848 ;
     RECT  31.043 52.464 31.961 52.488 ;
     RECT  31.849 88.32 31.993 90.792 ;
     RECT  31.537 34.176 32.033 34.2 ;
     RECT  31.753 102.672 32.033 104.856 ;
     RECT  31.885 17.472 32.173 17.496 ;
     RECT  31.925 53.856 32.173 55.848 ;
     RECT  31.277 56.976 32.173 57.144 ;
     RECT  31.667 58.176 32.173 58.776 ;
     RECT  31.133 3.024 32.245 5.496 ;
     RECT  32.173 58.128 32.285 58.776 ;
     RECT  31.379 79.248 32.321 85.56 ;
     RECT  32.321 79.248 32.425 85.512 ;
     RECT  32.101 26.64 32.461 26.664 ;
     RECT  31.993 88.32 32.465 91.032 ;
     RECT  31.525 106.56 32.465 106.584 ;
     RECT  31.849 44.16 32.537 51.048 ;
     RECT  31.889 60.96 32.537 64.152 ;
     RECT  31.889 65.136 32.537 65.592 ;
     RECT  31.379 66.816 32.537 78.168 ;
     RECT  32.461 25.68 32.544 26.664 ;
     RECT  32.544 25.68 32.545 25.704 ;
     RECT  31.817 20.304 32.573 21.192 ;
     RECT  32.485 24.48 32.573 24.504 ;
     RECT  32.465 88.512 32.605 91.032 ;
     RECT  30.985 92.592 32.605 92.616 ;
     RECT  30.995 93.84 32.605 93.864 ;
     RECT  31.309 27.84 32.609 27.864 ;
     RECT  32.605 92.592 32.645 93.864 ;
     RECT  32.537 44.4 32.684 51.048 ;
     RECT  31.309 29.04 32.713 29.064 ;
     RECT  32.245 3.024 32.725 5.592 ;
     RECT  32.713 29.04 32.753 29.688 ;
     RECT  31.565 13.248 32.771 13.272 ;
     RECT  32.537 62.496 32.825 64.152 ;
     RECT  32.537 65.232 32.857 65.592 ;
     RECT  32.537 66.816 32.897 71.736 ;
     RECT  32.173 53.856 32.965 57.144 ;
     RECT  32.285 58.128 32.965 58.44 ;
     RECT  32.924 37.44 33.011 37.464 ;
     RECT  31.861 39.6 33.011 42.456 ;
     RECT  32.684 44.4 33.041 51.624 ;
     RECT  32.725 3.024 33.073 6.12 ;
     RECT  32.965 53.856 33.113 58.44 ;
     RECT  32.033 102.672 33.113 104.712 ;
     RECT  32.537 60.96 33.149 60.984 ;
     RECT  33.073 2.88 33.221 6.12 ;
     RECT  32.605 88.512 33.257 91.128 ;
     RECT  33.013 107.856 33.293 107.88 ;
     RECT  32.929 31.92 33.349 31.944 ;
     RECT  33.041 44.4 33.365 50.664 ;
     RECT  33.349 31.248 33.395 31.944 ;
     RECT  32.753 29.664 33.397 29.688 ;
     RECT  33.395 31.248 33.397 31.272 ;
     RECT  33.011 40.272 33.397 42.456 ;
     RECT  33.397 29.664 33.437 31.272 ;
     RECT  32.825 62.496 33.437 63.528 ;
     RECT  33.437 29.664 33.443 30.84 ;
     RECT  32.317 19.104 33.473 19.128 ;
     RECT  33.365 50.496 33.473 50.664 ;
     RECT  33.443 29.904 33.481 30.84 ;
     RECT  33.257 90 33.509 91.128 ;
     RECT  32.965 36.384 33.545 36.408 ;
     RECT  32.897 69.552 33.545 71.736 ;
     RECT  30.901 0.096 33.653 0.12 ;
     RECT  32.425 79.152 33.653 85.512 ;
     RECT  33.509 90 33.653 91.08 ;
     RECT  33.361 52.848 33.689 52.872 ;
     RECT  33.653 79.152 33.689 80.616 ;
     RECT  33.437 62.496 33.725 63.384 ;
     RECT  33.545 69.552 33.725 70.632 ;
     RECT  33.653 90.816 33.725 91.08 ;
     RECT  33.725 62.496 33.761 62.952 ;
     RECT  32.537 72.72 33.761 78.168 ;
     RECT  33.365 44.4 33.781 48.984 ;
     RECT  33.397 40.272 33.827 42.792 ;
     RECT  32.645 92.88 33.829 93.864 ;
     RECT  32.749 11.424 33.893 11.448 ;
     RECT  33.827 42.768 34.069 42.792 ;
     RECT  33.781 43.92 34.069 48.984 ;
     RECT  33.113 53.856 34.081 58.2 ;
     RECT  33.257 88.512 34.081 88.536 ;
     RECT  33.473 50.592 34.261 50.664 ;
     RECT  33.545 71.712 34.333 71.736 ;
     RECT  33.761 72.72 34.333 77.688 ;
     RECT  33.217 24.912 34.357 25.128 ;
     RECT  33.761 62.496 34.357 62.52 ;
     RECT  34.261 50.592 34.405 50.856 ;
     RECT  34.261 52.464 34.405 52.488 ;
     RECT  34.045 59.856 34.441 60.408 ;
     RECT  33.733 106.032 34.453 106.056 ;
     RECT  33.481 29.904 34.477 29.928 ;
     RECT  34.453 106.032 34.625 106.584 ;
     RECT  32.573 20.304 34.765 20.328 ;
     RECT  34.069 42.768 34.765 48.984 ;
     RECT  33.653 81.696 34.765 85.512 ;
     RECT  34.081 88.464 34.765 88.536 ;
     RECT  34.729 13.296 34.801 13.32 ;
     RECT  34.765 81.6 34.801 85.512 ;
     RECT  34.009 0.528 34.805 0.552 ;
     RECT  33.221 3.024 34.808 6.12 ;
     RECT  33.893 10.8 34.808 11.448 ;
     RECT  34.801 13.056 34.808 13.32 ;
     RECT  34.261 15.312 34.808 15.336 ;
     RECT  32.173 16.56 34.808 17.496 ;
     RECT  34.765 20.304 34.808 21.144 ;
     RECT  34.357 23.856 34.808 23.88 ;
     RECT  34.357 24.912 34.808 25.32 ;
     RECT  34.477 28.992 34.808 29.928 ;
     RECT  34.261 33.936 34.808 33.96 ;
     RECT  33.827 40.272 34.808 41.64 ;
     RECT  34.765 42.768 34.808 49.08 ;
     RECT  34.405 50.592 34.808 52.488 ;
     RECT  34.081 53.616 34.808 58.2 ;
     RECT  34.441 59.28 34.808 60.408 ;
     RECT  34.357 61.872 34.808 62.52 ;
     RECT  34.693 63.504 34.808 63.528 ;
     RECT  32.857 65.232 34.808 65.64 ;
     RECT  32.897 66.816 34.808 68.232 ;
     RECT  33.725 69.552 34.808 69.576 ;
     RECT  33.725 70.608 34.808 70.632 ;
     RECT  34.333 71.712 34.808 77.688 ;
     RECT  33.689 79.296 34.808 80.616 ;
     RECT  34.801 81.6 34.808 85.704 ;
     RECT  33.505 87.168 34.808 87.192 ;
     RECT  34.765 88.464 34.808 88.776 ;
     RECT  33.725 90.816 34.808 91.032 ;
     RECT  33.829 92.688 34.808 93.864 ;
     RECT  33.109 97.632 34.808 97.656 ;
     RECT  33.113 102.672 34.808 104.664 ;
     RECT  34.808 2.148 34.912 105.852 ;
     RECT  34.912 2.418 35.104 105.582 ;
     RECT  35.104 40.272 35.201 40.392 ;
     RECT  35.104 60.96 35.219 69.96 ;
     RECT  35.104 91.872 35.219 92.712 ;
     RECT  35.104 11.424 35.273 11.976 ;
     RECT  35.219 92.688 35.273 92.712 ;
     RECT  35.273 11.952 35.363 11.976 ;
     RECT  35.104 13.056 35.363 13.8 ;
     RECT  35.104 32.736 35.363 32.76 ;
     RECT  35.104 71.712 35.363 78.12 ;
     RECT  35.104 88.512 35.417 90.84 ;
     RECT  35.221 107.856 35.453 107.88 ;
     RECT  35.104 15.312 35.489 15.336 ;
     RECT  35.104 43.296 35.525 59.448 ;
     RECT  35.363 71.76 35.597 78.12 ;
     RECT  35.363 13.248 35.603 13.8 ;
     RECT  35.104 33.936 35.603 33.96 ;
     RECT  35.597 71.76 35.669 77.976 ;
     RECT  35.104 3.024 35.699 6.264 ;
     RECT  35.104 27.216 35.747 29.016 ;
     RECT  35.699 3.024 35.777 5.064 ;
     RECT  35.603 13.248 35.777 13.704 ;
     RECT  35.669 71.76 35.813 77.496 ;
     RECT  35.417 88.512 35.813 88.536 ;
     RECT  35.104 18.576 35.843 18.6 ;
     RECT  35.219 60.96 35.885 65.544 ;
     RECT  35.777 3.024 35.921 5.016 ;
     RECT  35.104 19.92 35.939 21.144 ;
     RECT  35.939 19.92 35.98 20.472 ;
     RECT  35.941 106.56 36.137 106.584 ;
     RECT  35.417 89.664 36.172 90.84 ;
     RECT  35.525 43.536 36.173 59.448 ;
     RECT  35.885 61.296 36.209 65.544 ;
     RECT  35.219 66.816 36.241 69.96 ;
     RECT  36.172 90.048 36.313 90.84 ;
     RECT  35.104 31.344 36.321 31.368 ;
     RECT  36.241 66.816 36.325 70.008 ;
     RECT  36.209 62.736 36.349 65.544 ;
     RECT  36.321 30.528 36.371 31.368 ;
     RECT  35.813 71.808 36.389 77.496 ;
     RECT  35.747 28.08 36.421 29.016 ;
     RECT  36.421 28.08 36.467 29.496 ;
     RECT  36.371 30.528 36.467 30.552 ;
     RECT  35.104 8.88 36.469 9.672 ;
     RECT  36.457 10.848 36.469 10.872 ;
     RECT  35.104 79.248 36.493 86.04 ;
     RECT  36.469 8.88 36.515 10.872 ;
     RECT  36.515 10.224 36.541 10.872 ;
     RECT  36.349 62.736 36.601 65.592 ;
     RECT  36.325 66.816 36.601 70.056 ;
     RECT  36.541 10.224 36.677 10.248 ;
     RECT  36.601 106.032 36.707 106.056 ;
     RECT  36.389 76.368 36.805 77.496 ;
     RECT  35.921 3.024 36.853 4.968 ;
     RECT  35.104 22.176 36.889 22.2 ;
     RECT  36.805 76.368 36.892 78.072 ;
     RECT  36.889 22.176 36.995 22.776 ;
     RECT  35.98 19.92 36.997 19.944 ;
     RECT  35.699 6.048 37.001 6.264 ;
     RECT  36.467 29.472 37.001 29.496 ;
     RECT  36.601 62.736 37.001 70.056 ;
     RECT  36.173 43.536 37.037 43.56 ;
     RECT  36.997 19.248 37.043 19.944 ;
     RECT  36.173 45.216 37.091 59.448 ;
     RECT  37.043 19.248 37.104 19.656 ;
     RECT  36.389 71.808 37.177 75.192 ;
     RECT  36.209 61.296 37.213 61.32 ;
     RECT  37.001 62.736 37.213 69 ;
     RECT  35.104 24.096 37.253 24.936 ;
     RECT  36.853 2.976 37.289 4.968 ;
     RECT  37.177 71.76 37.289 75.192 ;
     RECT  37.091 45.648 37.357 59.448 ;
     RECT  36.493 79.152 37.381 86.04 ;
     RECT  35.104 17.472 37.465 17.496 ;
     RECT  37.381 79.152 37.468 86.376 ;
     RECT  37.357 45.648 37.484 59.64 ;
     RECT  37.465 17.472 37.505 17.688 ;
     RECT  35.777 13.68 37.525 13.704 ;
     RECT  37.525 12.912 37.571 13.704 ;
     RECT  37.484 45.648 37.571 60.024 ;
     RECT  37.289 71.808 37.573 75.192 ;
     RECT  36.892 76.368 37.573 77.304 ;
     RECT  37.571 12.912 37.612 12.936 ;
     RECT  36.995 22.176 37.685 22.2 ;
     RECT  36.313 90.048 37.721 90.888 ;
     RECT  36.515 8.88 37.789 8.904 ;
     RECT  37.573 71.808 37.861 77.304 ;
     RECT  37.213 61.296 37.897 69 ;
     RECT  37.897 61.008 38.009 69 ;
     RECT  37.505 17.664 38.081 17.688 ;
     RECT  37.721 90.048 38.117 90.456 ;
     RECT  37.789 8.304 38.149 8.904 ;
     RECT  37.104 19.632 38.149 19.656 ;
     RECT  38.009 61.344 38.197 69 ;
     RECT  37.001 70.032 38.197 70.056 ;
     RECT  38.117 90.048 38.197 90.072 ;
     RECT  38.149 18.768 38.233 20.04 ;
     RECT  38.197 89.472 38.243 90.072 ;
     RECT  35.104 102.672 38.257 104.712 ;
     RECT  37.861 71.808 38.293 78.072 ;
     RECT  37.468 79.152 38.293 86.088 ;
     RECT  38.233 20.016 38.297 20.04 ;
     RECT  37.289 3.408 38.365 4.968 ;
     RECT  37.141 15.168 38.365 15.192 ;
     RECT  35.104 87.36 38.365 87.384 ;
     RECT  38.197 61.344 38.369 70.056 ;
     RECT  38.369 69.552 38.389 70.056 ;
     RECT  38.365 15.168 38.405 15.336 ;
     RECT  38.365 87.36 38.429 87.576 ;
     RECT  37.001 6.048 38.441 6.072 ;
     RECT  38.429 87.216 38.444 87.576 ;
     RECT  38.293 71.808 38.483 86.088 ;
     RECT  38.444 87.216 38.531 87.72 ;
     RECT  38.257 102.672 38.549 104.856 ;
     RECT  37.571 45.648 38.617 59.784 ;
     RECT  38.365 3.408 38.653 5.064 ;
     RECT  38.617 44.784 38.657 59.784 ;
     RECT  36.467 28.08 38.675 28.104 ;
     RECT  38.483 85.488 38.689 86.088 ;
     RECT  38.531 87.216 38.689 87.576 ;
     RECT  38.657 44.784 38.693 55.992 ;
     RECT  38.483 71.808 38.693 84.216 ;
     RECT  37.253 24.336 38.725 24.936 ;
     RECT  38.389 69.552 38.725 70.104 ;
     RECT  38.693 71.808 38.725 83.448 ;
     RECT  38.629 10.848 38.729 10.968 ;
     RECT  38.149 8.304 38.761 9 ;
     RECT  38.693 44.784 38.765 47.832 ;
     RECT  38.629 26.736 38.771 26.76 ;
     RECT  35.104 36.72 38.773 36.744 ;
     RECT  38.729 10.848 38.801 10.872 ;
     RECT  38.369 61.344 38.801 68.568 ;
     RECT  38.773 36.72 38.819 36.936 ;
     RECT  38.653 3.408 38.837 5.736 ;
     RECT  38.801 66 38.837 68.568 ;
     RECT  38.725 69.552 38.873 83.448 ;
     RECT  38.243 89.472 38.905 89.496 ;
     RECT  38.905 89.424 38.906 89.496 ;
     RECT  38.828 106.032 38.915 106.056 ;
     RECT  38.693 48.816 39.017 55.992 ;
     RECT  38.657 57.552 39.017 59.784 ;
     RECT  38.801 61.344 39.109 65.016 ;
     RECT  38.689 85.488 39.125 87.576 ;
     RECT  39.109 60.96 39.155 65.016 ;
     RECT  39.155 62.16 39.161 65.016 ;
     RECT  38.873 69.552 39.161 83.352 ;
     RECT  39.155 60.96 39.164 61.128 ;
     RECT  38.765 44.784 39.203 47.688 ;
     RECT  39.017 57.552 39.205 59.544 ;
     RECT  39.161 62.16 39.233 64.968 ;
     RECT  39.203 45.12 39.244 47.688 ;
     RECT  39.161 69.552 39.337 82.968 ;
     RECT  38.837 3.504 39.553 5.736 ;
     RECT  38.761 7.824 39.644 9 ;
     RECT  39.644 7.344 39.685 9 ;
     RECT  39.244 45.648 39.733 47.688 ;
     RECT  39.017 48.816 39.733 55.512 ;
     RECT  39.125 85.488 39.841 85.8 ;
     RECT  35.201 40.272 39.913 40.296 ;
     RECT  39.337 14.208 40.021 14.232 ;
     RECT  38.233 18.768 40.049 18.792 ;
     RECT  39.157 20.112 40.049 20.136 ;
     RECT  38.906 89.424 40.057 89.448 ;
     RECT  39.733 10.176 40.069 10.2 ;
     RECT  39.553 3.504 40.208 5.784 ;
     RECT  39.685 6.816 40.208 9 ;
     RECT  40.069 10.176 40.208 10.344 ;
     RECT  40.021 12.48 40.208 12.504 ;
     RECT  40.021 13.584 40.208 14.232 ;
     RECT  38.405 15.312 40.208 15.336 ;
     RECT  39.841 17.472 40.208 17.496 ;
     RECT  40.049 18.768 40.208 20.136 ;
     RECT  38.725 24.336 40.208 25.512 ;
     RECT  38.819 36.912 40.208 36.936 ;
     RECT  39.205 38.64 40.208 38.664 ;
     RECT  39.913 40.272 40.208 40.44 ;
     RECT  39.733 45.648 40.208 55.512 ;
     RECT  39.205 57.696 40.208 59.544 ;
     RECT  39.164 60.768 40.208 61.128 ;
     RECT  39.233 62.16 40.208 63.912 ;
     RECT  39.233 64.944 40.208 64.968 ;
     RECT  38.837 66 40.208 68.184 ;
     RECT  39.337 69.456 40.208 82.968 ;
     RECT  39.841 84.528 40.208 85.8 ;
     RECT  39.125 87.216 40.208 87.576 ;
     RECT  40.057 89.184 40.208 89.448 ;
     RECT  35.104 93.84 40.208 93.864 ;
     RECT  35.104 97.776 40.208 97.8 ;
     RECT  38.549 102.96 40.208 104.856 ;
     RECT  40.208 2.148 40.312 105.852 ;
     RECT  40.312 2.418 40.504 105.852 ;
     RECT  40.504 16.416 40.529 17.496 ;
     RECT  40.504 67.68 40.529 70.248 ;
     RECT  40.504 13.584 40.565 14.232 ;
     RECT  37.429 107.856 40.565 107.88 ;
     RECT  40.504 3.6 40.601 5.784 ;
     RECT  40.504 36.912 40.601 37.032 ;
     RECT  40.504 59.04 40.601 59.544 ;
     RECT  40.529 16.416 40.643 17.304 ;
     RECT  40.643 16.416 40.681 16.44 ;
     RECT  40.504 64.944 40.691 66.264 ;
     RECT  40.504 50.544 40.709 50.76 ;
     RECT  40.691 65.52 40.732 66.024 ;
     RECT  40.504 81.408 40.817 82.968 ;
     RECT  40.504 103.296 40.889 105.852 ;
     RECT  40.601 59.04 40.925 59.064 ;
     RECT  40.504 72 40.961 79.992 ;
     RECT  40.601 3.6 40.997 5.736 ;
     RECT  40.529 67.68 41.069 67.704 ;
     RECT  40.817 81.504 41.069 82.968 ;
     RECT  40.529 68.688 41.075 70.248 ;
     RECT  40.504 47.664 41.219 48.456 ;
     RECT  40.504 52.224 41.249 54.12 ;
     RECT  41.249 52.992 41.411 54.12 ;
     RECT  40.709 50.736 41.429 50.76 ;
     RECT  40.504 89.184 41.465 89.448 ;
     RECT  41.219 47.664 41.496 47.736 ;
     RECT  41.075 68.688 41.537 69.528 ;
     RECT  40.504 46.272 41.557 46.296 ;
     RECT  41.557 45.6 41.603 46.296 ;
     RECT  41.496 47.28 41.603 47.736 ;
     RECT  40.961 72 41.609 75.096 ;
     RECT  41.609 72 41.645 74.712 ;
     RECT  41.564 14.784 41.651 14.808 ;
     RECT  40.565 13.584 41.673 13.608 ;
     RECT  41.537 68.688 41.681 68.712 ;
     RECT  41.069 81.504 41.717 81.672 ;
     RECT  40.504 20.112 41.785 20.136 ;
     RECT  41.645 72 41.789 73.752 ;
     RECT  40.997 3.6 41.821 4.968 ;
     RECT  41.785 20.016 41.825 20.136 ;
     RECT  40.504 7.92 41.893 7.944 ;
     RECT  41.789 72.96 41.897 73.752 ;
     RECT  41.821 67.776 41.905 67.8 ;
     RECT  41.069 82.944 41.929 82.968 ;
     RECT  41.603 47.28 41.933 47.304 ;
     RECT  41.852 6.816 41.939 6.84 ;
     RECT  41.077 106.032 42.041 106.056 ;
     RECT  40.504 56.064 42.073 57.048 ;
     RECT  40.961 76.368 42.077 79.992 ;
     RECT  41.929 82.944 42.109 83.784 ;
     RECT  42.073 56.064 42.113 57.624 ;
     RECT  42.077 76.944 42.113 79.992 ;
     RECT  40.504 10.176 42.133 10.344 ;
     RECT  41.821 3.408 42.145 4.968 ;
     RECT  41.603 45.6 42.221 45.624 ;
     RECT  40.504 87.36 42.408 87.384 ;
     RECT  42.113 77.904 42.419 79.992 ;
     RECT  42.419 77.904 42.445 79.224 ;
     RECT  41.569 22.8 42.469 22.824 ;
     RECT  40.889 103.296 42.469 104.952 ;
     RECT  42.133 10.176 42.505 10.872 ;
     RECT  40.504 11.904 42.505 11.928 ;
     RECT  42.469 22.176 42.515 22.824 ;
     RECT  42.109 82.656 42.515 83.784 ;
     RECT  42.469 103.2 42.553 104.952 ;
     RECT  42.515 22.176 42.556 22.2 ;
     RECT  35.153 0.096 42.617 0.12 ;
     RECT  41.717 81.504 42.653 81.528 ;
     RECT  42.145 3.264 42.785 4.968 ;
     RECT  42.785 3.264 42.793 5.736 ;
     RECT  41.749 13.056 42.833 13.08 ;
     RECT  42.445 79.2 42.833 79.224 ;
     RECT  42.793 2.832 42.869 5.736 ;
     RECT  42.181 43.92 42.869 43.944 ;
     RECT  41.893 7.92 42.901 7.992 ;
     RECT  40.504 8.976 42.901 9 ;
     RECT  42.869 2.832 42.905 5.112 ;
     RECT  42.901 7.92 42.941 9 ;
     RECT  42.505 10.176 42.947 11.928 ;
     RECT  43.052 0.528 43.139 0.552 ;
     RECT  42.113 57.6 43.265 57.624 ;
     RECT  40.601 37.008 43.333 37.032 ;
     RECT  41.825 20.016 43.373 20.04 ;
     RECT  43.436 7.392 43.523 7.416 ;
     RECT  42.445 77.904 43.573 77.928 ;
     RECT  43.573 77.52 43.619 77.928 ;
     RECT  42.325 15.168 43.621 15.192 ;
     RECT  43.58 13.488 43.667 13.512 ;
     RECT  43.621 15.168 43.667 15.288 ;
     RECT  42.941 8.496 43.765 9 ;
     RECT  42.947 10.176 43.765 11.16 ;
     RECT  43.765 8.496 43.769 11.16 ;
     RECT  40.732 66 43.801 66.024 ;
     RECT  43.769 8.88 43.811 11.16 ;
     RECT  43.724 19.968 43.811 19.992 ;
     RECT  43.619 77.52 43.859 77.544 ;
     RECT  42.757 42.384 43.873 42.408 ;
     RECT  43.801 66 43.885 66.12 ;
     RECT  42.905 3.408 44.149 5.112 ;
     RECT  43.811 8.928 44.195 11.16 ;
     RECT  42.565 106.56 44.237 106.584 ;
     RECT  42.408 87.36 44.3 87.72 ;
     RECT  44.3 87.36 44.341 88.2 ;
     RECT  44.341 87.168 44.387 88.2 ;
     RECT  44.149 3.408 44.449 5.496 ;
     RECT  43.873 42.192 44.725 42.408 ;
     RECT  43.613 0.096 44.785 0.12 ;
     RECT  40.504 40.416 44.917 40.44 ;
     RECT  44.725 41.424 44.917 42.408 ;
     RECT  41.465 89.424 44.953 89.448 ;
     RECT  41.411 53.856 45.061 53.88 ;
     RECT  44.449 3.408 45.241 5.832 ;
     RECT  45.212 0.528 45.299 0.552 ;
     RECT  45.205 30.576 45.452 30.6 ;
     RECT  45.241 2.976 45.608 5.832 ;
     RECT  44.195 9.696 45.608 11.16 ;
     RECT  43.667 15.264 45.608 15.288 ;
     RECT  45.601 17.616 45.608 17.64 ;
     RECT  43.765 18.768 45.608 18.792 ;
     RECT  40.504 24.768 45.608 24.792 ;
     RECT  45.452 30.576 45.608 30.792 ;
     RECT  43.333 36.864 45.608 37.032 ;
     RECT  44.917 40.416 45.608 42.408 ;
     RECT  45.061 53.856 45.608 54.744 ;
     RECT  42.113 56.064 45.608 56.088 ;
     RECT  43.885 66 45.608 66.024 ;
     RECT  44.387 87.168 45.608 87.384 ;
     RECT  44.953 89.232 45.608 89.448 ;
     RECT  40.504 93.84 45.608 93.864 ;
     RECT  42.469 95.616 45.608 95.64 ;
     RECT  40.504 97.776 45.608 97.8 ;
     RECT  42.553 103.296 45.608 104.952 ;
     RECT  45.608 2.148 45.712 105.852 ;
     RECT  44.773 107.856 45.785 107.88 ;
     RECT  45.712 2.418 45.904 105.582 ;
     RECT  45.904 16.464 46.595 16.488 ;
     RECT  45.904 17.616 46.595 17.64 ;
     RECT  45.904 87.36 46.793 89.256 ;
     RECT  45.904 8.016 46.931 8.04 ;
     RECT  46.249 106.56 47.053 106.584 ;
     RECT  45.904 103.296 47.117 104.712 ;
     RECT  47.117 103.536 47.401 104.712 ;
     RECT  45.904 15.264 47.437 15.288 ;
     RECT  46.793 87.36 47.437 89.16 ;
     RECT  45.904 40.08 47.441 41.448 ;
     RECT  47.437 15.168 47.477 15.288 ;
     RECT  47.401 103.536 47.549 105 ;
     RECT  45.904 53.856 47.617 54.12 ;
     RECT  45.904 55.248 47.617 55.272 ;
     RECT  47.617 53.856 47.725 55.272 ;
     RECT  46.885 6.816 47.729 6.84 ;
     RECT  47.725 53.856 47.795 55.896 ;
     RECT  45.904 3.312 47.801 5.832 ;
     RECT  47.795 55.872 47.809 55.896 ;
     RECT  47.701 107.856 47.945 107.88 ;
     RECT  47.437 87.168 48.089 89.16 ;
     RECT  47.477 15.168 48.332 15.192 ;
     RECT  48.332 14.592 48.419 15.192 ;
     RECT  48.089 88.896 48.469 89.16 ;
     RECT  48.469 88.896 48.515 89.544 ;
     RECT  48.515 88.944 48.589 89.544 ;
     RECT  47.221 90.912 48.589 90.936 ;
     RECT  48.589 88.944 48.629 90.936 ;
     RECT  47.801 5.808 48.665 5.832 ;
     RECT  48.469 106.56 48.665 106.584 ;
     RECT  45.904 95.616 48.709 95.64 ;
     RECT  47.801 3.312 48.737 4.728 ;
     RECT  48.629 90.384 48.755 90.936 ;
     RECT  48.755 90.384 48.989 90.408 ;
     RECT  48.709 95.616 49.133 95.736 ;
     RECT  47.795 53.856 49.157 54.36 ;
     RECT  49.157 53.856 49.241 54.744 ;
     RECT  48.629 88.944 49.349 89.16 ;
     RECT  49.189 107.856 49.385 107.88 ;
     RECT  45.904 10.32 49.457 11.16 ;
     RECT  49.388 95.808 49.475 95.832 ;
     RECT  49.877 106.56 49.961 106.584 ;
     RECT  49.457 10.704 50.101 11.16 ;
     RECT  47.441 40.08 50.137 40.296 ;
     RECT  48.737 3.408 50.749 4.728 ;
     RECT  50.749 3.12 50.893 4.728 ;
     RECT  50.677 107.856 50.897 107.88 ;
     RECT  50.893 3.12 50.929 5.064 ;
     RECT  45.781 0.096 50.965 0.12 ;
     RECT  50.137 39.648 50.965 40.296 ;
     RECT  50.929 2.88 51.008 5.064 ;
     RECT  50.101 10.704 51.008 11.688 ;
     RECT  48.373 13.296 51.008 13.32 ;
     RECT  45.904 30.576 51.008 30.6 ;
     RECT  50.965 39.6 51.008 40.296 ;
     RECT  47.441 41.424 51.008 41.448 ;
     RECT  48.733 52.416 51.008 52.44 ;
     RECT  49.241 53.856 51.008 54.36 ;
     RECT  48.089 87.36 51.008 87.384 ;
     RECT  49.349 89.136 51.008 89.16 ;
     RECT  45.904 93.84 51.008 93.864 ;
     RECT  45.904 97.776 51.008 97.8 ;
     RECT  47.549 103.728 51.008 105 ;
     RECT  50.965 0.096 51.107 0.552 ;
     RECT  51.008 2.148 51.112 105.852 ;
     RECT  51.112 2.418 51.304 105.582 ;
     RECT  51.304 2.832 51.797 5.064 ;
     RECT  51.304 10.272 51.923 11.16 ;
     RECT  51.304 103.728 52.121 104.856 ;
     RECT  52.121 103.728 52.229 104.808 ;
     RECT  51.397 106.56 52.445 106.584 ;
     RECT  51.304 9.216 52.451 9.24 ;
     RECT  51.304 39.6 52.451 41.448 ;
     RECT  51.304 51.264 52.621 51.288 ;
     RECT  52.621 50.976 52.661 51.288 ;
     RECT  51.797 2.88 52.691 5.064 ;
     RECT  52.405 8.16 52.805 8.184 ;
     RECT  52.451 39.6 52.805 40.104 ;
     RECT  52.885 107.856 53.093 107.88 ;
     RECT  51.304 53.856 53.237 54.12 ;
     RECT  52.661 50.976 53.557 51 ;
     RECT  53.237 54.096 53.561 54.12 ;
     RECT  53.557 50.112 53.603 51 ;
     RECT  53.603 50.112 53.629 50.136 ;
     RECT  53.629 49.968 53.669 50.136 ;
     RECT  53.612 13.632 53.699 13.656 ;
     RECT  52.805 40.08 53.773 40.104 ;
     RECT  52.229 103.728 53.989 104.664 ;
     RECT  51.923 11.136 54.035 11.16 ;
     RECT  53.989 13.104 54.073 13.128 ;
     RECT  53.557 52.464 54.101 52.488 ;
     RECT  53.653 35.568 54.131 35.592 ;
     RECT  52.729 46.512 54.277 46.536 ;
     RECT  53.773 39.12 54.323 40.104 ;
     RECT  52.451 41.424 54.323 41.448 ;
     RECT  54.277 46.512 54.361 46.728 ;
     RECT  53.665 6.288 54.371 6.312 ;
     RECT  54.323 39.6 54.421 40.104 ;
     RECT  51.304 30.576 54.467 30.6 ;
     RECT  54.38 35.616 54.467 35.64 ;
     RECT  53.605 106.56 54.497 106.584 ;
     RECT  51.304 89.136 54.709 89.16 ;
     RECT  54.421 39.6 54.713 40.584 ;
     RECT  54.709 89.136 54.749 89.256 ;
     RECT  51.107 0.096 54.757 0.12 ;
     RECT  54.757 0.096 54.893 0.552 ;
     RECT  53.669 49.968 54.929 49.992 ;
     RECT  52.691 2.88 55.357 4.536 ;
     RECT  55.093 107.856 55.397 107.88 ;
     RECT  55.357 2.88 55.433 4.68 ;
     RECT  53.989 103.728 55.433 104.712 ;
     RECT  54.277 48.96 55.933 48.984 ;
     RECT  54.893 0.096 56.341 0.12 ;
     RECT  55.433 3.12 56.408 4.68 ;
     RECT  53.989 9.792 56.408 9.816 ;
     RECT  54.713 40.56 56.408 40.584 ;
     RECT  54.361 46.512 56.408 46.536 ;
     RECT  55.933 48.96 56.408 49.032 ;
     RECT  55.933 52.464 56.408 52.488 ;
     RECT  51.304 87.36 56.408 87.384 ;
     RECT  54.749 89.232 56.408 89.256 ;
     RECT  51.304 93.84 56.408 93.864 ;
     RECT  51.304 97.776 56.408 97.8 ;
     RECT  55.433 103.728 56.408 104.664 ;
     RECT  55.609 106.032 56.408 106.056 ;
     RECT  56.408 2.148 56.512 106.056 ;
     RECT  56.512 2.418 56.62 106.056 ;
     RECT  56.62 2.418 56.704 105.582 ;
     RECT  56.341 0.096 56.801 0.552 ;
     RECT  56.704 87.36 56.909 87.768 ;
     RECT  56.704 48.864 57.377 49.032 ;
     RECT  56.704 89.232 57.587 89.256 ;
     RECT  56.909 87.744 57.601 87.768 ;
     RECT  57.377 48.864 58.163 48.888 ;
     RECT  57.301 107.856 58.241 107.88 ;
     RECT  56.704 52.464 58.625 52.488 ;
     RECT  58.625 51.792 58.645 52.488 ;
     RECT  58.645 51.072 58.691 52.488 ;
     RECT  58.691 51.072 58.709 51.816 ;
     RECT  56.704 103.728 58.745 104.856 ;
     RECT  58.745 103.728 58.817 104.808 ;
     RECT  58.817 103.728 59.573 104.712 ;
     RECT  58.741 106.56 59.681 106.584 ;
     RECT  56.704 46.512 59.989 46.536 ;
     RECT  58.117 47.616 59.989 47.64 ;
     RECT  59.989 46.368 60.035 47.64 ;
     RECT  58.709 51.072 60.037 51.096 ;
     RECT  60.035 46.368 60.076 46.872 ;
     RECT  60.037 50.4 60.077 51.096 ;
     RECT  60.077 50.4 60.121 50.76 ;
     RECT  59.573 103.776 60.289 104.712 ;
     RECT  60.229 107.136 60.437 107.16 ;
     RECT  60.289 103.776 60.617 105 ;
     RECT  56.801 0.096 60.761 0.12 ;
     RECT  60.949 107.856 61.301 107.88 ;
     RECT  60.121 50.4 61.405 50.424 ;
     RECT  56.704 3.12 61.765 4.68 ;
     RECT  61.765 3.024 61.808 4.68 ;
     RECT  56.704 9.792 61.808 9.816 ;
     RECT  56.704 40.56 61.808 40.584 ;
     RECT  60.076 46.368 61.808 46.536 ;
     RECT  61.405 50.304 61.808 50.424 ;
     RECT  56.704 90.24 61.808 90.264 ;
     RECT  56.704 93.84 61.808 93.864 ;
     RECT  56.704 97.776 61.808 97.8 ;
     RECT  60.617 103.776 61.808 104.664 ;
     RECT  61.717 106.032 61.808 106.056 ;
     RECT  61.808 2.148 61.912 106.056 ;
     RECT  61.081 0.528 61.985 0.552 ;
     RECT  61.912 2.418 61.985 106.056 ;
     RECT  61.985 2.418 62.104 105.582 ;
     RECT  62.104 40.56 62.309 41.016 ;
     RECT  62.309 40.992 62.339 41.016 ;
     RECT  62.104 46.512 62.339 46.728 ;
     RECT  62.339 46.704 62.435 46.728 ;
     RECT  62.104 103.776 62.705 104.904 ;
     RECT  62.104 3.504 62.813 4.824 ;
     RECT  62.104 49.536 62.957 50.328 ;
     RECT  62.813 3.552 62.993 4.824 ;
     RECT  62.104 9.792 63.349 9.816 ;
     RECT  63.349 9.792 63.389 9.912 ;
     RECT  63.389 9.888 63.433 9.912 ;
     RECT  62.993 3.696 63.827 4.824 ;
     RECT  63.827 3.696 63.929 4.488 ;
     RECT  62.437 107.856 64.073 107.88 ;
     RECT  62.104 48.384 64.717 48.408 ;
     RECT  62.957 49.536 64.717 49.56 ;
     RECT  64.645 106.56 64.729 106.584 ;
     RECT  64.717 48.384 64.757 49.56 ;
     RECT  65.545 2.832 65.657 2.856 ;
     RECT  62.104 44.928 65.725 44.952 ;
     RECT  65.725 44.736 65.765 44.952 ;
     RECT  63.929 3.84 66.733 4.488 ;
     RECT  65.324 106.032 66.853 106.056 ;
     RECT  65.765 44.736 67.093 44.76 ;
     RECT  64.757 48.384 67.093 49.032 ;
     RECT  66.733 3.696 67.208 4.488 ;
     RECT  67.093 44.352 67.208 44.76 ;
     RECT  67.093 48.24 67.208 49.032 ;
     RECT  62.104 90.24 67.208 90.264 ;
     RECT  62.104 93.84 67.208 93.864 ;
     RECT  62.104 97.776 67.208 97.8 ;
     RECT  62.705 103.872 67.208 104.904 ;
     RECT  66.853 106.032 67.208 106.584 ;
     RECT  67.208 2.148 67.312 106.584 ;
     RECT  67.312 2.418 67.504 105.582 ;
     RECT  67.504 3.696 67.709 4.488 ;
     RECT  67.504 90.24 67.709 90.6 ;
     RECT  67.312 106.56 67.781 106.584 ;
     RECT  67.709 3.84 67.889 4.488 ;
     RECT  67.504 103.68 68.069 104.904 ;
     RECT  67.709 90.576 68.077 90.6 ;
     RECT  68.341 107.856 68.537 107.88 ;
     RECT  69.061 106.032 69.545 106.056 ;
     RECT  68.569 43.248 69.865 43.272 ;
     RECT  69.865 43.248 69.866 43.32 ;
     RECT  69.781 106.56 69.941 106.584 ;
     RECT  67.889 3.84 70.513 4.2 ;
     RECT  70.513 3.84 70.553 4.392 ;
     RECT  68.069 103.68 70.645 104.664 ;
     RECT  70.645 103.536 70.691 104.664 ;
     RECT  70.549 107.856 70.769 107.88 ;
     RECT  69.866 43.296 71.363 43.32 ;
     RECT  70.553 3.984 71.417 4.392 ;
     RECT  71.417 3.984 71.917 4.2 ;
     RECT  71.269 106.56 72.209 106.584 ;
     RECT  62.161 0.096 72.325 0.12 ;
     RECT  71.917 3.408 72.449 4.2 ;
     RECT  72.449 3.408 72.608 4.776 ;
     RECT  71.317 45.504 72.608 45.528 ;
     RECT  67.504 47.856 72.608 48.408 ;
     RECT  67.504 93.84 72.608 93.864 ;
     RECT  67.504 97.776 72.608 97.8 ;
     RECT  70.691 103.488 72.608 104.664 ;
     RECT  72.608 2.148 72.712 105.852 ;
     RECT  72.745 0.528 72.851 0.552 ;
     RECT  72.712 2.418 72.904 105.582 ;
     RECT  72.904 3.408 72.929 4.776 ;
     RECT  72.929 3.984 72.965 4.776 ;
     RECT  72.757 107.856 73.685 107.88 ;
     RECT  72.965 3.984 73.969 4.2 ;
     RECT  72.904 47.856 74.221 48.408 ;
     RECT  74.221 47.04 74.261 48.408 ;
     RECT  74.197 106.56 74.369 106.584 ;
     RECT  72.904 103.488 74.653 104.664 ;
     RECT  72.904 45.504 75.116 45.528 ;
     RECT  75.116 45.312 75.203 45.528 ;
     RECT  74.261 48.384 75.203 48.408 ;
     RECT  73.969 3.408 75.341 4.2 ;
     RECT  74.261 47.04 75.781 47.064 ;
     RECT  75.445 45.552 75.827 45.576 ;
     RECT  74.965 107.856 75.881 107.88 ;
     RECT  75.781 46.848 76.025 47.064 ;
     RECT  74.653 103.488 76.277 104.808 ;
     RECT  75.341 3.888 76.417 4.2 ;
     RECT  76.405 106.032 76.673 106.056 ;
     RECT  76.277 103.488 77.317 104.568 ;
     RECT  77.173 106.56 77.393 106.584 ;
     RECT  76.417 3.408 78.008 4.2 ;
     RECT  76.025 46.848 78.008 46.872 ;
     RECT  74.917 52.272 78.008 52.296 ;
     RECT  72.904 93.84 78.008 93.864 ;
     RECT  72.904 97.776 78.008 97.8 ;
     RECT  77.317 103.488 78.008 104.664 ;
     RECT  78.008 2.148 78.112 105.852 ;
     RECT  77.893 107.856 78.185 107.88 ;
     RECT  78.112 2.418 78.304 105.582 ;
     RECT  78.304 46.752 78.401 46.872 ;
     RECT  78.304 103.488 79.729 104.664 ;
     RECT  78.661 106.56 80.309 106.584 ;
     RECT  78.304 3.408 81.133 4.2 ;
     RECT  80.869 107.856 81.245 107.88 ;
     RECT  81.493 107.184 81.635 107.208 ;
     RECT  79.729 103.488 82.211 104.856 ;
     RECT  82.211 103.728 82.225 104.856 ;
     RECT  78.401 46.752 82.253 46.776 ;
     RECT  81.133 3.168 82.361 4.2 ;
     RECT  82.309 106.032 82.541 106.056 ;
     RECT  83.077 107.856 83.261 107.88 ;
     RECT  82.361 3.408 83.408 4.2 ;
     RECT  78.304 52.416 83.408 52.44 ;
     RECT  78.304 93.84 83.408 93.864 ;
     RECT  78.304 97.776 83.408 97.8 ;
     RECT  82.165 100.224 83.408 100.248 ;
     RECT  82.225 104.016 83.408 104.856 ;
     RECT  83.408 2.148 83.512 105.852 ;
     RECT  83.512 2.418 83.704 105.582 ;
     RECT  83.704 3.312 84.764 4.344 ;
     RECT  84.764 3.312 84.805 4.392 ;
     RECT  83.704 7.44 85.043 7.464 ;
     RECT  83.704 104.064 85.057 104.664 ;
     RECT  84.997 6.432 85.084 6.456 ;
     RECT  84.805 3.312 85.34 5.16 ;
     RECT  85.34 3.312 85.381 5.448 ;
     RECT  85.057 104.016 85.484 104.664 ;
     RECT  83.797 106.56 85.493 106.584 ;
     RECT  85.381 3.312 85.565 5.736 ;
     RECT  85.484 103.728 85.571 104.664 ;
     RECT  85.565 3.312 85.601 4.296 ;
     RECT  85.601 3.408 85.709 4.296 ;
     RECT  85.565 5.712 85.997 5.736 ;
     RECT  86.005 107.856 86.213 107.88 ;
     RECT  85.571 104.016 86.393 104.664 ;
     RECT  73.321 0.096 86.581 0.12 ;
     RECT  86.393 104.064 86.717 104.664 ;
     RECT  86.581 0.096 86.825 0.552 ;
     RECT  86.725 106.56 87.581 106.584 ;
     RECT  85.709 3.408 87.685 4.2 ;
     RECT  86.717 104.112 88.369 104.664 ;
     RECT  88.213 107.856 88.409 107.88 ;
     RECT  87.685 2.832 88.808 4.2 ;
     RECT  83.704 52.416 88.808 52.44 ;
     RECT  83.704 93.84 88.808 93.864 ;
     RECT  83.704 97.776 88.808 97.8 ;
     RECT  83.704 100.224 88.808 100.248 ;
     RECT  88.369 104.016 88.808 104.664 ;
     RECT  88.808 2.148 88.912 105.852 ;
     RECT  88.912 2.418 88.933 105.852 ;
     RECT  88.933 2.418 89.02 106.056 ;
     RECT  89.02 2.418 89.104 105.582 ;
     RECT  89.693 106.56 89.777 106.584 ;
     RECT  89.104 3.984 90.313 4.2 ;
     RECT  89.104 97.776 90.637 97.8 ;
     RECT  90.637 97.776 90.677 97.896 ;
     RECT  90.313 3.648 90.901 4.2 ;
     RECT  89.104 104.016 90.908 104.664 ;
     RECT  89.104 100.224 90.949 100.248 ;
     RECT  90.908 103.728 90.995 104.664 ;
     RECT  90.421 107.856 91.505 107.88 ;
     RECT  90.995 104.304 91.577 104.664 ;
     RECT  90.901 3.408 92.621 4.2 ;
     RECT  91.909 106.56 92.701 106.584 ;
     RECT  91.577 104.64 92.869 104.664 ;
     RECT  93.349 107.856 93.629 107.88 ;
     RECT  92.621 3.696 93.769 4.2 ;
     RECT  90.677 97.872 93.913 97.896 ;
     RECT  94.085 106.56 94.169 106.584 ;
     RECT  93.769 3.696 94.208 4.776 ;
     RECT  89.104 52.416 94.208 52.44 ;
     RECT  89.104 93.84 94.208 93.864 ;
     RECT  93.913 97.104 94.208 97.896 ;
     RECT  90.949 100.224 94.208 100.68 ;
     RECT  92.869 104.544 94.208 104.664 ;
     RECT  94.208 2.148 94.312 105.852 ;
     RECT  94.312 2.418 94.504 105.582 ;
     RECT  94.504 100.224 94.787 100.344 ;
     RECT  94.837 107.856 95.213 107.88 ;
     RECT  94.504 97.104 95.465 98.616 ;
     RECT  95.465 97.872 95.645 98.616 ;
     RECT  95.645 98.592 95.749 98.616 ;
     RECT  94.504 3.888 96.001 4.92 ;
     RECT  95.749 98.592 96.361 98.664 ;
     RECT  95.557 106.56 96.509 106.584 ;
     RECT  96.289 96.72 96.901 96.744 ;
     RECT  96.901 96.72 96.947 96.984 ;
     RECT  94.504 104.016 97.009 104.664 ;
     RECT  96.947 96.96 97.049 96.984 ;
     RECT  95.677 95.184 97.141 95.208 ;
     RECT  94.787 100.224 97.187 100.248 ;
     RECT  86.825 0.096 97.189 0.12 ;
     RECT  96.001 3.456 97.265 4.92 ;
     RECT  97.189 0.096 97.373 0.168 ;
     RECT  96.361 98.592 97.481 99.144 ;
     RECT  97.009 103.2 97.589 104.664 ;
     RECT  97.481 99.12 97.729 99.144 ;
     RECT  97.729 99.12 97.733 99.72 ;
     RECT  97.045 106.032 97.985 106.056 ;
     RECT  97.733 99.696 98.309 99.72 ;
     RECT  97.265 4.176 98.521 4.92 ;
     RECT  98.492 100.224 98.579 100.68 ;
     RECT  98.521 3.408 98.593 4.92 ;
     RECT  94.504 52.416 98.593 52.44 ;
     RECT  94.504 93.84 98.629 93.864 ;
     RECT  98.593 52.272 98.737 52.44 ;
     RECT  97.141 95.184 99.253 95.736 ;
     RECT  98.593 3.408 99.608 5.016 ;
     RECT  98.737 52.272 99.608 53.064 ;
     RECT  98.629 93.84 99.608 94.056 ;
     RECT  99.253 95.184 99.608 96.216 ;
     RECT  99.212 99.12 99.608 99.144 ;
     RECT  98.579 100.224 99.608 100.536 ;
     RECT  97.589 103.2 99.608 104.424 ;
     RECT  99.608 2.148 99.712 105.852 ;
     RECT  98.533 107.856 99.785 107.88 ;
     RECT  99.712 2.418 99.904 105.582 ;
     RECT  99.904 95.184 100.019 95.496 ;
     RECT  99.904 55.248 100.259 55.272 ;
     RECT  99.904 52.272 100.595 53.064 ;
     RECT  99.973 106.56 100.793 106.584 ;
     RECT  99.904 93.84 100.969 93.864 ;
     RECT  99.904 103.2 100.969 103.368 ;
     RECT  99.904 104.4 100.973 104.712 ;
     RECT  99.904 91.728 100.981 92.328 ;
     RECT  100.969 93.84 100.981 94.056 ;
     RECT  100.981 91.728 101.027 94.056 ;
     RECT  100.019 95.184 101.029 95.208 ;
     RECT  101.027 92.784 101.068 94.056 ;
     RECT  101.068 93.84 101.075 94.056 ;
     RECT  101.029 95.184 101.075 95.544 ;
     RECT  101.075 93.84 101.153 93.864 ;
     RECT  99.904 99.168 101.267 99.192 ;
     RECT  101.18 100.656 101.267 100.68 ;
     RECT  100.969 102.768 101.267 103.368 ;
     RECT  101.221 107.184 101.507 107.208 ;
     RECT  100.595 52.272 101.729 52.968 ;
     RECT  99.904 3.408 101.909 5.016 ;
     RECT  100.973 104.4 101.945 104.424 ;
     RECT  101.027 91.728 101.977 91.752 ;
     RECT  102.085 105.984 102.227 106.008 ;
     RECT  101.267 103.2 102.229 103.368 ;
     RECT  102.332 51.552 102.373 51.576 ;
     RECT  102.373 50.688 102.419 51.576 ;
     RECT  102.229 103.2 102.556 104.28 ;
     RECT  102.556 103.2 102.557 103.224 ;
     RECT  101.909 3.408 102.593 4.488 ;
     RECT  102.556 104.208 102.611 104.28 ;
     RECT  102.561 105.456 102.665 105.816 ;
     RECT  101.068 92.784 102.701 92.808 ;
     RECT  101.977 91.44 102.709 91.752 ;
     RECT  102.709 90.912 102.733 91.752 ;
     RECT  102.733 90.624 102.917 91.752 ;
     RECT  102.917 90.624 103.205 91.464 ;
     RECT  101.977 52.992 103.277 53.016 ;
     RECT  103.205 90.816 103.277 91.464 ;
     RECT  101.075 95.52 103.277 95.544 ;
     RECT  102.419 50.688 103.313 50.712 ;
     RECT  102.611 104.256 103.313 104.28 ;
     RECT  102.593 4.272 103.379 4.488 ;
     RECT  103.333 5.712 103.457 5.736 ;
     RECT  102.665 105.792 103.715 105.816 ;
     RECT  104.353 105.984 104.437 106.008 ;
     RECT  97.373 0.096 104.533 0.12 ;
     RECT  104.533 0.096 104.627 0.552 ;
     RECT  103.379 4.464 105.008 4.488 ;
     RECT  103.277 90.816 105.008 90.84 ;
     RECT  105.008 2.148 105.112 105.852 ;
     RECT  105.112 2.418 105.304 105.582 ;
     RECT  104.627 0.096 105.689 0.12 ;
     RECT  105.304 100.464 106.585 100.488 ;
     RECT  104.605 107.184 106.669 107.208 ;
     RECT  106.124 0.528 106.739 0.552 ;
     RECT  106.585 2.16 107.125 2.184 ;
     RECT  105.304 3.696 107.125 3.72 ;
     RECT  106.585 5.232 107.125 5.256 ;
     RECT  106.549 6.768 107.125 6.792 ;
     RECT  106.585 8.304 107.125 8.328 ;
     RECT  106.585 9.84 107.125 11.4 ;
     RECT  106.585 17.52 107.125 17.544 ;
     RECT  106.585 19.824 107.125 19.848 ;
     RECT  106.585 21.36 107.125 22.152 ;
     RECT  106.585 25.968 107.125 25.992 ;
     RECT  106.585 28.272 107.125 29.832 ;
     RECT  106.585 35.184 107.125 35.208 ;
     RECT  106.585 40.56 107.125 40.584 ;
     RECT  106.585 42.096 107.125 42.12 ;
     RECT  106.585 44.4 107.125 45.96 ;
     RECT  106.585 47.472 107.125 48.264 ;
     RECT  106.585 50.544 107.125 50.568 ;
     RECT  106.585 52.08 107.125 52.104 ;
     RECT  106.585 54.384 107.125 55.176 ;
     RECT  106.585 56.688 107.125 57.48 ;
     RECT  106.585 60.528 107.125 62.088 ;
     RECT  106.585 64.368 107.125 64.392 ;
     RECT  106.585 66.672 107.125 66.696 ;
     RECT  106.585 69.744 107.125 69.768 ;
     RECT  106.585 72.048 107.125 72.84 ;
     RECT  106.585 75.12 107.125 75.144 ;
     RECT  106.585 76.656 107.125 77.448 ;
     RECT  106.585 78.96 107.125 81.288 ;
     RECT  106.585 82.8 107.125 82.824 ;
     RECT  106.585 84.336 107.125 84.36 ;
     RECT  106.585 88.176 107.125 88.2 ;
     RECT  106.585 89.712 107.125 89.736 ;
     RECT  106.585 92.016 107.125 92.04 ;
     RECT  106.585 94.32 107.125 95.112 ;
     RECT  106.585 99.696 107.125 100.488 ;
     RECT  107.125 5.232 107.161 6.792 ;
     RECT  107.125 8.304 107.161 11.4 ;
     RECT  107.125 12.912 107.161 12.936 ;
     RECT  107.125 14.448 107.161 17.544 ;
     RECT  107.125 19.056 107.161 22.152 ;
     RECT  107.125 23.664 107.161 26.76 ;
     RECT  107.125 28.272 107.161 30.6 ;
     RECT  107.125 32.88 107.161 37.512 ;
     RECT  107.125 39.024 107.161 42.12 ;
     RECT  107.125 43.632 107.161 48.264 ;
     RECT  107.125 49.776 107.161 52.872 ;
     RECT  107.125 54.384 107.161 57.48 ;
     RECT  107.125 58.992 107.161 62.088 ;
     RECT  107.125 63.6 107.161 64.392 ;
     RECT  107.125 65.904 107.161 68.232 ;
     RECT  107.125 69.744 107.161 72.84 ;
     RECT  107.125 74.352 107.161 88.2 ;
     RECT  107.125 89.712 107.161 90.504 ;
     RECT  107.125 92.016 107.161 92.808 ;
     RECT  107.125 94.32 107.161 102.792 ;
     RECT  107.125 1.392 107.881 3.72 ;
     RECT  107.161 5.232 107.881 42.12 ;
     RECT  107.161 43.632 107.881 62.088 ;
     RECT  107.161 63.6 107.881 106.632 ;
     RECT  107.881 1.392 107.916 1.416 ;
     RECT  107.881 1.416 107.964 2.16 ;
     RECT  107.881 2.16 107.916 2.184 ;
     RECT  107.881 2.184 107.964 2.928 ;
     RECT  107.881 2.928 107.916 2.952 ;
     RECT  107.881 2.952 107.964 3.696 ;
     RECT  107.881 3.696 107.916 3.72 ;
     RECT  107.881 3.72 107.964 4.464 ;
     RECT  107.881 4.464 107.916 4.488 ;
     RECT  107.881 4.488 107.964 5.232 ;
     RECT  107.881 5.232 107.916 5.256 ;
     RECT  107.881 5.256 107.964 6 ;
     RECT  107.881 6 107.916 6.024 ;
     RECT  107.881 6.024 107.964 6.768 ;
     RECT  107.881 6.768 107.916 6.792 ;
     RECT  107.881 6.792 107.964 7.536 ;
     RECT  107.881 7.536 107.916 7.56 ;
     RECT  107.881 7.56 107.964 8.304 ;
     RECT  107.881 8.304 107.916 8.328 ;
     RECT  107.881 8.328 107.964 9.072 ;
     RECT  107.881 9.072 107.916 9.096 ;
     RECT  107.881 9.096 107.964 9.84 ;
     RECT  107.881 9.84 107.916 9.864 ;
     RECT  107.881 9.864 107.964 10.608 ;
     RECT  107.881 10.608 107.916 10.632 ;
     RECT  107.881 10.632 107.964 11.376 ;
     RECT  107.881 11.376 107.916 11.4 ;
     RECT  107.881 11.4 107.964 12.144 ;
     RECT  107.881 12.144 107.916 12.168 ;
     RECT  107.881 12.168 107.964 12.912 ;
     RECT  107.881 12.912 107.916 12.936 ;
     RECT  107.881 12.936 107.964 13.68 ;
     RECT  107.881 13.68 107.916 13.704 ;
     RECT  107.881 13.704 107.964 14.448 ;
     RECT  107.881 14.448 107.916 14.472 ;
     RECT  107.881 14.472 107.964 15.216 ;
     RECT  107.881 15.216 107.916 15.24 ;
     RECT  107.881 15.24 107.964 15.984 ;
     RECT  107.881 15.984 107.916 16.008 ;
     RECT  107.881 16.008 107.964 16.752 ;
     RECT  107.881 16.752 107.916 16.776 ;
     RECT  107.881 16.776 107.964 17.52 ;
     RECT  107.881 17.52 107.916 17.544 ;
     RECT  107.881 17.544 107.964 18.288 ;
     RECT  107.881 18.288 107.916 18.312 ;
     RECT  107.881 18.312 107.964 19.056 ;
     RECT  107.881 19.056 107.916 19.08 ;
     RECT  107.881 19.08 107.964 19.824 ;
     RECT  107.881 19.824 107.916 19.848 ;
     RECT  107.881 19.848 107.964 20.592 ;
     RECT  107.881 20.592 107.916 20.616 ;
     RECT  107.881 20.616 107.964 21.36 ;
     RECT  107.881 21.36 107.916 21.384 ;
     RECT  107.881 21.384 107.964 22.128 ;
     RECT  107.881 22.128 107.916 22.152 ;
     RECT  107.881 22.152 107.964 22.896 ;
     RECT  107.881 22.896 107.916 22.92 ;
     RECT  107.881 22.92 107.964 23.664 ;
     RECT  107.881 23.664 107.916 23.688 ;
     RECT  107.881 23.688 107.964 24.432 ;
     RECT  107.881 24.432 107.916 24.456 ;
     RECT  107.881 24.456 107.964 25.2 ;
     RECT  107.881 25.2 107.916 25.224 ;
     RECT  107.881 25.224 107.964 25.968 ;
     RECT  107.881 25.968 107.916 25.992 ;
     RECT  107.881 25.992 107.964 26.736 ;
     RECT  107.881 26.736 107.916 26.76 ;
     RECT  107.881 26.76 107.964 27.504 ;
     RECT  107.881 27.504 107.916 27.528 ;
     RECT  107.881 27.528 107.964 28.272 ;
     RECT  107.881 28.272 107.916 28.296 ;
     RECT  107.881 28.296 107.964 29.04 ;
     RECT  107.881 29.04 107.916 29.064 ;
     RECT  107.881 29.064 107.964 29.808 ;
     RECT  107.881 29.808 107.916 29.832 ;
     RECT  107.881 29.832 107.964 30.576 ;
     RECT  107.881 30.576 107.916 30.6 ;
     RECT  107.881 30.6 107.964 31.344 ;
     RECT  107.881 31.344 107.916 31.368 ;
     RECT  107.881 31.368 107.964 32.112 ;
     RECT  107.881 32.112 107.916 32.136 ;
     RECT  107.881 32.136 107.964 32.88 ;
     RECT  107.881 32.88 107.916 32.904 ;
     RECT  107.881 32.904 107.964 33.648 ;
     RECT  107.881 33.648 107.916 33.672 ;
     RECT  107.881 33.672 107.964 34.416 ;
     RECT  107.881 34.416 107.916 34.44 ;
     RECT  107.881 34.44 107.964 35.184 ;
     RECT  107.881 35.184 107.916 35.208 ;
     RECT  107.881 35.208 107.964 35.952 ;
     RECT  107.881 35.952 107.916 35.976 ;
     RECT  107.881 35.976 107.964 36.72 ;
     RECT  107.881 36.72 107.916 36.744 ;
     RECT  107.881 36.744 107.964 37.488 ;
     RECT  107.881 37.488 107.916 37.512 ;
     RECT  107.881 37.512 107.964 38.256 ;
     RECT  107.881 38.256 107.916 38.28 ;
     RECT  107.881 38.28 107.964 39.024 ;
     RECT  107.881 39.024 107.916 39.048 ;
     RECT  107.881 39.048 107.964 39.792 ;
     RECT  107.881 39.792 107.916 39.816 ;
     RECT  107.881 39.816 107.964 40.56 ;
     RECT  107.881 40.56 107.916 40.584 ;
     RECT  107.881 40.584 107.964 41.328 ;
     RECT  107.881 41.328 107.916 41.352 ;
     RECT  107.881 41.352 107.964 42.096 ;
     RECT  107.881 42.096 107.916 42.12 ;
     RECT  107.881 42.12 107.964 42.864 ;
     RECT  107.881 42.864 107.916 42.888 ;
     RECT  107.881 42.888 107.964 43.632 ;
     RECT  107.881 43.632 107.916 43.656 ;
     RECT  107.881 43.656 107.964 44.4 ;
     RECT  107.881 44.4 107.916 44.424 ;
     RECT  107.881 44.424 107.964 45.168 ;
     RECT  107.881 45.168 107.916 45.192 ;
     RECT  107.881 45.192 107.964 45.936 ;
     RECT  107.881 45.936 107.916 45.96 ;
     RECT  107.881 45.96 107.964 46.704 ;
     RECT  107.881 46.704 107.916 46.728 ;
     RECT  107.881 46.728 107.964 47.472 ;
     RECT  107.881 47.472 107.916 47.496 ;
     RECT  107.881 47.496 107.964 48.24 ;
     RECT  107.881 48.24 107.916 48.264 ;
     RECT  107.881 48.264 107.964 49.008 ;
     RECT  107.881 49.008 107.916 49.032 ;
     RECT  107.881 49.032 107.964 49.776 ;
     RECT  107.881 49.776 107.916 49.8 ;
     RECT  107.881 49.8 107.964 50.544 ;
     RECT  107.881 50.544 107.916 50.568 ;
     RECT  107.881 50.568 107.964 51.312 ;
     RECT  107.881 51.312 107.916 51.336 ;
     RECT  107.881 51.336 107.964 52.08 ;
     RECT  107.881 52.08 107.916 52.104 ;
     RECT  107.881 52.104 107.964 52.848 ;
     RECT  107.881 52.848 107.916 52.872 ;
     RECT  107.881 52.872 107.964 53.616 ;
     RECT  107.881 53.616 107.916 53.64 ;
     RECT  107.881 53.64 107.964 54.384 ;
     RECT  107.881 54.384 107.916 54.408 ;
     RECT  107.881 54.408 107.964 55.152 ;
     RECT  107.881 55.152 107.916 55.176 ;
     RECT  107.881 55.176 107.964 55.92 ;
     RECT  107.881 55.92 107.916 55.944 ;
     RECT  107.881 55.944 107.964 56.688 ;
     RECT  107.881 56.688 107.916 56.712 ;
     RECT  107.881 56.712 107.964 57.456 ;
     RECT  107.881 57.456 107.916 57.48 ;
     RECT  107.881 57.48 107.964 58.224 ;
     RECT  107.881 58.224 107.916 58.248 ;
     RECT  107.881 58.248 107.964 58.992 ;
     RECT  107.881 58.992 107.916 59.016 ;
     RECT  107.881 59.016 107.964 59.76 ;
     RECT  107.881 59.76 107.916 59.784 ;
     RECT  107.881 59.784 107.964 60.528 ;
     RECT  107.881 60.528 107.916 60.552 ;
     RECT  107.881 60.552 107.964 61.296 ;
     RECT  107.881 61.296 107.916 61.32 ;
     RECT  107.881 61.32 107.964 62.064 ;
     RECT  107.881 62.064 107.916 62.088 ;
     RECT  107.881 62.088 107.964 62.832 ;
     RECT  107.881 62.832 107.916 62.856 ;
     RECT  107.881 62.856 107.964 63.6 ;
     RECT  107.881 63.6 107.916 63.624 ;
     RECT  107.881 63.624 107.964 64.368 ;
     RECT  107.881 64.368 107.916 64.392 ;
     RECT  107.881 64.392 107.964 65.136 ;
     RECT  107.881 65.136 107.916 65.16 ;
     RECT  107.881 65.16 107.964 65.904 ;
     RECT  107.881 65.904 107.916 65.928 ;
     RECT  107.881 65.928 107.964 66.672 ;
     RECT  107.881 66.672 107.916 66.696 ;
     RECT  107.881 66.696 107.964 67.44 ;
     RECT  107.881 67.44 107.916 67.464 ;
     RECT  107.881 67.464 107.964 68.208 ;
     RECT  107.881 68.208 107.916 68.232 ;
     RECT  107.881 68.232 107.964 68.976 ;
     RECT  107.881 68.976 107.916 69 ;
     RECT  107.881 69 107.964 69.744 ;
     RECT  107.881 69.744 107.916 69.768 ;
     RECT  107.881 69.768 107.964 70.512 ;
     RECT  107.881 70.512 107.916 70.536 ;
     RECT  107.881 70.536 107.964 71.28 ;
     RECT  107.881 71.28 107.916 71.304 ;
     RECT  107.881 71.304 107.964 72.048 ;
     RECT  107.881 72.048 107.916 72.072 ;
     RECT  107.881 72.072 107.964 72.816 ;
     RECT  107.881 72.816 107.916 72.84 ;
     RECT  107.881 72.84 107.964 73.584 ;
     RECT  107.881 73.584 107.916 73.608 ;
     RECT  107.881 73.608 107.964 74.352 ;
     RECT  107.881 74.352 107.916 74.376 ;
     RECT  107.881 74.376 107.964 75.12 ;
     RECT  107.881 75.12 107.916 75.144 ;
     RECT  107.881 75.144 107.964 75.888 ;
     RECT  107.881 75.888 107.916 75.912 ;
     RECT  107.881 75.912 107.964 76.656 ;
     RECT  107.881 76.656 107.916 76.68 ;
     RECT  107.881 76.68 107.964 77.424 ;
     RECT  107.881 77.424 107.916 77.448 ;
     RECT  107.881 77.448 107.964 78.192 ;
     RECT  107.881 78.192 107.916 78.216 ;
     RECT  107.881 78.216 107.964 78.96 ;
     RECT  107.881 78.96 107.916 78.984 ;
     RECT  107.881 78.984 107.964 79.728 ;
     RECT  107.881 79.728 107.916 79.752 ;
     RECT  107.881 79.752 107.964 80.496 ;
     RECT  107.881 80.496 107.916 80.52 ;
     RECT  107.881 80.52 107.964 81.264 ;
     RECT  107.881 81.264 107.916 81.288 ;
     RECT  107.881 81.288 107.964 82.032 ;
     RECT  107.881 82.032 107.916 82.056 ;
     RECT  107.881 82.056 107.964 82.8 ;
     RECT  107.881 82.8 107.916 82.824 ;
     RECT  107.881 82.824 107.964 83.568 ;
     RECT  107.881 83.568 107.916 83.592 ;
     RECT  107.881 83.592 107.964 84.336 ;
     RECT  107.881 84.336 107.916 84.36 ;
     RECT  107.881 84.36 107.964 85.104 ;
     RECT  107.881 85.104 107.916 85.128 ;
     RECT  107.881 85.128 107.964 85.872 ;
     RECT  107.881 85.872 107.916 85.896 ;
     RECT  107.881 85.896 107.964 86.64 ;
     RECT  107.881 86.64 107.916 86.664 ;
     RECT  107.881 86.664 107.964 87.408 ;
     RECT  107.881 87.408 107.916 87.432 ;
     RECT  107.881 87.432 107.964 88.176 ;
     RECT  107.881 88.176 107.916 88.2 ;
     RECT  107.881 88.2 107.964 88.944 ;
     RECT  107.881 88.944 107.916 88.968 ;
     RECT  107.881 88.968 107.964 89.712 ;
     RECT  107.881 89.712 107.916 89.736 ;
     RECT  107.881 89.736 107.964 90.48 ;
     RECT  107.881 90.48 107.916 90.504 ;
     RECT  107.881 90.504 107.964 91.248 ;
     RECT  107.881 91.248 107.916 91.272 ;
     RECT  107.881 91.272 107.964 92.016 ;
     RECT  107.881 92.016 107.916 92.04 ;
     RECT  107.881 92.04 107.964 92.784 ;
     RECT  107.881 92.784 107.916 92.808 ;
     RECT  107.881 92.808 107.964 93.552 ;
     RECT  107.881 93.552 107.916 93.576 ;
     RECT  107.881 93.576 107.964 94.32 ;
     RECT  107.881 94.32 107.916 94.344 ;
     RECT  107.881 94.344 107.964 95.088 ;
     RECT  107.881 95.088 107.916 95.112 ;
     RECT  107.881 95.112 107.964 95.856 ;
     RECT  107.881 95.856 107.916 95.88 ;
     RECT  107.881 95.88 107.964 96.624 ;
     RECT  107.881 96.624 107.916 96.648 ;
     RECT  107.881 96.648 107.964 97.392 ;
     RECT  107.881 97.392 107.916 97.416 ;
     RECT  107.881 97.416 107.964 98.16 ;
     RECT  107.881 98.16 107.916 98.184 ;
     RECT  107.881 98.184 107.964 98.928 ;
     RECT  107.881 98.928 107.916 98.952 ;
     RECT  107.881 98.952 107.964 99.696 ;
     RECT  107.881 99.696 107.916 99.72 ;
     RECT  107.881 99.72 107.964 100.464 ;
     RECT  107.881 100.464 107.916 100.488 ;
     RECT  107.881 100.488 107.964 101.232 ;
     RECT  107.881 101.232 107.916 101.256 ;
     RECT  107.881 101.256 107.964 102 ;
     RECT  107.881 102 107.916 102.024 ;
     RECT  107.881 102.024 107.964 102.768 ;
     RECT  107.881 102.768 107.916 102.792 ;
     RECT  107.881 102.792 107.964 103.536 ;
     RECT  107.881 103.536 107.916 103.56 ;
     RECT  107.881 103.56 107.964 104.304 ;
     RECT  107.881 104.304 107.916 104.328 ;
     RECT  107.881 104.328 107.964 105.072 ;
     RECT  107.881 105.072 107.916 105.096 ;
     RECT  107.881 105.096 107.964 105.84 ;
     RECT  107.881 105.84 107.916 105.864 ;
     RECT  107.881 105.864 107.964 106.608 ;
     RECT  107.881 106.608 107.916 106.632 ;
    LAYER M5 ;
     RECT  1.272 0.016 1.776 0.084 ;
     RECT  1.8 0.016 2.304 0.084 ;
     RECT  2.328 0.016 2.832 0.084 ;
     RECT  2.856 0.016 3.36 0.084 ;
     RECT  3.384 0.016 3.888 0.084 ;
     RECT  3.912 0.016 4.416 0.084 ;
     RECT  4.44 0.016 4.944 0.084 ;
     RECT  4.968 0.016 5.472 0.084 ;
     RECT  5.496 0.016 6 0.084 ;
     RECT  6.024 0.016 6.576 0.084 ;
     RECT  6.6 0.016 7.104 0.084 ;
     RECT  7.128 0.016 7.632 0.084 ;
     RECT  7.656 0.016 8.16 0.084 ;
     RECT  8.184 0.016 8.688 0.084 ;
     RECT  8.712 0.016 9.216 0.084 ;
     RECT  9.24 0.016 9.744 0.084 ;
     RECT  9.768 0.016 10.272 0.084 ;
     RECT  10.296 0.016 10.8 0.084 ;
     RECT  10.824 0.016 11.328 0.084 ;
     RECT  11.352 0.016 11.856 0.084 ;
     RECT  11.88 0.016 12.384 0.084 ;
     RECT  12.408 0.016 12.912 0.084 ;
     RECT  12.936 0.016 13.44 0.084 ;
     RECT  13.464 0.016 13.968 0.084 ;
     RECT  13.992 0.016 14.496 0.084 ;
     RECT  14.52 0.016 15.024 0.084 ;
     RECT  15.048 0.016 15.552 0.084 ;
     RECT  15.576 0.016 16.08 0.084 ;
     RECT  16.104 0.016 16.608 0.084 ;
     RECT  16.632 0.016 17.136 0.084 ;
     RECT  17.16 0.016 17.664 0.084 ;
     RECT  17.688 0.016 18.192 0.084 ;
     RECT  18.216 0.016 18.72 0.084 ;
     RECT  18.744 0.016 19.296 0.084 ;
     RECT  19.32 0.016 19.824 0.084 ;
     RECT  19.848 0.016 20.352 0.084 ;
     RECT  20.376 0.016 20.88 0.084 ;
     RECT  20.904 0.016 21.408 0.084 ;
     RECT  21.432 0.016 21.936 0.084 ;
     RECT  21.96 0.016 22.464 0.084 ;
     RECT  22.488 0.016 22.992 0.084 ;
     RECT  23.016 0.016 23.52 0.084 ;
     RECT  23.544 0.016 24.048 0.084 ;
     RECT  24.072 0.016 24.576 0.084 ;
     RECT  24.6 0.016 25.104 0.084 ;
     RECT  25.128 0.016 25.632 0.084 ;
     RECT  25.656 0.016 26.16 0.084 ;
     RECT  26.184 0.016 26.688 0.084 ;
     RECT  26.712 0.016 27.216 0.084 ;
     RECT  27.24 0.016 27.744 0.084 ;
     RECT  27.768 0.016 28.272 0.084 ;
     RECT  28.296 0.016 28.8 0.084 ;
     RECT  28.824 0.016 29.328 0.084 ;
     RECT  29.352 0.016 29.856 0.084 ;
     RECT  29.88 0.016 30.384 0.084 ;
     RECT  30.408 0.016 30.912 0.084 ;
     RECT  30.936 0.016 31.44 0.084 ;
     RECT  31.464 0.016 32.016 0.084 ;
     RECT  32.04 0.016 32.544 0.084 ;
     RECT  32.568 0.016 33.072 0.084 ;
     RECT  33.096 0.016 33.6 0.084 ;
     RECT  33.624 0.016 34.128 0.084 ;
     RECT  34.152 0.016 34.656 0.084 ;
     RECT  34.68 0.016 35.184 0.084 ;
     RECT  35.208 0.016 35.712 0.084 ;
     RECT  35.736 0.016 36.24 0.084 ;
     RECT  36.264 0.016 36.768 0.084 ;
     RECT  36.792 0.016 37.296 0.084 ;
     RECT  37.32 0.016 37.824 0.084 ;
     RECT  37.848 0.016 38.352 0.084 ;
     RECT  38.376 0.016 38.88 0.084 ;
     RECT  38.904 0.016 39.408 0.084 ;
     RECT  39.432 0.016 39.936 0.084 ;
     RECT  39.96 0.016 40.464 0.084 ;
     RECT  40.488 0.016 40.992 0.084 ;
     RECT  41.016 0.016 41.52 0.084 ;
     RECT  41.544 0.016 42.048 0.084 ;
     RECT  42.072 0.016 42.576 0.084 ;
     RECT  42.6 0.016 43.104 0.084 ;
     RECT  43.128 0.016 43.632 0.084 ;
     RECT  43.656 0.016 44.16 0.084 ;
     RECT  44.184 0.016 44.736 0.084 ;
     RECT  44.76 0.016 45.264 0.084 ;
     RECT  45.288 0.016 45.792 0.084 ;
     RECT  45.816 0.016 46.32 0.084 ;
     RECT  46.344 0.016 46.848 0.084 ;
     RECT  46.872 0.016 47.376 0.084 ;
     RECT  47.4 0.016 47.904 0.084 ;
     RECT  47.928 0.016 48.432 0.084 ;
     RECT  48.456 0.016 48.96 0.084 ;
     RECT  48.984 0.016 49.488 0.084 ;
     RECT  49.512 0.016 50.016 0.084 ;
     RECT  50.04 0.016 50.544 0.084 ;
     RECT  50.568 0.016 51.072 0.084 ;
     RECT  51.096 0.016 51.6 0.084 ;
     RECT  51.624 0.016 52.128 0.084 ;
     RECT  52.152 0.016 52.656 0.084 ;
     RECT  52.68 0.016 53.184 0.084 ;
     RECT  53.208 0.016 53.712 0.084 ;
     RECT  53.736 0.016 54.24 0.084 ;
     RECT  54.264 0.016 54.768 0.084 ;
     RECT  54.792 0.016 55.296 0.084 ;
     RECT  55.32 0.016 55.824 0.084 ;
     RECT  55.848 0.016 56.352 0.084 ;
     RECT  56.376 0.016 56.88 0.084 ;
     RECT  56.904 0.016 57.456 0.084 ;
     RECT  57.48 0.016 57.984 0.084 ;
     RECT  58.008 0.016 58.512 0.084 ;
     RECT  58.536 0.016 59.04 0.084 ;
     RECT  59.064 0.016 59.568 0.084 ;
     RECT  59.592 0.016 60.096 0.084 ;
     RECT  60.12 0.016 60.624 0.084 ;
     RECT  60.648 0.016 61.152 0.084 ;
     RECT  61.176 0.016 61.68 0.084 ;
     RECT  61.704 0.016 62.208 0.084 ;
     RECT  62.232 0.016 62.736 0.084 ;
     RECT  62.76 0.016 63.264 0.084 ;
     RECT  63.288 0.016 63.792 0.084 ;
     RECT  63.816 0.016 64.32 0.084 ;
     RECT  64.344 0.016 64.848 0.084 ;
     RECT  64.872 0.016 65.376 0.084 ;
     RECT  65.4 0.016 65.904 0.084 ;
     RECT  65.928 0.016 66.432 0.084 ;
     RECT  66.456 0.016 66.96 0.084 ;
     RECT  66.984 0.016 67.488 0.084 ;
     RECT  67.512 0.016 68.016 0.084 ;
     RECT  68.04 0.016 68.544 0.084 ;
     RECT  68.568 0.016 69.072 0.084 ;
     RECT  69.096 0.016 69.6 0.084 ;
     RECT  69.624 0.016 70.176 0.084 ;
     RECT  70.2 0.016 70.704 0.084 ;
     RECT  70.728 0.016 71.232 0.084 ;
     RECT  71.256 0.016 71.76 0.084 ;
     RECT  71.784 0.016 72.288 0.084 ;
     RECT  72.312 0.016 72.816 0.084 ;
     RECT  72.84 0.016 73.344 0.084 ;
     RECT  73.368 0.016 73.872 0.084 ;
     RECT  73.896 0.016 74.4 0.084 ;
     RECT  74.424 0.016 74.928 0.084 ;
     RECT  74.952 0.016 75.456 0.084 ;
     RECT  75.48 0.016 75.984 0.084 ;
     RECT  76.008 0.016 76.512 0.084 ;
     RECT  76.536 0.016 77.04 0.084 ;
     RECT  77.064 0.016 77.568 0.084 ;
     RECT  77.592 0.016 78.096 0.084 ;
     RECT  78.12 0.016 78.624 0.084 ;
     RECT  78.648 0.016 79.152 0.084 ;
     RECT  79.176 0.016 79.68 0.084 ;
     RECT  79.704 0.016 80.208 0.084 ;
     RECT  80.232 0.016 80.736 0.084 ;
     RECT  80.76 0.016 81.264 0.084 ;
     RECT  81.288 0.016 81.792 0.084 ;
     RECT  81.816 0.016 82.32 0.084 ;
     RECT  82.344 0.016 82.896 0.084 ;
     RECT  82.92 0.016 83.424 0.084 ;
     RECT  83.448 0.016 83.952 0.084 ;
     RECT  83.976 0.016 84.48 0.084 ;
     RECT  84.504 0.016 85.008 0.084 ;
     RECT  85.032 0.016 85.536 0.084 ;
     RECT  85.56 0.016 86.064 0.084 ;
     RECT  86.088 0.016 86.592 0.084 ;
     RECT  86.616 0.016 87.12 0.084 ;
     RECT  87.144 0.016 87.648 0.084 ;
     RECT  87.672 0.016 88.176 0.084 ;
     RECT  88.2 0.016 88.704 0.084 ;
     RECT  88.728 0.016 89.232 0.084 ;
     RECT  89.256 0.016 89.76 0.084 ;
     RECT  89.784 0.016 90.288 0.084 ;
     RECT  90.312 0.016 90.816 0.084 ;
     RECT  90.84 0.016 91.344 0.084 ;
     RECT  91.368 0.016 91.872 0.084 ;
     RECT  91.896 0.016 92.4 0.084 ;
     RECT  92.424 0.016 92.928 0.084 ;
     RECT  92.952 0.016 93.456 0.084 ;
     RECT  93.48 0.016 93.984 0.084 ;
     RECT  94.008 0.016 94.512 0.084 ;
     RECT  94.536 0.016 95.04 0.084 ;
     RECT  95.064 0.016 95.616 0.084 ;
     RECT  95.64 0.016 96.144 0.084 ;
     RECT  96.168 0.016 96.672 0.084 ;
     RECT  96.696 0.016 97.2 0.084 ;
     RECT  97.224 0.016 97.728 0.084 ;
     RECT  97.752 0.016 98.256 0.084 ;
     RECT  98.28 0.016 98.784 0.084 ;
     RECT  98.808 0.016 99.312 0.084 ;
     RECT  99.336 0.016 99.84 0.084 ;
     RECT  99.864 0.016 100.368 0.084 ;
     RECT  100.392 0.016 100.896 0.084 ;
     RECT  100.92 0.016 101.424 0.084 ;
     RECT  101.448 0.016 101.952 0.084 ;
     RECT  101.976 0.016 102.48 0.084 ;
     RECT  102.504 0.016 103.008 0.084 ;
     RECT  103.032 0.016 103.536 0.084 ;
     RECT  103.56 0.016 104.064 0.084 ;
     RECT  104.088 0.016 104.592 0.084 ;
     RECT  104.616 0.016 105.12 0.084 ;
     RECT  105.144 0.016 105.648 0.084 ;
     RECT  105.672 0.016 106.176 0.084 ;
     RECT  106.2 0.016 106.704 0.084 ;
     RECT  1.248 0.084 106.728 0.131 ;
     RECT  1.776 0.131 2.856 0.179 ;
     RECT  97.2 0.131 97.224 0.179 ;
     RECT  3.888 0.131 4.968 0.563 ;
     RECT  11.856 0.131 11.88 0.563 ;
     RECT  24.048 0.131 24.6 0.563 ;
     RECT  29.856 0.131 30.408 0.563 ;
     RECT  34.128 0.131 34.68 0.563 ;
     RECT  43.104 0.131 43.128 0.563 ;
     RECT  45.264 0.131 45.288 0.563 ;
     RECT  51.072 0.131 51.096 0.563 ;
     RECT  54.768 0.131 54.792 0.563 ;
     RECT  56.352 0.131 56.376 0.563 ;
     RECT  61.152 0.131 61.704 0.563 ;
     RECT  72.816 0.131 72.84 0.563 ;
     RECT  86.592 0.131 86.616 0.563 ;
     RECT  104.592 0.131 104.616 0.563 ;
     RECT  106.176 0.131 106.728 0.563 ;
     RECT  6.576 0.131 6.6 0.611 ;
     RECT  7.632 0.131 8.184 0.611 ;
     RECT  10.272 0.131 10.296 0.611 ;
     RECT  15.024 0.131 15.048 0.611 ;
     RECT  24.576 0.563 24.6 0.611 ;
     RECT  30.384 0.563 30.408 0.611 ;
     RECT  12.912 0.131 13.464 1.139 ;
     RECT  4.416 0.563 4.968 1.763 ;
     RECT  20.352 0.131 20.376 1.763 ;
     RECT  22.992 0.131 23.016 1.763 ;
     RECT  26.16 0.131 26.184 1.763 ;
     RECT  18.72 0.131 18.744 2.137 ;
     RECT  7.8 2.137 7.92 2.151 ;
     RECT  13.2 2.137 13.32 2.151 ;
     RECT  18.6 2.137 18.744 2.151 ;
     RECT  24 2.137 24.12 2.151 ;
     RECT  29.4 2.137 29.52 2.151 ;
     RECT  34.8 2.137 34.92 2.151 ;
     RECT  40.2 2.137 40.32 2.151 ;
     RECT  45.6 2.137 45.72 2.151 ;
     RECT  51 2.137 51.12 2.151 ;
     RECT  56.4 2.137 56.52 2.151 ;
     RECT  61.8 2.137 61.92 2.151 ;
     RECT  67.2 2.137 67.32 2.151 ;
     RECT  72.6 2.137 72.72 2.151 ;
     RECT  78 2.137 78.12 2.151 ;
     RECT  83.4 2.137 83.52 2.151 ;
     RECT  88.8 2.137 88.92 2.151 ;
     RECT  94.2 2.137 94.32 2.151 ;
     RECT  99.6 2.137 99.72 2.151 ;
     RECT  105 2.137 105.12 2.151 ;
     RECT  2.304 0.179 2.856 2.291 ;
     RECT  2.304 2.291 2.712 3.347 ;
     RECT  61.8 2.151 62.112 3.397 ;
     RECT  72.6 2.151 72.912 3.397 ;
     RECT  34.8 2.151 35.112 3.493 ;
     RECT  29.4 2.151 29.712 3.541 ;
     RECT  56.4 2.151 56.712 3.589 ;
     RECT  2.4 3.347 2.712 3.733 ;
     RECT  40.2 2.151 40.512 3.877 ;
     RECT  60.912 3.397 62.112 3.877 ;
     RECT  7.8 2.151 8.112 3.925 ;
     RECT  24 2.151 24.312 3.925 ;
     RECT  27.36 3.685 27.384 3.925 ;
     RECT  60.912 3.877 62.808 3.925 ;
     RECT  58.608 3.685 58.632 3.971 ;
     RECT  42.816 3.397 42.84 3.973 ;
     RECT  34.8 3.493 35.208 4.019 ;
     RECT  34.8 4.019 35.112 4.021 ;
     RECT  42.672 3.973 42.84 4.069 ;
     RECT  60.768 3.925 62.808 4.115 ;
     RECT  75.072 3.397 75.096 4.115 ;
     RECT  90.912 3.397 90.936 4.115 ;
     RECT  51 2.151 51.312 4.117 ;
     RECT  56.304 3.589 56.712 4.163 ;
     RECT  28.992 3.541 29.712 4.165 ;
     RECT  40.08 3.877 40.512 4.165 ;
     RECT  42.576 4.069 42.84 4.211 ;
     RECT  23.568 3.925 24.312 4.213 ;
     RECT  28.992 4.165 29.832 4.261 ;
     RECT  45.6 2.151 45.912 4.261 ;
     RECT  85.392 4.165 85.416 4.261 ;
     RECT  48.528 3.589 48.552 4.307 ;
     RECT  28.704 4.261 29.832 4.357 ;
     RECT  45.6 4.261 46.776 4.357 ;
     RECT  85.008 4.261 85.416 4.357 ;
     RECT  22.8 4.213 24.312 4.451 ;
     RECT  45.504 4.357 46.776 4.451 ;
     RECT  50.736 4.117 51.312 4.451 ;
     RECT  42.816 4.211 42.84 4.453 ;
     RECT  54.48 4.309 54.504 4.453 ;
     RECT  28.608 4.357 29.832 4.499 ;
     RECT  36.672 3.973 36.696 4.499 ;
     RECT  54.336 4.453 54.504 4.499 ;
     RECT  33.84 4.021 35.112 4.547 ;
     RECT  2.4 3.733 2.808 4.595 ;
     RECT  27.36 3.925 27.624 4.595 ;
     RECT  40.08 4.165 40.92 4.595 ;
     RECT  60.768 4.115 60.792 4.595 ;
     RECT  61.8 4.115 62.808 4.595 ;
     RECT  23.568 4.451 24.312 4.643 ;
     RECT  42.816 4.453 42.936 4.643 ;
     RECT  18.6 2.151 18.912 4.645 ;
     RECT  45.504 4.451 45.912 4.691 ;
     RECT  9.552 3.925 9.576 4.787 ;
     RECT  29.4 4.499 29.832 4.787 ;
     RECT  72.48 3.397 72.912 4.787 ;
     RECT  63.792 4.117 63.816 4.789 ;
     RECT  63.36 4.789 63.816 4.835 ;
     RECT  21.504 3.301 21.528 4.883 ;
     RECT  28.032 4.741 28.056 4.883 ;
     RECT  52.656 3.349 52.68 5.029 ;
     RECT  52.416 5.029 52.68 5.075 ;
     RECT  6.864 3.925 8.112 5.171 ;
     RECT  38.736 4.213 38.76 5.171 ;
     RECT  84.816 4.357 85.416 5.171 ;
     RECT  33.072 5.221 33.096 5.363 ;
     RECT  85.008 5.171 85.416 5.459 ;
     RECT  34.8 4.547 35.112 5.557 ;
     RECT  40.2 4.595 40.92 5.747 ;
     RECT  42.816 4.643 42.84 5.747 ;
     RECT  103.344 4.261 103.368 5.747 ;
     RECT  54.336 4.499 54.36 6.323 ;
     RECT  40.2 5.747 40.512 6.805 ;
     RECT  5.616 4.261 5.64 6.899 ;
     RECT  44.16 4.405 44.184 7.381 ;
     RECT  85.008 5.459 85.032 7.475 ;
     RECT  39.696 6.805 40.512 7.859 ;
     RECT  41.904 6.805 41.928 8.003 ;
     RECT  46.896 5.797 46.92 8.051 ;
     RECT  43.488 7.381 44.184 8.917 ;
     RECT  42.912 8.917 44.184 8.963 ;
     RECT  51 4.451 51.312 9.205 ;
     RECT  52.416 5.075 52.44 9.205 ;
     RECT  51 9.205 52.44 9.251 ;
     RECT  34.8 5.557 35.688 9.637 ;
     RECT  42.912 8.963 44.088 9.731 ;
     RECT  63.36 4.835 63.384 9.923 ;
     RECT  42.912 9.731 42.936 10.165 ;
     RECT  44.064 9.731 44.088 10.307 ;
     RECT  51 9.251 51.912 10.307 ;
     RECT  40.2 7.859 40.512 10.309 ;
     RECT  51 10.307 51.312 10.693 ;
     RECT  34.8 9.637 36.504 10.789 ;
     RECT  33.936 10.789 36.504 10.883 ;
     RECT  42.144 10.165 42.936 10.883 ;
     RECT  38.64 10.837 38.664 10.979 ;
     RECT  33.936 10.883 35.592 11.459 ;
     RECT  4.56 8.485 4.584 11.893 ;
     RECT  4.56 11.893 5.448 11.939 ;
     RECT  42.912 10.883 42.936 11.939 ;
     RECT  40.08 10.309 40.512 12.469 ;
     RECT  54 9.781 54.024 13.139 ;
     RECT  32.736 6.085 32.76 13.283 ;
     RECT  50.112 10.693 51.312 13.331 ;
     RECT  5.424 11.939 5.448 13.571 ;
     RECT  37.536 12.901 37.56 13.669 ;
     RECT  37.152 13.669 37.56 13.715 ;
     RECT  40.032 12.469 40.512 14.243 ;
     RECT  41.616 13.573 41.64 14.819 ;
     RECT  30.768 14.725 30.792 14.867 ;
     RECT  24 4.643 24.312 14.917 ;
     RECT  25.584 3.925 25.608 14.917 ;
     RECT  17.616 4.645 18.912 14.963 ;
     RECT  5.472 13.621 5.496 15.109 ;
     RECT  4.56 15.109 5.496 15.155 ;
     RECT  37.152 13.715 37.176 15.203 ;
     RECT  48.384 13.285 48.408 15.203 ;
     RECT  45.6 4.691 45.912 15.253 ;
     RECT  43.632 13.477 43.656 15.299 ;
     RECT  18.6 14.963 18.912 15.301 ;
     RECT  40.08 14.243 40.512 16.405 ;
     RECT  40.08 16.405 40.632 17.315 ;
     RECT  45.6 15.253 46.584 17.651 ;
     RECT  4.56 15.155 4.584 18.373 ;
     RECT  4.56 18.373 4.824 18.419 ;
     RECT  34.8 11.459 35.592 18.565 ;
     RECT  6.048 15.157 6.072 18.851 ;
     RECT  33.072 17.461 33.096 19.139 ;
     RECT  7.8 5.171 8.112 19.189 ;
     RECT  31.056 18.757 31.08 19.571 ;
     RECT  34.8 18.565 35.832 19.909 ;
     RECT  37.008 19.237 37.032 19.955 ;
     RECT  43.776 18.757 43.8 20.003 ;
     RECT  38.16 19.333 38.184 20.051 ;
     RECT  7.2 19.189 8.112 21.155 ;
     RECT  34.8 19.909 35.928 21.155 ;
     RECT  31.488 20.485 31.512 21.203 ;
     RECT  7.8 21.155 8.112 21.541 ;
     RECT  29.4 4.787 29.712 22.597 ;
     RECT  24 14.917 25.608 22.739 ;
     RECT  24 22.739 24.792 22.741 ;
     RECT  42.48 20.005 42.504 22.835 ;
     RECT  31.104 21.637 31.128 22.979 ;
     RECT  23.904 22.741 24.792 23.411 ;
     RECT  34.8 21.155 35.112 23.845 ;
     RECT  28.416 22.597 29.712 23.939 ;
     RECT  36.96 22.165 36.984 24.131 ;
     RECT  45.6 17.651 45.912 24.757 ;
     RECT  40.08 17.315 40.512 24.947 ;
     RECT  4.8 18.419 4.824 25.045 ;
     RECT  4.8 25.045 5.112 25.091 ;
     RECT  34.368 23.845 35.112 25.331 ;
     RECT  7.8 21.541 8.472 25.525 ;
     RECT  32.496 24.469 32.52 25.715 ;
     RECT  24 23.411 24.792 25.765 ;
     RECT  27.552 25.093 27.576 25.955 ;
     RECT  24 25.765 25.368 26.197 ;
     RECT  5.088 25.091 5.112 26.531 ;
     RECT  38.736 24.325 38.76 26.725 ;
     RECT  38.64 26.725 38.76 26.771 ;
     RECT  34.8 25.331 35.112 27.205 ;
     RECT  23.472 26.197 25.368 27.733 ;
     RECT  32.448 26.629 32.472 27.875 ;
     RECT  7.68 25.525 8.472 27.971 ;
     RECT  38.64 26.771 38.664 28.115 ;
     RECT  26.688 27.301 26.712 28.307 ;
     RECT  34.8 27.205 35.736 28.451 ;
     RECT  23.472 27.733 25.464 28.547 ;
     RECT  25.344 28.547 25.464 29.123 ;
     RECT  23.472 28.547 24.312 29.219 ;
     RECT  29.4 23.939 29.712 29.509 ;
     RECT  24 29.219 24.312 29.605 ;
     RECT  25.344 29.123 25.368 29.605 ;
     RECT  2.4 4.595 2.712 30.181 ;
     RECT  36.432 28.981 36.456 30.517 ;
     RECT  36.336 30.517 36.456 30.563 ;
     RECT  53.664 13.621 53.688 30.565 ;
     RECT  33.408 29.653 33.432 30.851 ;
     RECT  34.8 28.451 35.112 31.333 ;
     RECT  36.336 30.563 36.36 31.379 ;
     RECT  33.36 31.237 33.384 31.955 ;
     RECT  2.4 30.181 3.624 33.011 ;
     RECT  28.944 29.509 29.712 33.013 ;
     RECT  10.896 25.621 10.92 33.347 ;
     RECT  21.792 32.725 21.816 33.589 ;
     RECT  24 29.605 25.368 33.589 ;
     RECT  34.8 31.333 35.352 33.925 ;
     RECT  17.376 32.341 17.4 34.259 ;
     RECT  27.312 33.589 27.336 34.259 ;
     RECT  23.52 33.589 25.368 34.499 ;
     RECT  25.344 34.499 25.368 34.741 ;
     RECT  6.48 32.965 6.504 34.787 ;
     RECT  31.488 34.165 31.512 34.835 ;
     RECT  28.56 33.013 29.712 35.269 ;
     RECT  25.344 34.741 25.512 35.413 ;
     RECT  53.664 30.565 54.456 35.603 ;
     RECT  18.6 15.301 19.752 35.653 ;
     RECT  23.904 34.499 24.312 35.939 ;
     RECT  28.512 35.269 30.696 35.939 ;
     RECT  18.6 35.653 19.944 36.515 ;
     RECT  29.4 35.939 30.696 36.515 ;
     RECT  24 35.939 24.312 36.661 ;
     RECT  25.344 35.413 26.232 36.661 ;
     RECT  24 36.661 26.232 36.707 ;
     RECT  34.8 33.925 35.592 36.755 ;
     RECT  45.504 24.757 45.912 36.853 ;
     RECT  38.784 36.709 38.808 36.901 ;
     RECT  40.2 24.947 40.512 36.901 ;
     RECT  38.784 36.901 40.512 36.947 ;
     RECT  45.072 36.853 45.912 36.997 ;
     RECT  24 36.707 25.512 37.283 ;
     RECT  4.56 36.421 4.584 37.619 ;
     RECT  15.648 31.381 15.672 37.621 ;
     RECT  15.648 37.621 15.96 37.667 ;
     RECT  18.6 36.515 19.752 37.667 ;
     RECT  21.552 33.589 21.816 37.813 ;
     RECT  15.936 37.667 15.96 38.005 ;
     RECT  29.4 36.515 29.712 38.149 ;
     RECT  15.936 38.005 16.536 38.435 ;
     RECT  6.288 35.317 6.312 38.629 ;
     RECT  27.312 36.661 27.336 38.629 ;
     RECT  6.288 38.629 6.552 38.675 ;
     RECT  26.928 38.629 27.336 38.675 ;
     RECT  39.216 36.947 40.512 38.675 ;
     RECT  7.8 27.971 8.472 38.725 ;
     RECT  18.6 37.667 18.912 38.725 ;
     RECT  15.936 38.435 15.96 38.819 ;
     RECT  25.344 37.283 25.512 39.395 ;
     RECT  32.976 36.373 33 39.635 ;
     RECT  6.528 38.675 6.552 39.877 ;
     RECT  7.8 38.725 8.952 39.877 ;
     RECT  6.528 39.877 8.952 39.923 ;
     RECT  21.552 37.813 22.2 39.923 ;
     RECT  26.928 38.675 26.952 39.923 ;
     RECT  29.4 38.149 29.832 40.067 ;
     RECT  54.096 35.603 54.456 40.115 ;
     RECT  6.816 39.923 8.952 40.163 ;
     RECT  6.816 40.163 8.856 40.355 ;
     RECT  24 37.283 24.312 40.405 ;
     RECT  25.344 39.395 25.368 40.405 ;
     RECT  24 40.405 25.368 40.451 ;
     RECT  12 40.117 12.024 40.547 ;
     RECT  54.288 40.115 54.456 40.595 ;
     RECT  61.8 4.595 62.112 40.981 ;
     RECT  17.136 39.877 17.16 41.075 ;
     RECT  52.416 39.589 52.44 41.075 ;
     RECT  34.8 36.755 35.112 41.221 ;
     RECT  21.552 39.923 21.576 41.267 ;
     RECT  31.872 39.589 31.896 41.267 ;
     RECT  44.928 36.997 45.912 41.413 ;
     RECT  24 40.451 25.224 41.509 ;
     RECT  13.2 2.151 13.512 41.557 ;
     RECT  22.704 40.405 22.728 41.651 ;
     RECT  34.08 41.221 35.112 41.797 ;
     RECT  22.752 41.797 22.776 42.133 ;
     RECT  24 41.509 25.416 42.133 ;
     RECT  29.4 40.067 29.712 42.133 ;
     RECT  22.752 42.133 25.416 42.227 ;
     RECT  44.736 41.413 45.912 42.419 ;
     RECT  7.8 40.355 8.856 42.709 ;
     RECT  18.6 38.725 19.752 42.709 ;
     RECT  28.272 41.269 28.296 42.803 ;
     RECT  12.528 41.557 13.512 42.851 ;
     RECT  18.6 42.709 19.848 42.851 ;
     RECT  21.12 41.749 21.144 42.851 ;
     RECT  33.792 41.797 35.112 42.995 ;
     RECT  22.752 42.227 25.224 43.379 ;
     RECT  34.8 42.995 35.112 43.525 ;
     RECT  23.328 43.379 25.224 43.669 ;
     RECT  11.328 42.181 11.352 43.763 ;
     RECT  3.696 42.709 3.72 43.955 ;
     RECT  33.792 42.995 33.816 43.955 ;
     RECT  23.328 43.669 25.752 44.197 ;
     RECT  23.328 44.197 26.232 44.243 ;
     RECT  67.2 2.151 67.512 44.341 ;
     RECT  18.6 42.851 19.704 44.389 ;
     RECT  7.8 42.709 8.952 44.483 ;
     RECT  17.856 44.389 19.704 44.483 ;
     RECT  23.328 44.243 25.224 44.677 ;
     RECT  17.856 44.483 19.032 44.771 ;
     RECT  28.224 43.141 28.248 44.819 ;
     RECT  34.8 43.525 35.64 44.869 ;
     RECT  17.856 44.771 18.912 45.059 ;
     RECT  23.28 44.677 25.224 45.155 ;
     RECT  34.8 44.869 35.736 45.203 ;
     RECT  21.12 45.013 21.144 45.301 ;
     RECT  26.208 44.243 26.232 45.397 ;
     RECT  71.328 43.285 71.352 45.539 ;
     RECT  7.8 44.483 8.856 45.541 ;
     RECT  10.272 45.493 10.296 45.541 ;
     RECT  29.4 42.133 29.88 45.541 ;
     RECT  75.168 45.301 75.192 45.541 ;
     RECT  21.12 45.301 22.104 45.923 ;
     RECT  32.448 44.917 32.472 46.069 ;
     RECT  18.192 45.059 18.912 46.115 ;
     RECT  33.648 45.013 33.672 46.117 ;
     RECT  34.8 45.203 35.112 46.117 ;
     RECT  37.056 45.205 37.08 46.117 ;
     RECT  6.384 41.557 6.408 46.211 ;
     RECT  26.208 45.397 27.192 46.211 ;
     RECT  39.168 44.773 39.192 46.211 ;
     RECT  7.8 45.541 10.296 46.307 ;
     RECT  10.272 46.307 10.296 46.643 ;
     RECT  33.648 46.117 35.112 46.643 ;
     RECT  13.104 42.851 13.512 46.645 ;
     RECT  7.8 46.307 8.856 46.693 ;
     RECT  61.8 40.981 62.328 46.693 ;
     RECT  13.008 46.645 13.512 46.741 ;
     RECT  14.784 45.205 14.808 46.835 ;
     RECT  23.328 45.155 25.224 46.883 ;
     RECT  75.168 45.541 75.816 46.883 ;
     RECT  29.04 45.541 29.88 46.931 ;
     RECT  33.84 46.643 35.112 47.077 ;
     RECT  36.192 46.117 37.08 47.077 ;
     RECT  13.008 46.741 13.656 47.123 ;
     RECT  18.384 46.115 18.912 47.123 ;
     RECT  27.168 46.211 27.192 47.123 ;
     RECT  16.56 46.645 16.584 47.315 ;
     RECT  13.104 47.123 13.656 47.411 ;
     RECT  18.48 47.123 18.912 47.557 ;
     RECT  22.08 45.923 22.104 47.557 ;
     RECT  23.328 46.883 24.312 47.557 ;
     RECT  60 46.357 60.024 47.651 ;
     RECT  22.08 47.557 24.312 47.699 ;
     RECT  41.568 45.589 41.592 47.747 ;
     RECT  22.08 47.699 22.104 47.845 ;
     RECT  33.84 47.077 37.08 47.891 ;
     RECT  23.472 47.699 24.312 47.893 ;
     RECT  34.128 47.891 37.08 47.939 ;
     RECT  32.064 46.069 32.472 47.941 ;
     RECT  34.128 47.939 37.032 47.987 ;
     RECT  18.48 47.557 19.368 48.275 ;
     RECT  26.208 47.173 26.232 48.277 ;
     RECT  75.168 46.883 75.192 48.373 ;
     RECT  61.8 46.693 62.424 48.419 ;
     RECT  74.928 48.373 75.192 48.419 ;
     RECT  14.496 47.845 14.52 48.421 ;
     RECT  40.2 38.675 40.512 48.421 ;
     RECT  18.48 48.275 19.08 48.467 ;
     RECT  67.104 44.341 67.512 48.515 ;
     RECT  58.128 47.605 58.152 48.899 ;
     RECT  34.416 47.987 37.032 48.995 ;
     RECT  54.288 40.595 54.312 48.995 ;
     RECT  34.8 48.995 37.032 49.043 ;
     RECT  38.16 47.557 38.184 49.043 ;
     RECT  13.104 47.411 13.512 49.045 ;
     RECT  14.496 48.421 15.384 49.045 ;
     RECT  13.104 49.045 15.384 49.091 ;
     RECT  34.8 49.043 36.408 49.091 ;
     RECT  13.2 49.091 15.384 49.187 ;
     RECT  25.632 48.277 26.232 49.235 ;
     RECT  29.28 46.931 29.88 49.381 ;
     RECT  32.016 47.941 32.472 49.477 ;
     RECT  25.632 49.235 25.656 49.619 ;
     RECT  15.36 49.187 15.384 49.763 ;
     RECT  29.28 49.381 30.264 49.813 ;
     RECT  32.016 49.477 32.76 49.859 ;
     RECT  32.304 49.859 32.76 49.907 ;
     RECT  40.2 48.421 41.208 50.677 ;
     RECT  39.84 50.677 41.208 50.771 ;
     RECT  60.048 50.389 60.072 50.771 ;
     RECT  13.2 49.187 13.608 50.821 ;
     RECT  34.8 49.091 35.352 50.867 ;
     RECT  4.032 49.525 4.056 51.059 ;
     RECT  23.472 47.893 24.408 51.109 ;
     RECT  13.104 50.821 14.184 51.251 ;
     RECT  39.84 50.771 40.512 51.395 ;
     RECT  26.448 50.389 26.472 51.635 ;
     RECT  32.4 49.907 32.76 51.635 ;
     RECT  37.632 51.397 37.656 51.637 ;
     RECT  38.736 49.381 38.76 51.637 ;
     RECT  18.6 48.467 19.08 51.683 ;
     RECT  16.512 50.293 16.536 51.829 ;
     RECT  13.104 51.251 13.608 51.875 ;
     RECT  16.416 51.829 16.536 51.875 ;
     RECT  29.28 49.813 31.032 51.923 ;
     RECT  34.8 50.867 35.256 51.923 ;
     RECT  37.632 51.637 38.76 51.923 ;
     RECT  74.928 48.419 74.952 52.307 ;
     RECT  99.6 2.151 99.912 52.309 ;
     RECT  40.08 51.395 40.512 52.355 ;
     RECT  53.568 50.101 53.592 52.499 ;
     RECT  58.656 51.061 58.68 52.499 ;
     RECT  13.104 51.875 13.512 52.597 ;
     RECT  7.248 46.693 8.856 52.739 ;
     RECT  23.232 51.109 24.408 52.739 ;
     RECT  16.416 51.875 16.44 52.981 ;
     RECT  18.6 51.683 18.912 52.981 ;
     RECT  36.384 49.091 36.408 52.981 ;
     RECT  40.2 52.355 40.512 52.981 ;
     RECT  102.384 50.677 102.408 53.027 ;
     RECT  21.888 47.845 22.104 53.075 ;
     RECT  99.6 52.309 100.584 53.075 ;
     RECT  28.128 50.869 28.152 53.555 ;
     RECT  24 52.739 24.408 53.557 ;
     RECT  36.288 52.981 36.408 53.557 ;
     RECT  37.632 51.923 38.184 53.557 ;
     RECT  20.784 52.933 20.808 53.699 ;
     RECT  12.384 52.597 13.512 53.749 ;
     RECT  14.832 52.021 14.856 53.795 ;
     RECT  0.192 3.445 0.216 53.891 ;
     RECT  6 51.013 6.024 54.083 ;
     RECT  16.416 52.981 16.536 54.275 ;
     RECT  49.008 52.405 49.032 54.325 ;
     RECT  12.384 53.749 13.608 54.371 ;
     RECT  49.008 54.325 49.224 54.371 ;
     RECT  24 53.557 25.368 54.373 ;
     RECT  29.28 51.923 29.712 54.709 ;
     RECT  31.008 51.923 31.032 54.709 ;
     RECT  36.288 53.557 38.184 54.755 ;
     RECT  45.072 42.419 45.912 54.755 ;
     RECT  49.2 54.371 49.224 54.755 ;
     RECT  28.176 53.605 28.2 55.237 ;
     RECT  29.28 54.709 31.032 55.237 ;
     RECT  99.6 53.075 99.912 55.237 ;
     RECT  23.904 54.373 25.368 55.283 ;
     RECT  34.8 51.923 35.112 55.285 ;
     RECT  21.888 53.075 21.912 55.331 ;
     RECT  16.512 54.275 16.536 55.525 ;
     RECT  18.6 52.981 19.368 55.667 ;
     RECT  10.848 52.405 10.872 55.669 ;
     RECT  28.176 55.237 31.032 55.669 ;
     RECT  28.176 55.669 31.416 55.907 ;
     RECT  47.76 54.325 47.784 55.907 ;
     RECT  40.2 52.981 41.4 56.195 ;
     RECT  34.8 55.285 35.592 56.341 ;
     RECT  18.6 55.667 19.08 56.389 ;
     RECT  16.272 55.525 16.536 56.435 ;
     RECT  10.848 55.669 11.016 56.483 ;
     RECT  31.008 55.907 31.416 56.965 ;
     RECT  32.4 51.635 32.424 56.965 ;
     RECT  36.912 54.755 38.184 57.013 ;
     RECT  7.68 52.739 8.856 57.059 ;
     RECT  24 55.283 25.368 57.061 ;
     RECT  18 56.389 19.08 57.107 ;
     RECT  31.008 56.965 32.424 57.155 ;
     RECT  12.384 54.371 13.512 57.301 ;
     RECT  28.176 55.907 29.712 57.397 ;
     RECT  28.176 57.397 30.072 57.443 ;
     RECT  36.912 57.013 38.376 57.541 ;
     RECT  7.68 57.059 8.376 58.115 ;
     RECT  12.384 57.301 14.328 58.115 ;
     RECT  28.512 57.443 30.072 58.115 ;
     RECT  10.848 56.483 10.872 58.163 ;
     RECT  34.8 56.341 35.832 58.163 ;
     RECT  36.912 57.541 39.192 58.163 ;
     RECT  36.912 58.163 38.184 58.211 ;
     RECT  38.16 58.211 38.184 58.643 ;
     RECT  7.68 58.115 8.112 58.645 ;
     RECT  22.032 58.069 22.056 58.981 ;
     RECT  12.384 58.115 13.512 59.027 ;
     RECT  16.512 56.435 16.536 59.029 ;
     RECT  39.168 58.163 39.192 59.029 ;
     RECT  40.2 56.195 40.512 59.029 ;
     RECT  5.088 56.389 5.112 59.173 ;
     RECT  24 57.061 25.56 59.173 ;
     RECT  4.8 59.173 5.112 59.219 ;
     RECT  24 59.173 25.656 59.219 ;
     RECT  27.168 58.117 27.192 59.219 ;
     RECT  22.032 58.981 22.2 59.221 ;
     RECT  24 59.219 24.504 59.221 ;
     RECT  36.912 58.211 36.936 59.221 ;
     RECT  31.392 57.155 32.424 59.413 ;
     RECT  31.344 59.413 32.424 59.459 ;
     RECT  23.376 59.221 24.504 59.603 ;
     RECT  21.984 59.221 22.2 59.797 ;
     RECT  23.376 59.603 24.408 59.797 ;
     RECT  12.72 59.027 13.512 59.843 ;
     RECT  36.912 59.221 37.56 60.035 ;
     RECT  18.6 57.107 19.08 60.275 ;
     RECT  34.8 58.163 35.112 60.277 ;
     RECT  7.488 58.645 8.112 60.467 ;
     RECT  31.344 59.459 31.416 60.563 ;
     RECT  16.464 59.029 16.536 60.661 ;
     RECT  21.984 59.797 24.408 60.709 ;
     RECT  25.536 59.219 25.656 60.709 ;
     RECT  11.472 59.749 11.496 60.755 ;
     RECT  34.368 60.277 35.112 60.949 ;
     RECT  39.168 59.029 40.512 60.949 ;
     RECT  21.984 60.709 25.656 60.995 ;
     RECT  34.368 60.949 35.736 61.331 ;
     RECT  7.8 60.467 8.112 61.525 ;
     RECT  23.376 60.995 25.656 61.525 ;
     RECT  39.12 60.949 40.512 61.619 ;
     RECT  28.224 61.189 28.248 61.765 ;
     RECT  29.4 58.115 30.072 61.765 ;
     RECT  34.368 61.331 35.112 61.907 ;
     RECT  31.392 60.563 31.416 61.909 ;
     RECT  32.4 59.459 32.424 61.909 ;
     RECT  39.168 61.619 40.512 62.195 ;
     RECT  28.224 61.765 30.072 62.485 ;
     RECT  31.392 61.909 32.424 62.531 ;
     RECT  23.376 61.525 26.184 62.579 ;
     RECT  31.392 62.531 31.896 62.675 ;
     RECT  20.784 55.285 20.808 62.677 ;
     RECT  18.6 60.275 19.032 62.723 ;
     RECT  28.224 62.485 30.264 62.723 ;
     RECT  36.912 60.035 36.936 63.109 ;
     RECT  15.024 62.677 15.048 63.157 ;
     RECT  31.68 62.675 31.896 63.299 ;
     RECT  21.984 60.995 22.104 63.637 ;
     RECT  24 62.579 26.184 63.731 ;
     RECT  39.168 62.195 39.192 63.779 ;
     RECT  36.432 63.109 36.936 63.781 ;
     RECT  4.8 59.219 4.824 63.875 ;
     RECT  28.464 62.723 30.264 63.923 ;
     RECT  16.464 60.661 17.016 64.019 ;
     RECT  36.432 63.781 37.656 64.021 ;
     RECT  36.432 64.021 38.376 64.069 ;
     RECT  18.6 62.723 18.912 64.165 ;
     RECT  25.536 63.731 26.184 64.307 ;
     RECT  21.984 63.637 22.92 64.357 ;
     RECT  15.024 63.157 15.432 64.403 ;
     RECT  16.464 64.019 16.728 64.451 ;
     RECT  28.464 63.923 30.168 64.499 ;
     RECT  21.984 64.357 22.968 64.645 ;
     RECT  24 63.731 24.312 64.645 ;
     RECT  25.536 64.307 25.992 64.691 ;
     RECT  34.8 61.907 35.112 64.741 ;
     RECT  21.984 64.645 24.312 64.837 ;
     RECT  20.448 62.677 20.808 64.883 ;
     RECT  25.68 64.691 25.992 64.931 ;
     RECT  40.2 62.195 40.512 64.933 ;
     RECT  18.192 64.165 18.912 64.979 ;
     RECT  15.024 64.403 15.048 65.027 ;
     RECT  16.464 64.451 16.488 65.027 ;
     RECT  21.888 64.837 24.312 65.027 ;
     RECT  29.184 64.499 30.168 65.221 ;
     RECT  31.68 63.299 31.704 65.221 ;
     RECT  11.424 61.189 11.448 65.509 ;
     RECT  11.424 65.509 11.832 65.603 ;
     RECT  29.184 65.221 31.704 65.603 ;
     RECT  36.384 64.069 38.376 65.603 ;
     RECT  9.552 64.933 9.576 65.845 ;
     RECT  9.552 65.845 9.864 65.987 ;
     RECT  25.68 64.931 25.704 65.987 ;
     RECT  45.264 54.755 45.912 66.035 ;
     RECT  13.2 59.843 13.512 66.085 ;
     RECT  29.184 65.603 30.792 66.179 ;
     RECT  36.912 65.603 38.376 66.179 ;
     RECT  34.8 64.741 35.208 66.275 ;
     RECT  40.2 64.933 40.68 66.275 ;
     RECT  37.584 66.179 38.376 66.661 ;
     RECT  40.2 66.275 40.512 66.661 ;
     RECT  37.584 66.661 38.424 66.755 ;
     RECT  13.104 66.085 13.512 66.757 ;
     RECT  13.104 66.757 13.608 66.803 ;
     RECT  39.936 66.661 40.512 67.043 ;
     RECT  9.84 65.987 9.864 67.189 ;
     RECT  9.84 67.189 10.536 67.283 ;
     RECT  10.512 67.283 10.536 67.621 ;
     RECT  29.184 66.179 30.168 67.669 ;
     RECT  16.416 65.509 16.44 67.765 ;
     RECT  20.448 64.883 20.472 67.765 ;
     RECT  20.4 67.765 20.472 67.813 ;
     RECT  13.2 66.803 13.608 68.051 ;
     RECT  13.2 68.051 13.512 68.101 ;
     RECT  20.4 67.813 20.856 68.243 ;
     RECT  10.512 67.621 10.776 68.389 ;
     RECT  23.376 65.027 24.312 68.389 ;
     RECT  23.376 68.389 24.408 68.485 ;
     RECT  4.608 67.765 4.632 68.629 ;
     RECT  4.608 68.629 5.112 68.675 ;
     RECT  10.464 68.389 10.776 68.821 ;
     RECT  11.808 65.603 11.832 68.821 ;
     RECT  10.464 68.821 11.832 69.301 ;
     RECT  13.008 68.101 13.512 69.301 ;
     RECT  10.464 69.301 13.512 69.347 ;
     RECT  20.832 68.243 20.856 69.443 ;
     RECT  14.832 69.253 14.856 69.445 ;
     RECT  15.888 67.765 16.44 69.445 ;
     RECT  10.752 69.347 13.512 69.493 ;
     RECT  14.832 69.445 16.44 69.493 ;
     RECT  40.2 67.043 40.512 69.493 ;
     RECT  41.856 67.765 41.88 69.493 ;
     RECT  38.016 66.755 38.424 69.541 ;
     RECT  40.2 69.493 41.88 69.541 ;
     RECT  29.184 67.669 30.408 69.731 ;
     RECT  10.752 69.493 16.536 69.971 ;
     RECT  36.336 69.541 36.36 70.021 ;
     RECT  36.336 70.021 36.792 70.067 ;
     RECT  23.376 68.485 24.552 70.259 ;
     RECT  10.752 69.971 16.296 70.739 ;
     RECT  26.544 67.717 26.568 71.075 ;
     RECT  20.208 69.973 20.232 71.077 ;
     RECT  21.888 65.027 22.008 71.123 ;
     RECT  9.456 70.693 9.48 71.219 ;
     RECT  14.832 70.739 16.296 71.219 ;
     RECT  14.832 71.219 15.432 71.315 ;
     RECT  20.208 71.077 20.28 71.363 ;
     RECT  29.184 69.731 30.216 71.459 ;
     RECT  5.088 68.675 5.112 71.507 ;
     RECT  23.52 70.259 24.552 71.653 ;
     RECT  23.04 71.653 24.552 71.699 ;
     RECT  34.8 66.275 35.112 71.701 ;
     RECT  10.752 70.739 13.512 71.749 ;
     RECT  10.272 71.749 13.512 71.795 ;
     RECT  29.28 71.459 30.216 71.797 ;
     RECT  36.768 70.067 36.792 71.843 ;
     RECT  20.256 71.363 20.28 71.891 ;
     RECT  10.272 71.795 10.296 71.939 ;
     RECT  26.928 71.797 26.952 72.325 ;
     RECT  26.736 72.325 26.952 72.419 ;
     RECT  38.016 69.541 41.88 72.419 ;
     RECT  21.888 71.123 21.912 72.901 ;
     RECT  34.8 71.701 35.352 72.901 ;
     RECT  38.016 72.419 40.512 72.995 ;
     RECT  23.04 71.699 24.504 73.235 ;
     RECT  29.28 71.797 30.552 73.237 ;
     RECT  34.8 72.901 35.736 73.237 ;
     RECT  23.04 73.235 24.456 73.331 ;
     RECT  29.184 73.237 30.552 73.477 ;
     RECT  26.736 72.419 26.76 73.571 ;
     RECT  29.184 73.477 30.984 73.573 ;
     RECT  38.016 72.995 38.232 73.619 ;
     RECT  29.184 73.573 31.416 73.667 ;
     RECT  16.896 72.805 16.92 74.003 ;
     RECT  11.664 71.795 13.512 74.053 ;
     RECT  41.856 72.419 41.88 74.053 ;
     RECT  10.848 74.053 13.512 74.099 ;
     RECT  39.312 72.995 40.512 74.147 ;
     RECT  18.6 64.979 18.912 74.341 ;
     RECT  33.84 73.237 35.736 74.387 ;
     RECT  10.848 74.099 11.976 74.675 ;
     RECT  29.4 73.667 31.416 74.675 ;
     RECT  33.84 74.387 35.256 74.819 ;
     RECT  23.04 73.331 24.312 75.109 ;
     RECT  28.032 74.629 28.056 75.157 ;
     RECT  13.2 74.099 13.512 75.205 ;
     RECT  14.832 71.315 14.856 75.205 ;
     RECT  27.408 75.157 28.056 75.299 ;
     RECT  23.04 75.109 25.08 75.541 ;
     RECT  13.2 75.205 14.856 75.637 ;
     RECT  6.096 71.461 6.12 75.827 ;
     RECT  13.104 75.637 14.856 75.827 ;
     RECT  18.384 74.341 18.912 75.875 ;
     RECT  21.216 72.901 21.912 76.309 ;
     RECT  23.04 75.541 25.272 76.309 ;
     RECT  40.2 74.147 40.512 76.357 ;
     RECT  41.52 74.053 41.88 76.357 ;
     RECT  36.72 74.341 36.744 76.403 ;
     RECT  13.2 75.827 14.856 76.499 ;
     RECT  38.016 73.619 38.04 76.549 ;
     RECT  34.8 74.819 35.256 76.693 ;
     RECT  34.704 76.693 35.256 76.835 ;
     RECT  40.2 76.357 41.88 76.837 ;
     RECT  27.408 75.299 27.432 76.883 ;
     RECT  21.216 76.309 25.272 76.933 ;
     RECT  26.4 76.357 26.424 76.933 ;
     RECT  9.744 76.357 9.768 76.979 ;
     RECT  13.2 76.499 13.704 76.979 ;
     RECT  21.216 76.933 26.424 76.979 ;
     RECT  40.08 76.837 41.88 76.979 ;
     RECT  13.2 76.979 13.512 76.981 ;
     RECT  11.664 74.675 11.976 77.123 ;
     RECT  40.08 76.979 41.544 77.267 ;
     RECT  14.832 76.499 14.856 77.363 ;
     RECT  43.824 66.085 43.848 77.509 ;
     RECT  21.216 76.979 25.848 77.555 ;
     RECT  43.584 77.509 43.848 77.555 ;
     RECT  11.664 77.123 11.688 77.603 ;
     RECT  40.08 77.267 40.512 77.603 ;
     RECT  18.6 75.875 18.912 77.941 ;
     RECT  21.888 77.555 25.848 77.941 ;
     RECT  21.888 77.941 26.184 77.987 ;
     RECT  18 77.941 18.912 77.989 ;
     RECT  37.872 76.549 38.04 78.083 ;
     RECT  29.4 74.675 29.928 78.419 ;
     RECT  41.52 77.267 41.544 78.613 ;
     RECT  19.968 77.701 19.992 78.659 ;
     RECT  41.52 78.613 42.408 78.659 ;
     RECT  5.712 76.885 5.736 78.707 ;
     RECT  15.888 77.989 15.912 79.043 ;
     RECT  36.816 77.269 36.84 79.187 ;
     RECT  17.424 77.989 18.912 79.235 ;
     RECT  23.04 77.987 26.184 79.235 ;
     RECT  23.28 79.235 26.184 79.237 ;
     RECT  21.888 77.987 21.912 79.765 ;
     RECT  10.848 77.701 10.872 79.859 ;
     RECT  20.016 79.189 20.04 79.859 ;
     RECT  28.272 79.909 28.296 79.957 ;
     RECT  42.384 78.659 42.408 80.003 ;
     RECT  23.28 79.237 26.616 80.245 ;
     RECT  23.28 80.245 26.712 80.341 ;
     RECT  14.496 77.941 14.52 80.531 ;
     RECT  30.96 74.675 31.416 80.677 ;
     RECT  18 79.235 18.912 80.725 ;
     RECT  23.28 80.341 26.808 80.821 ;
     RECT  21.792 79.765 21.912 80.867 ;
     RECT  13.104 76.981 13.512 80.869 ;
     RECT  23.28 80.821 26.952 80.869 ;
     RECT  28.08 79.957 28.296 80.869 ;
     RECT  23.28 80.869 28.296 81.061 ;
     RECT  17.376 80.725 18.912 81.157 ;
     RECT  23.28 81.061 28.344 81.157 ;
     RECT  29.4 78.419 29.712 81.157 ;
     RECT  12.768 80.869 13.512 81.205 ;
     RECT  23.28 81.157 29.712 81.299 ;
     RECT  23.28 81.299 28.296 81.491 ;
     RECT  34.8 76.835 35.256 81.541 ;
     RECT  23.28 81.491 28.2 81.587 ;
     RECT  29.4 81.299 29.712 81.733 ;
     RECT  30.912 80.677 31.416 81.733 ;
     RECT  29.4 81.733 31.416 81.923 ;
     RECT  37.872 78.083 37.896 81.925 ;
     RECT  12.768 81.205 14.232 82.115 ;
     RECT  23.28 81.587 27.096 82.115 ;
     RECT  21.792 80.867 21.816 82.261 ;
     RECT  23.472 82.115 27.096 82.403 ;
     RECT  37.008 81.925 37.896 82.453 ;
     RECT  34.8 81.541 35.304 82.499 ;
     RECT  28.176 81.587 28.2 82.549 ;
     RECT  29.4 81.923 30.12 82.549 ;
     RECT  37.008 82.453 37.944 82.645 ;
     RECT  15.6 81.445 15.624 82.691 ;
     RECT  23.472 82.403 26.952 82.883 ;
     RECT  31.344 81.923 31.416 82.885 ;
     RECT  21.792 82.261 22.056 82.981 ;
     RECT  34.8 82.499 35.256 82.981 ;
     RECT  28.176 82.549 30.12 83.173 ;
     RECT  31.344 82.885 31.608 83.173 ;
     RECT  28.176 83.173 31.608 83.219 ;
     RECT  37.008 82.645 38.232 83.221 ;
     RECT  36.48 83.221 38.232 83.267 ;
     RECT  28.32 83.219 31.608 83.317 ;
     RECT  28.32 83.317 31.656 83.557 ;
     RECT  21.792 82.981 22.152 83.747 ;
     RECT  34.176 82.981 35.256 83.893 ;
     RECT  36.48 83.267 37.032 83.893 ;
     RECT  23.472 82.883 26.856 84.085 ;
     RECT  28.32 83.557 31.704 84.131 ;
     RECT  31.584 84.131 31.704 84.133 ;
     RECT  23.472 84.085 26.952 84.179 ;
     RECT  28.32 84.131 30.12 84.275 ;
     RECT  34.176 83.893 37.032 84.419 ;
     RECT  24 84.179 26.952 84.755 ;
     RECT  16.8 81.157 18.912 84.901 ;
     RECT  21.792 83.747 21.816 84.901 ;
     RECT  16.8 84.901 19.608 84.995 ;
     RECT  34.176 84.419 36.12 84.995 ;
     RECT  38.208 83.267 38.232 85.045 ;
     RECT  38.208 85.045 38.472 85.091 ;
     RECT  31.584 84.133 32.136 85.093 ;
     RECT  25.68 84.755 26.952 85.139 ;
     RECT  16.896 84.995 19.608 85.427 ;
     RECT  28.416 84.275 30.12 85.427 ;
     RECT  31.584 85.093 32.28 85.475 ;
     RECT  12.768 82.115 13.512 85.523 ;
     RECT  31.584 85.475 31.944 85.523 ;
     RECT  6.288 80.533 6.312 85.667 ;
     RECT  28.416 85.427 29.712 85.667 ;
     RECT  34.8 84.995 36.12 85.715 ;
     RECT  38.448 85.091 38.472 85.765 ;
     RECT  40.2 77.603 40.512 85.765 ;
     RECT  24 84.755 24.648 85.811 ;
     RECT  13.2 85.523 13.512 86.005 ;
     RECT  21.648 84.901 21.816 86.147 ;
     RECT  21.792 86.147 21.816 86.195 ;
     RECT  22.944 85.381 22.968 86.243 ;
     RECT  16.896 85.427 18.912 86.581 ;
     RECT  25.68 85.139 26.616 86.675 ;
     RECT  31.584 85.523 31.608 86.677 ;
     RECT  31.344 86.677 31.608 86.723 ;
     RECT  16.8 86.581 18.912 87.157 ;
     RECT  20.592 84.325 20.616 87.157 ;
     RECT  43.584 77.555 43.608 87.157 ;
     RECT  25.68 86.675 25.704 87.251 ;
     RECT  38.448 85.765 40.512 87.251 ;
     RECT  40.2 87.251 40.512 87.349 ;
     RECT  37.392 85.765 37.416 87.395 ;
     RECT  43.584 87.157 44.376 87.395 ;
     RECT  24 85.811 24.552 87.539 ;
     RECT  42.48 82.645 42.504 87.731 ;
     RECT  56.4 4.163 56.712 87.733 ;
     RECT  7.8 61.525 8.472 87.781 ;
     RECT  9.504 84.325 9.528 87.781 ;
     RECT  6.624 86.581 6.648 87.827 ;
     RECT  7.8 87.781 9.528 87.827 ;
     RECT  24 87.539 24.456 87.923 ;
     RECT  44.352 87.395 44.376 88.211 ;
     RECT  24 87.923 24.312 88.213 ;
     RECT  13.2 86.005 13.704 88.403 ;
     RECT  16.8 87.157 20.616 88.499 ;
     RECT  34.8 85.715 35.112 88.501 ;
     RECT  36.096 85.715 36.12 88.501 ;
     RECT  18.6 88.499 20.616 88.883 ;
     RECT  13.2 88.403 13.512 88.885 ;
     RECT  16.8 88.499 17.352 88.931 ;
     RECT  23.76 88.213 24.312 89.123 ;
     RECT  29.4 85.667 29.712 89.173 ;
     RECT  40.2 87.349 40.632 89.219 ;
     RECT  31.344 86.723 31.368 89.413 ;
     RECT  20.592 88.883 20.616 89.459 ;
     RECT  31.344 89.413 31.704 89.459 ;
     RECT  38.496 87.251 38.52 89.461 ;
     RECT  38.208 89.461 38.52 89.507 ;
     RECT  34.8 88.501 36.12 89.555 ;
     RECT  48.48 88.885 48.504 89.555 ;
     RECT  36.096 89.555 36.12 89.699 ;
     RECT  13.104 88.885 13.512 89.939 ;
     RECT  21.6 89.509 21.624 90.037 ;
     RECT  38.208 89.507 38.232 90.083 ;
     RECT  56.4 87.733 57.576 90.275 ;
     RECT  67.2 48.515 67.512 90.565 ;
     RECT  34.8 89.555 35.112 90.805 ;
     RECT  102.72 90.901 102.744 91.475 ;
     RECT  29.04 89.173 29.712 91.619 ;
     RECT  99.6 55.237 100.248 91.763 ;
     RECT  21.12 90.037 21.624 91.811 ;
     RECT  34.8 90.805 35.208 91.907 ;
     RECT  11.952 91.141 11.976 92.003 ;
     RECT  4.656 91.717 4.68 92.099 ;
     RECT  18.6 88.883 19.128 92.675 ;
     RECT  13.2 89.939 13.512 92.821 ;
     RECT  24 89.123 24.312 92.869 ;
     RECT  5.184 92.773 5.208 92.915 ;
     RECT  100.992 92.293 101.016 93.059 ;
     RECT  7.8 87.827 9.384 93.061 ;
     RECT  29.4 91.619 29.712 93.061 ;
     RECT  6.336 92.965 6.36 93.107 ;
     RECT  24 92.869 25.128 93.301 ;
     RECT  21.6 91.811 21.624 93.491 ;
     RECT  99.6 91.763 100.008 94.021 ;
     RECT  10.368 93.253 10.392 94.115 ;
     RECT  16.8 88.931 16.824 94.115 ;
     RECT  23.04 93.301 25.128 94.163 ;
     RECT  18.6 92.675 18.912 94.165 ;
     RECT  12.864 92.821 13.512 94.259 ;
     RECT  29.28 93.061 29.712 94.355 ;
     RECT  23.04 94.163 24.552 94.405 ;
     RECT  31.68 89.459 31.704 94.453 ;
     RECT  3.936 93.829 3.96 94.691 ;
     RECT  20.544 94.021 20.568 94.691 ;
     RECT  7.68 93.061 9.384 94.979 ;
     RECT  22.896 94.405 24.552 95.219 ;
     RECT  98.64 94.021 100.008 95.219 ;
     RECT  18.48 94.165 18.912 95.461 ;
     RECT  99.264 95.219 100.008 95.507 ;
     RECT  101.04 94.021 101.064 95.555 ;
     RECT  42.72 89.413 42.744 95.605 ;
     RECT  42.48 95.605 42.744 95.651 ;
     RECT  96.912 95.173 96.936 95.701 ;
     RECT  48.72 90.373 48.744 95.747 ;
     RECT  21.456 95.125 21.48 95.795 ;
     RECT  22.896 95.219 24.312 95.795 ;
     RECT  5.184 95.125 5.208 96.277 ;
     RECT  11.952 95.125 11.976 96.323 ;
     RECT  7.68 94.979 8.472 96.419 ;
     RECT  5.088 96.277 5.208 96.901 ;
     RECT  96.912 95.701 97.176 96.995 ;
     RECT  94.2 2.151 94.512 97.093 ;
     RECT  10.8 96.277 10.824 97.523 ;
     RECT  33.12 90.757 33.144 97.667 ;
     RECT  2.4 33.011 2.712 97.909 ;
     RECT  94.2 97.093 95.16 97.957 ;
     RECT  27.12 94.549 27.144 98.053 ;
     RECT  26.496 98.053 27.144 98.099 ;
     RECT  7.8 96.419 8.472 98.101 ;
     RECT  26.496 98.099 26.52 98.341 ;
     RECT  7.68 98.101 8.472 98.387 ;
     RECT  2.4 97.909 2.808 98.675 ;
     RECT  6.336 98.101 6.36 98.723 ;
     RECT  7.68 98.387 8.112 99.491 ;
     RECT  4.896 96.901 5.208 99.589 ;
     RECT  7.8 99.491 8.112 100.117 ;
     RECT  17.616 95.461 18.912 100.211 ;
     RECT  23.184 95.795 24.312 100.259 ;
     RECT  99.264 95.507 99.912 100.259 ;
     RECT  30.96 94.453 31.704 100.499 ;
     RECT  17.088 100.309 17.208 100.931 ;
     RECT  23.328 100.259 24.312 100.931 ;
     RECT  25.968 98.341 26.52 101.459 ;
     RECT  25.968 101.459 25.992 101.987 ;
     RECT  31.296 100.499 31.704 102.661 ;
     RECT  31.296 102.661 32.232 102.803 ;
     RECT  101.232 99.157 101.256 102.803 ;
     RECT  24 100.931 24.312 102.997 ;
     RECT  25.92 102.037 25.944 102.997 ;
     RECT  29.4 94.355 29.712 102.997 ;
     RECT  31.296 102.803 31.32 102.997 ;
     RECT  29.4 102.997 31.32 103.043 ;
     RECT  24 102.997 25.944 103.045 ;
     RECT  29.4 103.043 30.36 103.045 ;
     RECT  23.76 103.045 25.944 103.093 ;
     RECT  23.76 103.093 26.904 103.235 ;
     RECT  42.48 95.651 42.504 103.235 ;
     RECT  97.152 96.995 97.176 103.235 ;
     RECT  24 103.235 26.904 103.285 ;
     RECT  98.544 100.645 98.568 103.331 ;
     RECT  24 103.285 27.576 103.475 ;
     RECT  24 103.475 26.904 103.619 ;
     RECT  29.136 103.045 30.36 103.619 ;
     RECT  78 2.151 78.312 103.717 ;
     RECT  82.176 100.213 82.2 103.763 ;
     RECT  56.4 90.275 56.712 103.765 ;
     RECT  56.4 103.765 56.856 103.907 ;
     RECT  21.12 103.813 21.144 103.955 ;
     RECT  36.096 103.669 36.12 104.005 ;
     RECT  4.752 99.589 5.208 104.051 ;
     RECT  14.832 103.813 14.856 104.051 ;
     RECT  67.2 90.565 68.04 104.051 ;
     RECT  29.28 103.619 30.36 104.101 ;
     RECT  24 103.619 26.664 104.147 ;
     RECT  36.096 104.005 36.216 104.147 ;
     RECT  102.48 103.333 102.504 104.197 ;
     RECT  4.752 104.051 4.776 104.243 ;
     RECT  49.44 95.797 49.464 104.243 ;
     RECT  10.608 103.717 10.632 104.291 ;
     RECT  17.184 100.931 17.208 104.291 ;
     RECT  29.28 104.101 31.032 104.291 ;
     RECT  33.072 104.005 33.096 104.291 ;
     RECT  102.48 104.197 102.6 104.291 ;
     RECT  7.8 100.117 8.664 104.339 ;
     RECT  36.096 104.147 36.12 104.339 ;
     RECT  90.96 100.645 90.984 104.339 ;
     RECT  94.2 97.957 95.496 104.435 ;
     RECT  47.808 103.717 47.832 104.483 ;
     RECT  70.656 103.525 70.68 104.531 ;
     RECT  25.728 104.147 26.664 104.579 ;
     RECT  85.536 103.717 85.56 104.579 ;
     RECT  77.328 103.717 78.312 104.675 ;
     RECT  29.28 104.291 29.712 104.915 ;
     RECT  31.008 104.291 31.032 104.915 ;
     RECT  25.728 104.579 25.752 104.963 ;
     RECT  6.288 104.245 6.312 105.107 ;
     RECT  29.4 104.915 29.712 105.445 ;
     RECT  102.576 104.291 102.6 105.781 ;
     RECT  2.4 98.675 2.712 105.849 ;
     RECT  34.8 91.907 35.112 105.849 ;
     RECT  56.4 103.907 56.712 105.849 ;
     RECT  61.8 48.419 62.112 105.849 ;
     RECT  72.6 4.787 72.912 105.849 ;
     RECT  94.2 104.435 94.512 105.849 ;
     RECT  105 2.151 105.312 105.849 ;
     RECT  2.4 105.849 2.52 105.863 ;
     RECT  24 104.147 24.312 105.863 ;
     RECT  34.8 105.849 34.92 105.863 ;
     RECT  40.2 89.219 40.512 105.863 ;
     RECT  45.6 66.035 45.912 105.863 ;
     RECT  51 13.331 51.312 105.863 ;
     RECT  61.8 105.849 61.92 105.863 ;
     RECT  72.6 105.849 72.72 105.863 ;
     RECT  78 104.675 78.312 105.863 ;
     RECT  83.4 2.151 83.712 105.863 ;
     RECT  88.8 2.151 89.112 105.863 ;
     RECT  94.2 105.849 94.32 105.863 ;
     RECT  99.6 100.259 99.912 105.863 ;
     RECT  105 105.849 105.12 105.863 ;
     RECT  29.4 105.445 30.072 105.925 ;
     RECT  4.32 105.541 4.344 105.973 ;
     RECT  24.192 105.863 24.312 105.973 ;
     RECT  102.576 105.781 103.704 105.973 ;
     RECT  4.32 105.973 5.064 106.021 ;
     RECT  9.456 105.493 9.48 106.021 ;
     RECT  13.2 94.259 13.512 106.021 ;
     RECT  17.568 105.973 17.592 106.021 ;
     RECT  18.6 100.211 18.912 106.021 ;
     RECT  20.496 105.973 20.52 106.021 ;
     RECT  22.704 105.541 22.728 106.021 ;
     RECT  27.12 105.973 27.144 106.021 ;
     RECT  29.328 105.925 30.072 106.021 ;
     RECT  56.4 105.849 56.568 106.021 ;
     RECT  4.32 106.021 5.784 106.549 ;
     RECT  7.8 104.339 8.112 106.549 ;
     RECT  9.456 106.021 10.2 106.549 ;
     RECT  13.152 106.021 13.512 106.549 ;
     RECT  15.36 106.021 15.384 106.549 ;
     RECT  16.8 106.021 18.912 106.549 ;
     RECT  20.496 106.021 22.728 106.549 ;
     RECT  24.192 105.973 24.936 106.549 ;
     RECT  26.4 106.021 27.144 106.549 ;
     RECT  29.328 106.021 30.84 106.549 ;
     RECT  33.744 106.021 33.768 106.549 ;
     RECT  36.672 106.021 36.696 106.549 ;
     RECT  41.088 106.021 41.88 106.549 ;
     RECT  65.376 106.021 66.168 106.549 ;
     RECT  67.2 104.051 67.512 106.549 ;
     RECT  69.072 106.021 69.096 106.549 ;
     RECT  76.416 106.021 76.44 106.549 ;
     RECT  88.944 105.863 89.112 106.549 ;
     RECT  97.056 106.021 97.8 106.549 ;
     RECT  58.752 106.549 59.544 107.125 ;
     RECT  82.32 106.021 82.344 107.173 ;
     RECT  99.984 106.549 100.776 107.173 ;
     RECT  102.192 105.973 104.424 107.173 ;
     RECT  2.112 105.973 2.136 107.845 ;
     RECT  3.552 106.549 22.728 107.845 ;
     RECT  24.192 106.549 32.28 107.845 ;
     RECT  33.744 106.549 34.488 107.845 ;
     RECT  35.952 106.549 36.696 107.845 ;
     RECT  38.88 106.021 38.904 107.845 ;
     RECT  41.088 106.549 44.088 107.845 ;
     RECT  46.272 106.549 47.016 107.845 ;
     RECT  48.48 106.549 48.504 107.845 ;
     RECT  49.92 106.549 49.944 107.845 ;
     RECT  51.408 106.549 52.152 107.845 ;
     RECT  53.616 106.549 54.36 107.845 ;
     RECT  55.824 106.021 56.568 107.845 ;
     RECT  58.752 107.125 60.264 107.845 ;
     RECT  61.728 106.021 61.752 107.845 ;
     RECT  64.656 106.549 67.608 107.845 ;
     RECT  69.072 106.549 69.816 107.845 ;
     RECT  71.28 106.549 72.024 107.845 ;
     RECT  74.208 106.549 74.232 107.845 ;
     RECT  76.416 106.549 77.208 107.845 ;
     RECT  78.672 106.549 80.136 107.845 ;
     RECT  81.6 107.173 82.344 107.845 ;
     RECT  83.808 106.549 85.32 107.845 ;
     RECT  86.736 106.549 87.528 107.845 ;
     RECT  88.944 106.549 89.736 107.845 ;
     RECT  91.92 106.549 92.664 107.845 ;
     RECT  94.128 106.549 94.152 107.845 ;
     RECT  95.568 106.549 97.8 107.845 ;
     RECT  99.984 107.173 106.632 107.845 ;
     RECT  1.344 107.845 106.632 107.916 ;
     RECT  1.368 107.916 2.112 107.984 ;
     RECT  2.136 107.916 2.832 107.984 ;
     RECT  2.856 107.916 3.552 107.984 ;
     RECT  3.576 107.916 4.32 107.984 ;
     RECT  4.344 107.916 5.04 107.984 ;
     RECT  5.064 107.916 5.76 107.984 ;
     RECT  5.784 107.916 6.528 107.984 ;
     RECT  6.552 107.916 7.248 107.984 ;
     RECT  7.272 107.916 7.968 107.984 ;
     RECT  7.992 107.916 8.736 107.984 ;
     RECT  8.76 107.916 9.456 107.984 ;
     RECT  9.48 107.916 10.176 107.984 ;
     RECT  10.2 107.916 10.944 107.984 ;
     RECT  10.968 107.916 11.664 107.984 ;
     RECT  11.688 107.916 12.384 107.984 ;
     RECT  12.408 107.916 13.152 107.984 ;
     RECT  13.176 107.916 13.872 107.984 ;
     RECT  13.896 107.916 14.592 107.984 ;
     RECT  14.616 107.916 15.36 107.984 ;
     RECT  15.384 107.916 16.08 107.984 ;
     RECT  16.104 107.916 16.8 107.984 ;
     RECT  16.824 107.916 17.568 107.984 ;
     RECT  17.592 107.916 18.288 107.984 ;
     RECT  18.312 107.916 19.008 107.984 ;
     RECT  19.032 107.916 19.776 107.984 ;
     RECT  19.8 107.916 20.496 107.984 ;
     RECT  20.52 107.916 21.216 107.984 ;
     RECT  21.24 107.916 21.984 107.984 ;
     RECT  22.008 107.916 22.704 107.984 ;
     RECT  22.728 107.916 23.424 107.984 ;
     RECT  23.448 107.916 24.192 107.984 ;
     RECT  24.216 107.916 24.912 107.984 ;
     RECT  24.936 107.916 25.632 107.984 ;
     RECT  25.656 107.916 26.4 107.984 ;
     RECT  26.424 107.916 27.12 107.984 ;
     RECT  27.144 107.916 27.84 107.984 ;
     RECT  27.864 107.916 28.608 107.984 ;
     RECT  28.632 107.916 29.328 107.984 ;
     RECT  29.352 107.916 30.048 107.984 ;
     RECT  30.072 107.916 30.816 107.984 ;
     RECT  30.84 107.916 31.536 107.984 ;
     RECT  31.56 107.916 32.256 107.984 ;
     RECT  32.28 107.916 33.024 107.984 ;
     RECT  33.048 107.916 33.744 107.984 ;
     RECT  33.768 107.916 34.464 107.984 ;
     RECT  34.488 107.916 35.232 107.984 ;
     RECT  35.256 107.916 35.952 107.984 ;
     RECT  35.976 107.916 36.672 107.984 ;
     RECT  36.696 107.916 37.44 107.984 ;
     RECT  37.464 107.916 38.16 107.984 ;
     RECT  38.184 107.916 38.88 107.984 ;
     RECT  38.904 107.916 39.648 107.984 ;
     RECT  39.672 107.916 40.368 107.984 ;
     RECT  40.392 107.916 41.088 107.984 ;
     RECT  41.112 107.916 41.856 107.984 ;
     RECT  41.88 107.916 42.576 107.984 ;
     RECT  42.6 107.916 43.296 107.984 ;
     RECT  43.32 107.916 44.064 107.984 ;
     RECT  44.088 107.916 44.784 107.984 ;
     RECT  44.808 107.916 45.504 107.984 ;
     RECT  45.528 107.916 46.272 107.984 ;
     RECT  46.296 107.916 46.992 107.984 ;
     RECT  47.016 107.916 47.712 107.984 ;
     RECT  47.736 107.916 48.48 107.984 ;
     RECT  48.504 107.916 49.2 107.984 ;
     RECT  49.224 107.916 49.92 107.984 ;
     RECT  49.944 107.916 50.688 107.984 ;
     RECT  50.712 107.916 51.408 107.984 ;
     RECT  51.432 107.916 52.128 107.984 ;
     RECT  52.152 107.916 52.896 107.984 ;
     RECT  52.92 107.916 53.616 107.984 ;
     RECT  53.64 107.916 54.336 107.984 ;
     RECT  54.36 107.916 55.104 107.984 ;
     RECT  55.128 107.916 55.824 107.984 ;
     RECT  55.848 107.916 56.544 107.984 ;
     RECT  56.568 107.916 57.312 107.984 ;
     RECT  57.336 107.916 58.032 107.984 ;
     RECT  58.056 107.916 58.752 107.984 ;
     RECT  58.776 107.916 59.52 107.984 ;
     RECT  59.544 107.916 60.24 107.984 ;
     RECT  60.264 107.916 60.96 107.984 ;
     RECT  60.984 107.916 61.728 107.984 ;
     RECT  61.752 107.916 62.448 107.984 ;
     RECT  62.472 107.916 63.168 107.984 ;
     RECT  63.192 107.916 63.936 107.984 ;
     RECT  63.96 107.916 64.656 107.984 ;
     RECT  64.68 107.916 65.376 107.984 ;
     RECT  65.4 107.916 66.144 107.984 ;
     RECT  66.168 107.916 66.864 107.984 ;
     RECT  66.888 107.916 67.584 107.984 ;
     RECT  67.608 107.916 68.352 107.984 ;
     RECT  68.376 107.916 69.072 107.984 ;
     RECT  69.096 107.916 69.792 107.984 ;
     RECT  69.816 107.916 70.56 107.984 ;
     RECT  70.584 107.916 71.28 107.984 ;
     RECT  71.304 107.916 72 107.984 ;
     RECT  72.024 107.916 72.768 107.984 ;
     RECT  72.792 107.916 73.488 107.984 ;
     RECT  73.512 107.916 74.208 107.984 ;
     RECT  74.232 107.916 74.976 107.984 ;
     RECT  75 107.916 75.696 107.984 ;
     RECT  75.72 107.916 76.416 107.984 ;
     RECT  76.44 107.916 77.184 107.984 ;
     RECT  77.208 107.916 77.904 107.984 ;
     RECT  77.928 107.916 78.672 107.984 ;
     RECT  78.696 107.916 79.392 107.984 ;
     RECT  79.416 107.916 80.112 107.984 ;
     RECT  80.136 107.916 80.88 107.984 ;
     RECT  80.904 107.916 81.6 107.984 ;
     RECT  81.624 107.916 82.32 107.984 ;
     RECT  82.344 107.916 83.088 107.984 ;
     RECT  83.112 107.916 83.808 107.984 ;
     RECT  83.832 107.916 84.528 107.984 ;
     RECT  84.552 107.916 85.296 107.984 ;
     RECT  85.32 107.916 86.016 107.984 ;
     RECT  86.04 107.916 86.736 107.984 ;
     RECT  86.76 107.916 87.504 107.984 ;
     RECT  87.528 107.916 88.224 107.984 ;
     RECT  88.248 107.916 88.944 107.984 ;
     RECT  88.968 107.916 89.712 107.984 ;
     RECT  89.736 107.916 90.432 107.984 ;
     RECT  90.456 107.916 91.152 107.984 ;
     RECT  91.176 107.916 91.92 107.984 ;
     RECT  91.944 107.916 92.64 107.984 ;
     RECT  92.664 107.916 93.36 107.984 ;
     RECT  93.384 107.916 94.128 107.984 ;
     RECT  94.152 107.916 94.848 107.984 ;
     RECT  94.872 107.916 95.568 107.984 ;
     RECT  95.592 107.916 96.336 107.984 ;
     RECT  96.36 107.916 97.056 107.984 ;
     RECT  97.08 107.916 97.776 107.984 ;
     RECT  97.8 107.916 98.544 107.984 ;
     RECT  98.568 107.916 99.264 107.984 ;
     RECT  99.288 107.916 99.984 107.984 ;
     RECT  100.008 107.916 100.752 107.984 ;
     RECT  100.776 107.916 101.472 107.984 ;
     RECT  101.496 107.916 102.192 107.984 ;
     RECT  102.216 107.916 102.96 107.984 ;
     RECT  102.984 107.916 103.68 107.984 ;
     RECT  103.704 107.916 104.4 107.984 ;
     RECT  104.424 107.916 105.168 107.984 ;
     RECT  105.192 107.916 105.888 107.984 ;
     RECT  105.912 107.916 106.608 107.984 ;
     RECT  2.904 0.131 3.312 0.132 ;
     RECT  3.432 0.131 3.84 0.132 ;
     RECT  6.648 0.131 7.056 0.132 ;
     RECT  7.176 0.131 7.584 0.132 ;
     RECT  11.928 0.131 12.336 0.132 ;
     RECT  12.456 0.131 12.864 0.132 ;
     RECT  23.064 0.131 23.472 0.132 ;
     RECT  23.592 0.131 24 0.132 ;
     RECT  2.856 0.132 3.888 0.563 ;
     RECT  6.6 0.132 7.632 0.611 ;
     RECT  11.88 0.132 12.912 0.563 ;
     RECT  23.016 0.132 24.048 0.563 ;
     RECT  7.8 0.611 7.92 2.137 ;
     RECT  13.2 1.139 13.464 2.137 ;
     RECT  13.32 2.137 13.464 2.151 ;
     RECT  2.712 2.291 2.808 3.733 ;
     RECT  51.312 3.349 52.656 5.029 ;
     RECT  8.112 3.925 9.552 4.787 ;
     RECT  24.312 3.925 25.584 14.917 ;
     RECT  27.624 3.925 28.992 4.261 ;
     RECT  35.208 3.973 36.672 4.019 ;
     RECT  60.792 4.115 61.8 4.595 ;
     RECT  62.808 4.117 63.792 4.595 ;
     RECT  21.528 4.213 22.8 4.451 ;
     RECT  38.76 4.213 40.08 4.595 ;
     RECT  5.64 4.261 6.864 5.171 ;
     RECT  27.624 4.261 28.704 4.357 ;
     RECT  83.712 4.261 85.008 4.357 ;
     RECT  27.624 4.357 28.608 4.499 ;
     RECT  83.712 4.357 84.816 5.171 ;
     RECT  42.84 4.405 44.16 4.453 ;
     RECT  44.184 4.405 45.504 4.691 ;
     RECT  45.912 4.451 46.776 5.797 ;
     RECT  42.936 4.453 44.16 4.643 ;
     RECT  27.624 4.499 29.4 4.595 ;
     RECT  28.032 4.595 29.4 4.741 ;
     RECT  38.76 4.595 40.2 5.171 ;
     RECT  62.112 4.595 63.792 4.789 ;
     RECT  42.84 4.643 44.16 5.747 ;
     RECT  44.184 4.691 45.6 8.963 ;
     RECT  28.056 4.741 29.4 4.883 ;
     RECT  62.112 4.789 63.36 9.923 ;
     RECT  51.312 5.029 52.416 9.205 ;
     RECT  83.712 5.171 85.008 7.475 ;
     RECT  40.512 5.747 40.92 6.805 ;
     RECT  45.912 5.797 46.896 8.051 ;
     RECT  40.512 6.805 41.904 8.003 ;
     RECT  44.088 8.963 45.6 10.307 ;
     RECT  42.936 9.731 44.064 10.307 ;
     RECT  32.76 10.789 33.936 11.459 ;
     RECT  38.664 10.837 40.08 10.979 ;
     RECT  40.032 10.979 40.08 12.469 ;
     RECT  40.512 13.573 41.616 14.819 ;
     RECT  29.712 14.725 30.768 14.867 ;
     RECT  4.584 15.155 5.496 15.157 ;
     RECT  4.584 15.157 6.048 18.373 ;
     RECT  4.824 18.373 6.048 18.851 ;
     RECT  29.712 18.757 31.056 19.571 ;
     RECT  35.832 19.237 37.008 19.909 ;
     RECT  37.032 19.333 38.16 19.955 ;
     RECT  35.928 19.909 37.008 19.955 ;
     RECT  29.712 21.637 31.104 22.979 ;
     RECT  38.76 24.325 40.08 24.947 ;
     RECT  38.76 24.947 40.2 26.771 ;
     RECT  25.368 27.301 26.688 27.733 ;
     RECT  25.464 27.733 26.688 28.307 ;
     RECT  35.112 28.451 35.736 28.981 ;
     RECT  24.312 28.547 25.344 29.605 ;
     RECT  35.112 28.981 36.432 30.517 ;
     RECT  33.432 29.653 34.8 30.851 ;
     RECT  35.112 30.517 36.336 31.333 ;
     RECT  33.408 30.851 34.8 31.237 ;
     RECT  33.384 31.237 34.8 31.955 ;
     RECT  35.352 31.333 36.336 31.379 ;
     RECT  17.4 32.341 18.6 34.259 ;
     RECT  6.504 32.965 7.8 34.787 ;
     RECT  27.336 33.589 28.56 34.259 ;
     RECT  28.512 34.259 28.56 35.269 ;
     RECT  24.312 34.499 25.344 36.661 ;
     RECT  6.48 34.787 7.8 35.317 ;
     RECT  6.312 35.317 7.8 38.629 ;
     RECT  26.232 36.661 27.312 36.707 ;
     RECT  38.808 36.709 40.2 36.901 ;
     RECT  24.312 37.283 25.344 40.405 ;
     RECT  18.912 37.667 19.752 38.725 ;
     RECT  6.552 38.629 7.8 39.877 ;
     RECT  25.512 38.629 26.928 39.395 ;
     RECT  31.896 39.589 32.976 39.635 ;
     RECT  51.312 39.589 52.416 41.075 ;
     RECT  17.16 39.877 18.6 41.075 ;
     RECT  21.576 39.923 22.2 40.405 ;
     RECT  12.024 40.117 13.2 40.547 ;
     RECT  6.816 40.355 7.8 41.557 ;
     RECT  21.576 40.405 22.704 41.267 ;
     RECT  22.728 40.405 24 41.651 ;
     RECT  25.224 40.451 25.368 41.509 ;
     RECT  12.528 40.547 13.2 41.557 ;
     RECT  28.296 41.269 29.4 42.803 ;
     RECT  6.408 41.557 7.8 46.211 ;
     RECT  22.752 41.651 24 41.797 ;
     RECT  19.752 41.749 21.12 42.709 ;
     RECT  22.776 41.797 24 42.133 ;
     RECT  11.352 42.181 12.528 42.851 ;
     RECT  25.224 42.227 25.416 43.669 ;
     RECT  2.712 42.709 3.696 43.955 ;
     RECT  19.848 42.709 21.12 42.851 ;
     RECT  28.272 42.803 29.4 43.141 ;
     RECT  33.816 42.995 34.8 43.955 ;
     RECT  28.248 43.141 29.4 44.819 ;
     RECT  71.352 43.285 72.6 45.539 ;
     RECT  23.28 43.379 23.328 44.677 ;
     RECT  33.792 43.955 34.8 44.917 ;
     RECT  25.224 44.243 26.208 46.211 ;
     RECT  8.856 44.483 8.952 45.493 ;
     RECT  39.192 44.773 40.2 46.211 ;
     RECT  29.04 44.819 29.4 45.541 ;
     RECT  32.472 44.917 34.8 45.013 ;
     RECT  32.472 45.013 33.648 46.643 ;
     RECT  33.672 45.013 34.8 46.117 ;
     RECT  23.28 45.155 23.328 45.301 ;
     RECT  35.112 45.203 35.736 45.205 ;
     RECT  13.512 45.205 14.784 46.741 ;
     RECT  35.112 45.205 37.056 46.117 ;
     RECT  22.104 45.301 23.328 47.557 ;
     RECT  8.856 45.493 10.272 45.541 ;
     RECT  40.512 45.589 41.568 47.747 ;
     RECT  35.112 46.117 36.192 47.077 ;
     RECT  7.248 46.211 7.8 46.693 ;
     RECT  25.224 46.211 27.168 46.883 ;
     RECT  8.856 46.307 10.272 46.643 ;
     RECT  32.472 46.643 33.84 47.891 ;
     RECT  13.656 46.741 14.784 46.835 ;
     RECT  13.656 46.835 14.52 47.411 ;
     RECT  24.312 46.883 27.168 47.123 ;
     RECT  24.312 47.123 26.232 47.173 ;
     RECT  24.312 47.173 26.208 47.893 ;
     RECT  13.512 47.411 14.52 47.845 ;
     RECT  37.08 47.557 38.16 47.939 ;
     RECT  56.712 47.605 58.128 48.899 ;
     RECT  22.104 47.699 23.472 51.109 ;
     RECT  40.512 47.747 41.208 48.421 ;
     RECT  13.512 47.845 14.496 49.045 ;
     RECT  24.408 47.893 26.208 48.277 ;
     RECT  37.032 47.939 38.16 49.043 ;
     RECT  24.408 48.277 25.632 49.619 ;
     RECT  35.352 49.091 36.384 50.867 ;
     RECT  38.76 49.381 40.2 50.677 ;
     RECT  2.712 49.525 4.032 51.059 ;
     RECT  31.032 49.813 32.016 49.859 ;
     RECT  31.032 49.859 32.304 49.907 ;
     RECT  31.032 49.907 32.4 55.669 ;
     RECT  38.76 50.677 39.84 51.395 ;
     RECT  35.256 50.867 36.384 51.923 ;
     RECT  28.152 50.869 29.28 53.555 ;
     RECT  6.024 51.013 7.248 52.739 ;
     RECT  22.104 51.109 23.232 52.739 ;
     RECT  13.608 51.251 14.184 51.875 ;
     RECT  38.76 51.395 40.08 51.923 ;
     RECT  36.408 51.397 37.632 53.557 ;
     RECT  37.656 51.397 38.736 51.637 ;
     RECT  18.912 51.683 19.08 52.981 ;
     RECT  13.512 51.875 14.184 52.021 ;
     RECT  16.44 51.875 16.536 52.981 ;
     RECT  29.712 51.923 31.008 54.709 ;
     RECT  35.112 51.923 36.384 52.981 ;
     RECT  13.512 52.021 14.832 53.749 ;
     RECT  10.872 52.597 12.384 55.669 ;
     RECT  20.808 52.933 21.888 53.699 ;
     RECT  19.368 52.981 20.784 53.699 ;
     RECT  35.112 52.981 36.288 54.755 ;
     RECT  28.176 53.555 29.28 53.605 ;
     RECT  28.2 53.605 29.28 55.237 ;
     RECT  13.608 53.749 14.832 53.795 ;
     RECT  16.416 54.275 16.512 55.525 ;
     RECT  47.784 54.325 49.008 54.371 ;
     RECT  47.784 54.371 49.2 54.755 ;
     RECT  35.112 54.755 36.912 55.285 ;
     RECT  19.368 55.285 20.784 55.667 ;
     RECT  20.808 55.285 21.888 55.331 ;
     RECT  35.592 55.285 36.912 56.341 ;
     RECT  11.016 55.669 12.384 56.483 ;
     RECT  31.416 55.669 32.4 56.965 ;
     RECT  29.712 55.907 31.008 57.155 ;
     RECT  35.832 56.341 36.912 58.163 ;
     RECT  16.536 56.389 18 57.107 ;
     RECT  10.872 56.483 12.384 58.163 ;
     RECT  29.712 57.155 31.392 57.397 ;
     RECT  30.072 57.397 31.392 59.413 ;
     RECT  39.192 57.541 40.2 59.029 ;
     RECT  20.808 58.069 22.032 59.221 ;
     RECT  38.184 58.163 39.168 58.643 ;
     RECT  36.936 58.211 38.16 58.643 ;
     RECT  36.936 58.643 37.56 59.221 ;
     RECT  12.384 59.027 12.72 59.749 ;
     RECT  25.656 59.173 27.168 59.219 ;
     RECT  24.504 59.219 25.536 59.603 ;
     RECT  20.808 59.221 21.984 64.837 ;
     RECT  22.2 59.221 23.376 59.797 ;
     RECT  30.072 59.413 31.344 60.563 ;
     RECT  31.416 59.459 32.4 61.909 ;
     RECT  24.408 59.603 25.536 60.709 ;
     RECT  11.496 59.749 12.72 59.843 ;
     RECT  30.072 60.563 31.392 62.485 ;
     RECT  35.736 60.949 36.912 61.331 ;
     RECT  22.104 60.995 23.376 62.579 ;
     RECT  28.248 61.189 29.4 61.765 ;
     RECT  39.192 62.195 40.2 63.779 ;
     RECT  30.264 62.485 31.392 62.675 ;
     RECT  22.104 62.579 24 63.637 ;
     RECT  30.264 62.675 31.68 63.923 ;
     RECT  13.512 62.677 15.024 65.027 ;
     RECT  15.048 62.677 16.464 63.157 ;
     RECT  19.032 62.677 20.448 62.723 ;
     RECT  35.112 63.109 36.432 64.069 ;
     RECT  15.432 63.157 16.464 64.403 ;
     RECT  22.92 63.637 24 64.357 ;
     RECT  24.312 63.731 25.536 64.691 ;
     RECT  30.168 63.923 31.68 65.221 ;
     RECT  16.728 64.019 17.016 64.165 ;
     RECT  35.112 64.069 36.384 64.741 ;
     RECT  16.728 64.165 18.192 64.451 ;
     RECT  22.968 64.357 24 64.645 ;
     RECT  15.048 64.403 16.464 65.027 ;
     RECT  24.312 64.691 25.68 65.987 ;
     RECT  35.208 64.741 36.384 65.603 ;
     RECT  20.808 64.837 21.888 64.883 ;
     RECT  20.472 64.883 21.888 67.813 ;
     RECT  8.472 64.933 9.552 65.987 ;
     RECT  16.416 65.027 16.44 65.509 ;
     RECT  22.008 65.027 23.376 70.259 ;
     RECT  11.832 65.509 13.2 66.085 ;
     RECT  8.472 65.987 9.84 67.283 ;
     RECT  11.832 66.085 13.104 66.803 ;
     RECT  30.168 66.179 30.408 67.669 ;
     RECT  40.512 66.275 40.68 67.765 ;
     RECT  38.424 66.661 39.936 67.043 ;
     RECT  11.832 66.803 13.2 68.101 ;
     RECT  10.536 67.189 11.808 67.621 ;
     RECT  10.464 67.283 10.512 68.389 ;
     RECT  10.776 67.621 11.808 68.821 ;
     RECT  18.912 67.765 20.4 68.243 ;
     RECT  40.512 67.765 41.856 69.493 ;
     RECT  20.856 67.813 21.888 69.443 ;
     RECT  13.512 68.051 13.608 69.253 ;
     RECT  11.832 68.101 13.008 69.301 ;
     RECT  13.512 69.253 14.832 69.493 ;
     RECT  14.856 69.253 15.888 69.445 ;
     RECT  10.464 69.347 10.752 70.693 ;
     RECT  35.112 69.541 36.336 70.067 ;
     RECT  18.912 69.973 20.208 71.363 ;
     RECT  36.792 70.021 38.016 71.843 ;
     RECT  22.008 70.259 23.52 71.123 ;
     RECT  8.472 70.693 9.456 71.219 ;
     RECT  9.48 70.693 10.752 71.219 ;
     RECT  13.512 70.739 14.832 75.205 ;
     RECT  21.912 71.123 23.52 71.653 ;
     RECT  10.272 71.219 10.752 71.749 ;
     RECT  18.912 71.363 20.256 71.891 ;
     RECT  5.112 71.461 6.096 71.507 ;
     RECT  21.912 71.653 23.04 76.309 ;
     RECT  35.352 71.701 36.768 71.843 ;
     RECT  10.296 71.795 11.664 71.939 ;
     RECT  35.352 71.843 35.736 72.901 ;
     RECT  40.512 72.419 41.856 74.053 ;
     RECT  38.232 72.995 39.312 73.619 ;
     RECT  38.04 73.619 39.312 74.147 ;
     RECT  29.184 73.667 29.4 74.629 ;
     RECT  40.512 74.053 41.52 76.357 ;
     RECT  11.976 74.099 13.2 75.637 ;
     RECT  35.736 74.341 36.72 74.387 ;
     RECT  36.744 74.341 38.016 76.403 ;
     RECT  35.256 74.387 36.72 76.403 ;
     RECT  28.056 74.629 29.4 75.299 ;
     RECT  29.928 74.675 30.96 78.419 ;
     RECT  11.976 75.637 13.104 75.827 ;
     RECT  11.976 75.827 13.2 76.981 ;
     RECT  8.472 76.357 9.744 76.979 ;
     RECT  25.272 76.357 26.4 76.933 ;
     RECT  26.424 76.357 27.408 76.883 ;
     RECT  36.816 76.403 38.016 76.549 ;
     RECT  13.704 76.499 14.832 76.979 ;
     RECT  36.816 76.549 37.872 77.269 ;
     RECT  13.512 76.979 14.832 77.363 ;
     RECT  25.848 76.979 26.184 77.941 ;
     RECT  11.976 76.981 13.104 77.123 ;
     RECT  11.688 77.123 13.104 77.603 ;
     RECT  40.512 77.267 41.52 78.659 ;
     RECT  36.84 77.269 37.872 79.187 ;
     RECT  13.512 77.363 14.856 77.941 ;
     RECT  18.912 77.701 19.968 78.659 ;
     RECT  13.512 77.941 14.496 80.531 ;
     RECT  14.52 77.941 14.856 77.989 ;
     RECT  21.912 77.987 23.04 79.235 ;
     RECT  14.52 77.989 15.888 79.043 ;
     RECT  15.912 77.989 17.424 79.043 ;
     RECT  29.712 78.419 30.96 80.677 ;
     RECT  42.408 78.613 43.584 80.003 ;
     RECT  18.912 78.659 19.992 79.189 ;
     RECT  18.912 79.189 20.016 79.859 ;
     RECT  17.424 79.235 18 80.725 ;
     RECT  21.912 79.235 23.28 80.867 ;
     RECT  28.296 79.909 29.4 81.061 ;
     RECT  26.616 79.957 28.08 80.245 ;
     RECT  26.712 80.245 28.08 80.341 ;
     RECT  26.808 80.341 28.08 80.821 ;
     RECT  13.512 80.531 14.52 81.205 ;
     RECT  6.312 80.533 7.8 85.667 ;
     RECT  29.712 80.677 30.912 81.733 ;
     RECT  26.952 80.821 28.08 80.869 ;
     RECT  21.816 80.867 23.28 82.115 ;
     RECT  28.344 81.061 29.4 81.157 ;
     RECT  14.232 81.205 14.52 81.445 ;
     RECT  28.296 81.299 29.4 81.491 ;
     RECT  14.232 81.445 15.6 82.115 ;
     RECT  15.624 81.445 16.8 82.691 ;
     RECT  28.2 81.491 29.4 82.549 ;
     RECT  27.096 81.587 28.176 82.403 ;
     RECT  30.12 81.923 31.344 83.173 ;
     RECT  21.816 82.115 23.472 82.261 ;
     RECT  22.056 82.261 23.472 82.981 ;
     RECT  26.952 82.403 28.176 82.883 ;
     RECT  35.256 82.499 35.304 83.221 ;
     RECT  42.504 82.645 43.584 87.395 ;
     RECT  26.856 82.883 28.176 83.219 ;
     RECT  22.152 82.981 23.472 83.747 ;
     RECT  26.856 83.219 28.32 84.085 ;
     RECT  35.256 83.221 36.48 83.893 ;
     RECT  37.032 83.267 38.208 84.419 ;
     RECT  26.952 84.085 28.32 84.275 ;
     RECT  30.12 84.131 31.584 85.427 ;
     RECT  23.472 84.179 24 85.381 ;
     RECT  26.952 84.275 28.416 85.139 ;
     RECT  8.472 84.325 9.504 87.781 ;
     RECT  20.616 84.325 21.792 84.901 ;
     RECT  36.12 84.419 38.208 85.091 ;
     RECT  24.648 84.755 25.68 85.811 ;
     RECT  19.608 84.901 20.592 85.427 ;
     RECT  20.616 84.901 21.648 86.147 ;
     RECT  36.12 85.091 38.448 85.765 ;
     RECT  21.816 85.381 22.944 86.195 ;
     RECT  22.968 85.381 24 86.243 ;
     RECT  31.344 85.427 31.584 86.677 ;
     RECT  6.624 85.667 7.8 86.581 ;
     RECT  35.112 85.715 36.096 88.501 ;
     RECT  36.12 85.765 37.392 87.395 ;
     RECT  37.416 85.765 38.448 87.251 ;
     RECT  24.552 85.811 25.68 87.251 ;
     RECT  20.616 86.147 21.792 86.195 ;
     RECT  6.648 86.581 7.8 87.827 ;
     RECT  44.376 87.157 45.6 88.211 ;
     RECT  37.416 87.251 38.496 87.395 ;
     RECT  17.352 88.499 18.6 88.931 ;
     RECT  19.128 88.883 20.592 89.459 ;
     RECT  35.112 89.555 36.096 89.699 ;
     RECT  35.112 89.699 35.208 90.805 ;
     RECT  13.104 89.939 13.2 91.141 ;
     RECT  31.704 90.757 33.12 97.667 ;
     RECT  11.976 91.141 13.2 92.003 ;
     RECT  29.28 91.619 29.4 93.061 ;
     RECT  100.008 91.763 100.248 92.293 ;
     RECT  12.864 92.003 13.2 92.821 ;
     RECT  100.008 92.293 100.992 93.059 ;
     RECT  6.36 92.965 7.8 93.061 ;
     RECT  100.008 93.059 101.016 94.021 ;
     RECT  6.36 93.061 7.68 93.107 ;
     RECT  9.384 93.253 10.368 94.115 ;
     RECT  21.624 93.301 23.04 93.491 ;
     RECT  22.896 93.491 23.04 94.405 ;
     RECT  2.712 93.829 3.936 94.691 ;
     RECT  100.008 94.021 101.04 95.507 ;
     RECT  12.864 94.259 13.2 95.125 ;
     RECT  29.712 94.453 30.96 100.499 ;
     RECT  11.976 95.125 13.2 96.323 ;
     RECT  21.48 95.125 22.896 95.795 ;
     RECT  99.912 95.507 101.04 95.555 ;
     RECT  10.824 96.277 11.952 96.323 ;
     RECT  5.208 98.101 6.336 98.723 ;
     RECT  6.36 98.101 7.68 98.723 ;
     RECT  99.912 99.157 101.232 102.803 ;
     RECT  17.616 100.211 18.6 100.309 ;
     RECT  82.2 100.213 83.4 103.763 ;
     RECT  99.264 100.259 99.6 100.645 ;
     RECT  17.208 100.309 18.6 104.291 ;
     RECT  97.176 100.645 98.544 103.235 ;
     RECT  98.568 100.645 99.6 103.331 ;
     RECT  25.968 101.987 25.992 102.037 ;
     RECT  25.944 102.037 25.992 103.093 ;
     RECT  30.36 103.043 31.032 104.101 ;
     RECT  35.112 103.669 36.096 104.339 ;
     RECT  13.512 103.813 14.832 104.051 ;
     RECT  24.312 104.147 25.728 104.963 ;
     RECT  6.312 104.245 7.8 105.107 ;
     RECT  29.712 104.291 31.008 104.915 ;
     RECT  8.112 104.339 8.664 105.493 ;
     RECT  25.752 104.579 26.664 104.963 ;
     RECT  29.328 104.915 29.4 105.925 ;
     RECT  29.712 104.915 30.84 105.445 ;
     RECT  24.312 104.963 26.664 105.973 ;
     RECT  6.288 105.107 7.8 105.973 ;
     RECT  30.072 105.445 30.84 106.021 ;
     RECT  8.112 105.493 9.456 106.549 ;
     RECT  22.728 105.541 24 105.863 ;
     RECT  103.704 105.781 105 105.863 ;
     RECT  2.52 105.849 2.712 105.863 ;
     RECT  34.92 105.849 35.112 105.863 ;
     RECT  94.32 105.849 94.512 105.863 ;
     RECT  105.12 105.849 105.312 105.863 ;
     RECT  2.4 105.863 2.712 105.973 ;
     RECT  22.728 105.863 24.192 107.845 ;
     RECT  34.8 105.863 35.112 106.021 ;
     RECT  51 105.863 51.312 106.549 ;
     RECT  78 105.863 78.312 106.549 ;
     RECT  83.4 105.863 83.712 106.021 ;
     RECT  88.8 105.863 88.944 106.549 ;
     RECT  94.2 105.863 94.512 106.549 ;
     RECT  103.704 105.863 105.312 105.973 ;
     RECT  2.136 105.973 2.712 106.549 ;
     RECT  5.064 105.973 7.8 106.021 ;
     RECT  17.592 105.973 18.6 106.021 ;
     RECT  24.936 105.973 27.12 106.021 ;
     RECT  104.424 105.973 105.312 107.173 ;
     RECT  5.784 106.021 7.8 106.549 ;
     RECT  15.384 106.021 16.8 106.549 ;
     RECT  24.936 106.021 26.4 106.549 ;
     RECT  33.768 106.021 35.112 106.549 ;
     RECT  66.168 106.021 67.2 106.549 ;
     RECT  82.344 106.021 83.712 106.549 ;
     RECT  2.136 106.549 3.552 107.845 ;
     RECT  32.28 106.549 33.744 107.845 ;
     RECT  34.488 106.549 35.952 107.845 ;
     RECT  47.016 106.549 48.48 107.845 ;
     RECT  48.504 106.549 49.92 107.845 ;
     RECT  49.944 106.549 51.408 107.845 ;
     RECT  52.152 106.549 53.616 107.845 ;
     RECT  54.36 106.549 55.824 107.845 ;
     RECT  67.608 106.549 69.072 107.845 ;
     RECT  69.816 106.549 71.28 107.845 ;
     RECT  77.208 106.549 78.672 107.845 ;
     RECT  82.344 106.549 83.808 107.845 ;
     RECT  85.32 106.549 86.736 107.845 ;
     RECT  87.528 106.549 88.944 107.845 ;
     RECT  92.664 106.549 94.128 107.845 ;
     RECT  94.152 106.549 95.568 107.845 ;
     RECT  100.776 106.549 102.192 107.173 ;
     RECT  60.264 107.125 61.728 107.845 ;
     RECT  80.136 107.173 81.6 107.845 ;
  END
END ot_hgi_qdq_transport_ctl_r3
END LIBRARY
